VERSION 5.8 ;
BUSBITCHARS "[]" ;
DIVIDERCHAR "/" ;
UNITS
    DATABASE MICRONS 1000 ;
END UNITS

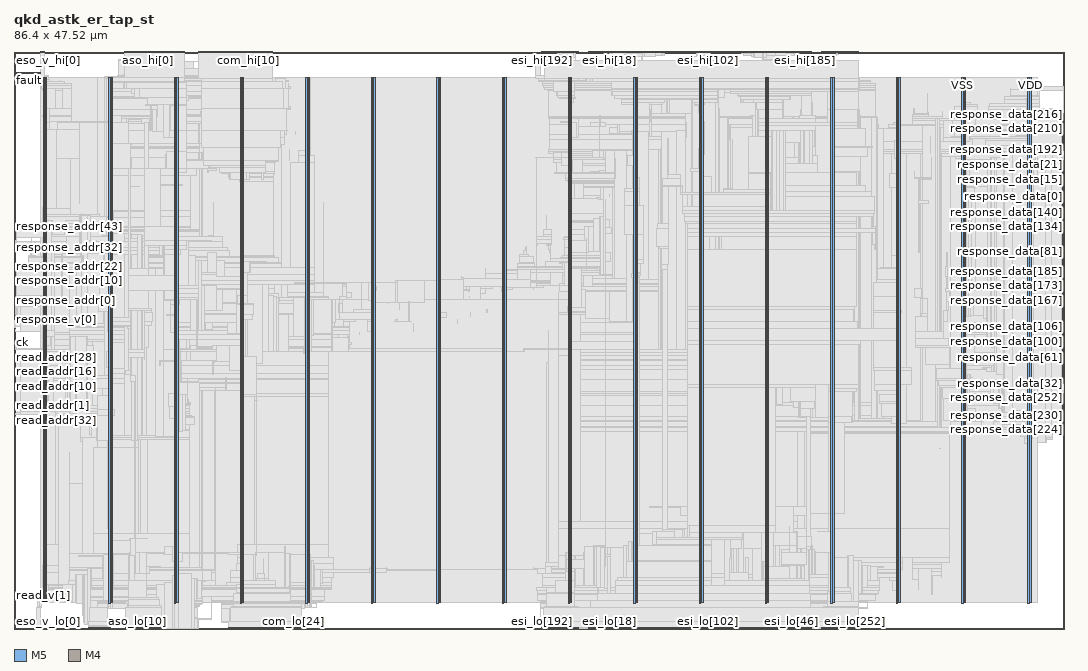
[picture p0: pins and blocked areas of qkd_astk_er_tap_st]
MACRO qkd_astk_er_tap_st
  FOREIGN qkd_astk_er_tap_st 0 0 ;
  CLASS BLOCK ;
  SIZE 86.4 BY 47.52 ;
  PIN aso_hi[0]
    DIRECTION OUTPUT ;
    USE SIGNAL ;
    PORT
      LAYER M5 ;
        RECT  10.992 47.436 11.016 47.52 ;
    END
  END aso_hi[0]
  PIN aso_hi[10]
    DIRECTION OUTPUT ;
    USE SIGNAL ;
    PORT
      LAYER M5 ;
        RECT  11.952 47.436 11.976 47.52 ;
    END
  END aso_hi[10]
  PIN aso_hi[11]
    DIRECTION OUTPUT ;
    USE SIGNAL ;
    PORT
      LAYER M5 ;
        RECT  12.048 47.436 12.072 47.52 ;
    END
  END aso_hi[11]
  PIN aso_hi[12]
    DIRECTION OUTPUT ;
    USE SIGNAL ;
    PORT
      LAYER M5 ;
        RECT  12.144 47.436 12.168 47.52 ;
    END
  END aso_hi[12]
  PIN aso_hi[13]
    DIRECTION OUTPUT ;
    USE SIGNAL ;
    PORT
      LAYER M5 ;
        RECT  12.24 47.436 12.264 47.52 ;
    END
  END aso_hi[13]
  PIN aso_hi[14]
    DIRECTION OUTPUT ;
    USE SIGNAL ;
    PORT
      LAYER M5 ;
        RECT  12.336 47.436 12.36 47.52 ;
    END
  END aso_hi[14]
  PIN aso_hi[15]
    DIRECTION OUTPUT ;
    USE SIGNAL ;
    PORT
      LAYER M5 ;
        RECT  12.432 47.436 12.456 47.52 ;
    END
  END aso_hi[15]
  PIN aso_hi[16]
    DIRECTION OUTPUT ;
    USE SIGNAL ;
    PORT
      LAYER M5 ;
        RECT  12.528 47.436 12.552 47.52 ;
    END
  END aso_hi[16]
  PIN aso_hi[17]
    DIRECTION OUTPUT ;
    USE SIGNAL ;
    PORT
      LAYER M5 ;
        RECT  12.624 47.436 12.648 47.52 ;
    END
  END aso_hi[17]
  PIN aso_hi[18]
    DIRECTION OUTPUT ;
    USE SIGNAL ;
    PORT
      LAYER M5 ;
        RECT  12.72 47.436 12.744 47.52 ;
    END
  END aso_hi[18]
  PIN aso_hi[19]
    DIRECTION OUTPUT ;
    USE SIGNAL ;
    PORT
      LAYER M5 ;
        RECT  12.816 47.436 12.84 47.52 ;
    END
  END aso_hi[19]
  PIN aso_hi[1]
    DIRECTION OUTPUT ;
    USE SIGNAL ;
    PORT
      LAYER M5 ;
        RECT  11.088 47.436 11.112 47.52 ;
    END
  END aso_hi[1]
  PIN aso_hi[20]
    DIRECTION OUTPUT ;
    USE SIGNAL ;
    PORT
      LAYER M5 ;
        RECT  12.912 47.436 12.936 47.52 ;
    END
  END aso_hi[20]
  PIN aso_hi[21]
    DIRECTION OUTPUT ;
    USE SIGNAL ;
    PORT
      LAYER M5 ;
        RECT  13.008 47.436 13.032 47.52 ;
    END
  END aso_hi[21]
  PIN aso_hi[22]
    DIRECTION OUTPUT ;
    USE SIGNAL ;
    PORT
      LAYER M5 ;
        RECT  13.104 47.436 13.128 47.52 ;
    END
  END aso_hi[22]
  PIN aso_hi[23]
    DIRECTION OUTPUT ;
    USE SIGNAL ;
    PORT
      LAYER M5 ;
        RECT  13.2 47.436 13.224 47.52 ;
    END
  END aso_hi[23]
  PIN aso_hi[24]
    DIRECTION OUTPUT ;
    USE SIGNAL ;
    PORT
      LAYER M5 ;
        RECT  13.296 47.436 13.32 47.52 ;
    END
  END aso_hi[24]
  PIN aso_hi[25]
    DIRECTION OUTPUT ;
    USE SIGNAL ;
    PORT
      LAYER M5 ;
        RECT  13.392 47.436 13.416 47.52 ;
    END
  END aso_hi[25]
  PIN aso_hi[26]
    DIRECTION OUTPUT ;
    USE SIGNAL ;
    PORT
      LAYER M5 ;
        RECT  13.488 47.436 13.512 47.52 ;
    END
  END aso_hi[26]
  PIN aso_hi[27]
    DIRECTION OUTPUT ;
    USE SIGNAL ;
    PORT
      LAYER M5 ;
        RECT  13.584 47.436 13.608 47.52 ;
    END
  END aso_hi[27]
  PIN aso_hi[28]
    DIRECTION OUTPUT ;
    USE SIGNAL ;
    PORT
      LAYER M5 ;
        RECT  13.68 47.436 13.704 47.52 ;
    END
  END aso_hi[28]
  PIN aso_hi[29]
    DIRECTION OUTPUT ;
    USE SIGNAL ;
    PORT
      LAYER M5 ;
        RECT  13.776 47.436 13.8 47.52 ;
    END
  END aso_hi[29]
  PIN aso_hi[2]
    DIRECTION OUTPUT ;
    USE SIGNAL ;
    PORT
      LAYER M5 ;
        RECT  11.184 47.436 11.208 47.52 ;
    END
  END aso_hi[2]
  PIN aso_hi[30]
    DIRECTION OUTPUT ;
    USE SIGNAL ;
    PORT
      LAYER M5 ;
        RECT  13.872 47.436 13.896 47.52 ;
    END
  END aso_hi[30]
  PIN aso_hi[31]
    DIRECTION OUTPUT ;
    USE SIGNAL ;
    PORT
      LAYER M5 ;
        RECT  13.968 47.436 13.992 47.52 ;
    END
  END aso_hi[31]
  PIN aso_hi[32]
    DIRECTION OUTPUT ;
    USE SIGNAL ;
    PORT
      LAYER M5 ;
        RECT  9.072 47.436 9.096 47.52 ;
    END
  END aso_hi[32]
  PIN aso_hi[33]
    DIRECTION OUTPUT ;
    USE SIGNAL ;
    PORT
      LAYER M5 ;
        RECT  9.168 47.436 9.192 47.52 ;
    END
  END aso_hi[33]
  PIN aso_hi[34]
    DIRECTION OUTPUT ;
    USE SIGNAL ;
    PORT
      LAYER M5 ;
        RECT  9.264 47.436 9.288 47.52 ;
    END
  END aso_hi[34]
  PIN aso_hi[35]
    DIRECTION OUTPUT ;
    USE SIGNAL ;
    PORT
      LAYER M5 ;
        RECT  9.36 47.436 9.384 47.52 ;
    END
  END aso_hi[35]
  PIN aso_hi[36]
    DIRECTION OUTPUT ;
    USE SIGNAL ;
    PORT
      LAYER M5 ;
        RECT  9.456 47.436 9.48 47.52 ;
    END
  END aso_hi[36]
  PIN aso_hi[37]
    DIRECTION OUTPUT ;
    USE SIGNAL ;
    PORT
      LAYER M5 ;
        RECT  9.552 47.436 9.576 47.52 ;
    END
  END aso_hi[37]
  PIN aso_hi[38]
    DIRECTION OUTPUT ;
    USE SIGNAL ;
    PORT
      LAYER M5 ;
        RECT  9.648 47.436 9.672 47.52 ;
    END
  END aso_hi[38]
  PIN aso_hi[39]
    DIRECTION OUTPUT ;
    USE SIGNAL ;
    PORT
      LAYER M5 ;
        RECT  9.744 47.436 9.768 47.52 ;
    END
  END aso_hi[39]
  PIN aso_hi[3]
    DIRECTION OUTPUT ;
    USE SIGNAL ;
    PORT
      LAYER M5 ;
        RECT  11.28 47.436 11.304 47.52 ;
    END
  END aso_hi[3]
  PIN aso_hi[40]
    DIRECTION OUTPUT ;
    USE SIGNAL ;
    PORT
      LAYER M5 ;
        RECT  9.84 47.436 9.864 47.52 ;
    END
  END aso_hi[40]
  PIN aso_hi[41]
    DIRECTION OUTPUT ;
    USE SIGNAL ;
    PORT
      LAYER M5 ;
        RECT  9.936 47.436 9.96 47.52 ;
    END
  END aso_hi[41]
  PIN aso_hi[42]
    DIRECTION OUTPUT ;
    USE SIGNAL ;
    PORT
      LAYER M5 ;
        RECT  10.032 47.436 10.056 47.52 ;
    END
  END aso_hi[42]
  PIN aso_hi[43]
    DIRECTION OUTPUT ;
    USE SIGNAL ;
    PORT
      LAYER M5 ;
        RECT  10.128 47.436 10.152 47.52 ;
    END
  END aso_hi[43]
  PIN aso_hi[44]
    DIRECTION OUTPUT ;
    USE SIGNAL ;
    PORT
      LAYER M5 ;
        RECT  10.224 47.436 10.248 47.52 ;
    END
  END aso_hi[44]
  PIN aso_hi[45]
    DIRECTION OUTPUT ;
    USE SIGNAL ;
    PORT
      LAYER M5 ;
        RECT  10.32 47.436 10.344 47.52 ;
    END
  END aso_hi[45]
  PIN aso_hi[46]
    DIRECTION OUTPUT ;
    USE SIGNAL ;
    PORT
      LAYER M5 ;
        RECT  10.416 47.436 10.44 47.52 ;
    END
  END aso_hi[46]
  PIN aso_hi[47]
    DIRECTION OUTPUT ;
    USE SIGNAL ;
    PORT
      LAYER M5 ;
        RECT  10.512 47.436 10.536 47.52 ;
    END
  END aso_hi[47]
  PIN aso_hi[48]
    DIRECTION OUTPUT ;
    USE SIGNAL ;
    PORT
      LAYER M5 ;
        RECT  10.608 47.436 10.632 47.52 ;
    END
  END aso_hi[48]
  PIN aso_hi[49]
    DIRECTION OUTPUT ;
    USE SIGNAL ;
    PORT
      LAYER M5 ;
        RECT  10.704 47.436 10.728 47.52 ;
    END
  END aso_hi[49]
  PIN aso_hi[4]
    DIRECTION OUTPUT ;
    USE SIGNAL ;
    PORT
      LAYER M5 ;
        RECT  11.376 47.436 11.4 47.52 ;
    END
  END aso_hi[4]
  PIN aso_hi[50]
    DIRECTION OUTPUT ;
    USE SIGNAL ;
    PORT
      LAYER M5 ;
        RECT  10.8 47.436 10.824 47.52 ;
    END
  END aso_hi[50]
  PIN aso_hi[51]
    DIRECTION OUTPUT ;
    USE SIGNAL ;
    PORT
      LAYER M5 ;
        RECT  10.896 47.436 10.92 47.52 ;
    END
  END aso_hi[51]
  PIN aso_hi[5]
    DIRECTION OUTPUT ;
    USE SIGNAL ;
    PORT
      LAYER M5 ;
        RECT  11.472 47.436 11.496 47.52 ;
    END
  END aso_hi[5]
  PIN aso_hi[6]
    DIRECTION OUTPUT ;
    USE SIGNAL ;
    PORT
      LAYER M5 ;
        RECT  11.568 47.436 11.592 47.52 ;
    END
  END aso_hi[6]
  PIN aso_hi[7]
    DIRECTION OUTPUT ;
    USE SIGNAL ;
    PORT
      LAYER M5 ;
        RECT  11.664 47.436 11.688 47.52 ;
    END
  END aso_hi[7]
  PIN aso_hi[8]
    DIRECTION OUTPUT ;
    USE SIGNAL ;
    PORT
      LAYER M5 ;
        RECT  11.76 47.436 11.784 47.52 ;
    END
  END aso_hi[8]
  PIN aso_hi[9]
    DIRECTION OUTPUT ;
    USE SIGNAL ;
    PORT
      LAYER M5 ;
        RECT  11.856 47.436 11.88 47.52 ;
    END
  END aso_hi[9]
  PIN aso_lo[0]
    DIRECTION OUTPUT ;
    USE SIGNAL ;
    PORT
      LAYER M5 ;
        RECT  9.168 0 9.192 0.084 ;
    END
  END aso_lo[0]
  PIN aso_lo[10]
    DIRECTION OUTPUT ;
    USE SIGNAL ;
    PORT
      LAYER M5 ;
        RECT  10.128 0 10.152 0.084 ;
    END
  END aso_lo[10]
  PIN aso_lo[11]
    DIRECTION OUTPUT ;
    USE SIGNAL ;
    PORT
      LAYER M5 ;
        RECT  10.224 0 10.248 0.084 ;
    END
  END aso_lo[11]
  PIN aso_lo[12]
    DIRECTION OUTPUT ;
    USE SIGNAL ;
    PORT
      LAYER M5 ;
        RECT  10.32 0 10.344 0.084 ;
    END
  END aso_lo[12]
  PIN aso_lo[13]
    DIRECTION OUTPUT ;
    USE SIGNAL ;
    PORT
      LAYER M5 ;
        RECT  10.416 0 10.44 0.084 ;
    END
  END aso_lo[13]
  PIN aso_lo[14]
    DIRECTION OUTPUT ;
    USE SIGNAL ;
    PORT
      LAYER M5 ;
        RECT  10.512 0 10.536 0.084 ;
    END
  END aso_lo[14]
  PIN aso_lo[15]
    DIRECTION OUTPUT ;
    USE SIGNAL ;
    PORT
      LAYER M5 ;
        RECT  10.608 0 10.632 0.084 ;
    END
  END aso_lo[15]
  PIN aso_lo[16]
    DIRECTION OUTPUT ;
    USE SIGNAL ;
    PORT
      LAYER M5 ;
        RECT  10.704 0 10.728 0.084 ;
    END
  END aso_lo[16]
  PIN aso_lo[17]
    DIRECTION OUTPUT ;
    USE SIGNAL ;
    PORT
      LAYER M5 ;
        RECT  10.8 0 10.824 0.084 ;
    END
  END aso_lo[17]
  PIN aso_lo[18]
    DIRECTION OUTPUT ;
    USE SIGNAL ;
    PORT
      LAYER M5 ;
        RECT  10.896 0 10.92 0.084 ;
    END
  END aso_lo[18]
  PIN aso_lo[19]
    DIRECTION OUTPUT ;
    USE SIGNAL ;
    PORT
      LAYER M5 ;
        RECT  10.992 0 11.016 0.084 ;
    END
  END aso_lo[19]
  PIN aso_lo[1]
    DIRECTION OUTPUT ;
    USE SIGNAL ;
    PORT
      LAYER M5 ;
        RECT  9.264 0 9.288 0.084 ;
    END
  END aso_lo[1]
  PIN aso_lo[20]
    DIRECTION OUTPUT ;
    USE SIGNAL ;
    PORT
      LAYER M5 ;
        RECT  11.088 0 11.112 0.084 ;
    END
  END aso_lo[20]
  PIN aso_lo[21]
    DIRECTION OUTPUT ;
    USE SIGNAL ;
    PORT
      LAYER M5 ;
        RECT  11.184 0 11.208 0.084 ;
    END
  END aso_lo[21]
  PIN aso_lo[22]
    DIRECTION OUTPUT ;
    USE SIGNAL ;
    PORT
      LAYER M5 ;
        RECT  11.28 0 11.304 0.084 ;
    END
  END aso_lo[22]
  PIN aso_lo[23]
    DIRECTION OUTPUT ;
    USE SIGNAL ;
    PORT
      LAYER M5 ;
        RECT  11.376 0 11.4 0.084 ;
    END
  END aso_lo[23]
  PIN aso_lo[24]
    DIRECTION OUTPUT ;
    USE SIGNAL ;
    PORT
      LAYER M5 ;
        RECT  11.472 0 11.496 0.084 ;
    END
  END aso_lo[24]
  PIN aso_lo[25]
    DIRECTION OUTPUT ;
    USE SIGNAL ;
    PORT
      LAYER M5 ;
        RECT  11.568 0 11.592 0.084 ;
    END
  END aso_lo[25]
  PIN aso_lo[26]
    DIRECTION OUTPUT ;
    USE SIGNAL ;
    PORT
      LAYER M5 ;
        RECT  11.664 0 11.688 0.084 ;
    END
  END aso_lo[26]
  PIN aso_lo[27]
    DIRECTION OUTPUT ;
    USE SIGNAL ;
    PORT
      LAYER M5 ;
        RECT  11.76 0 11.784 0.084 ;
    END
  END aso_lo[27]
  PIN aso_lo[28]
    DIRECTION OUTPUT ;
    USE SIGNAL ;
    PORT
      LAYER M5 ;
        RECT  11.856 0 11.88 0.084 ;
    END
  END aso_lo[28]
  PIN aso_lo[29]
    DIRECTION OUTPUT ;
    USE SIGNAL ;
    PORT
      LAYER M5 ;
        RECT  11.952 0 11.976 0.084 ;
    END
  END aso_lo[29]
  PIN aso_lo[2]
    DIRECTION OUTPUT ;
    USE SIGNAL ;
    PORT
      LAYER M5 ;
        RECT  9.36 0 9.384 0.084 ;
    END
  END aso_lo[2]
  PIN aso_lo[30]
    DIRECTION OUTPUT ;
    USE SIGNAL ;
    PORT
      LAYER M5 ;
        RECT  12.048 0 12.072 0.084 ;
    END
  END aso_lo[30]
  PIN aso_lo[31]
    DIRECTION OUTPUT ;
    USE SIGNAL ;
    PORT
      LAYER M5 ;
        RECT  12.144 0 12.168 0.084 ;
    END
  END aso_lo[31]
  PIN aso_lo[32]
    DIRECTION OUTPUT ;
    USE SIGNAL ;
    PORT
      LAYER M5 ;
        RECT  6.096 0 6.12 0.084 ;
    END
  END aso_lo[32]
  PIN aso_lo[33]
    DIRECTION OUTPUT ;
    USE SIGNAL ;
    PORT
      LAYER M5 ;
        RECT  6.192 0 6.216 0.084 ;
    END
  END aso_lo[33]
  PIN aso_lo[34]
    DIRECTION OUTPUT ;
    USE SIGNAL ;
    PORT
      LAYER M5 ;
        RECT  6.288 0 6.312 0.084 ;
    END
  END aso_lo[34]
  PIN aso_lo[35]
    DIRECTION OUTPUT ;
    USE SIGNAL ;
    PORT
      LAYER M5 ;
        RECT  6.384 0 6.408 0.084 ;
    END
  END aso_lo[35]
  PIN aso_lo[36]
    DIRECTION OUTPUT ;
    USE SIGNAL ;
    PORT
      LAYER M5 ;
        RECT  6.48 0 6.504 0.084 ;
    END
  END aso_lo[36]
  PIN aso_lo[37]
    DIRECTION OUTPUT ;
    USE SIGNAL ;
    PORT
      LAYER M5 ;
        RECT  6.576 0 6.6 0.084 ;
    END
  END aso_lo[37]
  PIN aso_lo[38]
    DIRECTION OUTPUT ;
    USE SIGNAL ;
    PORT
      LAYER M5 ;
        RECT  6.672 0 6.696 0.084 ;
    END
  END aso_lo[38]
  PIN aso_lo[39]
    DIRECTION OUTPUT ;
    USE SIGNAL ;
    PORT
      LAYER M5 ;
        RECT  6.768 0 6.792 0.084 ;
    END
  END aso_lo[39]
  PIN aso_lo[3]
    DIRECTION OUTPUT ;
    USE SIGNAL ;
    PORT
      LAYER M5 ;
        RECT  9.456 0 9.48 0.084 ;
    END
  END aso_lo[3]
  PIN aso_lo[40]
    DIRECTION OUTPUT ;
    USE SIGNAL ;
    PORT
      LAYER M5 ;
        RECT  6.864 0 6.888 0.084 ;
    END
  END aso_lo[40]
  PIN aso_lo[41]
    DIRECTION OUTPUT ;
    USE SIGNAL ;
    PORT
      LAYER M5 ;
        RECT  6.96 0 6.984 0.084 ;
    END
  END aso_lo[41]
  PIN aso_lo[42]
    DIRECTION OUTPUT ;
    USE SIGNAL ;
    PORT
      LAYER M5 ;
        RECT  7.056 0 7.08 0.084 ;
    END
  END aso_lo[42]
  PIN aso_lo[43]
    DIRECTION OUTPUT ;
    USE SIGNAL ;
    PORT
      LAYER M5 ;
        RECT  7.152 0 7.176 0.084 ;
    END
  END aso_lo[43]
  PIN aso_lo[44]
    DIRECTION OUTPUT ;
    USE SIGNAL ;
    PORT
      LAYER M5 ;
        RECT  7.248 0 7.272 0.084 ;
    END
  END aso_lo[44]
  PIN aso_lo[45]
    DIRECTION OUTPUT ;
    USE SIGNAL ;
    PORT
      LAYER M5 ;
        RECT  7.344 0 7.368 0.084 ;
    END
  END aso_lo[45]
  PIN aso_lo[46]
    DIRECTION OUTPUT ;
    USE SIGNAL ;
    PORT
      LAYER M5 ;
        RECT  7.44 0 7.464 0.084 ;
    END
  END aso_lo[46]
  PIN aso_lo[47]
    DIRECTION OUTPUT ;
    USE SIGNAL ;
    PORT
      LAYER M5 ;
        RECT  7.536 0 7.56 0.084 ;
    END
  END aso_lo[47]
  PIN aso_lo[48]
    DIRECTION OUTPUT ;
    USE SIGNAL ;
    PORT
      LAYER M5 ;
        RECT  7.632 0 7.656 0.084 ;
    END
  END aso_lo[48]
  PIN aso_lo[49]
    DIRECTION OUTPUT ;
    USE SIGNAL ;
    PORT
      LAYER M5 ;
        RECT  7.728 0 7.752 0.084 ;
    END
  END aso_lo[49]
  PIN aso_lo[4]
    DIRECTION OUTPUT ;
    USE SIGNAL ;
    PORT
      LAYER M5 ;
        RECT  9.552 0 9.576 0.084 ;
    END
  END aso_lo[4]
  PIN aso_lo[50]
    DIRECTION OUTPUT ;
    USE SIGNAL ;
    PORT
      LAYER M5 ;
        RECT  7.824 0 7.848 0.084 ;
    END
  END aso_lo[50]
  PIN aso_lo[51]
    DIRECTION OUTPUT ;
    USE SIGNAL ;
    PORT
      LAYER M5 ;
        RECT  7.92 0 7.944 0.084 ;
    END
  END aso_lo[51]
  PIN aso_lo[5]
    DIRECTION OUTPUT ;
    USE SIGNAL ;
    PORT
      LAYER M5 ;
        RECT  9.648 0 9.672 0.084 ;
    END
  END aso_lo[5]
  PIN aso_lo[6]
    DIRECTION OUTPUT ;
    USE SIGNAL ;
    PORT
      LAYER M5 ;
        RECT  9.744 0 9.768 0.084 ;
    END
  END aso_lo[6]
  PIN aso_lo[7]
    DIRECTION OUTPUT ;
    USE SIGNAL ;
    PORT
      LAYER M5 ;
        RECT  9.84 0 9.864 0.084 ;
    END
  END aso_lo[7]
  PIN aso_lo[8]
    DIRECTION OUTPUT ;
    USE SIGNAL ;
    PORT
      LAYER M5 ;
        RECT  9.936 0 9.96 0.084 ;
    END
  END aso_lo[8]
  PIN aso_lo[9]
    DIRECTION OUTPUT ;
    USE SIGNAL ;
    PORT
      LAYER M5 ;
        RECT  10.032 0 10.056 0.084 ;
    END
  END aso_lo[9]
  PIN ck
    DIRECTION INPUT ;
    USE SIGNAL ;
    PORT
      LAYER M4 ;
        RECT  0 23.568 0.084 23.592 ;
    END
    PORT
      LAYER M4 ;
        RECT  0.06 23.568 0.133 23.592 ;
    END
  END ck
  PIN com_hi[0]
    DIRECTION INPUT ;
    USE SIGNAL ;
    PORT
      LAYER M5 ;
        RECT  18.288 47.436 18.312 47.52 ;
    END
  END com_hi[0]
  PIN com_hi[10]
    DIRECTION INPUT ;
    USE SIGNAL ;
    PORT
      LAYER M5 ;
        RECT  19.248 47.436 19.272 47.52 ;
    END
  END com_hi[10]
  PIN com_hi[11]
    DIRECTION INPUT ;
    USE SIGNAL ;
    PORT
      LAYER M5 ;
        RECT  19.344 47.436 19.368 47.52 ;
    END
  END com_hi[11]
  PIN com_hi[12]
    DIRECTION INPUT ;
    USE SIGNAL ;
    PORT
      LAYER M5 ;
        RECT  19.44 47.436 19.464 47.52 ;
    END
  END com_hi[12]
  PIN com_hi[13]
    DIRECTION INPUT ;
    USE SIGNAL ;
    PORT
      LAYER M5 ;
        RECT  19.536 47.436 19.56 47.52 ;
    END
  END com_hi[13]
  PIN com_hi[14]
    DIRECTION INPUT ;
    USE SIGNAL ;
    PORT
      LAYER M5 ;
        RECT  19.632 47.436 19.656 47.52 ;
    END
  END com_hi[14]
  PIN com_hi[15]
    DIRECTION INPUT ;
    USE SIGNAL ;
    PORT
      LAYER M5 ;
        RECT  19.728 47.436 19.752 47.52 ;
    END
  END com_hi[15]
  PIN com_hi[16]
    DIRECTION INPUT ;
    USE SIGNAL ;
    PORT
      LAYER M5 ;
        RECT  19.824 47.436 19.848 47.52 ;
    END
  END com_hi[16]
  PIN com_hi[17]
    DIRECTION INPUT ;
    USE SIGNAL ;
    PORT
      LAYER M5 ;
        RECT  19.92 47.436 19.944 47.52 ;
    END
  END com_hi[17]
  PIN com_hi[18]
    DIRECTION INPUT ;
    USE SIGNAL ;
    PORT
      LAYER M5 ;
        RECT  20.016 47.436 20.04 47.52 ;
    END
  END com_hi[18]
  PIN com_hi[19]
    DIRECTION INPUT ;
    USE SIGNAL ;
    PORT
      LAYER M5 ;
        RECT  20.112 47.436 20.136 47.52 ;
    END
  END com_hi[19]
  PIN com_hi[1]
    DIRECTION INPUT ;
    USE SIGNAL ;
    PORT
      LAYER M5 ;
        RECT  18.384 47.436 18.408 47.52 ;
    END
  END com_hi[1]
  PIN com_hi[20]
    DIRECTION INPUT ;
    USE SIGNAL ;
    PORT
      LAYER M5 ;
        RECT  20.208 47.436 20.232 47.52 ;
    END
  END com_hi[20]
  PIN com_hi[21]
    DIRECTION INPUT ;
    USE SIGNAL ;
    PORT
      LAYER M5 ;
        RECT  20.304 47.436 20.328 47.52 ;
    END
  END com_hi[21]
  PIN com_hi[22]
    DIRECTION INPUT ;
    USE SIGNAL ;
    PORT
      LAYER M5 ;
        RECT  20.4 47.436 20.424 47.52 ;
    END
  END com_hi[22]
  PIN com_hi[23]
    DIRECTION INPUT ;
    USE SIGNAL ;
    PORT
      LAYER M5 ;
        RECT  20.496 47.436 20.52 47.52 ;
    END
  END com_hi[23]
  PIN com_hi[24]
    DIRECTION INPUT ;
    USE SIGNAL ;
    PORT
      LAYER M5 ;
        RECT  20.592 47.436 20.616 47.52 ;
    END
  END com_hi[24]
  PIN com_hi[25]
    DIRECTION INPUT ;
    USE SIGNAL ;
    PORT
      LAYER M5 ;
        RECT  20.688 47.436 20.712 47.52 ;
    END
  END com_hi[25]
  PIN com_hi[26]
    DIRECTION INPUT ;
    USE SIGNAL ;
    PORT
      LAYER M5 ;
        RECT  20.784 47.436 20.808 47.52 ;
    END
  END com_hi[26]
  PIN com_hi[27]
    DIRECTION INPUT ;
    USE SIGNAL ;
    PORT
      LAYER M5 ;
        RECT  20.88 47.436 20.904 47.52 ;
    END
  END com_hi[27]
  PIN com_hi[28]
    DIRECTION INPUT ;
    USE SIGNAL ;
    PORT
      LAYER M5 ;
        RECT  20.976 47.436 21 47.52 ;
    END
  END com_hi[28]
  PIN com_hi[29]
    DIRECTION INPUT ;
    USE SIGNAL ;
    PORT
      LAYER M5 ;
        RECT  21.072 47.436 21.096 47.52 ;
    END
  END com_hi[29]
  PIN com_hi[2]
    DIRECTION INPUT ;
    USE SIGNAL ;
    PORT
      LAYER M5 ;
        RECT  18.48 47.436 18.504 47.52 ;
    END
  END com_hi[2]
  PIN com_hi[30]
    DIRECTION INPUT ;
    USE SIGNAL ;
    PORT
      LAYER M5 ;
        RECT  21.168 47.436 21.192 47.52 ;
    END
  END com_hi[30]
  PIN com_hi[31]
    DIRECTION INPUT ;
    USE SIGNAL ;
    PORT
      LAYER M5 ;
        RECT  21.264 47.436 21.288 47.52 ;
    END
  END com_hi[31]
  PIN com_hi[32]
    DIRECTION INPUT ;
    USE SIGNAL ;
    PORT
      LAYER M5 ;
        RECT  15.216 47.436 15.24 47.52 ;
    END
  END com_hi[32]
  PIN com_hi[33]
    DIRECTION INPUT ;
    USE SIGNAL ;
    PORT
      LAYER M5 ;
        RECT  15.312 47.436 15.336 47.52 ;
    END
  END com_hi[33]
  PIN com_hi[34]
    DIRECTION INPUT ;
    USE SIGNAL ;
    PORT
      LAYER M5 ;
        RECT  15.408 47.436 15.432 47.52 ;
    END
  END com_hi[34]
  PIN com_hi[35]
    DIRECTION INPUT ;
    USE SIGNAL ;
    PORT
      LAYER M5 ;
        RECT  15.504 47.436 15.528 47.52 ;
    END
  END com_hi[35]
  PIN com_hi[36]
    DIRECTION INPUT ;
    USE SIGNAL ;
    PORT
      LAYER M5 ;
        RECT  15.6 47.436 15.624 47.52 ;
    END
  END com_hi[36]
  PIN com_hi[37]
    DIRECTION INPUT ;
    USE SIGNAL ;
    PORT
      LAYER M5 ;
        RECT  15.696 47.436 15.72 47.52 ;
    END
  END com_hi[37]
  PIN com_hi[38]
    DIRECTION INPUT ;
    USE SIGNAL ;
    PORT
      LAYER M5 ;
        RECT  15.792 47.436 15.816 47.52 ;
    END
  END com_hi[38]
  PIN com_hi[39]
    DIRECTION INPUT ;
    USE SIGNAL ;
    PORT
      LAYER M5 ;
        RECT  15.888 47.436 15.912 47.52 ;
    END
  END com_hi[39]
  PIN com_hi[3]
    DIRECTION INPUT ;
    USE SIGNAL ;
    PORT
      LAYER M5 ;
        RECT  18.576 47.436 18.6 47.52 ;
    END
  END com_hi[3]
  PIN com_hi[40]
    DIRECTION INPUT ;
    USE SIGNAL ;
    PORT
      LAYER M5 ;
        RECT  15.984 47.436 16.008 47.52 ;
    END
  END com_hi[40]
  PIN com_hi[41]
    DIRECTION INPUT ;
    USE SIGNAL ;
    PORT
      LAYER M5 ;
        RECT  16.08 47.436 16.104 47.52 ;
    END
  END com_hi[41]
  PIN com_hi[42]
    DIRECTION INPUT ;
    USE SIGNAL ;
    PORT
      LAYER M5 ;
        RECT  16.176 47.436 16.2 47.52 ;
    END
  END com_hi[42]
  PIN com_hi[43]
    DIRECTION INPUT ;
    USE SIGNAL ;
    PORT
      LAYER M5 ;
        RECT  16.272 47.436 16.296 47.52 ;
    END
  END com_hi[43]
  PIN com_hi[44]
    DIRECTION INPUT ;
    USE SIGNAL ;
    PORT
      LAYER M5 ;
        RECT  16.368 47.436 16.392 47.52 ;
    END
  END com_hi[44]
  PIN com_hi[45]
    DIRECTION INPUT ;
    USE SIGNAL ;
    PORT
      LAYER M5 ;
        RECT  16.464 47.436 16.488 47.52 ;
    END
  END com_hi[45]
  PIN com_hi[46]
    DIRECTION INPUT ;
    USE SIGNAL ;
    PORT
      LAYER M5 ;
        RECT  16.56 47.436 16.584 47.52 ;
    END
  END com_hi[46]
  PIN com_hi[47]
    DIRECTION INPUT ;
    USE SIGNAL ;
    PORT
      LAYER M5 ;
        RECT  16.656 47.436 16.68 47.52 ;
    END
  END com_hi[47]
  PIN com_hi[48]
    DIRECTION INPUT ;
    USE SIGNAL ;
    PORT
      LAYER M5 ;
        RECT  16.752 47.436 16.776 47.52 ;
    END
  END com_hi[48]
  PIN com_hi[49]
    DIRECTION INPUT ;
    USE SIGNAL ;
    PORT
      LAYER M5 ;
        RECT  16.848 47.436 16.872 47.52 ;
    END
  END com_hi[49]
  PIN com_hi[4]
    DIRECTION INPUT ;
    USE SIGNAL ;
    PORT
      LAYER M5 ;
        RECT  18.672 47.436 18.696 47.52 ;
    END
  END com_hi[4]
  PIN com_hi[50]
    DIRECTION INPUT ;
    USE SIGNAL ;
    PORT
      LAYER M5 ;
        RECT  16.944 47.436 16.968 47.52 ;
    END
  END com_hi[50]
  PIN com_hi[51]
    DIRECTION INPUT ;
    USE SIGNAL ;
    PORT
      LAYER M5 ;
        RECT  17.04 47.436 17.064 47.52 ;
    END
  END com_hi[51]
  PIN com_hi[52]
    DIRECTION INPUT ;
    USE SIGNAL ;
    PORT
      LAYER M5 ;
        RECT  17.136 47.436 17.16 47.52 ;
    END
  END com_hi[52]
  PIN com_hi[53]
    DIRECTION INPUT ;
    USE SIGNAL ;
    PORT
      LAYER M5 ;
        RECT  17.232 47.436 17.256 47.52 ;
    END
  END com_hi[53]
  PIN com_hi[54]
    DIRECTION INPUT ;
    USE SIGNAL ;
    PORT
      LAYER M5 ;
        RECT  17.328 47.436 17.352 47.52 ;
    END
  END com_hi[54]
  PIN com_hi[55]
    DIRECTION INPUT ;
    USE SIGNAL ;
    PORT
      LAYER M5 ;
        RECT  17.424 47.436 17.448 47.52 ;
    END
  END com_hi[55]
  PIN com_hi[56]
    DIRECTION INPUT ;
    USE SIGNAL ;
    PORT
      LAYER M5 ;
        RECT  17.52 47.436 17.544 47.52 ;
    END
  END com_hi[56]
  PIN com_hi[57]
    DIRECTION INPUT ;
    USE SIGNAL ;
    PORT
      LAYER M5 ;
        RECT  17.616 47.436 17.64 47.52 ;
    END
  END com_hi[57]
  PIN com_hi[58]
    DIRECTION INPUT ;
    USE SIGNAL ;
    PORT
      LAYER M5 ;
        RECT  17.712 47.436 17.736 47.52 ;
    END
  END com_hi[58]
  PIN com_hi[59]
    DIRECTION INPUT ;
    USE SIGNAL ;
    PORT
      LAYER M5 ;
        RECT  17.808 47.436 17.832 47.52 ;
    END
  END com_hi[59]
  PIN com_hi[5]
    DIRECTION INPUT ;
    USE SIGNAL ;
    PORT
      LAYER M5 ;
        RECT  18.768 47.436 18.792 47.52 ;
    END
  END com_hi[5]
  PIN com_hi[60]
    DIRECTION INPUT ;
    USE SIGNAL ;
    PORT
      LAYER M5 ;
        RECT  17.904 47.436 17.928 47.52 ;
    END
  END com_hi[60]
  PIN com_hi[61]
    DIRECTION INPUT ;
    USE SIGNAL ;
    PORT
      LAYER M5 ;
        RECT  18 47.436 18.024 47.52 ;
    END
  END com_hi[61]
  PIN com_hi[62]
    DIRECTION INPUT ;
    USE SIGNAL ;
    PORT
      LAYER M5 ;
        RECT  18.096 47.436 18.12 47.52 ;
    END
  END com_hi[62]
  PIN com_hi[63]
    DIRECTION INPUT ;
    USE SIGNAL ;
    PORT
      LAYER M5 ;
        RECT  18.192 47.436 18.216 47.52 ;
    END
  END com_hi[63]
  PIN com_hi[6]
    DIRECTION INPUT ;
    USE SIGNAL ;
    PORT
      LAYER M5 ;
        RECT  18.864 47.436 18.888 47.52 ;
    END
  END com_hi[6]
  PIN com_hi[7]
    DIRECTION INPUT ;
    USE SIGNAL ;
    PORT
      LAYER M5 ;
        RECT  18.96 47.436 18.984 47.52 ;
    END
  END com_hi[7]
  PIN com_hi[8]
    DIRECTION INPUT ;
    USE SIGNAL ;
    PORT
      LAYER M5 ;
        RECT  19.056 47.436 19.08 47.52 ;
    END
  END com_hi[8]
  PIN com_hi[9]
    DIRECTION INPUT ;
    USE SIGNAL ;
    PORT
      LAYER M5 ;
        RECT  19.152 47.436 19.176 47.52 ;
    END
  END com_hi[9]
  PIN com_lo[0]
    DIRECTION INPUT ;
    USE SIGNAL ;
    PORT
      LAYER M5 ;
        RECT  20.688 0 20.712 0.084 ;
    END
  END com_lo[0]
  PIN com_lo[10]
    DIRECTION INPUT ;
    USE SIGNAL ;
    PORT
      LAYER M5 ;
        RECT  21.648 0 21.672 0.084 ;
    END
  END com_lo[10]
  PIN com_lo[11]
    DIRECTION INPUT ;
    USE SIGNAL ;
    PORT
      LAYER M5 ;
        RECT  21.744 0 21.768 0.084 ;
    END
  END com_lo[11]
  PIN com_lo[12]
    DIRECTION INPUT ;
    USE SIGNAL ;
    PORT
      LAYER M5 ;
        RECT  21.84 0 21.864 0.084 ;
    END
  END com_lo[12]
  PIN com_lo[13]
    DIRECTION INPUT ;
    USE SIGNAL ;
    PORT
      LAYER M5 ;
        RECT  21.936 0 21.96 0.084 ;
    END
  END com_lo[13]
  PIN com_lo[14]
    DIRECTION INPUT ;
    USE SIGNAL ;
    PORT
      LAYER M5 ;
        RECT  22.032 0 22.056 0.084 ;
    END
  END com_lo[14]
  PIN com_lo[15]
    DIRECTION INPUT ;
    USE SIGNAL ;
    PORT
      LAYER M5 ;
        RECT  22.128 0 22.152 0.084 ;
    END
  END com_lo[15]
  PIN com_lo[16]
    DIRECTION INPUT ;
    USE SIGNAL ;
    PORT
      LAYER M5 ;
        RECT  22.224 0 22.248 0.084 ;
    END
  END com_lo[16]
  PIN com_lo[17]
    DIRECTION INPUT ;
    USE SIGNAL ;
    PORT
      LAYER M5 ;
        RECT  22.32 0 22.344 0.084 ;
    END
  END com_lo[17]
  PIN com_lo[18]
    DIRECTION INPUT ;
    USE SIGNAL ;
    PORT
      LAYER M5 ;
        RECT  22.416 0 22.44 0.084 ;
    END
  END com_lo[18]
  PIN com_lo[19]
    DIRECTION INPUT ;
    USE SIGNAL ;
    PORT
      LAYER M5 ;
        RECT  22.512 0 22.536 0.084 ;
    END
  END com_lo[19]
  PIN com_lo[1]
    DIRECTION INPUT ;
    USE SIGNAL ;
    PORT
      LAYER M5 ;
        RECT  20.784 0 20.808 0.084 ;
    END
  END com_lo[1]
  PIN com_lo[20]
    DIRECTION INPUT ;
    USE SIGNAL ;
    PORT
      LAYER M5 ;
        RECT  22.608 0 22.632 0.084 ;
    END
  END com_lo[20]
  PIN com_lo[21]
    DIRECTION INPUT ;
    USE SIGNAL ;
    PORT
      LAYER M5 ;
        RECT  22.704 0 22.728 0.084 ;
    END
  END com_lo[21]
  PIN com_lo[22]
    DIRECTION INPUT ;
    USE SIGNAL ;
    PORT
      LAYER M5 ;
        RECT  22.8 0 22.824 0.084 ;
    END
  END com_lo[22]
  PIN com_lo[23]
    DIRECTION INPUT ;
    USE SIGNAL ;
    PORT
      LAYER M5 ;
        RECT  22.896 0 22.92 0.084 ;
    END
  END com_lo[23]
  PIN com_lo[24]
    DIRECTION INPUT ;
    USE SIGNAL ;
    PORT
      LAYER M5 ;
        RECT  22.992 0 23.016 0.084 ;
    END
  END com_lo[24]
  PIN com_lo[25]
    DIRECTION INPUT ;
    USE SIGNAL ;
    PORT
      LAYER M5 ;
        RECT  23.088 0 23.112 0.084 ;
    END
  END com_lo[25]
  PIN com_lo[26]
    DIRECTION INPUT ;
    USE SIGNAL ;
    PORT
      LAYER M5 ;
        RECT  23.184 0 23.208 0.084 ;
    END
  END com_lo[26]
  PIN com_lo[27]
    DIRECTION INPUT ;
    USE SIGNAL ;
    PORT
      LAYER M5 ;
        RECT  23.28 0 23.304 0.084 ;
    END
  END com_lo[27]
  PIN com_lo[28]
    DIRECTION INPUT ;
    USE SIGNAL ;
    PORT
      LAYER M5 ;
        RECT  23.376 0 23.4 0.084 ;
    END
  END com_lo[28]
  PIN com_lo[29]
    DIRECTION INPUT ;
    USE SIGNAL ;
    PORT
      LAYER M5 ;
        RECT  23.472 0 23.496 0.084 ;
    END
  END com_lo[29]
  PIN com_lo[2]
    DIRECTION INPUT ;
    USE SIGNAL ;
    PORT
      LAYER M5 ;
        RECT  20.88 0 20.904 0.084 ;
    END
  END com_lo[2]
  PIN com_lo[30]
    DIRECTION INPUT ;
    USE SIGNAL ;
    PORT
      LAYER M5 ;
        RECT  23.568 0 23.592 0.084 ;
    END
  END com_lo[30]
  PIN com_lo[31]
    DIRECTION INPUT ;
    USE SIGNAL ;
    PORT
      LAYER M5 ;
        RECT  23.664 0 23.688 0.084 ;
    END
  END com_lo[31]
  PIN com_lo[32]
    DIRECTION INPUT ;
    USE SIGNAL ;
    PORT
      LAYER M5 ;
        RECT  17.616 0 17.64 0.084 ;
    END
  END com_lo[32]
  PIN com_lo[33]
    DIRECTION INPUT ;
    USE SIGNAL ;
    PORT
      LAYER M5 ;
        RECT  17.712 0 17.736 0.084 ;
    END
  END com_lo[33]
  PIN com_lo[34]
    DIRECTION INPUT ;
    USE SIGNAL ;
    PORT
      LAYER M5 ;
        RECT  17.808 0 17.832 0.084 ;
    END
  END com_lo[34]
  PIN com_lo[35]
    DIRECTION INPUT ;
    USE SIGNAL ;
    PORT
      LAYER M5 ;
        RECT  17.904 0 17.928 0.084 ;
    END
  END com_lo[35]
  PIN com_lo[36]
    DIRECTION INPUT ;
    USE SIGNAL ;
    PORT
      LAYER M5 ;
        RECT  18 0 18.024 0.084 ;
    END
  END com_lo[36]
  PIN com_lo[37]
    DIRECTION INPUT ;
    USE SIGNAL ;
    PORT
      LAYER M5 ;
        RECT  18.096 0 18.12 0.084 ;
    END
  END com_lo[37]
  PIN com_lo[38]
    DIRECTION INPUT ;
    USE SIGNAL ;
    PORT
      LAYER M5 ;
        RECT  18.192 0 18.216 0.084 ;
    END
  END com_lo[38]
  PIN com_lo[39]
    DIRECTION INPUT ;
    USE SIGNAL ;
    PORT
      LAYER M5 ;
        RECT  18.288 0 18.312 0.084 ;
    END
  END com_lo[39]
  PIN com_lo[3]
    DIRECTION INPUT ;
    USE SIGNAL ;
    PORT
      LAYER M5 ;
        RECT  20.976 0 21 0.084 ;
    END
  END com_lo[3]
  PIN com_lo[40]
    DIRECTION INPUT ;
    USE SIGNAL ;
    PORT
      LAYER M5 ;
        RECT  18.384 0 18.408 0.084 ;
    END
  END com_lo[40]
  PIN com_lo[41]
    DIRECTION INPUT ;
    USE SIGNAL ;
    PORT
      LAYER M5 ;
        RECT  18.48 0 18.504 0.084 ;
    END
  END com_lo[41]
  PIN com_lo[42]
    DIRECTION INPUT ;
    USE SIGNAL ;
    PORT
      LAYER M5 ;
        RECT  18.576 0 18.6 0.084 ;
    END
  END com_lo[42]
  PIN com_lo[43]
    DIRECTION INPUT ;
    USE SIGNAL ;
    PORT
      LAYER M5 ;
        RECT  18.672 0 18.696 0.084 ;
    END
  END com_lo[43]
  PIN com_lo[44]
    DIRECTION INPUT ;
    USE SIGNAL ;
    PORT
      LAYER M5 ;
        RECT  18.768 0 18.792 0.084 ;
    END
  END com_lo[44]
  PIN com_lo[45]
    DIRECTION INPUT ;
    USE SIGNAL ;
    PORT
      LAYER M5 ;
        RECT  18.864 0 18.888 0.084 ;
    END
  END com_lo[45]
  PIN com_lo[46]
    DIRECTION INPUT ;
    USE SIGNAL ;
    PORT
      LAYER M5 ;
        RECT  18.96 0 18.984 0.084 ;
    END
  END com_lo[46]
  PIN com_lo[47]
    DIRECTION INPUT ;
    USE SIGNAL ;
    PORT
      LAYER M5 ;
        RECT  19.056 0 19.08 0.084 ;
    END
  END com_lo[47]
  PIN com_lo[48]
    DIRECTION INPUT ;
    USE SIGNAL ;
    PORT
      LAYER M5 ;
        RECT  19.152 0 19.176 0.084 ;
    END
  END com_lo[48]
  PIN com_lo[49]
    DIRECTION INPUT ;
    USE SIGNAL ;
    PORT
      LAYER M5 ;
        RECT  19.248 0 19.272 0.084 ;
    END
  END com_lo[49]
  PIN com_lo[4]
    DIRECTION INPUT ;
    USE SIGNAL ;
    PORT
      LAYER M5 ;
        RECT  21.072 0 21.096 0.084 ;
    END
  END com_lo[4]
  PIN com_lo[50]
    DIRECTION INPUT ;
    USE SIGNAL ;
    PORT
      LAYER M5 ;
        RECT  19.344 0 19.368 0.084 ;
    END
  END com_lo[50]
  PIN com_lo[51]
    DIRECTION INPUT ;
    USE SIGNAL ;
    PORT
      LAYER M5 ;
        RECT  19.44 0 19.464 0.084 ;
    END
  END com_lo[51]
  PIN com_lo[52]
    DIRECTION INPUT ;
    USE SIGNAL ;
    PORT
      LAYER M5 ;
        RECT  19.536 0 19.56 0.084 ;
    END
  END com_lo[52]
  PIN com_lo[53]
    DIRECTION INPUT ;
    USE SIGNAL ;
    PORT
      LAYER M5 ;
        RECT  19.632 0 19.656 0.084 ;
    END
  END com_lo[53]
  PIN com_lo[54]
    DIRECTION INPUT ;
    USE SIGNAL ;
    PORT
      LAYER M5 ;
        RECT  19.728 0 19.752 0.084 ;
    END
  END com_lo[54]
  PIN com_lo[55]
    DIRECTION INPUT ;
    USE SIGNAL ;
    PORT
      LAYER M5 ;
        RECT  19.824 0 19.848 0.084 ;
    END
  END com_lo[55]
  PIN com_lo[56]
    DIRECTION INPUT ;
    USE SIGNAL ;
    PORT
      LAYER M5 ;
        RECT  19.92 0 19.944 0.084 ;
    END
  END com_lo[56]
  PIN com_lo[57]
    DIRECTION INPUT ;
    USE SIGNAL ;
    PORT
      LAYER M5 ;
        RECT  20.016 0 20.04 0.084 ;
    END
  END com_lo[57]
  PIN com_lo[58]
    DIRECTION INPUT ;
    USE SIGNAL ;
    PORT
      LAYER M5 ;
        RECT  20.112 0 20.136 0.084 ;
    END
  END com_lo[58]
  PIN com_lo[59]
    DIRECTION INPUT ;
    USE SIGNAL ;
    PORT
      LAYER M5 ;
        RECT  20.208 0 20.232 0.084 ;
    END
  END com_lo[59]
  PIN com_lo[5]
    DIRECTION INPUT ;
    USE SIGNAL ;
    PORT
      LAYER M5 ;
        RECT  21.168 0 21.192 0.084 ;
    END
  END com_lo[5]
  PIN com_lo[60]
    DIRECTION INPUT ;
    USE SIGNAL ;
    PORT
      LAYER M5 ;
        RECT  20.304 0 20.328 0.084 ;
    END
  END com_lo[60]
  PIN com_lo[61]
    DIRECTION INPUT ;
    USE SIGNAL ;
    PORT
      LAYER M5 ;
        RECT  20.4 0 20.424 0.084 ;
    END
  END com_lo[61]
  PIN com_lo[62]
    DIRECTION INPUT ;
    USE SIGNAL ;
    PORT
      LAYER M5 ;
        RECT  20.496 0 20.52 0.084 ;
    END
  END com_lo[62]
  PIN com_lo[63]
    DIRECTION INPUT ;
    USE SIGNAL ;
    PORT
      LAYER M5 ;
        RECT  20.592 0 20.616 0.084 ;
    END
  END com_lo[63]
  PIN com_lo[6]
    DIRECTION INPUT ;
    USE SIGNAL ;
    PORT
      LAYER M5 ;
        RECT  21.264 0 21.288 0.084 ;
    END
  END com_lo[6]
  PIN com_lo[7]
    DIRECTION INPUT ;
    USE SIGNAL ;
    PORT
      LAYER M5 ;
        RECT  21.36 0 21.384 0.084 ;
    END
  END com_lo[7]
  PIN com_lo[8]
    DIRECTION INPUT ;
    USE SIGNAL ;
    PORT
      LAYER M5 ;
        RECT  21.456 0 21.48 0.084 ;
    END
  END com_lo[8]
  PIN com_lo[9]
    DIRECTION INPUT ;
    USE SIGNAL ;
    PORT
      LAYER M5 ;
        RECT  21.552 0 21.576 0.084 ;
    END
  END com_lo[9]
  PIN esi_hi[0]
    DIRECTION INPUT ;
    USE SIGNAL ;
    PORT
      LAYER M5 ;
        RECT  47.28 47.436 47.304 47.52 ;
    END
  END esi_hi[0]
  PIN esi_hi[100]
    DIRECTION INPUT ;
    USE SIGNAL ;
    PORT
      LAYER M5 ;
        RECT  56.88 47.436 56.904 47.52 ;
    END
  END esi_hi[100]
  PIN esi_hi[101]
    DIRECTION INPUT ;
    USE SIGNAL ;
    PORT
      LAYER M5 ;
        RECT  56.976 47.436 57 47.52 ;
    END
  END esi_hi[101]
  PIN esi_hi[102]
    DIRECTION INPUT ;
    USE SIGNAL ;
    PORT
      LAYER M5 ;
        RECT  57.072 47.436 57.096 47.52 ;
    END
  END esi_hi[102]
  PIN esi_hi[103]
    DIRECTION INPUT ;
    USE SIGNAL ;
    PORT
      LAYER M5 ;
        RECT  57.168 47.436 57.192 47.52 ;
    END
  END esi_hi[103]
  PIN esi_hi[104]
    DIRECTION INPUT ;
    USE SIGNAL ;
    PORT
      LAYER M5 ;
        RECT  57.264 47.436 57.288 47.52 ;
    END
  END esi_hi[104]
  PIN esi_hi[105]
    DIRECTION INPUT ;
    USE SIGNAL ;
    PORT
      LAYER M5 ;
        RECT  57.36 47.436 57.384 47.52 ;
    END
  END esi_hi[105]
  PIN esi_hi[106]
    DIRECTION INPUT ;
    USE SIGNAL ;
    PORT
      LAYER M5 ;
        RECT  57.456 47.436 57.48 47.52 ;
    END
  END esi_hi[106]
  PIN esi_hi[107]
    DIRECTION INPUT ;
    USE SIGNAL ;
    PORT
      LAYER M5 ;
        RECT  57.552 47.436 57.576 47.52 ;
    END
  END esi_hi[107]
  PIN esi_hi[108]
    DIRECTION INPUT ;
    USE SIGNAL ;
    PORT
      LAYER M5 ;
        RECT  57.648 47.436 57.672 47.52 ;
    END
  END esi_hi[108]
  PIN esi_hi[109]
    DIRECTION INPUT ;
    USE SIGNAL ;
    PORT
      LAYER M5 ;
        RECT  57.744 47.436 57.768 47.52 ;
    END
  END esi_hi[109]
  PIN esi_hi[10]
    DIRECTION INPUT ;
    USE SIGNAL ;
    PORT
      LAYER M5 ;
        RECT  48.24 47.436 48.264 47.52 ;
    END
  END esi_hi[10]
  PIN esi_hi[110]
    DIRECTION INPUT ;
    USE SIGNAL ;
    PORT
      LAYER M5 ;
        RECT  57.84 47.436 57.864 47.52 ;
    END
  END esi_hi[110]
  PIN esi_hi[111]
    DIRECTION INPUT ;
    USE SIGNAL ;
    PORT
      LAYER M5 ;
        RECT  57.936 47.436 57.96 47.52 ;
    END
  END esi_hi[111]
  PIN esi_hi[112]
    DIRECTION INPUT ;
    USE SIGNAL ;
    PORT
      LAYER M5 ;
        RECT  58.032 47.436 58.056 47.52 ;
    END
  END esi_hi[112]
  PIN esi_hi[113]
    DIRECTION INPUT ;
    USE SIGNAL ;
    PORT
      LAYER M5 ;
        RECT  58.128 47.436 58.152 47.52 ;
    END
  END esi_hi[113]
  PIN esi_hi[114]
    DIRECTION INPUT ;
    USE SIGNAL ;
    PORT
      LAYER M5 ;
        RECT  58.224 47.436 58.248 47.52 ;
    END
  END esi_hi[114]
  PIN esi_hi[115]
    DIRECTION INPUT ;
    USE SIGNAL ;
    PORT
      LAYER M5 ;
        RECT  58.32 47.436 58.344 47.52 ;
    END
  END esi_hi[115]
  PIN esi_hi[116]
    DIRECTION INPUT ;
    USE SIGNAL ;
    PORT
      LAYER M5 ;
        RECT  58.416 47.436 58.44 47.52 ;
    END
  END esi_hi[116]
  PIN esi_hi[117]
    DIRECTION INPUT ;
    USE SIGNAL ;
    PORT
      LAYER M5 ;
        RECT  58.512 47.436 58.536 47.52 ;
    END
  END esi_hi[117]
  PIN esi_hi[118]
    DIRECTION INPUT ;
    USE SIGNAL ;
    PORT
      LAYER M5 ;
        RECT  58.608 47.436 58.632 47.52 ;
    END
  END esi_hi[118]
  PIN esi_hi[119]
    DIRECTION INPUT ;
    USE SIGNAL ;
    PORT
      LAYER M5 ;
        RECT  58.704 47.436 58.728 47.52 ;
    END
  END esi_hi[119]
  PIN esi_hi[11]
    DIRECTION INPUT ;
    USE SIGNAL ;
    PORT
      LAYER M5 ;
        RECT  48.336 47.436 48.36 47.52 ;
    END
  END esi_hi[11]
  PIN esi_hi[120]
    DIRECTION INPUT ;
    USE SIGNAL ;
    PORT
      LAYER M5 ;
        RECT  58.8 47.436 58.824 47.52 ;
    END
  END esi_hi[120]
  PIN esi_hi[121]
    DIRECTION INPUT ;
    USE SIGNAL ;
    PORT
      LAYER M5 ;
        RECT  58.896 47.436 58.92 47.52 ;
    END
  END esi_hi[121]
  PIN esi_hi[122]
    DIRECTION INPUT ;
    USE SIGNAL ;
    PORT
      LAYER M5 ;
        RECT  58.992 47.436 59.016 47.52 ;
    END
  END esi_hi[122]
  PIN esi_hi[123]
    DIRECTION INPUT ;
    USE SIGNAL ;
    PORT
      LAYER M5 ;
        RECT  59.088 47.436 59.112 47.52 ;
    END
  END esi_hi[123]
  PIN esi_hi[124]
    DIRECTION INPUT ;
    USE SIGNAL ;
    PORT
      LAYER M5 ;
        RECT  59.184 47.436 59.208 47.52 ;
    END
  END esi_hi[124]
  PIN esi_hi[125]
    DIRECTION INPUT ;
    USE SIGNAL ;
    PORT
      LAYER M5 ;
        RECT  59.28 47.436 59.304 47.52 ;
    END
  END esi_hi[125]
  PIN esi_hi[126]
    DIRECTION INPUT ;
    USE SIGNAL ;
    PORT
      LAYER M5 ;
        RECT  59.376 47.436 59.4 47.52 ;
    END
  END esi_hi[126]
  PIN esi_hi[127]
    DIRECTION INPUT ;
    USE SIGNAL ;
    PORT
      LAYER M5 ;
        RECT  59.472 47.436 59.496 47.52 ;
    END
  END esi_hi[127]
  PIN esi_hi[128]
    DIRECTION INPUT ;
    USE SIGNAL ;
    PORT
      LAYER M5 ;
        RECT  53.424 47.436 53.448 47.52 ;
    END
  END esi_hi[128]
  PIN esi_hi[129]
    DIRECTION INPUT ;
    USE SIGNAL ;
    PORT
      LAYER M5 ;
        RECT  53.52 47.436 53.544 47.52 ;
    END
  END esi_hi[129]
  PIN esi_hi[12]
    DIRECTION INPUT ;
    USE SIGNAL ;
    PORT
      LAYER M5 ;
        RECT  48.432 47.436 48.456 47.52 ;
    END
  END esi_hi[12]
  PIN esi_hi[130]
    DIRECTION INPUT ;
    USE SIGNAL ;
    PORT
      LAYER M5 ;
        RECT  53.616 47.436 53.64 47.52 ;
    END
  END esi_hi[130]
  PIN esi_hi[131]
    DIRECTION INPUT ;
    USE SIGNAL ;
    PORT
      LAYER M5 ;
        RECT  53.712 47.436 53.736 47.52 ;
    END
  END esi_hi[131]
  PIN esi_hi[132]
    DIRECTION INPUT ;
    USE SIGNAL ;
    PORT
      LAYER M5 ;
        RECT  53.808 47.436 53.832 47.52 ;
    END
  END esi_hi[132]
  PIN esi_hi[133]
    DIRECTION INPUT ;
    USE SIGNAL ;
    PORT
      LAYER M5 ;
        RECT  53.904 47.436 53.928 47.52 ;
    END
  END esi_hi[133]
  PIN esi_hi[134]
    DIRECTION INPUT ;
    USE SIGNAL ;
    PORT
      LAYER M5 ;
        RECT  54 47.436 54.024 47.52 ;
    END
  END esi_hi[134]
  PIN esi_hi[135]
    DIRECTION INPUT ;
    USE SIGNAL ;
    PORT
      LAYER M5 ;
        RECT  54.096 47.436 54.12 47.52 ;
    END
  END esi_hi[135]
  PIN esi_hi[136]
    DIRECTION INPUT ;
    USE SIGNAL ;
    PORT
      LAYER M5 ;
        RECT  54.192 47.436 54.216 47.52 ;
    END
  END esi_hi[136]
  PIN esi_hi[137]
    DIRECTION INPUT ;
    USE SIGNAL ;
    PORT
      LAYER M5 ;
        RECT  54.288 47.436 54.312 47.52 ;
    END
  END esi_hi[137]
  PIN esi_hi[138]
    DIRECTION INPUT ;
    USE SIGNAL ;
    PORT
      LAYER M5 ;
        RECT  54.384 47.436 54.408 47.52 ;
    END
  END esi_hi[138]
  PIN esi_hi[139]
    DIRECTION INPUT ;
    USE SIGNAL ;
    PORT
      LAYER M5 ;
        RECT  54.48 47.436 54.504 47.52 ;
    END
  END esi_hi[139]
  PIN esi_hi[13]
    DIRECTION INPUT ;
    USE SIGNAL ;
    PORT
      LAYER M5 ;
        RECT  48.528 47.436 48.552 47.52 ;
    END
  END esi_hi[13]
  PIN esi_hi[140]
    DIRECTION INPUT ;
    USE SIGNAL ;
    PORT
      LAYER M5 ;
        RECT  54.576 47.436 54.6 47.52 ;
    END
  END esi_hi[140]
  PIN esi_hi[141]
    DIRECTION INPUT ;
    USE SIGNAL ;
    PORT
      LAYER M5 ;
        RECT  54.672 47.436 54.696 47.52 ;
    END
  END esi_hi[141]
  PIN esi_hi[142]
    DIRECTION INPUT ;
    USE SIGNAL ;
    PORT
      LAYER M5 ;
        RECT  54.768 47.436 54.792 47.52 ;
    END
  END esi_hi[142]
  PIN esi_hi[143]
    DIRECTION INPUT ;
    USE SIGNAL ;
    PORT
      LAYER M5 ;
        RECT  54.864 47.436 54.888 47.52 ;
    END
  END esi_hi[143]
  PIN esi_hi[144]
    DIRECTION INPUT ;
    USE SIGNAL ;
    PORT
      LAYER M5 ;
        RECT  54.96 47.436 54.984 47.52 ;
    END
  END esi_hi[144]
  PIN esi_hi[145]
    DIRECTION INPUT ;
    USE SIGNAL ;
    PORT
      LAYER M5 ;
        RECT  55.056 47.436 55.08 47.52 ;
    END
  END esi_hi[145]
  PIN esi_hi[146]
    DIRECTION INPUT ;
    USE SIGNAL ;
    PORT
      LAYER M5 ;
        RECT  55.152 47.436 55.176 47.52 ;
    END
  END esi_hi[146]
  PIN esi_hi[147]
    DIRECTION INPUT ;
    USE SIGNAL ;
    PORT
      LAYER M5 ;
        RECT  55.248 47.436 55.272 47.52 ;
    END
  END esi_hi[147]
  PIN esi_hi[148]
    DIRECTION INPUT ;
    USE SIGNAL ;
    PORT
      LAYER M5 ;
        RECT  55.344 47.436 55.368 47.52 ;
    END
  END esi_hi[148]
  PIN esi_hi[149]
    DIRECTION INPUT ;
    USE SIGNAL ;
    PORT
      LAYER M5 ;
        RECT  55.44 47.436 55.464 47.52 ;
    END
  END esi_hi[149]
  PIN esi_hi[14]
    DIRECTION INPUT ;
    USE SIGNAL ;
    PORT
      LAYER M5 ;
        RECT  48.624 47.436 48.648 47.52 ;
    END
  END esi_hi[14]
  PIN esi_hi[150]
    DIRECTION INPUT ;
    USE SIGNAL ;
    PORT
      LAYER M5 ;
        RECT  55.536 47.436 55.56 47.52 ;
    END
  END esi_hi[150]
  PIN esi_hi[151]
    DIRECTION INPUT ;
    USE SIGNAL ;
    PORT
      LAYER M5 ;
        RECT  55.632 47.436 55.656 47.52 ;
    END
  END esi_hi[151]
  PIN esi_hi[152]
    DIRECTION INPUT ;
    USE SIGNAL ;
    PORT
      LAYER M5 ;
        RECT  55.728 47.436 55.752 47.52 ;
    END
  END esi_hi[152]
  PIN esi_hi[153]
    DIRECTION INPUT ;
    USE SIGNAL ;
    PORT
      LAYER M5 ;
        RECT  55.824 47.436 55.848 47.52 ;
    END
  END esi_hi[153]
  PIN esi_hi[154]
    DIRECTION INPUT ;
    USE SIGNAL ;
    PORT
      LAYER M5 ;
        RECT  55.92 47.436 55.944 47.52 ;
    END
  END esi_hi[154]
  PIN esi_hi[155]
    DIRECTION INPUT ;
    USE SIGNAL ;
    PORT
      LAYER M5 ;
        RECT  56.016 47.436 56.04 47.52 ;
    END
  END esi_hi[155]
  PIN esi_hi[156]
    DIRECTION INPUT ;
    USE SIGNAL ;
    PORT
      LAYER M5 ;
        RECT  56.112 47.436 56.136 47.52 ;
    END
  END esi_hi[156]
  PIN esi_hi[157]
    DIRECTION INPUT ;
    USE SIGNAL ;
    PORT
      LAYER M5 ;
        RECT  56.208 47.436 56.232 47.52 ;
    END
  END esi_hi[157]
  PIN esi_hi[158]
    DIRECTION INPUT ;
    USE SIGNAL ;
    PORT
      LAYER M5 ;
        RECT  56.304 47.436 56.328 47.52 ;
    END
  END esi_hi[158]
  PIN esi_hi[159]
    DIRECTION INPUT ;
    USE SIGNAL ;
    PORT
      LAYER M5 ;
        RECT  56.4 47.436 56.424 47.52 ;
    END
  END esi_hi[159]
  PIN esi_hi[15]
    DIRECTION INPUT ;
    USE SIGNAL ;
    PORT
      LAYER M5 ;
        RECT  48.72 47.436 48.744 47.52 ;
    END
  END esi_hi[15]
  PIN esi_hi[160]
    DIRECTION INPUT ;
    USE SIGNAL ;
    PORT
      LAYER M5 ;
        RECT  62.64 47.436 62.664 47.52 ;
    END
  END esi_hi[160]
  PIN esi_hi[161]
    DIRECTION INPUT ;
    USE SIGNAL ;
    PORT
      LAYER M5 ;
        RECT  62.736 47.436 62.76 47.52 ;
    END
  END esi_hi[161]
  PIN esi_hi[162]
    DIRECTION INPUT ;
    USE SIGNAL ;
    PORT
      LAYER M5 ;
        RECT  62.832 47.436 62.856 47.52 ;
    END
  END esi_hi[162]
  PIN esi_hi[163]
    DIRECTION INPUT ;
    USE SIGNAL ;
    PORT
      LAYER M5 ;
        RECT  62.928 47.436 62.952 47.52 ;
    END
  END esi_hi[163]
  PIN esi_hi[164]
    DIRECTION INPUT ;
    USE SIGNAL ;
    PORT
      LAYER M5 ;
        RECT  63.024 47.436 63.048 47.52 ;
    END
  END esi_hi[164]
  PIN esi_hi[165]
    DIRECTION INPUT ;
    USE SIGNAL ;
    PORT
      LAYER M5 ;
        RECT  63.12 47.436 63.144 47.52 ;
    END
  END esi_hi[165]
  PIN esi_hi[166]
    DIRECTION INPUT ;
    USE SIGNAL ;
    PORT
      LAYER M5 ;
        RECT  63.216 47.436 63.24 47.52 ;
    END
  END esi_hi[166]
  PIN esi_hi[167]
    DIRECTION INPUT ;
    USE SIGNAL ;
    PORT
      LAYER M5 ;
        RECT  63.312 47.436 63.336 47.52 ;
    END
  END esi_hi[167]
  PIN esi_hi[168]
    DIRECTION INPUT ;
    USE SIGNAL ;
    PORT
      LAYER M5 ;
        RECT  63.408 47.436 63.432 47.52 ;
    END
  END esi_hi[168]
  PIN esi_hi[169]
    DIRECTION INPUT ;
    USE SIGNAL ;
    PORT
      LAYER M5 ;
        RECT  63.504 47.436 63.528 47.52 ;
    END
  END esi_hi[169]
  PIN esi_hi[16]
    DIRECTION INPUT ;
    USE SIGNAL ;
    PORT
      LAYER M5 ;
        RECT  48.816 47.436 48.84 47.52 ;
    END
  END esi_hi[16]
  PIN esi_hi[170]
    DIRECTION INPUT ;
    USE SIGNAL ;
    PORT
      LAYER M5 ;
        RECT  63.6 47.436 63.624 47.52 ;
    END
  END esi_hi[170]
  PIN esi_hi[171]
    DIRECTION INPUT ;
    USE SIGNAL ;
    PORT
      LAYER M5 ;
        RECT  63.696 47.436 63.72 47.52 ;
    END
  END esi_hi[171]
  PIN esi_hi[172]
    DIRECTION INPUT ;
    USE SIGNAL ;
    PORT
      LAYER M5 ;
        RECT  63.792 47.436 63.816 47.52 ;
    END
  END esi_hi[172]
  PIN esi_hi[173]
    DIRECTION INPUT ;
    USE SIGNAL ;
    PORT
      LAYER M5 ;
        RECT  63.888 47.436 63.912 47.52 ;
    END
  END esi_hi[173]
  PIN esi_hi[174]
    DIRECTION INPUT ;
    USE SIGNAL ;
    PORT
      LAYER M5 ;
        RECT  63.984 47.436 64.008 47.52 ;
    END
  END esi_hi[174]
  PIN esi_hi[175]
    DIRECTION INPUT ;
    USE SIGNAL ;
    PORT
      LAYER M5 ;
        RECT  64.08 47.436 64.104 47.52 ;
    END
  END esi_hi[175]
  PIN esi_hi[176]
    DIRECTION INPUT ;
    USE SIGNAL ;
    PORT
      LAYER M5 ;
        RECT  64.176 47.436 64.2 47.52 ;
    END
  END esi_hi[176]
  PIN esi_hi[177]
    DIRECTION INPUT ;
    USE SIGNAL ;
    PORT
      LAYER M5 ;
        RECT  64.272 47.436 64.296 47.52 ;
    END
  END esi_hi[177]
  PIN esi_hi[178]
    DIRECTION INPUT ;
    USE SIGNAL ;
    PORT
      LAYER M5 ;
        RECT  64.368 47.436 64.392 47.52 ;
    END
  END esi_hi[178]
  PIN esi_hi[179]
    DIRECTION INPUT ;
    USE SIGNAL ;
    PORT
      LAYER M5 ;
        RECT  64.464 47.436 64.488 47.52 ;
    END
  END esi_hi[179]
  PIN esi_hi[17]
    DIRECTION INPUT ;
    USE SIGNAL ;
    PORT
      LAYER M5 ;
        RECT  48.912 47.436 48.936 47.52 ;
    END
  END esi_hi[17]
  PIN esi_hi[180]
    DIRECTION INPUT ;
    USE SIGNAL ;
    PORT
      LAYER M5 ;
        RECT  64.56 47.436 64.584 47.52 ;
    END
  END esi_hi[180]
  PIN esi_hi[181]
    DIRECTION INPUT ;
    USE SIGNAL ;
    PORT
      LAYER M5 ;
        RECT  64.656 47.436 64.68 47.52 ;
    END
  END esi_hi[181]
  PIN esi_hi[182]
    DIRECTION INPUT ;
    USE SIGNAL ;
    PORT
      LAYER M5 ;
        RECT  64.752 47.436 64.776 47.52 ;
    END
  END esi_hi[182]
  PIN esi_hi[183]
    DIRECTION INPUT ;
    USE SIGNAL ;
    PORT
      LAYER M5 ;
        RECT  64.848 47.436 64.872 47.52 ;
    END
  END esi_hi[183]
  PIN esi_hi[184]
    DIRECTION INPUT ;
    USE SIGNAL ;
    PORT
      LAYER M5 ;
        RECT  64.944 47.436 64.968 47.52 ;
    END
  END esi_hi[184]
  PIN esi_hi[185]
    DIRECTION INPUT ;
    USE SIGNAL ;
    PORT
      LAYER M5 ;
        RECT  65.04 47.436 65.064 47.52 ;
    END
  END esi_hi[185]
  PIN esi_hi[186]
    DIRECTION INPUT ;
    USE SIGNAL ;
    PORT
      LAYER M5 ;
        RECT  65.136 47.436 65.16 47.52 ;
    END
  END esi_hi[186]
  PIN esi_hi[187]
    DIRECTION INPUT ;
    USE SIGNAL ;
    PORT
      LAYER M5 ;
        RECT  65.232 47.436 65.256 47.52 ;
    END
  END esi_hi[187]
  PIN esi_hi[188]
    DIRECTION INPUT ;
    USE SIGNAL ;
    PORT
      LAYER M5 ;
        RECT  65.328 47.436 65.352 47.52 ;
    END
  END esi_hi[188]
  PIN esi_hi[189]
    DIRECTION INPUT ;
    USE SIGNAL ;
    PORT
      LAYER M5 ;
        RECT  65.424 47.436 65.448 47.52 ;
    END
  END esi_hi[189]
  PIN esi_hi[18]
    DIRECTION INPUT ;
    USE SIGNAL ;
    PORT
      LAYER M5 ;
        RECT  49.008 47.436 49.032 47.52 ;
    END
  END esi_hi[18]
  PIN esi_hi[190]
    DIRECTION INPUT ;
    USE SIGNAL ;
    PORT
      LAYER M5 ;
        RECT  65.52 47.436 65.544 47.52 ;
    END
  END esi_hi[190]
  PIN esi_hi[191]
    DIRECTION INPUT ;
    USE SIGNAL ;
    PORT
      LAYER M5 ;
        RECT  65.616 47.436 65.64 47.52 ;
    END
  END esi_hi[191]
  PIN esi_hi[192]
    DIRECTION INPUT ;
    USE SIGNAL ;
    PORT
      LAYER M5 ;
        RECT  43.44 47.436 43.464 47.52 ;
    END
  END esi_hi[192]
  PIN esi_hi[193]
    DIRECTION INPUT ;
    USE SIGNAL ;
    PORT
      LAYER M5 ;
        RECT  43.536 47.436 43.56 47.52 ;
    END
  END esi_hi[193]
  PIN esi_hi[194]
    DIRECTION INPUT ;
    USE SIGNAL ;
    PORT
      LAYER M5 ;
        RECT  43.632 47.436 43.656 47.52 ;
    END
  END esi_hi[194]
  PIN esi_hi[195]
    DIRECTION INPUT ;
    USE SIGNAL ;
    PORT
      LAYER M5 ;
        RECT  43.728 47.436 43.752 47.52 ;
    END
  END esi_hi[195]
  PIN esi_hi[196]
    DIRECTION INPUT ;
    USE SIGNAL ;
    PORT
      LAYER M5 ;
        RECT  43.824 47.436 43.848 47.52 ;
    END
  END esi_hi[196]
  PIN esi_hi[197]
    DIRECTION INPUT ;
    USE SIGNAL ;
    PORT
      LAYER M5 ;
        RECT  43.92 47.436 43.944 47.52 ;
    END
  END esi_hi[197]
  PIN esi_hi[198]
    DIRECTION INPUT ;
    USE SIGNAL ;
    PORT
      LAYER M5 ;
        RECT  44.016 47.436 44.04 47.52 ;
    END
  END esi_hi[198]
  PIN esi_hi[199]
    DIRECTION INPUT ;
    USE SIGNAL ;
    PORT
      LAYER M5 ;
        RECT  44.112 47.436 44.136 47.52 ;
    END
  END esi_hi[199]
  PIN esi_hi[19]
    DIRECTION INPUT ;
    USE SIGNAL ;
    PORT
      LAYER M5 ;
        RECT  49.104 47.436 49.128 47.52 ;
    END
  END esi_hi[19]
  PIN esi_hi[1]
    DIRECTION INPUT ;
    USE SIGNAL ;
    PORT
      LAYER M5 ;
        RECT  47.376 47.436 47.4 47.52 ;
    END
  END esi_hi[1]
  PIN esi_hi[200]
    DIRECTION INPUT ;
    USE SIGNAL ;
    PORT
      LAYER M5 ;
        RECT  44.208 47.436 44.232 47.52 ;
    END
  END esi_hi[200]
  PIN esi_hi[201]
    DIRECTION INPUT ;
    USE SIGNAL ;
    PORT
      LAYER M5 ;
        RECT  44.304 47.436 44.328 47.52 ;
    END
  END esi_hi[201]
  PIN esi_hi[202]
    DIRECTION INPUT ;
    USE SIGNAL ;
    PORT
      LAYER M5 ;
        RECT  44.4 47.436 44.424 47.52 ;
    END
  END esi_hi[202]
  PIN esi_hi[203]
    DIRECTION INPUT ;
    USE SIGNAL ;
    PORT
      LAYER M5 ;
        RECT  44.496 47.436 44.52 47.52 ;
    END
  END esi_hi[203]
  PIN esi_hi[204]
    DIRECTION INPUT ;
    USE SIGNAL ;
    PORT
      LAYER M5 ;
        RECT  44.592 47.436 44.616 47.52 ;
    END
  END esi_hi[204]
  PIN esi_hi[205]
    DIRECTION INPUT ;
    USE SIGNAL ;
    PORT
      LAYER M5 ;
        RECT  44.688 47.436 44.712 47.52 ;
    END
  END esi_hi[205]
  PIN esi_hi[206]
    DIRECTION INPUT ;
    USE SIGNAL ;
    PORT
      LAYER M5 ;
        RECT  44.784 47.436 44.808 47.52 ;
    END
  END esi_hi[206]
  PIN esi_hi[207]
    DIRECTION INPUT ;
    USE SIGNAL ;
    PORT
      LAYER M5 ;
        RECT  44.88 47.436 44.904 47.52 ;
    END
  END esi_hi[207]
  PIN esi_hi[208]
    DIRECTION INPUT ;
    USE SIGNAL ;
    PORT
      LAYER M5 ;
        RECT  44.976 47.436 45 47.52 ;
    END
  END esi_hi[208]
  PIN esi_hi[209]
    DIRECTION INPUT ;
    USE SIGNAL ;
    PORT
      LAYER M5 ;
        RECT  45.072 47.436 45.096 47.52 ;
    END
  END esi_hi[209]
  PIN esi_hi[20]
    DIRECTION INPUT ;
    USE SIGNAL ;
    PORT
      LAYER M5 ;
        RECT  49.2 47.436 49.224 47.52 ;
    END
  END esi_hi[20]
  PIN esi_hi[210]
    DIRECTION INPUT ;
    USE SIGNAL ;
    PORT
      LAYER M5 ;
        RECT  45.168 47.436 45.192 47.52 ;
    END
  END esi_hi[210]
  PIN esi_hi[211]
    DIRECTION INPUT ;
    USE SIGNAL ;
    PORT
      LAYER M5 ;
        RECT  45.264 47.436 45.288 47.52 ;
    END
  END esi_hi[211]
  PIN esi_hi[212]
    DIRECTION INPUT ;
    USE SIGNAL ;
    PORT
      LAYER M5 ;
        RECT  45.36 47.436 45.384 47.52 ;
    END
  END esi_hi[212]
  PIN esi_hi[213]
    DIRECTION INPUT ;
    USE SIGNAL ;
    PORT
      LAYER M5 ;
        RECT  45.456 47.436 45.48 47.52 ;
    END
  END esi_hi[213]
  PIN esi_hi[214]
    DIRECTION INPUT ;
    USE SIGNAL ;
    PORT
      LAYER M5 ;
        RECT  45.552 47.436 45.576 47.52 ;
    END
  END esi_hi[214]
  PIN esi_hi[215]
    DIRECTION INPUT ;
    USE SIGNAL ;
    PORT
      LAYER M5 ;
        RECT  45.648 47.436 45.672 47.52 ;
    END
  END esi_hi[215]
  PIN esi_hi[216]
    DIRECTION INPUT ;
    USE SIGNAL ;
    PORT
      LAYER M5 ;
        RECT  45.744 47.436 45.768 47.52 ;
    END
  END esi_hi[216]
  PIN esi_hi[217]
    DIRECTION INPUT ;
    USE SIGNAL ;
    PORT
      LAYER M5 ;
        RECT  45.84 47.436 45.864 47.52 ;
    END
  END esi_hi[217]
  PIN esi_hi[218]
    DIRECTION INPUT ;
    USE SIGNAL ;
    PORT
      LAYER M5 ;
        RECT  45.936 47.436 45.96 47.52 ;
    END
  END esi_hi[218]
  PIN esi_hi[219]
    DIRECTION INPUT ;
    USE SIGNAL ;
    PORT
      LAYER M5 ;
        RECT  46.032 47.436 46.056 47.52 ;
    END
  END esi_hi[219]
  PIN esi_hi[21]
    DIRECTION INPUT ;
    USE SIGNAL ;
    PORT
      LAYER M5 ;
        RECT  49.296 47.436 49.32 47.52 ;
    END
  END esi_hi[21]
  PIN esi_hi[220]
    DIRECTION INPUT ;
    USE SIGNAL ;
    PORT
      LAYER M5 ;
        RECT  46.128 47.436 46.152 47.52 ;
    END
  END esi_hi[220]
  PIN esi_hi[221]
    DIRECTION INPUT ;
    USE SIGNAL ;
    PORT
      LAYER M5 ;
        RECT  46.224 47.436 46.248 47.52 ;
    END
  END esi_hi[221]
  PIN esi_hi[222]
    DIRECTION INPUT ;
    USE SIGNAL ;
    PORT
      LAYER M5 ;
        RECT  46.32 47.436 46.344 47.52 ;
    END
  END esi_hi[222]
  PIN esi_hi[223]
    DIRECTION INPUT ;
    USE SIGNAL ;
    PORT
      LAYER M5 ;
        RECT  46.416 47.436 46.44 47.52 ;
    END
  END esi_hi[223]
  PIN esi_hi[224]
    DIRECTION INPUT ;
    USE SIGNAL ;
    PORT
      LAYER M5 ;
        RECT  66.48 47.436 66.504 47.52 ;
    END
  END esi_hi[224]
  PIN esi_hi[225]
    DIRECTION INPUT ;
    USE SIGNAL ;
    PORT
      LAYER M5 ;
        RECT  66.576 47.436 66.6 47.52 ;
    END
  END esi_hi[225]
  PIN esi_hi[226]
    DIRECTION INPUT ;
    USE SIGNAL ;
    PORT
      LAYER M5 ;
        RECT  66.672 47.436 66.696 47.52 ;
    END
  END esi_hi[226]
  PIN esi_hi[227]
    DIRECTION INPUT ;
    USE SIGNAL ;
    PORT
      LAYER M5 ;
        RECT  66.768 47.436 66.792 47.52 ;
    END
  END esi_hi[227]
  PIN esi_hi[228]
    DIRECTION INPUT ;
    USE SIGNAL ;
    PORT
      LAYER M5 ;
        RECT  66.864 47.436 66.888 47.52 ;
    END
  END esi_hi[228]
  PIN esi_hi[229]
    DIRECTION INPUT ;
    USE SIGNAL ;
    PORT
      LAYER M5 ;
        RECT  66.96 47.436 66.984 47.52 ;
    END
  END esi_hi[229]
  PIN esi_hi[22]
    DIRECTION INPUT ;
    USE SIGNAL ;
    PORT
      LAYER M5 ;
        RECT  49.392 47.436 49.416 47.52 ;
    END
  END esi_hi[22]
  PIN esi_hi[230]
    DIRECTION INPUT ;
    USE SIGNAL ;
    PORT
      LAYER M5 ;
        RECT  67.056 47.436 67.08 47.52 ;
    END
  END esi_hi[230]
  PIN esi_hi[231]
    DIRECTION INPUT ;
    USE SIGNAL ;
    PORT
      LAYER M5 ;
        RECT  67.152 47.436 67.176 47.52 ;
    END
  END esi_hi[231]
  PIN esi_hi[232]
    DIRECTION INPUT ;
    USE SIGNAL ;
    PORT
      LAYER M5 ;
        RECT  67.248 47.436 67.272 47.52 ;
    END
  END esi_hi[232]
  PIN esi_hi[233]
    DIRECTION INPUT ;
    USE SIGNAL ;
    PORT
      LAYER M5 ;
        RECT  67.344 47.436 67.368 47.52 ;
    END
  END esi_hi[233]
  PIN esi_hi[234]
    DIRECTION INPUT ;
    USE SIGNAL ;
    PORT
      LAYER M5 ;
        RECT  67.44 47.436 67.464 47.52 ;
    END
  END esi_hi[234]
  PIN esi_hi[235]
    DIRECTION INPUT ;
    USE SIGNAL ;
    PORT
      LAYER M5 ;
        RECT  67.536 47.436 67.56 47.52 ;
    END
  END esi_hi[235]
  PIN esi_hi[236]
    DIRECTION INPUT ;
    USE SIGNAL ;
    PORT
      LAYER M5 ;
        RECT  67.632 47.436 67.656 47.52 ;
    END
  END esi_hi[236]
  PIN esi_hi[237]
    DIRECTION INPUT ;
    USE SIGNAL ;
    PORT
      LAYER M5 ;
        RECT  67.728 47.436 67.752 47.52 ;
    END
  END esi_hi[237]
  PIN esi_hi[238]
    DIRECTION INPUT ;
    USE SIGNAL ;
    PORT
      LAYER M5 ;
        RECT  67.824 47.436 67.848 47.52 ;
    END
  END esi_hi[238]
  PIN esi_hi[239]
    DIRECTION INPUT ;
    USE SIGNAL ;
    PORT
      LAYER M5 ;
        RECT  67.92 47.436 67.944 47.52 ;
    END
  END esi_hi[239]
  PIN esi_hi[23]
    DIRECTION INPUT ;
    USE SIGNAL ;
    PORT
      LAYER M5 ;
        RECT  49.488 47.436 49.512 47.52 ;
    END
  END esi_hi[23]
  PIN esi_hi[240]
    DIRECTION INPUT ;
    USE SIGNAL ;
    PORT
      LAYER M5 ;
        RECT  68.016 47.436 68.04 47.52 ;
    END
  END esi_hi[240]
  PIN esi_hi[241]
    DIRECTION INPUT ;
    USE SIGNAL ;
    PORT
      LAYER M5 ;
        RECT  68.112 47.436 68.136 47.52 ;
    END
  END esi_hi[241]
  PIN esi_hi[242]
    DIRECTION INPUT ;
    USE SIGNAL ;
    PORT
      LAYER M5 ;
        RECT  68.208 47.436 68.232 47.52 ;
    END
  END esi_hi[242]
  PIN esi_hi[243]
    DIRECTION INPUT ;
    USE SIGNAL ;
    PORT
      LAYER M5 ;
        RECT  68.304 47.436 68.328 47.52 ;
    END
  END esi_hi[243]
  PIN esi_hi[244]
    DIRECTION INPUT ;
    USE SIGNAL ;
    PORT
      LAYER M5 ;
        RECT  68.4 47.436 68.424 47.52 ;
    END
  END esi_hi[244]
  PIN esi_hi[245]
    DIRECTION INPUT ;
    USE SIGNAL ;
    PORT
      LAYER M5 ;
        RECT  68.496 47.436 68.52 47.52 ;
    END
  END esi_hi[245]
  PIN esi_hi[246]
    DIRECTION INPUT ;
    USE SIGNAL ;
    PORT
      LAYER M5 ;
        RECT  68.592 47.436 68.616 47.52 ;
    END
  END esi_hi[246]
  PIN esi_hi[247]
    DIRECTION INPUT ;
    USE SIGNAL ;
    PORT
      LAYER M5 ;
        RECT  68.688 47.436 68.712 47.52 ;
    END
  END esi_hi[247]
  PIN esi_hi[248]
    DIRECTION INPUT ;
    USE SIGNAL ;
    PORT
      LAYER M5 ;
        RECT  68.784 47.436 68.808 47.52 ;
    END
  END esi_hi[248]
  PIN esi_hi[249]
    DIRECTION INPUT ;
    USE SIGNAL ;
    PORT
      LAYER M5 ;
        RECT  68.88 47.436 68.904 47.52 ;
    END
  END esi_hi[249]
  PIN esi_hi[24]
    DIRECTION INPUT ;
    USE SIGNAL ;
    PORT
      LAYER M5 ;
        RECT  49.584 47.436 49.608 47.52 ;
    END
  END esi_hi[24]
  PIN esi_hi[250]
    DIRECTION INPUT ;
    USE SIGNAL ;
    PORT
      LAYER M5 ;
        RECT  68.976 47.436 69 47.52 ;
    END
  END esi_hi[250]
  PIN esi_hi[251]
    DIRECTION INPUT ;
    USE SIGNAL ;
    PORT
      LAYER M5 ;
        RECT  69.072 47.436 69.096 47.52 ;
    END
  END esi_hi[251]
  PIN esi_hi[252]
    DIRECTION INPUT ;
    USE SIGNAL ;
    PORT
      LAYER M5 ;
        RECT  69.168 47.436 69.192 47.52 ;
    END
  END esi_hi[252]
  PIN esi_hi[253]
    DIRECTION INPUT ;
    USE SIGNAL ;
    PORT
      LAYER M5 ;
        RECT  69.264 47.436 69.288 47.52 ;
    END
  END esi_hi[253]
  PIN esi_hi[254]
    DIRECTION INPUT ;
    USE SIGNAL ;
    PORT
      LAYER M5 ;
        RECT  69.36 47.436 69.384 47.52 ;
    END
  END esi_hi[254]
  PIN esi_hi[255]
    DIRECTION INPUT ;
    USE SIGNAL ;
    PORT
      LAYER M5 ;
        RECT  69.456 47.436 69.48 47.52 ;
    END
  END esi_hi[255]
  PIN esi_hi[25]
    DIRECTION INPUT ;
    USE SIGNAL ;
    PORT
      LAYER M5 ;
        RECT  49.68 47.436 49.704 47.52 ;
    END
  END esi_hi[25]
  PIN esi_hi[26]
    DIRECTION INPUT ;
    USE SIGNAL ;
    PORT
      LAYER M5 ;
        RECT  49.776 47.436 49.8 47.52 ;
    END
  END esi_hi[26]
  PIN esi_hi[27]
    DIRECTION INPUT ;
    USE SIGNAL ;
    PORT
      LAYER M5 ;
        RECT  49.872 47.436 49.896 47.52 ;
    END
  END esi_hi[27]
  PIN esi_hi[28]
    DIRECTION INPUT ;
    USE SIGNAL ;
    PORT
      LAYER M5 ;
        RECT  49.968 47.436 49.992 47.52 ;
    END
  END esi_hi[28]
  PIN esi_hi[29]
    DIRECTION INPUT ;
    USE SIGNAL ;
    PORT
      LAYER M5 ;
        RECT  50.064 47.436 50.088 47.52 ;
    END
  END esi_hi[29]
  PIN esi_hi[2]
    DIRECTION INPUT ;
    USE SIGNAL ;
    PORT
      LAYER M5 ;
        RECT  47.472 47.436 47.496 47.52 ;
    END
  END esi_hi[2]
  PIN esi_hi[30]
    DIRECTION INPUT ;
    USE SIGNAL ;
    PORT
      LAYER M5 ;
        RECT  50.16 47.436 50.184 47.52 ;
    END
  END esi_hi[30]
  PIN esi_hi[31]
    DIRECTION INPUT ;
    USE SIGNAL ;
    PORT
      LAYER M5 ;
        RECT  50.256 47.436 50.28 47.52 ;
    END
  END esi_hi[31]
  PIN esi_hi[32]
    DIRECTION INPUT ;
    USE SIGNAL ;
    PORT
      LAYER M5 ;
        RECT  59.568 47.436 59.592 47.52 ;
    END
  END esi_hi[32]
  PIN esi_hi[33]
    DIRECTION INPUT ;
    USE SIGNAL ;
    PORT
      LAYER M5 ;
        RECT  59.664 47.436 59.688 47.52 ;
    END
  END esi_hi[33]
  PIN esi_hi[34]
    DIRECTION INPUT ;
    USE SIGNAL ;
    PORT
      LAYER M5 ;
        RECT  59.76 47.436 59.784 47.52 ;
    END
  END esi_hi[34]
  PIN esi_hi[35]
    DIRECTION INPUT ;
    USE SIGNAL ;
    PORT
      LAYER M5 ;
        RECT  59.856 47.436 59.88 47.52 ;
    END
  END esi_hi[35]
  PIN esi_hi[36]
    DIRECTION INPUT ;
    USE SIGNAL ;
    PORT
      LAYER M5 ;
        RECT  59.952 47.436 59.976 47.52 ;
    END
  END esi_hi[36]
  PIN esi_hi[37]
    DIRECTION INPUT ;
    USE SIGNAL ;
    PORT
      LAYER M5 ;
        RECT  60.048 47.436 60.072 47.52 ;
    END
  END esi_hi[37]
  PIN esi_hi[38]
    DIRECTION INPUT ;
    USE SIGNAL ;
    PORT
      LAYER M5 ;
        RECT  60.144 47.436 60.168 47.52 ;
    END
  END esi_hi[38]
  PIN esi_hi[39]
    DIRECTION INPUT ;
    USE SIGNAL ;
    PORT
      LAYER M5 ;
        RECT  60.24 47.436 60.264 47.52 ;
    END
  END esi_hi[39]
  PIN esi_hi[3]
    DIRECTION INPUT ;
    USE SIGNAL ;
    PORT
      LAYER M5 ;
        RECT  47.568 47.436 47.592 47.52 ;
    END
  END esi_hi[3]
  PIN esi_hi[40]
    DIRECTION INPUT ;
    USE SIGNAL ;
    PORT
      LAYER M5 ;
        RECT  60.336 47.436 60.36 47.52 ;
    END
  END esi_hi[40]
  PIN esi_hi[41]
    DIRECTION INPUT ;
    USE SIGNAL ;
    PORT
      LAYER M5 ;
        RECT  60.432 47.436 60.456 47.52 ;
    END
  END esi_hi[41]
  PIN esi_hi[42]
    DIRECTION INPUT ;
    USE SIGNAL ;
    PORT
      LAYER M5 ;
        RECT  60.528 47.436 60.552 47.52 ;
    END
  END esi_hi[42]
  PIN esi_hi[43]
    DIRECTION INPUT ;
    USE SIGNAL ;
    PORT
      LAYER M5 ;
        RECT  60.624 47.436 60.648 47.52 ;
    END
  END esi_hi[43]
  PIN esi_hi[44]
    DIRECTION INPUT ;
    USE SIGNAL ;
    PORT
      LAYER M5 ;
        RECT  60.72 47.436 60.744 47.52 ;
    END
  END esi_hi[44]
  PIN esi_hi[45]
    DIRECTION INPUT ;
    USE SIGNAL ;
    PORT
      LAYER M5 ;
        RECT  60.816 47.436 60.84 47.52 ;
    END
  END esi_hi[45]
  PIN esi_hi[46]
    DIRECTION INPUT ;
    USE SIGNAL ;
    PORT
      LAYER M5 ;
        RECT  60.912 47.436 60.936 47.52 ;
    END
  END esi_hi[46]
  PIN esi_hi[47]
    DIRECTION INPUT ;
    USE SIGNAL ;
    PORT
      LAYER M5 ;
        RECT  61.008 47.436 61.032 47.52 ;
    END
  END esi_hi[47]
  PIN esi_hi[48]
    DIRECTION INPUT ;
    USE SIGNAL ;
    PORT
      LAYER M5 ;
        RECT  61.104 47.436 61.128 47.52 ;
    END
  END esi_hi[48]
  PIN esi_hi[49]
    DIRECTION INPUT ;
    USE SIGNAL ;
    PORT
      LAYER M5 ;
        RECT  61.2 47.436 61.224 47.52 ;
    END
  END esi_hi[49]
  PIN esi_hi[4]
    DIRECTION INPUT ;
    USE SIGNAL ;
    PORT
      LAYER M5 ;
        RECT  47.664 47.436 47.688 47.52 ;
    END
  END esi_hi[4]
  PIN esi_hi[50]
    DIRECTION INPUT ;
    USE SIGNAL ;
    PORT
      LAYER M5 ;
        RECT  61.296 47.436 61.32 47.52 ;
    END
  END esi_hi[50]
  PIN esi_hi[51]
    DIRECTION INPUT ;
    USE SIGNAL ;
    PORT
      LAYER M5 ;
        RECT  61.392 47.436 61.416 47.52 ;
    END
  END esi_hi[51]
  PIN esi_hi[52]
    DIRECTION INPUT ;
    USE SIGNAL ;
    PORT
      LAYER M5 ;
        RECT  61.488 47.436 61.512 47.52 ;
    END
  END esi_hi[52]
  PIN esi_hi[53]
    DIRECTION INPUT ;
    USE SIGNAL ;
    PORT
      LAYER M5 ;
        RECT  61.584 47.436 61.608 47.52 ;
    END
  END esi_hi[53]
  PIN esi_hi[54]
    DIRECTION INPUT ;
    USE SIGNAL ;
    PORT
      LAYER M5 ;
        RECT  61.68 47.436 61.704 47.52 ;
    END
  END esi_hi[54]
  PIN esi_hi[55]
    DIRECTION INPUT ;
    USE SIGNAL ;
    PORT
      LAYER M5 ;
        RECT  61.776 47.436 61.8 47.52 ;
    END
  END esi_hi[55]
  PIN esi_hi[56]
    DIRECTION INPUT ;
    USE SIGNAL ;
    PORT
      LAYER M5 ;
        RECT  61.872 47.436 61.896 47.52 ;
    END
  END esi_hi[56]
  PIN esi_hi[57]
    DIRECTION INPUT ;
    USE SIGNAL ;
    PORT
      LAYER M5 ;
        RECT  61.968 47.436 61.992 47.52 ;
    END
  END esi_hi[57]
  PIN esi_hi[58]
    DIRECTION INPUT ;
    USE SIGNAL ;
    PORT
      LAYER M5 ;
        RECT  62.064 47.436 62.088 47.52 ;
    END
  END esi_hi[58]
  PIN esi_hi[59]
    DIRECTION INPUT ;
    USE SIGNAL ;
    PORT
      LAYER M5 ;
        RECT  62.16 47.436 62.184 47.52 ;
    END
  END esi_hi[59]
  PIN esi_hi[5]
    DIRECTION INPUT ;
    USE SIGNAL ;
    PORT
      LAYER M5 ;
        RECT  47.76 47.436 47.784 47.52 ;
    END
  END esi_hi[5]
  PIN esi_hi[60]
    DIRECTION INPUT ;
    USE SIGNAL ;
    PORT
      LAYER M5 ;
        RECT  62.256 47.436 62.28 47.52 ;
    END
  END esi_hi[60]
  PIN esi_hi[61]
    DIRECTION INPUT ;
    USE SIGNAL ;
    PORT
      LAYER M5 ;
        RECT  62.352 47.436 62.376 47.52 ;
    END
  END esi_hi[61]
  PIN esi_hi[62]
    DIRECTION INPUT ;
    USE SIGNAL ;
    PORT
      LAYER M5 ;
        RECT  62.448 47.436 62.472 47.52 ;
    END
  END esi_hi[62]
  PIN esi_hi[63]
    DIRECTION INPUT ;
    USE SIGNAL ;
    PORT
      LAYER M5 ;
        RECT  62.544 47.436 62.568 47.52 ;
    END
  END esi_hi[63]
  PIN esi_hi[64]
    DIRECTION INPUT ;
    USE SIGNAL ;
    PORT
      LAYER M5 ;
        RECT  50.352 47.436 50.376 47.52 ;
    END
  END esi_hi[64]
  PIN esi_hi[65]
    DIRECTION INPUT ;
    USE SIGNAL ;
    PORT
      LAYER M5 ;
        RECT  50.448 47.436 50.472 47.52 ;
    END
  END esi_hi[65]
  PIN esi_hi[66]
    DIRECTION INPUT ;
    USE SIGNAL ;
    PORT
      LAYER M5 ;
        RECT  50.544 47.436 50.568 47.52 ;
    END
  END esi_hi[66]
  PIN esi_hi[67]
    DIRECTION INPUT ;
    USE SIGNAL ;
    PORT
      LAYER M5 ;
        RECT  50.64 47.436 50.664 47.52 ;
    END
  END esi_hi[67]
  PIN esi_hi[68]
    DIRECTION INPUT ;
    USE SIGNAL ;
    PORT
      LAYER M5 ;
        RECT  50.736 47.436 50.76 47.52 ;
    END
  END esi_hi[68]
  PIN esi_hi[69]
    DIRECTION INPUT ;
    USE SIGNAL ;
    PORT
      LAYER M5 ;
        RECT  50.832 47.436 50.856 47.52 ;
    END
  END esi_hi[69]
  PIN esi_hi[6]
    DIRECTION INPUT ;
    USE SIGNAL ;
    PORT
      LAYER M5 ;
        RECT  47.856 47.436 47.88 47.52 ;
    END
  END esi_hi[6]
  PIN esi_hi[70]
    DIRECTION INPUT ;
    USE SIGNAL ;
    PORT
      LAYER M5 ;
        RECT  50.928 47.436 50.952 47.52 ;
    END
  END esi_hi[70]
  PIN esi_hi[71]
    DIRECTION INPUT ;
    USE SIGNAL ;
    PORT
      LAYER M5 ;
        RECT  51.024 47.436 51.048 47.52 ;
    END
  END esi_hi[71]
  PIN esi_hi[72]
    DIRECTION INPUT ;
    USE SIGNAL ;
    PORT
      LAYER M5 ;
        RECT  51.12 47.436 51.144 47.52 ;
    END
  END esi_hi[72]
  PIN esi_hi[73]
    DIRECTION INPUT ;
    USE SIGNAL ;
    PORT
      LAYER M5 ;
        RECT  51.216 47.436 51.24 47.52 ;
    END
  END esi_hi[73]
  PIN esi_hi[74]
    DIRECTION INPUT ;
    USE SIGNAL ;
    PORT
      LAYER M5 ;
        RECT  51.312 47.436 51.336 47.52 ;
    END
  END esi_hi[74]
  PIN esi_hi[75]
    DIRECTION INPUT ;
    USE SIGNAL ;
    PORT
      LAYER M5 ;
        RECT  51.408 47.436 51.432 47.52 ;
    END
  END esi_hi[75]
  PIN esi_hi[76]
    DIRECTION INPUT ;
    USE SIGNAL ;
    PORT
      LAYER M5 ;
        RECT  51.504 47.436 51.528 47.52 ;
    END
  END esi_hi[76]
  PIN esi_hi[77]
    DIRECTION INPUT ;
    USE SIGNAL ;
    PORT
      LAYER M5 ;
        RECT  51.6 47.436 51.624 47.52 ;
    END
  END esi_hi[77]
  PIN esi_hi[78]
    DIRECTION INPUT ;
    USE SIGNAL ;
    PORT
      LAYER M5 ;
        RECT  51.696 47.436 51.72 47.52 ;
    END
  END esi_hi[78]
  PIN esi_hi[79]
    DIRECTION INPUT ;
    USE SIGNAL ;
    PORT
      LAYER M5 ;
        RECT  51.792 47.436 51.816 47.52 ;
    END
  END esi_hi[79]
  PIN esi_hi[7]
    DIRECTION INPUT ;
    USE SIGNAL ;
    PORT
      LAYER M5 ;
        RECT  47.952 47.436 47.976 47.52 ;
    END
  END esi_hi[7]
  PIN esi_hi[80]
    DIRECTION INPUT ;
    USE SIGNAL ;
    PORT
      LAYER M5 ;
        RECT  51.888 47.436 51.912 47.52 ;
    END
  END esi_hi[80]
  PIN esi_hi[81]
    DIRECTION INPUT ;
    USE SIGNAL ;
    PORT
      LAYER M5 ;
        RECT  51.984 47.436 52.008 47.52 ;
    END
  END esi_hi[81]
  PIN esi_hi[82]
    DIRECTION INPUT ;
    USE SIGNAL ;
    PORT
      LAYER M5 ;
        RECT  52.08 47.436 52.104 47.52 ;
    END
  END esi_hi[82]
  PIN esi_hi[83]
    DIRECTION INPUT ;
    USE SIGNAL ;
    PORT
      LAYER M5 ;
        RECT  52.176 47.436 52.2 47.52 ;
    END
  END esi_hi[83]
  PIN esi_hi[84]
    DIRECTION INPUT ;
    USE SIGNAL ;
    PORT
      LAYER M5 ;
        RECT  52.272 47.436 52.296 47.52 ;
    END
  END esi_hi[84]
  PIN esi_hi[85]
    DIRECTION INPUT ;
    USE SIGNAL ;
    PORT
      LAYER M5 ;
        RECT  52.368 47.436 52.392 47.52 ;
    END
  END esi_hi[85]
  PIN esi_hi[86]
    DIRECTION INPUT ;
    USE SIGNAL ;
    PORT
      LAYER M5 ;
        RECT  52.464 47.436 52.488 47.52 ;
    END
  END esi_hi[86]
  PIN esi_hi[87]
    DIRECTION INPUT ;
    USE SIGNAL ;
    PORT
      LAYER M5 ;
        RECT  52.56 47.436 52.584 47.52 ;
    END
  END esi_hi[87]
  PIN esi_hi[88]
    DIRECTION INPUT ;
    USE SIGNAL ;
    PORT
      LAYER M5 ;
        RECT  52.656 47.436 52.68 47.52 ;
    END
  END esi_hi[88]
  PIN esi_hi[89]
    DIRECTION INPUT ;
    USE SIGNAL ;
    PORT
      LAYER M5 ;
        RECT  52.752 47.436 52.776 47.52 ;
    END
  END esi_hi[89]
  PIN esi_hi[8]
    DIRECTION INPUT ;
    USE SIGNAL ;
    PORT
      LAYER M5 ;
        RECT  48.048 47.436 48.072 47.52 ;
    END
  END esi_hi[8]
  PIN esi_hi[90]
    DIRECTION INPUT ;
    USE SIGNAL ;
    PORT
      LAYER M5 ;
        RECT  52.848 47.436 52.872 47.52 ;
    END
  END esi_hi[90]
  PIN esi_hi[91]
    DIRECTION INPUT ;
    USE SIGNAL ;
    PORT
      LAYER M5 ;
        RECT  52.944 47.436 52.968 47.52 ;
    END
  END esi_hi[91]
  PIN esi_hi[92]
    DIRECTION INPUT ;
    USE SIGNAL ;
    PORT
      LAYER M5 ;
        RECT  53.04 47.436 53.064 47.52 ;
    END
  END esi_hi[92]
  PIN esi_hi[93]
    DIRECTION INPUT ;
    USE SIGNAL ;
    PORT
      LAYER M5 ;
        RECT  53.136 47.436 53.16 47.52 ;
    END
  END esi_hi[93]
  PIN esi_hi[94]
    DIRECTION INPUT ;
    USE SIGNAL ;
    PORT
      LAYER M5 ;
        RECT  53.232 47.436 53.256 47.52 ;
    END
  END esi_hi[94]
  PIN esi_hi[95]
    DIRECTION INPUT ;
    USE SIGNAL ;
    PORT
      LAYER M5 ;
        RECT  53.328 47.436 53.352 47.52 ;
    END
  END esi_hi[95]
  PIN esi_hi[96]
    DIRECTION INPUT ;
    USE SIGNAL ;
    PORT
      LAYER M5 ;
        RECT  56.496 47.436 56.52 47.52 ;
    END
  END esi_hi[96]
  PIN esi_hi[97]
    DIRECTION INPUT ;
    USE SIGNAL ;
    PORT
      LAYER M5 ;
        RECT  56.592 47.436 56.616 47.52 ;
    END
  END esi_hi[97]
  PIN esi_hi[98]
    DIRECTION INPUT ;
    USE SIGNAL ;
    PORT
      LAYER M5 ;
        RECT  56.688 47.436 56.712 47.52 ;
    END
  END esi_hi[98]
  PIN esi_hi[99]
    DIRECTION INPUT ;
    USE SIGNAL ;
    PORT
      LAYER M5 ;
        RECT  56.784 47.436 56.808 47.52 ;
    END
  END esi_hi[99]
  PIN esi_hi[9]
    DIRECTION INPUT ;
    USE SIGNAL ;
    PORT
      LAYER M5 ;
        RECT  48.144 47.436 48.168 47.52 ;
    END
  END esi_hi[9]
  PIN esi_lo[0]
    DIRECTION INPUT ;
    USE SIGNAL ;
    PORT
      LAYER M5 ;
        RECT  47.28 0 47.304 0.084 ;
    END
  END esi_lo[0]
  PIN esi_lo[100]
    DIRECTION INPUT ;
    USE SIGNAL ;
    PORT
      LAYER M5 ;
        RECT  56.88 0 56.904 0.084 ;
    END
  END esi_lo[100]
  PIN esi_lo[101]
    DIRECTION INPUT ;
    USE SIGNAL ;
    PORT
      LAYER M5 ;
        RECT  56.976 0 57 0.084 ;
    END
  END esi_lo[101]
  PIN esi_lo[102]
    DIRECTION INPUT ;
    USE SIGNAL ;
    PORT
      LAYER M5 ;
        RECT  57.072 0 57.096 0.084 ;
    END
  END esi_lo[102]
  PIN esi_lo[103]
    DIRECTION INPUT ;
    USE SIGNAL ;
    PORT
      LAYER M5 ;
        RECT  57.168 0 57.192 0.084 ;
    END
  END esi_lo[103]
  PIN esi_lo[104]
    DIRECTION INPUT ;
    USE SIGNAL ;
    PORT
      LAYER M5 ;
        RECT  57.264 0 57.288 0.084 ;
    END
  END esi_lo[104]
  PIN esi_lo[105]
    DIRECTION INPUT ;
    USE SIGNAL ;
    PORT
      LAYER M5 ;
        RECT  57.36 0 57.384 0.084 ;
    END
  END esi_lo[105]
  PIN esi_lo[106]
    DIRECTION INPUT ;
    USE SIGNAL ;
    PORT
      LAYER M5 ;
        RECT  57.456 0 57.48 0.084 ;
    END
  END esi_lo[106]
  PIN esi_lo[107]
    DIRECTION INPUT ;
    USE SIGNAL ;
    PORT
      LAYER M5 ;
        RECT  57.552 0 57.576 0.084 ;
    END
  END esi_lo[107]
  PIN esi_lo[108]
    DIRECTION INPUT ;
    USE SIGNAL ;
    PORT
      LAYER M5 ;
        RECT  57.648 0 57.672 0.084 ;
    END
  END esi_lo[108]
  PIN esi_lo[109]
    DIRECTION INPUT ;
    USE SIGNAL ;
    PORT
      LAYER M5 ;
        RECT  57.744 0 57.768 0.084 ;
    END
  END esi_lo[109]
  PIN esi_lo[10]
    DIRECTION INPUT ;
    USE SIGNAL ;
    PORT
      LAYER M5 ;
        RECT  48.24 0 48.264 0.084 ;
    END
  END esi_lo[10]
  PIN esi_lo[110]
    DIRECTION INPUT ;
    USE SIGNAL ;
    PORT
      LAYER M5 ;
        RECT  57.84 0 57.864 0.084 ;
    END
  END esi_lo[110]
  PIN esi_lo[111]
    DIRECTION INPUT ;
    USE SIGNAL ;
    PORT
      LAYER M5 ;
        RECT  57.936 0 57.96 0.084 ;
    END
  END esi_lo[111]
  PIN esi_lo[112]
    DIRECTION INPUT ;
    USE SIGNAL ;
    PORT
      LAYER M5 ;
        RECT  58.032 0 58.056 0.084 ;
    END
  END esi_lo[112]
  PIN esi_lo[113]
    DIRECTION INPUT ;
    USE SIGNAL ;
    PORT
      LAYER M5 ;
        RECT  58.128 0 58.152 0.084 ;
    END
  END esi_lo[113]
  PIN esi_lo[114]
    DIRECTION INPUT ;
    USE SIGNAL ;
    PORT
      LAYER M5 ;
        RECT  58.224 0 58.248 0.084 ;
    END
  END esi_lo[114]
  PIN esi_lo[115]
    DIRECTION INPUT ;
    USE SIGNAL ;
    PORT
      LAYER M5 ;
        RECT  58.32 0 58.344 0.084 ;
    END
  END esi_lo[115]
  PIN esi_lo[116]
    DIRECTION INPUT ;
    USE SIGNAL ;
    PORT
      LAYER M5 ;
        RECT  58.416 0 58.44 0.084 ;
    END
  END esi_lo[116]
  PIN esi_lo[117]
    DIRECTION INPUT ;
    USE SIGNAL ;
    PORT
      LAYER M5 ;
        RECT  58.512 0 58.536 0.084 ;
    END
  END esi_lo[117]
  PIN esi_lo[118]
    DIRECTION INPUT ;
    USE SIGNAL ;
    PORT
      LAYER M5 ;
        RECT  58.608 0 58.632 0.084 ;
    END
  END esi_lo[118]
  PIN esi_lo[119]
    DIRECTION INPUT ;
    USE SIGNAL ;
    PORT
      LAYER M5 ;
        RECT  58.704 0 58.728 0.084 ;
    END
  END esi_lo[119]
  PIN esi_lo[11]
    DIRECTION INPUT ;
    USE SIGNAL ;
    PORT
      LAYER M5 ;
        RECT  48.336 0 48.36 0.084 ;
    END
  END esi_lo[11]
  PIN esi_lo[120]
    DIRECTION INPUT ;
    USE SIGNAL ;
    PORT
      LAYER M5 ;
        RECT  58.8 0 58.824 0.084 ;
    END
  END esi_lo[120]
  PIN esi_lo[121]
    DIRECTION INPUT ;
    USE SIGNAL ;
    PORT
      LAYER M5 ;
        RECT  58.896 0 58.92 0.084 ;
    END
  END esi_lo[121]
  PIN esi_lo[122]
    DIRECTION INPUT ;
    USE SIGNAL ;
    PORT
      LAYER M5 ;
        RECT  58.992 0 59.016 0.084 ;
    END
  END esi_lo[122]
  PIN esi_lo[123]
    DIRECTION INPUT ;
    USE SIGNAL ;
    PORT
      LAYER M5 ;
        RECT  59.088 0 59.112 0.084 ;
    END
  END esi_lo[123]
  PIN esi_lo[124]
    DIRECTION INPUT ;
    USE SIGNAL ;
    PORT
      LAYER M5 ;
        RECT  59.184 0 59.208 0.084 ;
    END
  END esi_lo[124]
  PIN esi_lo[125]
    DIRECTION INPUT ;
    USE SIGNAL ;
    PORT
      LAYER M5 ;
        RECT  59.28 0 59.304 0.084 ;
    END
  END esi_lo[125]
  PIN esi_lo[126]
    DIRECTION INPUT ;
    USE SIGNAL ;
    PORT
      LAYER M5 ;
        RECT  59.376 0 59.4 0.084 ;
    END
  END esi_lo[126]
  PIN esi_lo[127]
    DIRECTION INPUT ;
    USE SIGNAL ;
    PORT
      LAYER M5 ;
        RECT  59.472 0 59.496 0.084 ;
    END
  END esi_lo[127]
  PIN esi_lo[128]
    DIRECTION INPUT ;
    USE SIGNAL ;
    PORT
      LAYER M5 ;
        RECT  50.352 0 50.376 0.084 ;
    END
  END esi_lo[128]
  PIN esi_lo[129]
    DIRECTION INPUT ;
    USE SIGNAL ;
    PORT
      LAYER M5 ;
        RECT  50.448 0 50.472 0.084 ;
    END
  END esi_lo[129]
  PIN esi_lo[12]
    DIRECTION INPUT ;
    USE SIGNAL ;
    PORT
      LAYER M5 ;
        RECT  48.432 0 48.456 0.084 ;
    END
  END esi_lo[12]
  PIN esi_lo[130]
    DIRECTION INPUT ;
    USE SIGNAL ;
    PORT
      LAYER M5 ;
        RECT  50.544 0 50.568 0.084 ;
    END
  END esi_lo[130]
  PIN esi_lo[131]
    DIRECTION INPUT ;
    USE SIGNAL ;
    PORT
      LAYER M5 ;
        RECT  50.64 0 50.664 0.084 ;
    END
  END esi_lo[131]
  PIN esi_lo[132]
    DIRECTION INPUT ;
    USE SIGNAL ;
    PORT
      LAYER M5 ;
        RECT  50.736 0 50.76 0.084 ;
    END
  END esi_lo[132]
  PIN esi_lo[133]
    DIRECTION INPUT ;
    USE SIGNAL ;
    PORT
      LAYER M5 ;
        RECT  50.832 0 50.856 0.084 ;
    END
  END esi_lo[133]
  PIN esi_lo[134]
    DIRECTION INPUT ;
    USE SIGNAL ;
    PORT
      LAYER M5 ;
        RECT  50.928 0 50.952 0.084 ;
    END
  END esi_lo[134]
  PIN esi_lo[135]
    DIRECTION INPUT ;
    USE SIGNAL ;
    PORT
      LAYER M5 ;
        RECT  51.024 0 51.048 0.084 ;
    END
  END esi_lo[135]
  PIN esi_lo[136]
    DIRECTION INPUT ;
    USE SIGNAL ;
    PORT
      LAYER M5 ;
        RECT  51.12 0 51.144 0.084 ;
    END
  END esi_lo[136]
  PIN esi_lo[137]
    DIRECTION INPUT ;
    USE SIGNAL ;
    PORT
      LAYER M5 ;
        RECT  51.216 0 51.24 0.084 ;
    END
  END esi_lo[137]
  PIN esi_lo[138]
    DIRECTION INPUT ;
    USE SIGNAL ;
    PORT
      LAYER M5 ;
        RECT  51.312 0 51.336 0.084 ;
    END
  END esi_lo[138]
  PIN esi_lo[139]
    DIRECTION INPUT ;
    USE SIGNAL ;
    PORT
      LAYER M5 ;
        RECT  51.408 0 51.432 0.084 ;
    END
  END esi_lo[139]
  PIN esi_lo[13]
    DIRECTION INPUT ;
    USE SIGNAL ;
    PORT
      LAYER M5 ;
        RECT  48.528 0 48.552 0.084 ;
    END
  END esi_lo[13]
  PIN esi_lo[140]
    DIRECTION INPUT ;
    USE SIGNAL ;
    PORT
      LAYER M5 ;
        RECT  51.504 0 51.528 0.084 ;
    END
  END esi_lo[140]
  PIN esi_lo[141]
    DIRECTION INPUT ;
    USE SIGNAL ;
    PORT
      LAYER M5 ;
        RECT  51.6 0 51.624 0.084 ;
    END
  END esi_lo[141]
  PIN esi_lo[142]
    DIRECTION INPUT ;
    USE SIGNAL ;
    PORT
      LAYER M5 ;
        RECT  51.696 0 51.72 0.084 ;
    END
  END esi_lo[142]
  PIN esi_lo[143]
    DIRECTION INPUT ;
    USE SIGNAL ;
    PORT
      LAYER M5 ;
        RECT  51.792 0 51.816 0.084 ;
    END
  END esi_lo[143]
  PIN esi_lo[144]
    DIRECTION INPUT ;
    USE SIGNAL ;
    PORT
      LAYER M5 ;
        RECT  51.888 0 51.912 0.084 ;
    END
  END esi_lo[144]
  PIN esi_lo[145]
    DIRECTION INPUT ;
    USE SIGNAL ;
    PORT
      LAYER M5 ;
        RECT  51.984 0 52.008 0.084 ;
    END
  END esi_lo[145]
  PIN esi_lo[146]
    DIRECTION INPUT ;
    USE SIGNAL ;
    PORT
      LAYER M5 ;
        RECT  52.08 0 52.104 0.084 ;
    END
  END esi_lo[146]
  PIN esi_lo[147]
    DIRECTION INPUT ;
    USE SIGNAL ;
    PORT
      LAYER M5 ;
        RECT  52.176 0 52.2 0.084 ;
    END
  END esi_lo[147]
  PIN esi_lo[148]
    DIRECTION INPUT ;
    USE SIGNAL ;
    PORT
      LAYER M5 ;
        RECT  52.272 0 52.296 0.084 ;
    END
  END esi_lo[148]
  PIN esi_lo[149]
    DIRECTION INPUT ;
    USE SIGNAL ;
    PORT
      LAYER M5 ;
        RECT  52.368 0 52.392 0.084 ;
    END
  END esi_lo[149]
  PIN esi_lo[14]
    DIRECTION INPUT ;
    USE SIGNAL ;
    PORT
      LAYER M5 ;
        RECT  48.624 0 48.648 0.084 ;
    END
  END esi_lo[14]
  PIN esi_lo[150]
    DIRECTION INPUT ;
    USE SIGNAL ;
    PORT
      LAYER M5 ;
        RECT  52.464 0 52.488 0.084 ;
    END
  END esi_lo[150]
  PIN esi_lo[151]
    DIRECTION INPUT ;
    USE SIGNAL ;
    PORT
      LAYER M5 ;
        RECT  52.56 0 52.584 0.084 ;
    END
  END esi_lo[151]
  PIN esi_lo[152]
    DIRECTION INPUT ;
    USE SIGNAL ;
    PORT
      LAYER M5 ;
        RECT  52.656 0 52.68 0.084 ;
    END
  END esi_lo[152]
  PIN esi_lo[153]
    DIRECTION INPUT ;
    USE SIGNAL ;
    PORT
      LAYER M5 ;
        RECT  52.752 0 52.776 0.084 ;
    END
  END esi_lo[153]
  PIN esi_lo[154]
    DIRECTION INPUT ;
    USE SIGNAL ;
    PORT
      LAYER M5 ;
        RECT  52.848 0 52.872 0.084 ;
    END
  END esi_lo[154]
  PIN esi_lo[155]
    DIRECTION INPUT ;
    USE SIGNAL ;
    PORT
      LAYER M5 ;
        RECT  52.944 0 52.968 0.084 ;
    END
  END esi_lo[155]
  PIN esi_lo[156]
    DIRECTION INPUT ;
    USE SIGNAL ;
    PORT
      LAYER M5 ;
        RECT  53.04 0 53.064 0.084 ;
    END
  END esi_lo[156]
  PIN esi_lo[157]
    DIRECTION INPUT ;
    USE SIGNAL ;
    PORT
      LAYER M5 ;
        RECT  53.136 0 53.16 0.084 ;
    END
  END esi_lo[157]
  PIN esi_lo[158]
    DIRECTION INPUT ;
    USE SIGNAL ;
    PORT
      LAYER M5 ;
        RECT  53.232 0 53.256 0.084 ;
    END
  END esi_lo[158]
  PIN esi_lo[159]
    DIRECTION INPUT ;
    USE SIGNAL ;
    PORT
      LAYER M5 ;
        RECT  53.328 0 53.352 0.084 ;
    END
  END esi_lo[159]
  PIN esi_lo[15]
    DIRECTION INPUT ;
    USE SIGNAL ;
    PORT
      LAYER M5 ;
        RECT  48.72 0 48.744 0.084 ;
    END
  END esi_lo[15]
  PIN esi_lo[160]
    DIRECTION INPUT ;
    USE SIGNAL ;
    PORT
      LAYER M5 ;
        RECT  59.568 0 59.592 0.084 ;
    END
  END esi_lo[160]
  PIN esi_lo[161]
    DIRECTION INPUT ;
    USE SIGNAL ;
    PORT
      LAYER M5 ;
        RECT  59.664 0 59.688 0.084 ;
    END
  END esi_lo[161]
  PIN esi_lo[162]
    DIRECTION INPUT ;
    USE SIGNAL ;
    PORT
      LAYER M5 ;
        RECT  59.76 0 59.784 0.084 ;
    END
  END esi_lo[162]
  PIN esi_lo[163]
    DIRECTION INPUT ;
    USE SIGNAL ;
    PORT
      LAYER M5 ;
        RECT  59.856 0 59.88 0.084 ;
    END
  END esi_lo[163]
  PIN esi_lo[164]
    DIRECTION INPUT ;
    USE SIGNAL ;
    PORT
      LAYER M5 ;
        RECT  59.952 0 59.976 0.084 ;
    END
  END esi_lo[164]
  PIN esi_lo[165]
    DIRECTION INPUT ;
    USE SIGNAL ;
    PORT
      LAYER M5 ;
        RECT  60.048 0 60.072 0.084 ;
    END
  END esi_lo[165]
  PIN esi_lo[166]
    DIRECTION INPUT ;
    USE SIGNAL ;
    PORT
      LAYER M5 ;
        RECT  60.144 0 60.168 0.084 ;
    END
  END esi_lo[166]
  PIN esi_lo[167]
    DIRECTION INPUT ;
    USE SIGNAL ;
    PORT
      LAYER M5 ;
        RECT  60.24 0 60.264 0.084 ;
    END
  END esi_lo[167]
  PIN esi_lo[168]
    DIRECTION INPUT ;
    USE SIGNAL ;
    PORT
      LAYER M5 ;
        RECT  60.336 0 60.36 0.084 ;
    END
  END esi_lo[168]
  PIN esi_lo[169]
    DIRECTION INPUT ;
    USE SIGNAL ;
    PORT
      LAYER M5 ;
        RECT  60.432 0 60.456 0.084 ;
    END
  END esi_lo[169]
  PIN esi_lo[16]
    DIRECTION INPUT ;
    USE SIGNAL ;
    PORT
      LAYER M5 ;
        RECT  48.816 0 48.84 0.084 ;
    END
  END esi_lo[16]
  PIN esi_lo[170]
    DIRECTION INPUT ;
    USE SIGNAL ;
    PORT
      LAYER M5 ;
        RECT  60.528 0 60.552 0.084 ;
    END
  END esi_lo[170]
  PIN esi_lo[171]
    DIRECTION INPUT ;
    USE SIGNAL ;
    PORT
      LAYER M5 ;
        RECT  60.624 0 60.648 0.084 ;
    END
  END esi_lo[171]
  PIN esi_lo[172]
    DIRECTION INPUT ;
    USE SIGNAL ;
    PORT
      LAYER M5 ;
        RECT  60.72 0 60.744 0.084 ;
    END
  END esi_lo[172]
  PIN esi_lo[173]
    DIRECTION INPUT ;
    USE SIGNAL ;
    PORT
      LAYER M5 ;
        RECT  60.816 0 60.84 0.084 ;
    END
  END esi_lo[173]
  PIN esi_lo[174]
    DIRECTION INPUT ;
    USE SIGNAL ;
    PORT
      LAYER M5 ;
        RECT  60.912 0 60.936 0.084 ;
    END
  END esi_lo[174]
  PIN esi_lo[175]
    DIRECTION INPUT ;
    USE SIGNAL ;
    PORT
      LAYER M5 ;
        RECT  61.008 0 61.032 0.084 ;
    END
  END esi_lo[175]
  PIN esi_lo[176]
    DIRECTION INPUT ;
    USE SIGNAL ;
    PORT
      LAYER M5 ;
        RECT  61.104 0 61.128 0.084 ;
    END
  END esi_lo[176]
  PIN esi_lo[177]
    DIRECTION INPUT ;
    USE SIGNAL ;
    PORT
      LAYER M5 ;
        RECT  61.2 0 61.224 0.084 ;
    END
  END esi_lo[177]
  PIN esi_lo[178]
    DIRECTION INPUT ;
    USE SIGNAL ;
    PORT
      LAYER M5 ;
        RECT  61.296 0 61.32 0.084 ;
    END
  END esi_lo[178]
  PIN esi_lo[179]
    DIRECTION INPUT ;
    USE SIGNAL ;
    PORT
      LAYER M5 ;
        RECT  61.392 0 61.416 0.084 ;
    END
  END esi_lo[179]
  PIN esi_lo[17]
    DIRECTION INPUT ;
    USE SIGNAL ;
    PORT
      LAYER M5 ;
        RECT  48.912 0 48.936 0.084 ;
    END
  END esi_lo[17]
  PIN esi_lo[180]
    DIRECTION INPUT ;
    USE SIGNAL ;
    PORT
      LAYER M5 ;
        RECT  61.488 0 61.512 0.084 ;
    END
  END esi_lo[180]
  PIN esi_lo[181]
    DIRECTION INPUT ;
    USE SIGNAL ;
    PORT
      LAYER M5 ;
        RECT  61.584 0 61.608 0.084 ;
    END
  END esi_lo[181]
  PIN esi_lo[182]
    DIRECTION INPUT ;
    USE SIGNAL ;
    PORT
      LAYER M5 ;
        RECT  61.68 0 61.704 0.084 ;
    END
  END esi_lo[182]
  PIN esi_lo[183]
    DIRECTION INPUT ;
    USE SIGNAL ;
    PORT
      LAYER M5 ;
        RECT  61.776 0 61.8 0.084 ;
    END
  END esi_lo[183]
  PIN esi_lo[184]
    DIRECTION INPUT ;
    USE SIGNAL ;
    PORT
      LAYER M5 ;
        RECT  61.872 0 61.896 0.084 ;
    END
  END esi_lo[184]
  PIN esi_lo[185]
    DIRECTION INPUT ;
    USE SIGNAL ;
    PORT
      LAYER M5 ;
        RECT  61.968 0 61.992 0.084 ;
    END
  END esi_lo[185]
  PIN esi_lo[186]
    DIRECTION INPUT ;
    USE SIGNAL ;
    PORT
      LAYER M5 ;
        RECT  62.064 0 62.088 0.084 ;
    END
  END esi_lo[186]
  PIN esi_lo[187]
    DIRECTION INPUT ;
    USE SIGNAL ;
    PORT
      LAYER M5 ;
        RECT  62.16 0 62.184 0.084 ;
    END
  END esi_lo[187]
  PIN esi_lo[188]
    DIRECTION INPUT ;
    USE SIGNAL ;
    PORT
      LAYER M5 ;
        RECT  62.256 0 62.28 0.084 ;
    END
  END esi_lo[188]
  PIN esi_lo[189]
    DIRECTION INPUT ;
    USE SIGNAL ;
    PORT
      LAYER M5 ;
        RECT  62.352 0 62.376 0.084 ;
    END
  END esi_lo[189]
  PIN esi_lo[18]
    DIRECTION INPUT ;
    USE SIGNAL ;
    PORT
      LAYER M5 ;
        RECT  49.008 0 49.032 0.084 ;
    END
  END esi_lo[18]
  PIN esi_lo[190]
    DIRECTION INPUT ;
    USE SIGNAL ;
    PORT
      LAYER M5 ;
        RECT  62.448 0 62.472 0.084 ;
    END
  END esi_lo[190]
  PIN esi_lo[191]
    DIRECTION INPUT ;
    USE SIGNAL ;
    PORT
      LAYER M5 ;
        RECT  62.544 0 62.568 0.084 ;
    END
  END esi_lo[191]
  PIN esi_lo[192]
    DIRECTION INPUT ;
    USE SIGNAL ;
    PORT
      LAYER M5 ;
        RECT  43.44 0 43.464 0.084 ;
    END
  END esi_lo[192]
  PIN esi_lo[193]
    DIRECTION INPUT ;
    USE SIGNAL ;
    PORT
      LAYER M5 ;
        RECT  43.536 0 43.56 0.084 ;
    END
  END esi_lo[193]
  PIN esi_lo[194]
    DIRECTION INPUT ;
    USE SIGNAL ;
    PORT
      LAYER M5 ;
        RECT  43.632 0 43.656 0.084 ;
    END
  END esi_lo[194]
  PIN esi_lo[195]
    DIRECTION INPUT ;
    USE SIGNAL ;
    PORT
      LAYER M5 ;
        RECT  43.728 0 43.752 0.084 ;
    END
  END esi_lo[195]
  PIN esi_lo[196]
    DIRECTION INPUT ;
    USE SIGNAL ;
    PORT
      LAYER M5 ;
        RECT  43.824 0 43.848 0.084 ;
    END
  END esi_lo[196]
  PIN esi_lo[197]
    DIRECTION INPUT ;
    USE SIGNAL ;
    PORT
      LAYER M5 ;
        RECT  43.92 0 43.944 0.084 ;
    END
  END esi_lo[197]
  PIN esi_lo[198]
    DIRECTION INPUT ;
    USE SIGNAL ;
    PORT
      LAYER M5 ;
        RECT  44.016 0 44.04 0.084 ;
    END
  END esi_lo[198]
  PIN esi_lo[199]
    DIRECTION INPUT ;
    USE SIGNAL ;
    PORT
      LAYER M5 ;
        RECT  44.112 0 44.136 0.084 ;
    END
  END esi_lo[199]
  PIN esi_lo[19]
    DIRECTION INPUT ;
    USE SIGNAL ;
    PORT
      LAYER M5 ;
        RECT  49.104 0 49.128 0.084 ;
    END
  END esi_lo[19]
  PIN esi_lo[1]
    DIRECTION INPUT ;
    USE SIGNAL ;
    PORT
      LAYER M5 ;
        RECT  47.376 0 47.4 0.084 ;
    END
  END esi_lo[1]
  PIN esi_lo[200]
    DIRECTION INPUT ;
    USE SIGNAL ;
    PORT
      LAYER M5 ;
        RECT  44.208 0 44.232 0.084 ;
    END
  END esi_lo[200]
  PIN esi_lo[201]
    DIRECTION INPUT ;
    USE SIGNAL ;
    PORT
      LAYER M5 ;
        RECT  44.304 0 44.328 0.084 ;
    END
  END esi_lo[201]
  PIN esi_lo[202]
    DIRECTION INPUT ;
    USE SIGNAL ;
    PORT
      LAYER M5 ;
        RECT  44.4 0 44.424 0.084 ;
    END
  END esi_lo[202]
  PIN esi_lo[203]
    DIRECTION INPUT ;
    USE SIGNAL ;
    PORT
      LAYER M5 ;
        RECT  44.496 0 44.52 0.084 ;
    END
  END esi_lo[203]
  PIN esi_lo[204]
    DIRECTION INPUT ;
    USE SIGNAL ;
    PORT
      LAYER M5 ;
        RECT  44.592 0 44.616 0.084 ;
    END
  END esi_lo[204]
  PIN esi_lo[205]
    DIRECTION INPUT ;
    USE SIGNAL ;
    PORT
      LAYER M5 ;
        RECT  44.688 0 44.712 0.084 ;
    END
  END esi_lo[205]
  PIN esi_lo[206]
    DIRECTION INPUT ;
    USE SIGNAL ;
    PORT
      LAYER M5 ;
        RECT  44.784 0 44.808 0.084 ;
    END
  END esi_lo[206]
  PIN esi_lo[207]
    DIRECTION INPUT ;
    USE SIGNAL ;
    PORT
      LAYER M5 ;
        RECT  44.88 0 44.904 0.084 ;
    END
  END esi_lo[207]
  PIN esi_lo[208]
    DIRECTION INPUT ;
    USE SIGNAL ;
    PORT
      LAYER M5 ;
        RECT  44.976 0 45 0.084 ;
    END
  END esi_lo[208]
  PIN esi_lo[209]
    DIRECTION INPUT ;
    USE SIGNAL ;
    PORT
      LAYER M5 ;
        RECT  45.072 0 45.096 0.084 ;
    END
  END esi_lo[209]
  PIN esi_lo[20]
    DIRECTION INPUT ;
    USE SIGNAL ;
    PORT
      LAYER M5 ;
        RECT  49.2 0 49.224 0.084 ;
    END
  END esi_lo[20]
  PIN esi_lo[210]
    DIRECTION INPUT ;
    USE SIGNAL ;
    PORT
      LAYER M5 ;
        RECT  45.168 0 45.192 0.084 ;
    END
  END esi_lo[210]
  PIN esi_lo[211]
    DIRECTION INPUT ;
    USE SIGNAL ;
    PORT
      LAYER M5 ;
        RECT  45.264 0 45.288 0.084 ;
    END
  END esi_lo[211]
  PIN esi_lo[212]
    DIRECTION INPUT ;
    USE SIGNAL ;
    PORT
      LAYER M5 ;
        RECT  45.36 0 45.384 0.084 ;
    END
  END esi_lo[212]
  PIN esi_lo[213]
    DIRECTION INPUT ;
    USE SIGNAL ;
    PORT
      LAYER M5 ;
        RECT  45.456 0 45.48 0.084 ;
    END
  END esi_lo[213]
  PIN esi_lo[214]
    DIRECTION INPUT ;
    USE SIGNAL ;
    PORT
      LAYER M5 ;
        RECT  45.552 0 45.576 0.084 ;
    END
  END esi_lo[214]
  PIN esi_lo[215]
    DIRECTION INPUT ;
    USE SIGNAL ;
    PORT
      LAYER M5 ;
        RECT  45.648 0 45.672 0.084 ;
    END
  END esi_lo[215]
  PIN esi_lo[216]
    DIRECTION INPUT ;
    USE SIGNAL ;
    PORT
      LAYER M5 ;
        RECT  45.744 0 45.768 0.084 ;
    END
  END esi_lo[216]
  PIN esi_lo[217]
    DIRECTION INPUT ;
    USE SIGNAL ;
    PORT
      LAYER M5 ;
        RECT  45.84 0 45.864 0.084 ;
    END
  END esi_lo[217]
  PIN esi_lo[218]
    DIRECTION INPUT ;
    USE SIGNAL ;
    PORT
      LAYER M5 ;
        RECT  45.936 0 45.96 0.084 ;
    END
  END esi_lo[218]
  PIN esi_lo[219]
    DIRECTION INPUT ;
    USE SIGNAL ;
    PORT
      LAYER M5 ;
        RECT  46.032 0 46.056 0.084 ;
    END
  END esi_lo[219]
  PIN esi_lo[21]
    DIRECTION INPUT ;
    USE SIGNAL ;
    PORT
      LAYER M5 ;
        RECT  49.296 0 49.32 0.084 ;
    END
  END esi_lo[21]
  PIN esi_lo[220]
    DIRECTION INPUT ;
    USE SIGNAL ;
    PORT
      LAYER M5 ;
        RECT  46.128 0 46.152 0.084 ;
    END
  END esi_lo[220]
  PIN esi_lo[221]
    DIRECTION INPUT ;
    USE SIGNAL ;
    PORT
      LAYER M5 ;
        RECT  46.224 0 46.248 0.084 ;
    END
  END esi_lo[221]
  PIN esi_lo[222]
    DIRECTION INPUT ;
    USE SIGNAL ;
    PORT
      LAYER M5 ;
        RECT  46.32 0 46.344 0.084 ;
    END
  END esi_lo[222]
  PIN esi_lo[223]
    DIRECTION INPUT ;
    USE SIGNAL ;
    PORT
      LAYER M5 ;
        RECT  46.416 0 46.44 0.084 ;
    END
  END esi_lo[223]
  PIN esi_lo[224]
    DIRECTION INPUT ;
    USE SIGNAL ;
    PORT
      LAYER M5 ;
        RECT  66.48 0 66.504 0.084 ;
    END
  END esi_lo[224]
  PIN esi_lo[225]
    DIRECTION INPUT ;
    USE SIGNAL ;
    PORT
      LAYER M5 ;
        RECT  66.576 0 66.6 0.084 ;
    END
  END esi_lo[225]
  PIN esi_lo[226]
    DIRECTION INPUT ;
    USE SIGNAL ;
    PORT
      LAYER M5 ;
        RECT  66.672 0 66.696 0.084 ;
    END
  END esi_lo[226]
  PIN esi_lo[227]
    DIRECTION INPUT ;
    USE SIGNAL ;
    PORT
      LAYER M5 ;
        RECT  66.768 0 66.792 0.084 ;
    END
  END esi_lo[227]
  PIN esi_lo[228]
    DIRECTION INPUT ;
    USE SIGNAL ;
    PORT
      LAYER M5 ;
        RECT  66.864 0 66.888 0.084 ;
    END
  END esi_lo[228]
  PIN esi_lo[229]
    DIRECTION INPUT ;
    USE SIGNAL ;
    PORT
      LAYER M5 ;
        RECT  66.96 0 66.984 0.084 ;
    END
  END esi_lo[229]
  PIN esi_lo[22]
    DIRECTION INPUT ;
    USE SIGNAL ;
    PORT
      LAYER M5 ;
        RECT  49.392 0 49.416 0.084 ;
    END
  END esi_lo[22]
  PIN esi_lo[230]
    DIRECTION INPUT ;
    USE SIGNAL ;
    PORT
      LAYER M5 ;
        RECT  67.056 0 67.08 0.084 ;
    END
  END esi_lo[230]
  PIN esi_lo[231]
    DIRECTION INPUT ;
    USE SIGNAL ;
    PORT
      LAYER M5 ;
        RECT  67.152 0 67.176 0.084 ;
    END
  END esi_lo[231]
  PIN esi_lo[232]
    DIRECTION INPUT ;
    USE SIGNAL ;
    PORT
      LAYER M5 ;
        RECT  67.248 0 67.272 0.084 ;
    END
  END esi_lo[232]
  PIN esi_lo[233]
    DIRECTION INPUT ;
    USE SIGNAL ;
    PORT
      LAYER M5 ;
        RECT  67.344 0 67.368 0.084 ;
    END
  END esi_lo[233]
  PIN esi_lo[234]
    DIRECTION INPUT ;
    USE SIGNAL ;
    PORT
      LAYER M5 ;
        RECT  67.44 0 67.464 0.084 ;
    END
  END esi_lo[234]
  PIN esi_lo[235]
    DIRECTION INPUT ;
    USE SIGNAL ;
    PORT
      LAYER M5 ;
        RECT  67.536 0 67.56 0.084 ;
    END
  END esi_lo[235]
  PIN esi_lo[236]
    DIRECTION INPUT ;
    USE SIGNAL ;
    PORT
      LAYER M5 ;
        RECT  67.632 0 67.656 0.084 ;
    END
  END esi_lo[236]
  PIN esi_lo[237]
    DIRECTION INPUT ;
    USE SIGNAL ;
    PORT
      LAYER M5 ;
        RECT  67.728 0 67.752 0.084 ;
    END
  END esi_lo[237]
  PIN esi_lo[238]
    DIRECTION INPUT ;
    USE SIGNAL ;
    PORT
      LAYER M5 ;
        RECT  67.824 0 67.848 0.084 ;
    END
  END esi_lo[238]
  PIN esi_lo[239]
    DIRECTION INPUT ;
    USE SIGNAL ;
    PORT
      LAYER M5 ;
        RECT  67.92 0 67.944 0.084 ;
    END
  END esi_lo[239]
  PIN esi_lo[23]
    DIRECTION INPUT ;
    USE SIGNAL ;
    PORT
      LAYER M5 ;
        RECT  49.488 0 49.512 0.084 ;
    END
  END esi_lo[23]
  PIN esi_lo[240]
    DIRECTION INPUT ;
    USE SIGNAL ;
    PORT
      LAYER M5 ;
        RECT  68.016 0 68.04 0.084 ;
    END
  END esi_lo[240]
  PIN esi_lo[241]
    DIRECTION INPUT ;
    USE SIGNAL ;
    PORT
      LAYER M5 ;
        RECT  68.112 0 68.136 0.084 ;
    END
  END esi_lo[241]
  PIN esi_lo[242]
    DIRECTION INPUT ;
    USE SIGNAL ;
    PORT
      LAYER M5 ;
        RECT  68.208 0 68.232 0.084 ;
    END
  END esi_lo[242]
  PIN esi_lo[243]
    DIRECTION INPUT ;
    USE SIGNAL ;
    PORT
      LAYER M5 ;
        RECT  68.304 0 68.328 0.084 ;
    END
  END esi_lo[243]
  PIN esi_lo[244]
    DIRECTION INPUT ;
    USE SIGNAL ;
    PORT
      LAYER M5 ;
        RECT  68.4 0 68.424 0.084 ;
    END
  END esi_lo[244]
  PIN esi_lo[245]
    DIRECTION INPUT ;
    USE SIGNAL ;
    PORT
      LAYER M5 ;
        RECT  68.496 0 68.52 0.084 ;
    END
  END esi_lo[245]
  PIN esi_lo[246]
    DIRECTION INPUT ;
    USE SIGNAL ;
    PORT
      LAYER M5 ;
        RECT  68.592 0 68.616 0.084 ;
    END
  END esi_lo[246]
  PIN esi_lo[247]
    DIRECTION INPUT ;
    USE SIGNAL ;
    PORT
      LAYER M5 ;
        RECT  68.688 0 68.712 0.084 ;
    END
  END esi_lo[247]
  PIN esi_lo[248]
    DIRECTION INPUT ;
    USE SIGNAL ;
    PORT
      LAYER M5 ;
        RECT  68.784 0 68.808 0.084 ;
    END
  END esi_lo[248]
  PIN esi_lo[249]
    DIRECTION INPUT ;
    USE SIGNAL ;
    PORT
      LAYER M5 ;
        RECT  68.88 0 68.904 0.084 ;
    END
  END esi_lo[249]
  PIN esi_lo[24]
    DIRECTION INPUT ;
    USE SIGNAL ;
    PORT
      LAYER M5 ;
        RECT  49.584 0 49.608 0.084 ;
    END
  END esi_lo[24]
  PIN esi_lo[250]
    DIRECTION INPUT ;
    USE SIGNAL ;
    PORT
      LAYER M5 ;
        RECT  68.976 0 69 0.084 ;
    END
  END esi_lo[250]
  PIN esi_lo[251]
    DIRECTION INPUT ;
    USE SIGNAL ;
    PORT
      LAYER M5 ;
        RECT  69.072 0 69.096 0.084 ;
    END
  END esi_lo[251]
  PIN esi_lo[252]
    DIRECTION INPUT ;
    USE SIGNAL ;
    PORT
      LAYER M5 ;
        RECT  69.168 0 69.192 0.084 ;
    END
  END esi_lo[252]
  PIN esi_lo[253]
    DIRECTION INPUT ;
    USE SIGNAL ;
    PORT
      LAYER M5 ;
        RECT  69.264 0 69.288 0.084 ;
    END
  END esi_lo[253]
  PIN esi_lo[254]
    DIRECTION INPUT ;
    USE SIGNAL ;
    PORT
      LAYER M5 ;
        RECT  69.36 0 69.384 0.084 ;
    END
  END esi_lo[254]
  PIN esi_lo[255]
    DIRECTION INPUT ;
    USE SIGNAL ;
    PORT
      LAYER M5 ;
        RECT  69.456 0 69.48 0.084 ;
    END
  END esi_lo[255]
  PIN esi_lo[25]
    DIRECTION INPUT ;
    USE SIGNAL ;
    PORT
      LAYER M5 ;
        RECT  49.68 0 49.704 0.084 ;
    END
  END esi_lo[25]
  PIN esi_lo[26]
    DIRECTION INPUT ;
    USE SIGNAL ;
    PORT
      LAYER M5 ;
        RECT  49.776 0 49.8 0.084 ;
    END
  END esi_lo[26]
  PIN esi_lo[27]
    DIRECTION INPUT ;
    USE SIGNAL ;
    PORT
      LAYER M5 ;
        RECT  49.872 0 49.896 0.084 ;
    END
  END esi_lo[27]
  PIN esi_lo[28]
    DIRECTION INPUT ;
    USE SIGNAL ;
    PORT
      LAYER M5 ;
        RECT  49.968 0 49.992 0.084 ;
    END
  END esi_lo[28]
  PIN esi_lo[29]
    DIRECTION INPUT ;
    USE SIGNAL ;
    PORT
      LAYER M5 ;
        RECT  50.064 0 50.088 0.084 ;
    END
  END esi_lo[29]
  PIN esi_lo[2]
    DIRECTION INPUT ;
    USE SIGNAL ;
    PORT
      LAYER M5 ;
        RECT  47.472 0 47.496 0.084 ;
    END
  END esi_lo[2]
  PIN esi_lo[30]
    DIRECTION INPUT ;
    USE SIGNAL ;
    PORT
      LAYER M5 ;
        RECT  50.16 0 50.184 0.084 ;
    END
  END esi_lo[30]
  PIN esi_lo[31]
    DIRECTION INPUT ;
    USE SIGNAL ;
    PORT
      LAYER M5 ;
        RECT  50.256 0 50.28 0.084 ;
    END
  END esi_lo[31]
  PIN esi_lo[32]
    DIRECTION INPUT ;
    USE SIGNAL ;
    PORT
      LAYER M5 ;
        RECT  62.64 0 62.664 0.084 ;
    END
  END esi_lo[32]
  PIN esi_lo[33]
    DIRECTION INPUT ;
    USE SIGNAL ;
    PORT
      LAYER M5 ;
        RECT  62.736 0 62.76 0.084 ;
    END
  END esi_lo[33]
  PIN esi_lo[34]
    DIRECTION INPUT ;
    USE SIGNAL ;
    PORT
      LAYER M5 ;
        RECT  62.832 0 62.856 0.084 ;
    END
  END esi_lo[34]
  PIN esi_lo[35]
    DIRECTION INPUT ;
    USE SIGNAL ;
    PORT
      LAYER M5 ;
        RECT  62.928 0 62.952 0.084 ;
    END
  END esi_lo[35]
  PIN esi_lo[36]
    DIRECTION INPUT ;
    USE SIGNAL ;
    PORT
      LAYER M5 ;
        RECT  63.024 0 63.048 0.084 ;
    END
  END esi_lo[36]
  PIN esi_lo[37]
    DIRECTION INPUT ;
    USE SIGNAL ;
    PORT
      LAYER M5 ;
        RECT  63.12 0 63.144 0.084 ;
    END
  END esi_lo[37]
  PIN esi_lo[38]
    DIRECTION INPUT ;
    USE SIGNAL ;
    PORT
      LAYER M5 ;
        RECT  63.216 0 63.24 0.084 ;
    END
  END esi_lo[38]
  PIN esi_lo[39]
    DIRECTION INPUT ;
    USE SIGNAL ;
    PORT
      LAYER M5 ;
        RECT  63.312 0 63.336 0.084 ;
    END
  END esi_lo[39]
  PIN esi_lo[3]
    DIRECTION INPUT ;
    USE SIGNAL ;
    PORT
      LAYER M5 ;
        RECT  47.568 0 47.592 0.084 ;
    END
  END esi_lo[3]
  PIN esi_lo[40]
    DIRECTION INPUT ;
    USE SIGNAL ;
    PORT
      LAYER M5 ;
        RECT  63.408 0 63.432 0.084 ;
    END
  END esi_lo[40]
  PIN esi_lo[41]
    DIRECTION INPUT ;
    USE SIGNAL ;
    PORT
      LAYER M5 ;
        RECT  63.504 0 63.528 0.084 ;
    END
  END esi_lo[41]
  PIN esi_lo[42]
    DIRECTION INPUT ;
    USE SIGNAL ;
    PORT
      LAYER M5 ;
        RECT  63.6 0 63.624 0.084 ;
    END
  END esi_lo[42]
  PIN esi_lo[43]
    DIRECTION INPUT ;
    USE SIGNAL ;
    PORT
      LAYER M5 ;
        RECT  63.696 0 63.72 0.084 ;
    END
  END esi_lo[43]
  PIN esi_lo[44]
    DIRECTION INPUT ;
    USE SIGNAL ;
    PORT
      LAYER M5 ;
        RECT  63.792 0 63.816 0.084 ;
    END
  END esi_lo[44]
  PIN esi_lo[45]
    DIRECTION INPUT ;
    USE SIGNAL ;
    PORT
      LAYER M5 ;
        RECT  63.888 0 63.912 0.084 ;
    END
  END esi_lo[45]
  PIN esi_lo[46]
    DIRECTION INPUT ;
    USE SIGNAL ;
    PORT
      LAYER M5 ;
        RECT  63.984 0 64.008 0.084 ;
    END
  END esi_lo[46]
  PIN esi_lo[47]
    DIRECTION INPUT ;
    USE SIGNAL ;
    PORT
      LAYER M5 ;
        RECT  64.08 0 64.104 0.084 ;
    END
  END esi_lo[47]
  PIN esi_lo[48]
    DIRECTION INPUT ;
    USE SIGNAL ;
    PORT
      LAYER M5 ;
        RECT  64.176 0 64.2 0.084 ;
    END
  END esi_lo[48]
  PIN esi_lo[49]
    DIRECTION INPUT ;
    USE SIGNAL ;
    PORT
      LAYER M5 ;
        RECT  64.272 0 64.296 0.084 ;
    END
  END esi_lo[49]
  PIN esi_lo[4]
    DIRECTION INPUT ;
    USE SIGNAL ;
    PORT
      LAYER M5 ;
        RECT  47.664 0 47.688 0.084 ;
    END
  END esi_lo[4]
  PIN esi_lo[50]
    DIRECTION INPUT ;
    USE SIGNAL ;
    PORT
      LAYER M5 ;
        RECT  64.368 0 64.392 0.084 ;
    END
  END esi_lo[50]
  PIN esi_lo[51]
    DIRECTION INPUT ;
    USE SIGNAL ;
    PORT
      LAYER M5 ;
        RECT  64.464 0 64.488 0.084 ;
    END
  END esi_lo[51]
  PIN esi_lo[52]
    DIRECTION INPUT ;
    USE SIGNAL ;
    PORT
      LAYER M5 ;
        RECT  64.56 0 64.584 0.084 ;
    END
  END esi_lo[52]
  PIN esi_lo[53]
    DIRECTION INPUT ;
    USE SIGNAL ;
    PORT
      LAYER M5 ;
        RECT  64.656 0 64.68 0.084 ;
    END
  END esi_lo[53]
  PIN esi_lo[54]
    DIRECTION INPUT ;
    USE SIGNAL ;
    PORT
      LAYER M5 ;
        RECT  64.752 0 64.776 0.084 ;
    END
  END esi_lo[54]
  PIN esi_lo[55]
    DIRECTION INPUT ;
    USE SIGNAL ;
    PORT
      LAYER M5 ;
        RECT  64.848 0 64.872 0.084 ;
    END
  END esi_lo[55]
  PIN esi_lo[56]
    DIRECTION INPUT ;
    USE SIGNAL ;
    PORT
      LAYER M5 ;
        RECT  64.944 0 64.968 0.084 ;
    END
  END esi_lo[56]
  PIN esi_lo[57]
    DIRECTION INPUT ;
    USE SIGNAL ;
    PORT
      LAYER M5 ;
        RECT  65.04 0 65.064 0.084 ;
    END
  END esi_lo[57]
  PIN esi_lo[58]
    DIRECTION INPUT ;
    USE SIGNAL ;
    PORT
      LAYER M5 ;
        RECT  65.136 0 65.16 0.084 ;
    END
  END esi_lo[58]
  PIN esi_lo[59]
    DIRECTION INPUT ;
    USE SIGNAL ;
    PORT
      LAYER M5 ;
        RECT  65.232 0 65.256 0.084 ;
    END
  END esi_lo[59]
  PIN esi_lo[5]
    DIRECTION INPUT ;
    USE SIGNAL ;
    PORT
      LAYER M5 ;
        RECT  47.76 0 47.784 0.084 ;
    END
  END esi_lo[5]
  PIN esi_lo[60]
    DIRECTION INPUT ;
    USE SIGNAL ;
    PORT
      LAYER M5 ;
        RECT  65.328 0 65.352 0.084 ;
    END
  END esi_lo[60]
  PIN esi_lo[61]
    DIRECTION INPUT ;
    USE SIGNAL ;
    PORT
      LAYER M5 ;
        RECT  65.424 0 65.448 0.084 ;
    END
  END esi_lo[61]
  PIN esi_lo[62]
    DIRECTION INPUT ;
    USE SIGNAL ;
    PORT
      LAYER M5 ;
        RECT  65.52 0 65.544 0.084 ;
    END
  END esi_lo[62]
  PIN esi_lo[63]
    DIRECTION INPUT ;
    USE SIGNAL ;
    PORT
      LAYER M5 ;
        RECT  65.616 0 65.64 0.084 ;
    END
  END esi_lo[63]
  PIN esi_lo[64]
    DIRECTION INPUT ;
    USE SIGNAL ;
    PORT
      LAYER M5 ;
        RECT  53.424 0 53.448 0.084 ;
    END
  END esi_lo[64]
  PIN esi_lo[65]
    DIRECTION INPUT ;
    USE SIGNAL ;
    PORT
      LAYER M5 ;
        RECT  53.52 0 53.544 0.084 ;
    END
  END esi_lo[65]
  PIN esi_lo[66]
    DIRECTION INPUT ;
    USE SIGNAL ;
    PORT
      LAYER M5 ;
        RECT  53.616 0 53.64 0.084 ;
    END
  END esi_lo[66]
  PIN esi_lo[67]
    DIRECTION INPUT ;
    USE SIGNAL ;
    PORT
      LAYER M5 ;
        RECT  53.712 0 53.736 0.084 ;
    END
  END esi_lo[67]
  PIN esi_lo[68]
    DIRECTION INPUT ;
    USE SIGNAL ;
    PORT
      LAYER M5 ;
        RECT  53.808 0 53.832 0.084 ;
    END
  END esi_lo[68]
  PIN esi_lo[69]
    DIRECTION INPUT ;
    USE SIGNAL ;
    PORT
      LAYER M5 ;
        RECT  53.904 0 53.928 0.084 ;
    END
  END esi_lo[69]
  PIN esi_lo[6]
    DIRECTION INPUT ;
    USE SIGNAL ;
    PORT
      LAYER M5 ;
        RECT  47.856 0 47.88 0.084 ;
    END
  END esi_lo[6]
  PIN esi_lo[70]
    DIRECTION INPUT ;
    USE SIGNAL ;
    PORT
      LAYER M5 ;
        RECT  54 0 54.024 0.084 ;
    END
  END esi_lo[70]
  PIN esi_lo[71]
    DIRECTION INPUT ;
    USE SIGNAL ;
    PORT
      LAYER M5 ;
        RECT  54.096 0 54.12 0.084 ;
    END
  END esi_lo[71]
  PIN esi_lo[72]
    DIRECTION INPUT ;
    USE SIGNAL ;
    PORT
      LAYER M5 ;
        RECT  54.192 0 54.216 0.084 ;
    END
  END esi_lo[72]
  PIN esi_lo[73]
    DIRECTION INPUT ;
    USE SIGNAL ;
    PORT
      LAYER M5 ;
        RECT  54.288 0 54.312 0.084 ;
    END
  END esi_lo[73]
  PIN esi_lo[74]
    DIRECTION INPUT ;
    USE SIGNAL ;
    PORT
      LAYER M5 ;
        RECT  54.384 0 54.408 0.084 ;
    END
  END esi_lo[74]
  PIN esi_lo[75]
    DIRECTION INPUT ;
    USE SIGNAL ;
    PORT
      LAYER M5 ;
        RECT  54.48 0 54.504 0.084 ;
    END
  END esi_lo[75]
  PIN esi_lo[76]
    DIRECTION INPUT ;
    USE SIGNAL ;
    PORT
      LAYER M5 ;
        RECT  54.576 0 54.6 0.084 ;
    END
  END esi_lo[76]
  PIN esi_lo[77]
    DIRECTION INPUT ;
    USE SIGNAL ;
    PORT
      LAYER M5 ;
        RECT  54.672 0 54.696 0.084 ;
    END
  END esi_lo[77]
  PIN esi_lo[78]
    DIRECTION INPUT ;
    USE SIGNAL ;
    PORT
      LAYER M5 ;
        RECT  54.768 0 54.792 0.084 ;
    END
  END esi_lo[78]
  PIN esi_lo[79]
    DIRECTION INPUT ;
    USE SIGNAL ;
    PORT
      LAYER M5 ;
        RECT  54.864 0 54.888 0.084 ;
    END
  END esi_lo[79]
  PIN esi_lo[7]
    DIRECTION INPUT ;
    USE SIGNAL ;
    PORT
      LAYER M5 ;
        RECT  47.952 0 47.976 0.084 ;
    END
  END esi_lo[7]
  PIN esi_lo[80]
    DIRECTION INPUT ;
    USE SIGNAL ;
    PORT
      LAYER M5 ;
        RECT  54.96 0 54.984 0.084 ;
    END
  END esi_lo[80]
  PIN esi_lo[81]
    DIRECTION INPUT ;
    USE SIGNAL ;
    PORT
      LAYER M5 ;
        RECT  55.056 0 55.08 0.084 ;
    END
  END esi_lo[81]
  PIN esi_lo[82]
    DIRECTION INPUT ;
    USE SIGNAL ;
    PORT
      LAYER M5 ;
        RECT  55.152 0 55.176 0.084 ;
    END
  END esi_lo[82]
  PIN esi_lo[83]
    DIRECTION INPUT ;
    USE SIGNAL ;
    PORT
      LAYER M5 ;
        RECT  55.248 0 55.272 0.084 ;
    END
  END esi_lo[83]
  PIN esi_lo[84]
    DIRECTION INPUT ;
    USE SIGNAL ;
    PORT
      LAYER M5 ;
        RECT  55.344 0 55.368 0.084 ;
    END
  END esi_lo[84]
  PIN esi_lo[85]
    DIRECTION INPUT ;
    USE SIGNAL ;
    PORT
      LAYER M5 ;
        RECT  55.44 0 55.464 0.084 ;
    END
  END esi_lo[85]
  PIN esi_lo[86]
    DIRECTION INPUT ;
    USE SIGNAL ;
    PORT
      LAYER M5 ;
        RECT  55.536 0 55.56 0.084 ;
    END
  END esi_lo[86]
  PIN esi_lo[87]
    DIRECTION INPUT ;
    USE SIGNAL ;
    PORT
      LAYER M5 ;
        RECT  55.632 0 55.656 0.084 ;
    END
  END esi_lo[87]
  PIN esi_lo[88]
    DIRECTION INPUT ;
    USE SIGNAL ;
    PORT
      LAYER M5 ;
        RECT  55.728 0 55.752 0.084 ;
    END
  END esi_lo[88]
  PIN esi_lo[89]
    DIRECTION INPUT ;
    USE SIGNAL ;
    PORT
      LAYER M5 ;
        RECT  55.824 0 55.848 0.084 ;
    END
  END esi_lo[89]
  PIN esi_lo[8]
    DIRECTION INPUT ;
    USE SIGNAL ;
    PORT
      LAYER M5 ;
        RECT  48.048 0 48.072 0.084 ;
    END
  END esi_lo[8]
  PIN esi_lo[90]
    DIRECTION INPUT ;
    USE SIGNAL ;
    PORT
      LAYER M5 ;
        RECT  55.92 0 55.944 0.084 ;
    END
  END esi_lo[90]
  PIN esi_lo[91]
    DIRECTION INPUT ;
    USE SIGNAL ;
    PORT
      LAYER M5 ;
        RECT  56.016 0 56.04 0.084 ;
    END
  END esi_lo[91]
  PIN esi_lo[92]
    DIRECTION INPUT ;
    USE SIGNAL ;
    PORT
      LAYER M5 ;
        RECT  56.112 0 56.136 0.084 ;
    END
  END esi_lo[92]
  PIN esi_lo[93]
    DIRECTION INPUT ;
    USE SIGNAL ;
    PORT
      LAYER M5 ;
        RECT  56.208 0 56.232 0.084 ;
    END
  END esi_lo[93]
  PIN esi_lo[94]
    DIRECTION INPUT ;
    USE SIGNAL ;
    PORT
      LAYER M5 ;
        RECT  56.304 0 56.328 0.084 ;
    END
  END esi_lo[94]
  PIN esi_lo[95]
    DIRECTION INPUT ;
    USE SIGNAL ;
    PORT
      LAYER M5 ;
        RECT  56.4 0 56.424 0.084 ;
    END
  END esi_lo[95]
  PIN esi_lo[96]
    DIRECTION INPUT ;
    USE SIGNAL ;
    PORT
      LAYER M5 ;
        RECT  56.496 0 56.52 0.084 ;
    END
  END esi_lo[96]
  PIN esi_lo[97]
    DIRECTION INPUT ;
    USE SIGNAL ;
    PORT
      LAYER M5 ;
        RECT  56.592 0 56.616 0.084 ;
    END
  END esi_lo[97]
  PIN esi_lo[98]
    DIRECTION INPUT ;
    USE SIGNAL ;
    PORT
      LAYER M5 ;
        RECT  56.688 0 56.712 0.084 ;
    END
  END esi_lo[98]
  PIN esi_lo[99]
    DIRECTION INPUT ;
    USE SIGNAL ;
    PORT
      LAYER M5 ;
        RECT  56.784 0 56.808 0.084 ;
    END
  END esi_lo[99]
  PIN esi_lo[9]
    DIRECTION INPUT ;
    USE SIGNAL ;
    PORT
      LAYER M5 ;
        RECT  48.144 0 48.168 0.084 ;
    END
  END esi_lo[9]
  PIN eso_v_hi[0]
    DIRECTION INPUT ;
    USE SIGNAL ;
    PORT
      LAYER M5 ;
        RECT  2.16 47.436 2.184 47.52 ;
    END
  END eso_v_hi[0]
  PIN eso_v_hi[1]
    DIRECTION INPUT ;
    USE SIGNAL ;
    PORT
      LAYER M5 ;
        RECT  2.256 47.436 2.28 47.52 ;
    END
  END eso_v_hi[1]
  PIN eso_v_hi[2]
    DIRECTION INPUT ;
    USE SIGNAL ;
    PORT
      LAYER M5 ;
        RECT  2.352 47.436 2.376 47.52 ;
    END
  END eso_v_hi[2]
  PIN eso_v_hi[3]
    DIRECTION INPUT ;
    USE SIGNAL ;
    PORT
      LAYER M5 ;
        RECT  2.448 47.436 2.472 47.52 ;
    END
  END eso_v_hi[3]
  PIN eso_v_lo[0]
    DIRECTION INPUT ;
    USE SIGNAL ;
    PORT
      LAYER M5 ;
        RECT  1.872 0 1.896 0.084 ;
    END
  END eso_v_lo[0]
  PIN eso_v_lo[1]
    DIRECTION INPUT ;
    USE SIGNAL ;
    PORT
      LAYER M5 ;
        RECT  1.968 0 1.992 0.084 ;
    END
  END eso_v_lo[1]
  PIN eso_v_lo[2]
    DIRECTION INPUT ;
    USE SIGNAL ;
    PORT
      LAYER M5 ;
        RECT  2.064 0 2.088 0.084 ;
    END
  END eso_v_lo[2]
  PIN eso_v_lo[3]
    DIRECTION INPUT ;
    USE SIGNAL ;
    PORT
      LAYER M5 ;
        RECT  2.16 0 2.184 0.084 ;
    END
  END eso_v_lo[3]
  PIN fault
    DIRECTION OUTPUT ;
    USE SIGNAL ;
    PORT
      LAYER M4 ;
        RECT  0 45.744 0.084 45.768 ;
    END
    PORT
      LAYER M4 ;
        RECT  0.06 45.744 2.149 45.768 ;
    END
  END fault
  PIN read_addr[0]
    DIRECTION INPUT ;
    USE SIGNAL ;
    PORT
      LAYER M4 ;
        RECT  0 18.96 0.084 18.984 ;
    END
  END read_addr[0]
  PIN read_addr[10]
    DIRECTION INPUT ;
    USE SIGNAL ;
    PORT
      LAYER M4 ;
        RECT  0 19.92 0.084 19.944 ;
    END
  END read_addr[10]
  PIN read_addr[11]
    DIRECTION INPUT ;
    USE SIGNAL ;
    PORT
      LAYER M4 ;
        RECT  0 20.016 0.084 20.04 ;
    END
  END read_addr[11]
  PIN read_addr[12]
    DIRECTION INPUT ;
    USE SIGNAL ;
    PORT
      LAYER M4 ;
        RECT  0 20.112 0.084 20.136 ;
    END
  END read_addr[12]
  PIN read_addr[13]
    DIRECTION INPUT ;
    USE SIGNAL ;
    PORT
      LAYER M4 ;
        RECT  0 20.208 0.084 20.232 ;
    END
  END read_addr[13]
  PIN read_addr[14]
    DIRECTION INPUT ;
    USE SIGNAL ;
    PORT
      LAYER M4 ;
        RECT  0 20.304 0.084 20.328 ;
    END
  END read_addr[14]
  PIN read_addr[15]
    DIRECTION INPUT ;
    USE SIGNAL ;
    PORT
      LAYER M4 ;
        RECT  0 20.4 0.084 20.424 ;
    END
  END read_addr[15]
  PIN read_addr[16]
    DIRECTION INPUT ;
    USE SIGNAL ;
    PORT
      LAYER M4 ;
        RECT  0 20.496 0.084 20.52 ;
    END
  END read_addr[16]
  PIN read_addr[17]
    DIRECTION INPUT ;
    USE SIGNAL ;
    PORT
      LAYER M4 ;
        RECT  0 20.592 0.084 20.616 ;
    END
  END read_addr[17]
  PIN read_addr[18]
    DIRECTION INPUT ;
    USE SIGNAL ;
    PORT
      LAYER M4 ;
        RECT  0 20.688 0.084 20.712 ;
    END
  END read_addr[18]
  PIN read_addr[19]
    DIRECTION INPUT ;
    USE SIGNAL ;
    PORT
      LAYER M4 ;
        RECT  0 20.784 0.084 20.808 ;
    END
  END read_addr[19]
  PIN read_addr[1]
    DIRECTION INPUT ;
    USE SIGNAL ;
    PORT
      LAYER M4 ;
        RECT  0 19.056 0.084 19.08 ;
    END
  END read_addr[1]
  PIN read_addr[20]
    DIRECTION INPUT ;
    USE SIGNAL ;
    PORT
      LAYER M4 ;
        RECT  0 20.88 0.084 20.904 ;
    END
  END read_addr[20]
  PIN read_addr[21]
    DIRECTION INPUT ;
    USE SIGNAL ;
    PORT
      LAYER M4 ;
        RECT  0 20.976 0.084 21 ;
    END
  END read_addr[21]
  PIN read_addr[22]
    DIRECTION INPUT ;
    USE SIGNAL ;
    PORT
      LAYER M4 ;
        RECT  0 21.072 0.084 21.096 ;
    END
  END read_addr[22]
  PIN read_addr[23]
    DIRECTION INPUT ;
    USE SIGNAL ;
    PORT
      LAYER M4 ;
        RECT  0 21.168 0.084 21.192 ;
    END
  END read_addr[23]
  PIN read_addr[24]
    DIRECTION INPUT ;
    USE SIGNAL ;
    PORT
      LAYER M4 ;
        RECT  0 21.264 0.084 21.288 ;
    END
  END read_addr[24]
  PIN read_addr[25]
    DIRECTION INPUT ;
    USE SIGNAL ;
    PORT
      LAYER M4 ;
        RECT  0 21.36 0.084 21.384 ;
    END
  END read_addr[25]
  PIN read_addr[26]
    DIRECTION INPUT ;
    USE SIGNAL ;
    PORT
      LAYER M4 ;
        RECT  0 21.456 0.084 21.48 ;
    END
  END read_addr[26]
  PIN read_addr[27]
    DIRECTION INPUT ;
    USE SIGNAL ;
    PORT
      LAYER M4 ;
        RECT  0 21.552 0.084 21.576 ;
    END
  END read_addr[27]
  PIN read_addr[28]
    DIRECTION INPUT ;
    USE SIGNAL ;
    PORT
      LAYER M4 ;
        RECT  0 21.648 0.084 21.672 ;
    END
  END read_addr[28]
  PIN read_addr[29]
    DIRECTION INPUT ;
    USE SIGNAL ;
    PORT
      LAYER M4 ;
        RECT  0 21.744 0.084 21.768 ;
    END
  END read_addr[29]
  PIN read_addr[2]
    DIRECTION INPUT ;
    USE SIGNAL ;
    PORT
      LAYER M4 ;
        RECT  0 19.152 0.084 19.176 ;
    END
  END read_addr[2]
  PIN read_addr[30]
    DIRECTION INPUT ;
    USE SIGNAL ;
    PORT
      LAYER M4 ;
        RECT  0 21.84 0.084 21.864 ;
    END
  END read_addr[30]
  PIN read_addr[31]
    DIRECTION INPUT ;
    USE SIGNAL ;
    PORT
      LAYER M4 ;
        RECT  0 21.936 0.084 21.96 ;
    END
  END read_addr[31]
  PIN read_addr[32]
    DIRECTION INPUT ;
    USE SIGNAL ;
    PORT
      LAYER M4 ;
        RECT  0 17.808 0.084 17.832 ;
    END
  END read_addr[32]
  PIN read_addr[33]
    DIRECTION INPUT ;
    USE SIGNAL ;
    PORT
      LAYER M4 ;
        RECT  0 17.904 0.084 17.928 ;
    END
  END read_addr[33]
  PIN read_addr[34]
    DIRECTION INPUT ;
    USE SIGNAL ;
    PORT
      LAYER M4 ;
        RECT  0 18 0.084 18.024 ;
    END
  END read_addr[34]
  PIN read_addr[35]
    DIRECTION INPUT ;
    USE SIGNAL ;
    PORT
      LAYER M4 ;
        RECT  0 18.096 0.084 18.12 ;
    END
  END read_addr[35]
  PIN read_addr[36]
    DIRECTION INPUT ;
    USE SIGNAL ;
    PORT
      LAYER M4 ;
        RECT  0 18.192 0.084 18.216 ;
    END
  END read_addr[36]
  PIN read_addr[37]
    DIRECTION INPUT ;
    USE SIGNAL ;
    PORT
      LAYER M4 ;
        RECT  0 18.288 0.084 18.312 ;
    END
  END read_addr[37]
  PIN read_addr[38]
    DIRECTION INPUT ;
    USE SIGNAL ;
    PORT
      LAYER M4 ;
        RECT  0 18.384 0.084 18.408 ;
    END
  END read_addr[38]
  PIN read_addr[39]
    DIRECTION INPUT ;
    USE SIGNAL ;
    PORT
      LAYER M4 ;
        RECT  0 18.48 0.084 18.504 ;
    END
  END read_addr[39]
  PIN read_addr[3]
    DIRECTION INPUT ;
    USE SIGNAL ;
    PORT
      LAYER M4 ;
        RECT  0 19.248 0.084 19.272 ;
    END
  END read_addr[3]
  PIN read_addr[40]
    DIRECTION INPUT ;
    USE SIGNAL ;
    PORT
      LAYER M4 ;
        RECT  0 18.576 0.084 18.6 ;
    END
  END read_addr[40]
  PIN read_addr[41]
    DIRECTION INPUT ;
    USE SIGNAL ;
    PORT
      LAYER M4 ;
        RECT  0 18.672 0.084 18.696 ;
    END
  END read_addr[41]
  PIN read_addr[42]
    DIRECTION INPUT ;
    USE SIGNAL ;
    PORT
      LAYER M4 ;
        RECT  0 18.768 0.084 18.792 ;
    END
  END read_addr[42]
  PIN read_addr[43]
    DIRECTION INPUT ;
    USE SIGNAL ;
    PORT
      LAYER M4 ;
        RECT  0 18.864 0.084 18.888 ;
    END
  END read_addr[43]
  PIN read_addr[4]
    DIRECTION INPUT ;
    USE SIGNAL ;
    PORT
      LAYER M4 ;
        RECT  0 19.344 0.084 19.368 ;
    END
  END read_addr[4]
  PIN read_addr[5]
    DIRECTION INPUT ;
    USE SIGNAL ;
    PORT
      LAYER M4 ;
        RECT  0 19.44 0.084 19.464 ;
    END
  END read_addr[5]
  PIN read_addr[6]
    DIRECTION INPUT ;
    USE SIGNAL ;
    PORT
      LAYER M4 ;
        RECT  0 19.536 0.084 19.56 ;
    END
  END read_addr[6]
  PIN read_addr[7]
    DIRECTION INPUT ;
    USE SIGNAL ;
    PORT
      LAYER M4 ;
        RECT  0 19.632 0.084 19.656 ;
    END
  END read_addr[7]
  PIN read_addr[8]
    DIRECTION INPUT ;
    USE SIGNAL ;
    PORT
      LAYER M4 ;
        RECT  0 19.728 0.084 19.752 ;
    END
  END read_addr[8]
  PIN read_addr[9]
    DIRECTION INPUT ;
    USE SIGNAL ;
    PORT
      LAYER M4 ;
        RECT  0 19.824 0.084 19.848 ;
    END
  END read_addr[9]
  PIN read_v[0]
    DIRECTION INPUT ;
    USE SIGNAL ;
    PORT
      LAYER M4 ;
        RECT  0 2.64 0.084 2.664 ;
    END
  END read_v[0]
  PIN read_v[1]
    DIRECTION INPUT ;
    USE SIGNAL ;
    PORT
      LAYER M4 ;
        RECT  0 2.736 0.084 2.76 ;
    END
  END read_v[1]
  PIN read_v[2]
    DIRECTION INPUT ;
    USE SIGNAL ;
    PORT
      LAYER M4 ;
        RECT  0 2.832 0.084 2.856 ;
    END
  END read_v[2]
  PIN read_v[3]
    DIRECTION INPUT ;
    USE SIGNAL ;
    PORT
      LAYER M4 ;
        RECT  0 2.928 0.084 2.952 ;
    END
  END read_v[3]
  PIN response_addr[0]
    DIRECTION OUTPUT ;
    USE SIGNAL ;
    PORT
      LAYER M4 ;
        RECT  0 27.024 0.084 27.048 ;
    END
  END response_addr[0]
  PIN response_addr[10]
    DIRECTION OUTPUT ;
    USE SIGNAL ;
    PORT
      LAYER M4 ;
        RECT  0 27.984 0.084 28.008 ;
    END
  END response_addr[10]
  PIN response_addr[11]
    DIRECTION OUTPUT ;
    USE SIGNAL ;
    PORT
      LAYER M4 ;
        RECT  0 28.08 0.084 28.104 ;
    END
  END response_addr[11]
  PIN response_addr[12]
    DIRECTION OUTPUT ;
    USE SIGNAL ;
    PORT
      LAYER M4 ;
        RECT  0 28.176 0.084 28.2 ;
    END
  END response_addr[12]
  PIN response_addr[13]
    DIRECTION OUTPUT ;
    USE SIGNAL ;
    PORT
      LAYER M4 ;
        RECT  0 28.272 0.084 28.296 ;
    END
  END response_addr[13]
  PIN response_addr[14]
    DIRECTION OUTPUT ;
    USE SIGNAL ;
    PORT
      LAYER M4 ;
        RECT  0 28.368 0.084 28.392 ;
    END
  END response_addr[14]
  PIN response_addr[15]
    DIRECTION OUTPUT ;
    USE SIGNAL ;
    PORT
      LAYER M4 ;
        RECT  0 28.464 0.084 28.488 ;
    END
  END response_addr[15]
  PIN response_addr[16]
    DIRECTION OUTPUT ;
    USE SIGNAL ;
    PORT
      LAYER M4 ;
        RECT  0 28.56 0.084 28.584 ;
    END
  END response_addr[16]
  PIN response_addr[17]
    DIRECTION OUTPUT ;
    USE SIGNAL ;
    PORT
      LAYER M4 ;
        RECT  0 28.656 0.084 28.68 ;
    END
  END response_addr[17]
  PIN response_addr[18]
    DIRECTION OUTPUT ;
    USE SIGNAL ;
    PORT
      LAYER M4 ;
        RECT  0 28.752 0.084 28.776 ;
    END
  END response_addr[18]
  PIN response_addr[19]
    DIRECTION OUTPUT ;
    USE SIGNAL ;
    PORT
      LAYER M4 ;
        RECT  0 28.848 0.084 28.872 ;
    END
  END response_addr[19]
  PIN response_addr[1]
    DIRECTION OUTPUT ;
    USE SIGNAL ;
    PORT
      LAYER M4 ;
        RECT  0 27.12 0.084 27.144 ;
    END
  END response_addr[1]
  PIN response_addr[20]
    DIRECTION OUTPUT ;
    USE SIGNAL ;
    PORT
      LAYER M4 ;
        RECT  0 28.944 0.084 28.968 ;
    END
  END response_addr[20]
  PIN response_addr[21]
    DIRECTION OUTPUT ;
    USE SIGNAL ;
    PORT
      LAYER M4 ;
        RECT  0 29.04 0.084 29.064 ;
    END
  END response_addr[21]
  PIN response_addr[22]
    DIRECTION OUTPUT ;
    USE SIGNAL ;
    PORT
      LAYER M4 ;
        RECT  0 29.136 0.084 29.16 ;
    END
  END response_addr[22]
  PIN response_addr[23]
    DIRECTION OUTPUT ;
    USE SIGNAL ;
    PORT
      LAYER M4 ;
        RECT  0 29.232 0.084 29.256 ;
    END
  END response_addr[23]
  PIN response_addr[24]
    DIRECTION OUTPUT ;
    USE SIGNAL ;
    PORT
      LAYER M4 ;
        RECT  0 29.328 0.084 29.352 ;
    END
  END response_addr[24]
  PIN response_addr[25]
    DIRECTION OUTPUT ;
    USE SIGNAL ;
    PORT
      LAYER M4 ;
        RECT  0 29.424 0.084 29.448 ;
    END
  END response_addr[25]
  PIN response_addr[26]
    DIRECTION OUTPUT ;
    USE SIGNAL ;
    PORT
      LAYER M4 ;
        RECT  0 29.52 0.084 29.544 ;
    END
  END response_addr[26]
  PIN response_addr[27]
    DIRECTION OUTPUT ;
    USE SIGNAL ;
    PORT
      LAYER M4 ;
        RECT  0 29.616 0.084 29.64 ;
    END
  END response_addr[27]
  PIN response_addr[28]
    DIRECTION OUTPUT ;
    USE SIGNAL ;
    PORT
      LAYER M4 ;
        RECT  0 29.712 0.084 29.736 ;
    END
  END response_addr[28]
  PIN response_addr[29]
    DIRECTION OUTPUT ;
    USE SIGNAL ;
    PORT
      LAYER M4 ;
        RECT  0 29.808 0.084 29.832 ;
    END
  END response_addr[29]
  PIN response_addr[2]
    DIRECTION OUTPUT ;
    USE SIGNAL ;
    PORT
      LAYER M4 ;
        RECT  0 27.216 0.084 27.24 ;
    END
  END response_addr[2]
  PIN response_addr[30]
    DIRECTION OUTPUT ;
    USE SIGNAL ;
    PORT
      LAYER M4 ;
        RECT  0 29.904 0.084 29.928 ;
    END
  END response_addr[30]
  PIN response_addr[31]
    DIRECTION OUTPUT ;
    USE SIGNAL ;
    PORT
      LAYER M4 ;
        RECT  0 30 0.084 30.024 ;
    END
  END response_addr[31]
  PIN response_addr[32]
    DIRECTION OUTPUT ;
    USE SIGNAL ;
    PORT
      LAYER M4 ;
        RECT  0 32.016 0.084 32.04 ;
    END
  END response_addr[32]
  PIN response_addr[33]
    DIRECTION OUTPUT ;
    USE SIGNAL ;
    PORT
      LAYER M4 ;
        RECT  0 32.112 0.084 32.136 ;
    END
  END response_addr[33]
  PIN response_addr[34]
    DIRECTION OUTPUT ;
    USE SIGNAL ;
    PORT
      LAYER M4 ;
        RECT  0 32.208 0.084 32.232 ;
    END
  END response_addr[34]
  PIN response_addr[35]
    DIRECTION OUTPUT ;
    USE SIGNAL ;
    PORT
      LAYER M4 ;
        RECT  0 32.304 0.084 32.328 ;
    END
  END response_addr[35]
  PIN response_addr[36]
    DIRECTION OUTPUT ;
    USE SIGNAL ;
    PORT
      LAYER M4 ;
        RECT  0 32.4 0.084 32.424 ;
    END
  END response_addr[36]
  PIN response_addr[37]
    DIRECTION OUTPUT ;
    USE SIGNAL ;
    PORT
      LAYER M4 ;
        RECT  0 32.496 0.084 32.52 ;
    END
  END response_addr[37]
  PIN response_addr[38]
    DIRECTION OUTPUT ;
    USE SIGNAL ;
    PORT
      LAYER M4 ;
        RECT  0 32.592 0.084 32.616 ;
    END
  END response_addr[38]
  PIN response_addr[39]
    DIRECTION OUTPUT ;
    USE SIGNAL ;
    PORT
      LAYER M4 ;
        RECT  0 32.688 0.084 32.712 ;
    END
  END response_addr[39]
  PIN response_addr[3]
    DIRECTION OUTPUT ;
    USE SIGNAL ;
    PORT
      LAYER M4 ;
        RECT  0 27.312 0.084 27.336 ;
    END
  END response_addr[3]
  PIN response_addr[40]
    DIRECTION OUTPUT ;
    USE SIGNAL ;
    PORT
      LAYER M4 ;
        RECT  0 32.784 0.084 32.808 ;
    END
  END response_addr[40]
  PIN response_addr[41]
    DIRECTION OUTPUT ;
    USE SIGNAL ;
    PORT
      LAYER M4 ;
        RECT  0 32.88 0.084 32.904 ;
    END
  END response_addr[41]
  PIN response_addr[42]
    DIRECTION OUTPUT ;
    USE SIGNAL ;
    PORT
      LAYER M4 ;
        RECT  0 32.976 0.084 33 ;
    END
  END response_addr[42]
  PIN response_addr[43]
    DIRECTION OUTPUT ;
    USE SIGNAL ;
    PORT
      LAYER M4 ;
        RECT  0 33.072 0.084 33.096 ;
    END
  END response_addr[43]
  PIN response_addr[4]
    DIRECTION OUTPUT ;
    USE SIGNAL ;
    PORT
      LAYER M4 ;
        RECT  0 27.408 0.084 27.432 ;
    END
  END response_addr[4]
  PIN response_addr[5]
    DIRECTION OUTPUT ;
    USE SIGNAL ;
    PORT
      LAYER M4 ;
        RECT  0 27.504 0.084 27.528 ;
    END
  END response_addr[5]
  PIN response_addr[6]
    DIRECTION OUTPUT ;
    USE SIGNAL ;
    PORT
      LAYER M4 ;
        RECT  0 27.6 0.084 27.624 ;
    END
  END response_addr[6]
  PIN response_addr[7]
    DIRECTION OUTPUT ;
    USE SIGNAL ;
    PORT
      LAYER M4 ;
        RECT  0 27.696 0.084 27.72 ;
    END
  END response_addr[7]
  PIN response_addr[8]
    DIRECTION OUTPUT ;
    USE SIGNAL ;
    PORT
      LAYER M4 ;
        RECT  0 27.792 0.084 27.816 ;
    END
  END response_addr[8]
  PIN response_addr[9]
    DIRECTION OUTPUT ;
    USE SIGNAL ;
    PORT
      LAYER M4 ;
        RECT  0 27.888 0.084 27.912 ;
    END
  END response_addr[9]
  PIN response_data[0]
    DIRECTION OUTPUT ;
    USE SIGNAL ;
    PORT
      LAYER M4 ;
        RECT  86.316 35.568 86.4 35.592 ;
    END
  END response_data[0]
  PIN response_data[100]
    DIRECTION OUTPUT ;
    USE SIGNAL ;
    PORT
      LAYER M4 ;
        RECT  86.316 23.664 86.4 23.688 ;
    END
  END response_data[100]
  PIN response_data[101]
    DIRECTION OUTPUT ;
    USE SIGNAL ;
    PORT
      LAYER M4 ;
        RECT  86.316 23.76 86.4 23.784 ;
    END
  END response_data[101]
  PIN response_data[102]
    DIRECTION OUTPUT ;
    USE SIGNAL ;
    PORT
      LAYER M4 ;
        RECT  86.316 23.856 86.4 23.88 ;
    END
  END response_data[102]
  PIN response_data[103]
    DIRECTION OUTPUT ;
    USE SIGNAL ;
    PORT
      LAYER M4 ;
        RECT  86.316 23.952 86.4 23.976 ;
    END
  END response_data[103]
  PIN response_data[104]
    DIRECTION OUTPUT ;
    USE SIGNAL ;
    PORT
      LAYER M4 ;
        RECT  86.316 24.048 86.4 24.072 ;
    END
  END response_data[104]
  PIN response_data[105]
    DIRECTION OUTPUT ;
    USE SIGNAL ;
    PORT
      LAYER M4 ;
        RECT  86.316 24.144 86.4 24.168 ;
    END
  END response_data[105]
  PIN response_data[106]
    DIRECTION OUTPUT ;
    USE SIGNAL ;
    PORT
      LAYER M4 ;
        RECT  86.316 24.24 86.4 24.264 ;
    END
  END response_data[106]
  PIN response_data[107]
    DIRECTION OUTPUT ;
    USE SIGNAL ;
    PORT
      LAYER M4 ;
        RECT  86.316 24.336 86.4 24.36 ;
    END
  END response_data[107]
  PIN response_data[108]
    DIRECTION OUTPUT ;
    USE SIGNAL ;
    PORT
      LAYER M4 ;
        RECT  86.316 24.432 86.4 24.456 ;
    END
  END response_data[108]
  PIN response_data[109]
    DIRECTION OUTPUT ;
    USE SIGNAL ;
    PORT
      LAYER M4 ;
        RECT  86.316 24.528 86.4 24.552 ;
    END
  END response_data[109]
  PIN response_data[10]
    DIRECTION OUTPUT ;
    USE SIGNAL ;
    PORT
      LAYER M4 ;
        RECT  86.316 36.528 86.4 36.552 ;
    END
  END response_data[10]
  PIN response_data[110]
    DIRECTION OUTPUT ;
    USE SIGNAL ;
    PORT
      LAYER M4 ;
        RECT  86.316 24.624 86.4 24.648 ;
    END
  END response_data[110]
  PIN response_data[111]
    DIRECTION OUTPUT ;
    USE SIGNAL ;
    PORT
      LAYER M4 ;
        RECT  86.316 24.72 86.4 24.744 ;
    END
  END response_data[111]
  PIN response_data[112]
    DIRECTION OUTPUT ;
    USE SIGNAL ;
    PORT
      LAYER M4 ;
        RECT  86.316 24.816 86.4 24.84 ;
    END
  END response_data[112]
  PIN response_data[113]
    DIRECTION OUTPUT ;
    USE SIGNAL ;
    PORT
      LAYER M4 ;
        RECT  86.316 24.912 86.4 24.936 ;
    END
  END response_data[113]
  PIN response_data[114]
    DIRECTION OUTPUT ;
    USE SIGNAL ;
    PORT
      LAYER M4 ;
        RECT  86.316 25.008 86.4 25.032 ;
    END
  END response_data[114]
  PIN response_data[115]
    DIRECTION OUTPUT ;
    USE SIGNAL ;
    PORT
      LAYER M4 ;
        RECT  86.316 25.104 86.4 25.128 ;
    END
  END response_data[115]
  PIN response_data[116]
    DIRECTION OUTPUT ;
    USE SIGNAL ;
    PORT
      LAYER M4 ;
        RECT  86.316 25.2 86.4 25.224 ;
    END
  END response_data[116]
  PIN response_data[117]
    DIRECTION OUTPUT ;
    USE SIGNAL ;
    PORT
      LAYER M4 ;
        RECT  86.316 25.296 86.4 25.32 ;
    END
  END response_data[117]
  PIN response_data[118]
    DIRECTION OUTPUT ;
    USE SIGNAL ;
    PORT
      LAYER M4 ;
        RECT  86.316 25.392 86.4 25.416 ;
    END
  END response_data[118]
  PIN response_data[119]
    DIRECTION OUTPUT ;
    USE SIGNAL ;
    PORT
      LAYER M4 ;
        RECT  86.316 25.488 86.4 25.512 ;
    END
  END response_data[119]
  PIN response_data[11]
    DIRECTION OUTPUT ;
    USE SIGNAL ;
    PORT
      LAYER M4 ;
        RECT  86.316 36.624 86.4 36.648 ;
    END
  END response_data[11]
  PIN response_data[120]
    DIRECTION OUTPUT ;
    USE SIGNAL ;
    PORT
      LAYER M4 ;
        RECT  86.316 25.584 86.4 25.608 ;
    END
  END response_data[120]
  PIN response_data[121]
    DIRECTION OUTPUT ;
    USE SIGNAL ;
    PORT
      LAYER M4 ;
        RECT  86.316 25.68 86.4 25.704 ;
    END
  END response_data[121]
  PIN response_data[122]
    DIRECTION OUTPUT ;
    USE SIGNAL ;
    PORT
      LAYER M4 ;
        RECT  86.316 25.776 86.4 25.8 ;
    END
  END response_data[122]
  PIN response_data[123]
    DIRECTION OUTPUT ;
    USE SIGNAL ;
    PORT
      LAYER M4 ;
        RECT  86.316 25.872 86.4 25.896 ;
    END
  END response_data[123]
  PIN response_data[124]
    DIRECTION OUTPUT ;
    USE SIGNAL ;
    PORT
      LAYER M4 ;
        RECT  86.316 25.968 86.4 25.992 ;
    END
  END response_data[124]
  PIN response_data[125]
    DIRECTION OUTPUT ;
    USE SIGNAL ;
    PORT
      LAYER M4 ;
        RECT  86.316 26.064 86.4 26.088 ;
    END
  END response_data[125]
  PIN response_data[126]
    DIRECTION OUTPUT ;
    USE SIGNAL ;
    PORT
      LAYER M4 ;
        RECT  86.316 26.16 86.4 26.184 ;
    END
  END response_data[126]
  PIN response_data[127]
    DIRECTION OUTPUT ;
    USE SIGNAL ;
    PORT
      LAYER M4 ;
        RECT  86.316 26.256 86.4 26.28 ;
    END
  END response_data[127]
  PIN response_data[128]
    DIRECTION OUTPUT ;
    USE SIGNAL ;
    PORT
      LAYER M4 ;
        RECT  86.316 32.496 86.4 32.52 ;
    END
  END response_data[128]
  PIN response_data[129]
    DIRECTION OUTPUT ;
    USE SIGNAL ;
    PORT
      LAYER M4 ;
        RECT  86.316 32.592 86.4 32.616 ;
    END
  END response_data[129]
  PIN response_data[12]
    DIRECTION OUTPUT ;
    USE SIGNAL ;
    PORT
      LAYER M4 ;
        RECT  86.316 36.72 86.4 36.744 ;
    END
  END response_data[12]
  PIN response_data[130]
    DIRECTION OUTPUT ;
    USE SIGNAL ;
    PORT
      LAYER M4 ;
        RECT  86.316 32.688 86.4 32.712 ;
    END
  END response_data[130]
  PIN response_data[131]
    DIRECTION OUTPUT ;
    USE SIGNAL ;
    PORT
      LAYER M4 ;
        RECT  86.316 32.784 86.4 32.808 ;
    END
  END response_data[131]
  PIN response_data[132]
    DIRECTION OUTPUT ;
    USE SIGNAL ;
    PORT
      LAYER M4 ;
        RECT  86.316 32.88 86.4 32.904 ;
    END
  END response_data[132]
  PIN response_data[133]
    DIRECTION OUTPUT ;
    USE SIGNAL ;
    PORT
      LAYER M4 ;
        RECT  86.316 32.976 86.4 33 ;
    END
  END response_data[133]
  PIN response_data[134]
    DIRECTION OUTPUT ;
    USE SIGNAL ;
    PORT
      LAYER M4 ;
        RECT  86.316 33.072 86.4 33.096 ;
    END
  END response_data[134]
  PIN response_data[135]
    DIRECTION OUTPUT ;
    USE SIGNAL ;
    PORT
      LAYER M4 ;
        RECT  86.316 33.168 86.4 33.192 ;
    END
  END response_data[135]
  PIN response_data[136]
    DIRECTION OUTPUT ;
    USE SIGNAL ;
    PORT
      LAYER M4 ;
        RECT  86.316 33.264 86.4 33.288 ;
    END
  END response_data[136]
  PIN response_data[137]
    DIRECTION OUTPUT ;
    USE SIGNAL ;
    PORT
      LAYER M4 ;
        RECT  86.316 33.36 86.4 33.384 ;
    END
  END response_data[137]
  PIN response_data[138]
    DIRECTION OUTPUT ;
    USE SIGNAL ;
    PORT
      LAYER M4 ;
        RECT  86.316 33.456 86.4 33.48 ;
    END
  END response_data[138]
  PIN response_data[139]
    DIRECTION OUTPUT ;
    USE SIGNAL ;
    PORT
      LAYER M4 ;
        RECT  86.316 33.552 86.4 33.576 ;
    END
  END response_data[139]
  PIN response_data[13]
    DIRECTION OUTPUT ;
    USE SIGNAL ;
    PORT
      LAYER M4 ;
        RECT  86.316 36.816 86.4 36.84 ;
    END
  END response_data[13]
  PIN response_data[140]
    DIRECTION OUTPUT ;
    USE SIGNAL ;
    PORT
      LAYER M4 ;
        RECT  86.316 33.648 86.4 33.672 ;
    END
  END response_data[140]
  PIN response_data[141]
    DIRECTION OUTPUT ;
    USE SIGNAL ;
    PORT
      LAYER M4 ;
        RECT  86.316 33.744 86.4 33.768 ;
    END
  END response_data[141]
  PIN response_data[142]
    DIRECTION OUTPUT ;
    USE SIGNAL ;
    PORT
      LAYER M4 ;
        RECT  86.316 33.84 86.4 33.864 ;
    END
  END response_data[142]
  PIN response_data[143]
    DIRECTION OUTPUT ;
    USE SIGNAL ;
    PORT
      LAYER M4 ;
        RECT  86.316 33.936 86.4 33.96 ;
    END
  END response_data[143]
  PIN response_data[144]
    DIRECTION OUTPUT ;
    USE SIGNAL ;
    PORT
      LAYER M4 ;
        RECT  86.316 34.032 86.4 34.056 ;
    END
  END response_data[144]
  PIN response_data[145]
    DIRECTION OUTPUT ;
    USE SIGNAL ;
    PORT
      LAYER M4 ;
        RECT  86.316 34.128 86.4 34.152 ;
    END
  END response_data[145]
  PIN response_data[146]
    DIRECTION OUTPUT ;
    USE SIGNAL ;
    PORT
      LAYER M4 ;
        RECT  86.316 34.224 86.4 34.248 ;
    END
  END response_data[146]
  PIN response_data[147]
    DIRECTION OUTPUT ;
    USE SIGNAL ;
    PORT
      LAYER M4 ;
        RECT  86.316 34.32 86.4 34.344 ;
    END
  END response_data[147]
  PIN response_data[148]
    DIRECTION OUTPUT ;
    USE SIGNAL ;
    PORT
      LAYER M4 ;
        RECT  86.316 34.416 86.4 34.44 ;
    END
  END response_data[148]
  PIN response_data[149]
    DIRECTION OUTPUT ;
    USE SIGNAL ;
    PORT
      LAYER M4 ;
        RECT  86.316 34.512 86.4 34.536 ;
    END
  END response_data[149]
  PIN response_data[14]
    DIRECTION OUTPUT ;
    USE SIGNAL ;
    PORT
      LAYER M4 ;
        RECT  86.316 36.912 86.4 36.936 ;
    END
  END response_data[14]
  PIN response_data[150]
    DIRECTION OUTPUT ;
    USE SIGNAL ;
    PORT
      LAYER M4 ;
        RECT  86.316 34.608 86.4 34.632 ;
    END
  END response_data[150]
  PIN response_data[151]
    DIRECTION OUTPUT ;
    USE SIGNAL ;
    PORT
      LAYER M4 ;
        RECT  86.316 34.704 86.4 34.728 ;
    END
  END response_data[151]
  PIN response_data[152]
    DIRECTION OUTPUT ;
    USE SIGNAL ;
    PORT
      LAYER M4 ;
        RECT  86.316 34.8 86.4 34.824 ;
    END
  END response_data[152]
  PIN response_data[153]
    DIRECTION OUTPUT ;
    USE SIGNAL ;
    PORT
      LAYER M4 ;
        RECT  86.316 34.896 86.4 34.92 ;
    END
  END response_data[153]
  PIN response_data[154]
    DIRECTION OUTPUT ;
    USE SIGNAL ;
    PORT
      LAYER M4 ;
        RECT  86.316 34.992 86.4 35.016 ;
    END
  END response_data[154]
  PIN response_data[155]
    DIRECTION OUTPUT ;
    USE SIGNAL ;
    PORT
      LAYER M4 ;
        RECT  86.316 35.088 86.4 35.112 ;
    END
  END response_data[155]
  PIN response_data[156]
    DIRECTION OUTPUT ;
    USE SIGNAL ;
    PORT
      LAYER M4 ;
        RECT  86.316 35.184 86.4 35.208 ;
    END
  END response_data[156]
  PIN response_data[157]
    DIRECTION OUTPUT ;
    USE SIGNAL ;
    PORT
      LAYER M4 ;
        RECT  86.316 35.28 86.4 35.304 ;
    END
  END response_data[157]
  PIN response_data[158]
    DIRECTION OUTPUT ;
    USE SIGNAL ;
    PORT
      LAYER M4 ;
        RECT  86.316 35.376 86.4 35.4 ;
    END
  END response_data[158]
  PIN response_data[159]
    DIRECTION OUTPUT ;
    USE SIGNAL ;
    PORT
      LAYER M4 ;
        RECT  86.316 35.472 86.4 35.496 ;
    END
  END response_data[159]
  PIN response_data[15]
    DIRECTION OUTPUT ;
    USE SIGNAL ;
    PORT
      LAYER M4 ;
        RECT  86.316 37.008 86.4 37.032 ;
    END
  END response_data[15]
  PIN response_data[160]
    DIRECTION OUTPUT ;
    USE SIGNAL ;
    PORT
      LAYER M4 ;
        RECT  86.316 26.352 86.4 26.376 ;
    END
  END response_data[160]
  PIN response_data[161]
    DIRECTION OUTPUT ;
    USE SIGNAL ;
    PORT
      LAYER M4 ;
        RECT  86.316 26.448 86.4 26.472 ;
    END
  END response_data[161]
  PIN response_data[162]
    DIRECTION OUTPUT ;
    USE SIGNAL ;
    PORT
      LAYER M4 ;
        RECT  86.316 26.544 86.4 26.568 ;
    END
  END response_data[162]
  PIN response_data[163]
    DIRECTION OUTPUT ;
    USE SIGNAL ;
    PORT
      LAYER M4 ;
        RECT  86.316 26.64 86.4 26.664 ;
    END
  END response_data[163]
  PIN response_data[164]
    DIRECTION OUTPUT ;
    USE SIGNAL ;
    PORT
      LAYER M4 ;
        RECT  86.316 26.736 86.4 26.76 ;
    END
  END response_data[164]
  PIN response_data[165]
    DIRECTION OUTPUT ;
    USE SIGNAL ;
    PORT
      LAYER M4 ;
        RECT  86.316 26.832 86.4 26.856 ;
    END
  END response_data[165]
  PIN response_data[166]
    DIRECTION OUTPUT ;
    USE SIGNAL ;
    PORT
      LAYER M4 ;
        RECT  86.316 26.928 86.4 26.952 ;
    END
  END response_data[166]
  PIN response_data[167]
    DIRECTION OUTPUT ;
    USE SIGNAL ;
    PORT
      LAYER M4 ;
        RECT  86.316 27.024 86.4 27.048 ;
    END
  END response_data[167]
  PIN response_data[168]
    DIRECTION OUTPUT ;
    USE SIGNAL ;
    PORT
      LAYER M4 ;
        RECT  86.316 27.12 86.4 27.144 ;
    END
  END response_data[168]
  PIN response_data[169]
    DIRECTION OUTPUT ;
    USE SIGNAL ;
    PORT
      LAYER M4 ;
        RECT  86.316 27.216 86.4 27.24 ;
    END
  END response_data[169]
  PIN response_data[16]
    DIRECTION OUTPUT ;
    USE SIGNAL ;
    PORT
      LAYER M4 ;
        RECT  86.316 37.104 86.4 37.128 ;
    END
  END response_data[16]
  PIN response_data[170]
    DIRECTION OUTPUT ;
    USE SIGNAL ;
    PORT
      LAYER M4 ;
        RECT  86.316 27.312 86.4 27.336 ;
    END
  END response_data[170]
  PIN response_data[171]
    DIRECTION OUTPUT ;
    USE SIGNAL ;
    PORT
      LAYER M4 ;
        RECT  86.316 27.408 86.4 27.432 ;
    END
  END response_data[171]
  PIN response_data[172]
    DIRECTION OUTPUT ;
    USE SIGNAL ;
    PORT
      LAYER M4 ;
        RECT  86.316 27.504 86.4 27.528 ;
    END
  END response_data[172]
  PIN response_data[173]
    DIRECTION OUTPUT ;
    USE SIGNAL ;
    PORT
      LAYER M4 ;
        RECT  86.316 27.6 86.4 27.624 ;
    END
  END response_data[173]
  PIN response_data[174]
    DIRECTION OUTPUT ;
    USE SIGNAL ;
    PORT
      LAYER M4 ;
        RECT  86.316 27.696 86.4 27.72 ;
    END
  END response_data[174]
  PIN response_data[175]
    DIRECTION OUTPUT ;
    USE SIGNAL ;
    PORT
      LAYER M4 ;
        RECT  86.316 27.792 86.4 27.816 ;
    END
  END response_data[175]
  PIN response_data[176]
    DIRECTION OUTPUT ;
    USE SIGNAL ;
    PORT
      LAYER M4 ;
        RECT  86.316 27.888 86.4 27.912 ;
    END
  END response_data[176]
  PIN response_data[177]
    DIRECTION OUTPUT ;
    USE SIGNAL ;
    PORT
      LAYER M4 ;
        RECT  86.316 27.984 86.4 28.008 ;
    END
  END response_data[177]
  PIN response_data[178]
    DIRECTION OUTPUT ;
    USE SIGNAL ;
    PORT
      LAYER M4 ;
        RECT  86.316 28.08 86.4 28.104 ;
    END
  END response_data[178]
  PIN response_data[179]
    DIRECTION OUTPUT ;
    USE SIGNAL ;
    PORT
      LAYER M4 ;
        RECT  86.316 28.176 86.4 28.2 ;
    END
  END response_data[179]
  PIN response_data[17]
    DIRECTION OUTPUT ;
    USE SIGNAL ;
    PORT
      LAYER M4 ;
        RECT  86.316 37.2 86.4 37.224 ;
    END
  END response_data[17]
  PIN response_data[180]
    DIRECTION OUTPUT ;
    USE SIGNAL ;
    PORT
      LAYER M4 ;
        RECT  86.316 28.272 86.4 28.296 ;
    END
  END response_data[180]
  PIN response_data[181]
    DIRECTION OUTPUT ;
    USE SIGNAL ;
    PORT
      LAYER M4 ;
        RECT  86.316 28.368 86.4 28.392 ;
    END
  END response_data[181]
  PIN response_data[182]
    DIRECTION OUTPUT ;
    USE SIGNAL ;
    PORT
      LAYER M4 ;
        RECT  86.316 28.464 86.4 28.488 ;
    END
  END response_data[182]
  PIN response_data[183]
    DIRECTION OUTPUT ;
    USE SIGNAL ;
    PORT
      LAYER M4 ;
        RECT  86.316 28.56 86.4 28.584 ;
    END
  END response_data[183]
  PIN response_data[184]
    DIRECTION OUTPUT ;
    USE SIGNAL ;
    PORT
      LAYER M4 ;
        RECT  86.316 28.656 86.4 28.68 ;
    END
  END response_data[184]
  PIN response_data[185]
    DIRECTION OUTPUT ;
    USE SIGNAL ;
    PORT
      LAYER M4 ;
        RECT  86.316 28.752 86.4 28.776 ;
    END
  END response_data[185]
  PIN response_data[186]
    DIRECTION OUTPUT ;
    USE SIGNAL ;
    PORT
      LAYER M4 ;
        RECT  86.316 28.848 86.4 28.872 ;
    END
  END response_data[186]
  PIN response_data[187]
    DIRECTION OUTPUT ;
    USE SIGNAL ;
    PORT
      LAYER M4 ;
        RECT  86.316 28.944 86.4 28.968 ;
    END
  END response_data[187]
  PIN response_data[188]
    DIRECTION OUTPUT ;
    USE SIGNAL ;
    PORT
      LAYER M4 ;
        RECT  86.316 29.04 86.4 29.064 ;
    END
  END response_data[188]
  PIN response_data[189]
    DIRECTION OUTPUT ;
    USE SIGNAL ;
    PORT
      LAYER M4 ;
        RECT  86.316 29.136 86.4 29.16 ;
    END
  END response_data[189]
  PIN response_data[18]
    DIRECTION OUTPUT ;
    USE SIGNAL ;
    PORT
      LAYER M4 ;
        RECT  86.316 37.296 86.4 37.32 ;
    END
  END response_data[18]
  PIN response_data[190]
    DIRECTION OUTPUT ;
    USE SIGNAL ;
    PORT
      LAYER M4 ;
        RECT  86.316 29.232 86.4 29.256 ;
    END
  END response_data[190]
  PIN response_data[191]
    DIRECTION OUTPUT ;
    USE SIGNAL ;
    PORT
      LAYER M4 ;
        RECT  86.316 29.328 86.4 29.352 ;
    END
  END response_data[191]
  PIN response_data[192]
    DIRECTION OUTPUT ;
    USE SIGNAL ;
    PORT
      LAYER M4 ;
        RECT  86.316 39.408 86.4 39.432 ;
    END
  END response_data[192]
  PIN response_data[193]
    DIRECTION OUTPUT ;
    USE SIGNAL ;
    PORT
      LAYER M4 ;
        RECT  86.316 39.504 86.4 39.528 ;
    END
  END response_data[193]
  PIN response_data[194]
    DIRECTION OUTPUT ;
    USE SIGNAL ;
    PORT
      LAYER M4 ;
        RECT  86.316 39.6 86.4 39.624 ;
    END
  END response_data[194]
  PIN response_data[195]
    DIRECTION OUTPUT ;
    USE SIGNAL ;
    PORT
      LAYER M4 ;
        RECT  86.316 39.696 86.4 39.72 ;
    END
  END response_data[195]
  PIN response_data[196]
    DIRECTION OUTPUT ;
    USE SIGNAL ;
    PORT
      LAYER M4 ;
        RECT  86.316 39.792 86.4 39.816 ;
    END
  END response_data[196]
  PIN response_data[197]
    DIRECTION OUTPUT ;
    USE SIGNAL ;
    PORT
      LAYER M4 ;
        RECT  86.316 39.888 86.4 39.912 ;
    END
  END response_data[197]
  PIN response_data[198]
    DIRECTION OUTPUT ;
    USE SIGNAL ;
    PORT
      LAYER M4 ;
        RECT  86.316 39.984 86.4 40.008 ;
    END
  END response_data[198]
  PIN response_data[199]
    DIRECTION OUTPUT ;
    USE SIGNAL ;
    PORT
      LAYER M4 ;
        RECT  86.316 40.08 86.4 40.104 ;
    END
  END response_data[199]
  PIN response_data[19]
    DIRECTION OUTPUT ;
    USE SIGNAL ;
    PORT
      LAYER M4 ;
        RECT  86.316 37.392 86.4 37.416 ;
    END
  END response_data[19]
  PIN response_data[1]
    DIRECTION OUTPUT ;
    USE SIGNAL ;
    PORT
      LAYER M4 ;
        RECT  86.316 35.664 86.4 35.688 ;
    END
  END response_data[1]
  PIN response_data[200]
    DIRECTION OUTPUT ;
    USE SIGNAL ;
    PORT
      LAYER M4 ;
        RECT  86.316 40.176 86.4 40.2 ;
    END
  END response_data[200]
  PIN response_data[201]
    DIRECTION OUTPUT ;
    USE SIGNAL ;
    PORT
      LAYER M4 ;
        RECT  86.316 40.272 86.4 40.296 ;
    END
  END response_data[201]
  PIN response_data[202]
    DIRECTION OUTPUT ;
    USE SIGNAL ;
    PORT
      LAYER M4 ;
        RECT  86.316 40.368 86.4 40.392 ;
    END
  END response_data[202]
  PIN response_data[203]
    DIRECTION OUTPUT ;
    USE SIGNAL ;
    PORT
      LAYER M4 ;
        RECT  86.316 40.464 86.4 40.488 ;
    END
  END response_data[203]
  PIN response_data[204]
    DIRECTION OUTPUT ;
    USE SIGNAL ;
    PORT
      LAYER M4 ;
        RECT  86.316 40.56 86.4 40.584 ;
    END
  END response_data[204]
  PIN response_data[205]
    DIRECTION OUTPUT ;
    USE SIGNAL ;
    PORT
      LAYER M4 ;
        RECT  86.316 40.656 86.4 40.68 ;
    END
  END response_data[205]
  PIN response_data[206]
    DIRECTION OUTPUT ;
    USE SIGNAL ;
    PORT
      LAYER M4 ;
        RECT  86.316 40.752 86.4 40.776 ;
    END
  END response_data[206]
  PIN response_data[207]
    DIRECTION OUTPUT ;
    USE SIGNAL ;
    PORT
      LAYER M4 ;
        RECT  86.316 40.848 86.4 40.872 ;
    END
  END response_data[207]
  PIN response_data[208]
    DIRECTION OUTPUT ;
    USE SIGNAL ;
    PORT
      LAYER M4 ;
        RECT  86.316 40.944 86.4 40.968 ;
    END
  END response_data[208]
  PIN response_data[209]
    DIRECTION OUTPUT ;
    USE SIGNAL ;
    PORT
      LAYER M4 ;
        RECT  86.316 41.04 86.4 41.064 ;
    END
  END response_data[209]
  PIN response_data[20]
    DIRECTION OUTPUT ;
    USE SIGNAL ;
    PORT
      LAYER M4 ;
        RECT  86.316 37.488 86.4 37.512 ;
    END
  END response_data[20]
  PIN response_data[210]
    DIRECTION OUTPUT ;
    USE SIGNAL ;
    PORT
      LAYER M4 ;
        RECT  86.316 41.136 86.4 41.16 ;
    END
  END response_data[210]
  PIN response_data[211]
    DIRECTION OUTPUT ;
    USE SIGNAL ;
    PORT
      LAYER M4 ;
        RECT  86.316 41.232 86.4 41.256 ;
    END
  END response_data[211]
  PIN response_data[212]
    DIRECTION OUTPUT ;
    USE SIGNAL ;
    PORT
      LAYER M4 ;
        RECT  86.316 41.328 86.4 41.352 ;
    END
  END response_data[212]
  PIN response_data[213]
    DIRECTION OUTPUT ;
    USE SIGNAL ;
    PORT
      LAYER M4 ;
        RECT  86.316 41.424 86.4 41.448 ;
    END
  END response_data[213]
  PIN response_data[214]
    DIRECTION OUTPUT ;
    USE SIGNAL ;
    PORT
      LAYER M4 ;
        RECT  86.316 41.52 86.4 41.544 ;
    END
  END response_data[214]
  PIN response_data[215]
    DIRECTION OUTPUT ;
    USE SIGNAL ;
    PORT
      LAYER M4 ;
        RECT  86.316 41.616 86.4 41.64 ;
    END
  END response_data[215]
  PIN response_data[216]
    DIRECTION OUTPUT ;
    USE SIGNAL ;
    PORT
      LAYER M4 ;
        RECT  86.316 41.712 86.4 41.736 ;
    END
  END response_data[216]
  PIN response_data[217]
    DIRECTION OUTPUT ;
    USE SIGNAL ;
    PORT
      LAYER M4 ;
        RECT  86.316 41.808 86.4 41.832 ;
    END
  END response_data[217]
  PIN response_data[218]
    DIRECTION OUTPUT ;
    USE SIGNAL ;
    PORT
      LAYER M4 ;
        RECT  86.316 41.904 86.4 41.928 ;
    END
  END response_data[218]
  PIN response_data[219]
    DIRECTION OUTPUT ;
    USE SIGNAL ;
    PORT
      LAYER M4 ;
        RECT  86.316 42 86.4 42.024 ;
    END
  END response_data[219]
  PIN response_data[21]
    DIRECTION OUTPUT ;
    USE SIGNAL ;
    PORT
      LAYER M4 ;
        RECT  86.316 37.584 86.4 37.608 ;
    END
  END response_data[21]
  PIN response_data[220]
    DIRECTION OUTPUT ;
    USE SIGNAL ;
    PORT
      LAYER M4 ;
        RECT  86.316 42.096 86.4 42.12 ;
    END
  END response_data[220]
  PIN response_data[221]
    DIRECTION OUTPUT ;
    USE SIGNAL ;
    PORT
      LAYER M4 ;
        RECT  86.316 42.192 86.4 42.216 ;
    END
  END response_data[221]
  PIN response_data[222]
    DIRECTION OUTPUT ;
    USE SIGNAL ;
    PORT
      LAYER M4 ;
        RECT  86.316 42.288 86.4 42.312 ;
    END
  END response_data[222]
  PIN response_data[223]
    DIRECTION OUTPUT ;
    USE SIGNAL ;
    PORT
      LAYER M4 ;
        RECT  86.316 42.384 86.4 42.408 ;
    END
  END response_data[223]
  PIN response_data[224]
    DIRECTION OUTPUT ;
    USE SIGNAL ;
    PORT
      LAYER M4 ;
        RECT  86.316 16.368 86.4 16.392 ;
    END
  END response_data[224]
  PIN response_data[225]
    DIRECTION OUTPUT ;
    USE SIGNAL ;
    PORT
      LAYER M4 ;
        RECT  86.316 16.464 86.4 16.488 ;
    END
  END response_data[225]
  PIN response_data[226]
    DIRECTION OUTPUT ;
    USE SIGNAL ;
    PORT
      LAYER M4 ;
        RECT  86.316 16.56 86.4 16.584 ;
    END
  END response_data[226]
  PIN response_data[227]
    DIRECTION OUTPUT ;
    USE SIGNAL ;
    PORT
      LAYER M4 ;
        RECT  86.316 16.656 86.4 16.68 ;
    END
  END response_data[227]
  PIN response_data[228]
    DIRECTION OUTPUT ;
    USE SIGNAL ;
    PORT
      LAYER M4 ;
        RECT  86.316 16.752 86.4 16.776 ;
    END
  END response_data[228]
  PIN response_data[229]
    DIRECTION OUTPUT ;
    USE SIGNAL ;
    PORT
      LAYER M4 ;
        RECT  86.316 16.848 86.4 16.872 ;
    END
  END response_data[229]
  PIN response_data[22]
    DIRECTION OUTPUT ;
    USE SIGNAL ;
    PORT
      LAYER M4 ;
        RECT  86.316 37.68 86.4 37.704 ;
    END
  END response_data[22]
  PIN response_data[230]
    DIRECTION OUTPUT ;
    USE SIGNAL ;
    PORT
      LAYER M4 ;
        RECT  86.316 16.944 86.4 16.968 ;
    END
  END response_data[230]
  PIN response_data[231]
    DIRECTION OUTPUT ;
    USE SIGNAL ;
    PORT
      LAYER M4 ;
        RECT  86.316 17.04 86.4 17.064 ;
    END
  END response_data[231]
  PIN response_data[232]
    DIRECTION OUTPUT ;
    USE SIGNAL ;
    PORT
      LAYER M4 ;
        RECT  86.316 17.136 86.4 17.16 ;
    END
  END response_data[232]
  PIN response_data[233]
    DIRECTION OUTPUT ;
    USE SIGNAL ;
    PORT
      LAYER M4 ;
        RECT  86.316 17.232 86.4 17.256 ;
    END
  END response_data[233]
  PIN response_data[234]
    DIRECTION OUTPUT ;
    USE SIGNAL ;
    PORT
      LAYER M4 ;
        RECT  86.316 17.328 86.4 17.352 ;
    END
  END response_data[234]
  PIN response_data[235]
    DIRECTION OUTPUT ;
    USE SIGNAL ;
    PORT
      LAYER M4 ;
        RECT  86.316 17.424 86.4 17.448 ;
    END
  END response_data[235]
  PIN response_data[236]
    DIRECTION OUTPUT ;
    USE SIGNAL ;
    PORT
      LAYER M4 ;
        RECT  86.316 17.52 86.4 17.544 ;
    END
  END response_data[236]
  PIN response_data[237]
    DIRECTION OUTPUT ;
    USE SIGNAL ;
    PORT
      LAYER M4 ;
        RECT  86.316 17.616 86.4 17.64 ;
    END
  END response_data[237]
  PIN response_data[238]
    DIRECTION OUTPUT ;
    USE SIGNAL ;
    PORT
      LAYER M4 ;
        RECT  86.316 17.712 86.4 17.736 ;
    END
  END response_data[238]
  PIN response_data[239]
    DIRECTION OUTPUT ;
    USE SIGNAL ;
    PORT
      LAYER M4 ;
        RECT  86.316 17.808 86.4 17.832 ;
    END
  END response_data[239]
  PIN response_data[23]
    DIRECTION OUTPUT ;
    USE SIGNAL ;
    PORT
      LAYER M4 ;
        RECT  86.316 37.776 86.4 37.8 ;
    END
  END response_data[23]
  PIN response_data[240]
    DIRECTION OUTPUT ;
    USE SIGNAL ;
    PORT
      LAYER M4 ;
        RECT  86.316 17.904 86.4 17.928 ;
    END
  END response_data[240]
  PIN response_data[241]
    DIRECTION OUTPUT ;
    USE SIGNAL ;
    PORT
      LAYER M4 ;
        RECT  86.316 18 86.4 18.024 ;
    END
  END response_data[241]
  PIN response_data[242]
    DIRECTION OUTPUT ;
    USE SIGNAL ;
    PORT
      LAYER M4 ;
        RECT  86.316 18.096 86.4 18.12 ;
    END
  END response_data[242]
  PIN response_data[243]
    DIRECTION OUTPUT ;
    USE SIGNAL ;
    PORT
      LAYER M4 ;
        RECT  86.316 18.192 86.4 18.216 ;
    END
  END response_data[243]
  PIN response_data[244]
    DIRECTION OUTPUT ;
    USE SIGNAL ;
    PORT
      LAYER M4 ;
        RECT  86.316 18.288 86.4 18.312 ;
    END
  END response_data[244]
  PIN response_data[245]
    DIRECTION OUTPUT ;
    USE SIGNAL ;
    PORT
      LAYER M4 ;
        RECT  86.316 18.384 86.4 18.408 ;
    END
  END response_data[245]
  PIN response_data[246]
    DIRECTION OUTPUT ;
    USE SIGNAL ;
    PORT
      LAYER M4 ;
        RECT  86.316 18.48 86.4 18.504 ;
    END
  END response_data[246]
  PIN response_data[247]
    DIRECTION OUTPUT ;
    USE SIGNAL ;
    PORT
      LAYER M4 ;
        RECT  86.316 18.576 86.4 18.6 ;
    END
  END response_data[247]
  PIN response_data[248]
    DIRECTION OUTPUT ;
    USE SIGNAL ;
    PORT
      LAYER M4 ;
        RECT  86.316 18.672 86.4 18.696 ;
    END
  END response_data[248]
  PIN response_data[249]
    DIRECTION OUTPUT ;
    USE SIGNAL ;
    PORT
      LAYER M4 ;
        RECT  86.316 18.768 86.4 18.792 ;
    END
  END response_data[249]
  PIN response_data[24]
    DIRECTION OUTPUT ;
    USE SIGNAL ;
    PORT
      LAYER M4 ;
        RECT  86.316 37.872 86.4 37.896 ;
    END
  END response_data[24]
  PIN response_data[250]
    DIRECTION OUTPUT ;
    USE SIGNAL ;
    PORT
      LAYER M4 ;
        RECT  86.316 18.864 86.4 18.888 ;
    END
  END response_data[250]
  PIN response_data[251]
    DIRECTION OUTPUT ;
    USE SIGNAL ;
    PORT
      LAYER M4 ;
        RECT  86.316 18.96 86.4 18.984 ;
    END
  END response_data[251]
  PIN response_data[252]
    DIRECTION OUTPUT ;
    USE SIGNAL ;
    PORT
      LAYER M4 ;
        RECT  86.316 19.056 86.4 19.08 ;
    END
  END response_data[252]
  PIN response_data[253]
    DIRECTION OUTPUT ;
    USE SIGNAL ;
    PORT
      LAYER M4 ;
        RECT  86.316 19.152 86.4 19.176 ;
    END
  END response_data[253]
  PIN response_data[254]
    DIRECTION OUTPUT ;
    USE SIGNAL ;
    PORT
      LAYER M4 ;
        RECT  86.316 19.248 86.4 19.272 ;
    END
  END response_data[254]
  PIN response_data[255]
    DIRECTION OUTPUT ;
    USE SIGNAL ;
    PORT
      LAYER M4 ;
        RECT  86.316 19.344 86.4 19.368 ;
    END
  END response_data[255]
  PIN response_data[25]
    DIRECTION OUTPUT ;
    USE SIGNAL ;
    PORT
      LAYER M4 ;
        RECT  86.316 37.968 86.4 37.992 ;
    END
  END response_data[25]
  PIN response_data[26]
    DIRECTION OUTPUT ;
    USE SIGNAL ;
    PORT
      LAYER M4 ;
        RECT  86.316 38.064 86.4 38.088 ;
    END
  END response_data[26]
  PIN response_data[27]
    DIRECTION OUTPUT ;
    USE SIGNAL ;
    PORT
      LAYER M4 ;
        RECT  86.316 38.16 86.4 38.184 ;
    END
  END response_data[27]
  PIN response_data[28]
    DIRECTION OUTPUT ;
    USE SIGNAL ;
    PORT
      LAYER M4 ;
        RECT  86.316 38.256 86.4 38.28 ;
    END
  END response_data[28]
  PIN response_data[29]
    DIRECTION OUTPUT ;
    USE SIGNAL ;
    PORT
      LAYER M4 ;
        RECT  86.316 38.352 86.4 38.376 ;
    END
  END response_data[29]
  PIN response_data[2]
    DIRECTION OUTPUT ;
    USE SIGNAL ;
    PORT
      LAYER M4 ;
        RECT  86.316 35.76 86.4 35.784 ;
    END
  END response_data[2]
  PIN response_data[30]
    DIRECTION OUTPUT ;
    USE SIGNAL ;
    PORT
      LAYER M4 ;
        RECT  86.316 38.448 86.4 38.472 ;
    END
  END response_data[30]
  PIN response_data[31]
    DIRECTION OUTPUT ;
    USE SIGNAL ;
    PORT
      LAYER M4 ;
        RECT  86.316 38.544 86.4 38.568 ;
    END
  END response_data[31]
  PIN response_data[32]
    DIRECTION OUTPUT ;
    USE SIGNAL ;
    PORT
      LAYER M4 ;
        RECT  86.316 20.208 86.4 20.232 ;
    END
  END response_data[32]
  PIN response_data[33]
    DIRECTION OUTPUT ;
    USE SIGNAL ;
    PORT
      LAYER M4 ;
        RECT  86.316 20.304 86.4 20.328 ;
    END
  END response_data[33]
  PIN response_data[34]
    DIRECTION OUTPUT ;
    USE SIGNAL ;
    PORT
      LAYER M4 ;
        RECT  86.316 20.4 86.4 20.424 ;
    END
  END response_data[34]
  PIN response_data[35]
    DIRECTION OUTPUT ;
    USE SIGNAL ;
    PORT
      LAYER M4 ;
        RECT  86.316 20.496 86.4 20.52 ;
    END
  END response_data[35]
  PIN response_data[36]
    DIRECTION OUTPUT ;
    USE SIGNAL ;
    PORT
      LAYER M4 ;
        RECT  86.316 20.592 86.4 20.616 ;
    END
  END response_data[36]
  PIN response_data[37]
    DIRECTION OUTPUT ;
    USE SIGNAL ;
    PORT
      LAYER M4 ;
        RECT  86.316 20.688 86.4 20.712 ;
    END
  END response_data[37]
  PIN response_data[38]
    DIRECTION OUTPUT ;
    USE SIGNAL ;
    PORT
      LAYER M4 ;
        RECT  86.316 20.784 86.4 20.808 ;
    END
  END response_data[38]
  PIN response_data[39]
    DIRECTION OUTPUT ;
    USE SIGNAL ;
    PORT
      LAYER M4 ;
        RECT  86.316 20.88 86.4 20.904 ;
    END
  END response_data[39]
  PIN response_data[3]
    DIRECTION OUTPUT ;
    USE SIGNAL ;
    PORT
      LAYER M4 ;
        RECT  86.316 35.856 86.4 35.88 ;
    END
  END response_data[3]
  PIN response_data[40]
    DIRECTION OUTPUT ;
    USE SIGNAL ;
    PORT
      LAYER M4 ;
        RECT  86.316 20.976 86.4 21 ;
    END
  END response_data[40]
  PIN response_data[41]
    DIRECTION OUTPUT ;
    USE SIGNAL ;
    PORT
      LAYER M4 ;
        RECT  86.316 21.072 86.4 21.096 ;
    END
  END response_data[41]
  PIN response_data[42]
    DIRECTION OUTPUT ;
    USE SIGNAL ;
    PORT
      LAYER M4 ;
        RECT  86.316 21.168 86.4 21.192 ;
    END
  END response_data[42]
  PIN response_data[43]
    DIRECTION OUTPUT ;
    USE SIGNAL ;
    PORT
      LAYER M4 ;
        RECT  86.316 21.264 86.4 21.288 ;
    END
  END response_data[43]
  PIN response_data[44]
    DIRECTION OUTPUT ;
    USE SIGNAL ;
    PORT
      LAYER M4 ;
        RECT  86.316 21.36 86.4 21.384 ;
    END
  END response_data[44]
  PIN response_data[45]
    DIRECTION OUTPUT ;
    USE SIGNAL ;
    PORT
      LAYER M4 ;
        RECT  86.316 21.456 86.4 21.48 ;
    END
  END response_data[45]
  PIN response_data[46]
    DIRECTION OUTPUT ;
    USE SIGNAL ;
    PORT
      LAYER M4 ;
        RECT  86.316 21.552 86.4 21.576 ;
    END
  END response_data[46]
  PIN response_data[47]
    DIRECTION OUTPUT ;
    USE SIGNAL ;
    PORT
      LAYER M4 ;
        RECT  86.316 21.648 86.4 21.672 ;
    END
  END response_data[47]
  PIN response_data[48]
    DIRECTION OUTPUT ;
    USE SIGNAL ;
    PORT
      LAYER M4 ;
        RECT  86.316 21.744 86.4 21.768 ;
    END
  END response_data[48]
  PIN response_data[49]
    DIRECTION OUTPUT ;
    USE SIGNAL ;
    PORT
      LAYER M4 ;
        RECT  86.316 21.84 86.4 21.864 ;
    END
  END response_data[49]
  PIN response_data[4]
    DIRECTION OUTPUT ;
    USE SIGNAL ;
    PORT
      LAYER M4 ;
        RECT  86.316 35.952 86.4 35.976 ;
    END
  END response_data[4]
  PIN response_data[50]
    DIRECTION OUTPUT ;
    USE SIGNAL ;
    PORT
      LAYER M4 ;
        RECT  86.316 21.936 86.4 21.96 ;
    END
  END response_data[50]
  PIN response_data[51]
    DIRECTION OUTPUT ;
    USE SIGNAL ;
    PORT
      LAYER M4 ;
        RECT  86.316 22.032 86.4 22.056 ;
    END
  END response_data[51]
  PIN response_data[52]
    DIRECTION OUTPUT ;
    USE SIGNAL ;
    PORT
      LAYER M4 ;
        RECT  86.316 22.128 86.4 22.152 ;
    END
  END response_data[52]
  PIN response_data[53]
    DIRECTION OUTPUT ;
    USE SIGNAL ;
    PORT
      LAYER M4 ;
        RECT  86.316 22.224 86.4 22.248 ;
    END
  END response_data[53]
  PIN response_data[54]
    DIRECTION OUTPUT ;
    USE SIGNAL ;
    PORT
      LAYER M4 ;
        RECT  86.316 22.32 86.4 22.344 ;
    END
  END response_data[54]
  PIN response_data[55]
    DIRECTION OUTPUT ;
    USE SIGNAL ;
    PORT
      LAYER M4 ;
        RECT  86.316 22.416 86.4 22.44 ;
    END
  END response_data[55]
  PIN response_data[56]
    DIRECTION OUTPUT ;
    USE SIGNAL ;
    PORT
      LAYER M4 ;
        RECT  86.316 22.512 86.4 22.536 ;
    END
  END response_data[56]
  PIN response_data[57]
    DIRECTION OUTPUT ;
    USE SIGNAL ;
    PORT
      LAYER M4 ;
        RECT  86.316 22.608 86.4 22.632 ;
    END
  END response_data[57]
  PIN response_data[58]
    DIRECTION OUTPUT ;
    USE SIGNAL ;
    PORT
      LAYER M4 ;
        RECT  86.316 22.704 86.4 22.728 ;
    END
  END response_data[58]
  PIN response_data[59]
    DIRECTION OUTPUT ;
    USE SIGNAL ;
    PORT
      LAYER M4 ;
        RECT  86.316 22.8 86.4 22.824 ;
    END
  END response_data[59]
  PIN response_data[5]
    DIRECTION OUTPUT ;
    USE SIGNAL ;
    PORT
      LAYER M4 ;
        RECT  86.316 36.048 86.4 36.072 ;
    END
  END response_data[5]
  PIN response_data[60]
    DIRECTION OUTPUT ;
    USE SIGNAL ;
    PORT
      LAYER M4 ;
        RECT  86.316 22.896 86.4 22.92 ;
    END
  END response_data[60]
  PIN response_data[61]
    DIRECTION OUTPUT ;
    USE SIGNAL ;
    PORT
      LAYER M4 ;
        RECT  86.316 22.992 86.4 23.016 ;
    END
  END response_data[61]
  PIN response_data[62]
    DIRECTION OUTPUT ;
    USE SIGNAL ;
    PORT
      LAYER M4 ;
        RECT  86.316 23.088 86.4 23.112 ;
    END
  END response_data[62]
  PIN response_data[63]
    DIRECTION OUTPUT ;
    USE SIGNAL ;
    PORT
      LAYER M4 ;
        RECT  86.316 23.184 86.4 23.208 ;
    END
  END response_data[63]
  PIN response_data[64]
    DIRECTION OUTPUT ;
    USE SIGNAL ;
    PORT
      LAYER M4 ;
        RECT  86.316 29.424 86.4 29.448 ;
    END
  END response_data[64]
  PIN response_data[65]
    DIRECTION OUTPUT ;
    USE SIGNAL ;
    PORT
      LAYER M4 ;
        RECT  86.316 29.52 86.4 29.544 ;
    END
  END response_data[65]
  PIN response_data[66]
    DIRECTION OUTPUT ;
    USE SIGNAL ;
    PORT
      LAYER M4 ;
        RECT  86.316 29.616 86.4 29.64 ;
    END
  END response_data[66]
  PIN response_data[67]
    DIRECTION OUTPUT ;
    USE SIGNAL ;
    PORT
      LAYER M4 ;
        RECT  86.316 29.712 86.4 29.736 ;
    END
  END response_data[67]
  PIN response_data[68]
    DIRECTION OUTPUT ;
    USE SIGNAL ;
    PORT
      LAYER M4 ;
        RECT  86.316 29.808 86.4 29.832 ;
    END
  END response_data[68]
  PIN response_data[69]
    DIRECTION OUTPUT ;
    USE SIGNAL ;
    PORT
      LAYER M4 ;
        RECT  86.316 29.904 86.4 29.928 ;
    END
  END response_data[69]
  PIN response_data[6]
    DIRECTION OUTPUT ;
    USE SIGNAL ;
    PORT
      LAYER M4 ;
        RECT  86.316 36.144 86.4 36.168 ;
    END
  END response_data[6]
  PIN response_data[70]
    DIRECTION OUTPUT ;
    USE SIGNAL ;
    PORT
      LAYER M4 ;
        RECT  86.316 30 86.4 30.024 ;
    END
  END response_data[70]
  PIN response_data[71]
    DIRECTION OUTPUT ;
    USE SIGNAL ;
    PORT
      LAYER M4 ;
        RECT  86.316 30.096 86.4 30.12 ;
    END
  END response_data[71]
  PIN response_data[72]
    DIRECTION OUTPUT ;
    USE SIGNAL ;
    PORT
      LAYER M4 ;
        RECT  86.316 30.192 86.4 30.216 ;
    END
  END response_data[72]
  PIN response_data[73]
    DIRECTION OUTPUT ;
    USE SIGNAL ;
    PORT
      LAYER M4 ;
        RECT  86.316 30.288 86.4 30.312 ;
    END
  END response_data[73]
  PIN response_data[74]
    DIRECTION OUTPUT ;
    USE SIGNAL ;
    PORT
      LAYER M4 ;
        RECT  86.316 30.384 86.4 30.408 ;
    END
  END response_data[74]
  PIN response_data[75]
    DIRECTION OUTPUT ;
    USE SIGNAL ;
    PORT
      LAYER M4 ;
        RECT  86.316 30.48 86.4 30.504 ;
    END
  END response_data[75]
  PIN response_data[76]
    DIRECTION OUTPUT ;
    USE SIGNAL ;
    PORT
      LAYER M4 ;
        RECT  86.316 30.576 86.4 30.6 ;
    END
  END response_data[76]
  PIN response_data[77]
    DIRECTION OUTPUT ;
    USE SIGNAL ;
    PORT
      LAYER M4 ;
        RECT  86.316 30.672 86.4 30.696 ;
    END
  END response_data[77]
  PIN response_data[78]
    DIRECTION OUTPUT ;
    USE SIGNAL ;
    PORT
      LAYER M4 ;
        RECT  86.316 30.768 86.4 30.792 ;
    END
  END response_data[78]
  PIN response_data[79]
    DIRECTION OUTPUT ;
    USE SIGNAL ;
    PORT
      LAYER M4 ;
        RECT  86.316 30.864 86.4 30.888 ;
    END
  END response_data[79]
  PIN response_data[7]
    DIRECTION OUTPUT ;
    USE SIGNAL ;
    PORT
      LAYER M4 ;
        RECT  86.316 36.24 86.4 36.264 ;
    END
  END response_data[7]
  PIN response_data[80]
    DIRECTION OUTPUT ;
    USE SIGNAL ;
    PORT
      LAYER M4 ;
        RECT  86.316 30.96 86.4 30.984 ;
    END
  END response_data[80]
  PIN response_data[81]
    DIRECTION OUTPUT ;
    USE SIGNAL ;
    PORT
      LAYER M4 ;
        RECT  86.316 31.056 86.4 31.08 ;
    END
  END response_data[81]
  PIN response_data[82]
    DIRECTION OUTPUT ;
    USE SIGNAL ;
    PORT
      LAYER M4 ;
        RECT  86.316 31.152 86.4 31.176 ;
    END
  END response_data[82]
  PIN response_data[83]
    DIRECTION OUTPUT ;
    USE SIGNAL ;
    PORT
      LAYER M4 ;
        RECT  86.316 31.248 86.4 31.272 ;
    END
  END response_data[83]
  PIN response_data[84]
    DIRECTION OUTPUT ;
    USE SIGNAL ;
    PORT
      LAYER M4 ;
        RECT  86.316 31.344 86.4 31.368 ;
    END
  END response_data[84]
  PIN response_data[85]
    DIRECTION OUTPUT ;
    USE SIGNAL ;
    PORT
      LAYER M4 ;
        RECT  86.316 31.44 86.4 31.464 ;
    END
  END response_data[85]
  PIN response_data[86]
    DIRECTION OUTPUT ;
    USE SIGNAL ;
    PORT
      LAYER M4 ;
        RECT  86.316 31.536 86.4 31.56 ;
    END
  END response_data[86]
  PIN response_data[87]
    DIRECTION OUTPUT ;
    USE SIGNAL ;
    PORT
      LAYER M4 ;
        RECT  86.316 31.632 86.4 31.656 ;
    END
  END response_data[87]
  PIN response_data[88]
    DIRECTION OUTPUT ;
    USE SIGNAL ;
    PORT
      LAYER M4 ;
        RECT  86.316 31.728 86.4 31.752 ;
    END
  END response_data[88]
  PIN response_data[89]
    DIRECTION OUTPUT ;
    USE SIGNAL ;
    PORT
      LAYER M4 ;
        RECT  86.316 31.824 86.4 31.848 ;
    END
  END response_data[89]
  PIN response_data[8]
    DIRECTION OUTPUT ;
    USE SIGNAL ;
    PORT
      LAYER M4 ;
        RECT  86.316 36.336 86.4 36.36 ;
    END
  END response_data[8]
  PIN response_data[90]
    DIRECTION OUTPUT ;
    USE SIGNAL ;
    PORT
      LAYER M4 ;
        RECT  86.316 31.92 86.4 31.944 ;
    END
  END response_data[90]
  PIN response_data[91]
    DIRECTION OUTPUT ;
    USE SIGNAL ;
    PORT
      LAYER M4 ;
        RECT  86.316 32.016 86.4 32.04 ;
    END
  END response_data[91]
  PIN response_data[92]
    DIRECTION OUTPUT ;
    USE SIGNAL ;
    PORT
      LAYER M4 ;
        RECT  86.316 32.112 86.4 32.136 ;
    END
  END response_data[92]
  PIN response_data[93]
    DIRECTION OUTPUT ;
    USE SIGNAL ;
    PORT
      LAYER M4 ;
        RECT  86.316 32.208 86.4 32.232 ;
    END
  END response_data[93]
  PIN response_data[94]
    DIRECTION OUTPUT ;
    USE SIGNAL ;
    PORT
      LAYER M4 ;
        RECT  86.316 32.304 86.4 32.328 ;
    END
  END response_data[94]
  PIN response_data[95]
    DIRECTION OUTPUT ;
    USE SIGNAL ;
    PORT
      LAYER M4 ;
        RECT  86.316 32.4 86.4 32.424 ;
    END
  END response_data[95]
  PIN response_data[96]
    DIRECTION OUTPUT ;
    USE SIGNAL ;
    PORT
      LAYER M4 ;
        RECT  86.316 23.28 86.4 23.304 ;
    END
  END response_data[96]
  PIN response_data[97]
    DIRECTION OUTPUT ;
    USE SIGNAL ;
    PORT
      LAYER M4 ;
        RECT  86.316 23.376 86.4 23.4 ;
    END
  END response_data[97]
  PIN response_data[98]
    DIRECTION OUTPUT ;
    USE SIGNAL ;
    PORT
      LAYER M4 ;
        RECT  86.316 23.472 86.4 23.496 ;
    END
  END response_data[98]
  PIN response_data[99]
    DIRECTION OUTPUT ;
    USE SIGNAL ;
    PORT
      LAYER M4 ;
        RECT  86.316 23.568 86.4 23.592 ;
    END
  END response_data[99]
  PIN response_data[9]
    DIRECTION OUTPUT ;
    USE SIGNAL ;
    PORT
      LAYER M4 ;
        RECT  86.316 36.432 86.4 36.456 ;
    END
  END response_data[9]
  PIN response_v[0]
    DIRECTION OUTPUT ;
    USE SIGNAL ;
    PORT
      LAYER M4 ;
        RECT  0 25.488 0.084 25.512 ;
    END
  END response_v[0]
  PIN response_v[1]
    DIRECTION OUTPUT ;
    USE SIGNAL ;
    PORT
      LAYER M4 ;
        RECT  0 25.584 0.084 25.608 ;
    END
  END response_v[1]
  PIN response_v[2]
    DIRECTION OUTPUT ;
    USE SIGNAL ;
    PORT
      LAYER M4 ;
        RECT  0 25.68 0.084 25.704 ;
    END
  END response_v[2]
  PIN response_v[3]
    DIRECTION OUTPUT ;
    USE SIGNAL ;
    PORT
      LAYER M4 ;
        RECT  0 25.776 0.084 25.8 ;
    END
  END response_v[3]
  PIN rst_n
    DIRECTION INPUT ;
    USE SIGNAL ;
    PORT
      LAYER M4 ;
        RECT  0 24.72 0.084 24.744 ;
    END
  END rst_n
  PIN VDD
    DIRECTION INOUT ;
    USE POWER ;
    PORT
      LAYER M5 ;
        RECT  83.592 2.151 83.712 45.369 ;
        RECT  78.192 2.151 78.312 45.369 ;
        RECT  72.792 2.151 72.912 45.369 ;
        RECT  67.392 2.151 67.512 45.369 ;
        RECT  61.992 2.151 62.112 45.369 ;
        RECT  56.592 2.151 56.712 45.369 ;
        RECT  51.192 2.151 51.312 45.369 ;
        RECT  45.792 2.151 45.912 45.369 ;
        RECT  40.392 2.151 40.512 45.369 ;
        RECT  34.992 2.151 35.112 45.369 ;
        RECT  29.592 2.151 29.712 45.369 ;
        RECT  24.192 2.151 24.312 45.369 ;
        RECT  18.792 2.151 18.912 45.369 ;
        RECT  13.392 2.151 13.512 45.369 ;
        RECT  7.992 2.151 8.112 45.369 ;
        RECT  2.592 2.151 2.712 45.369 ;
    END
  END VDD
  PIN VSS
    DIRECTION INOUT ;
    USE GROUND ;
    PORT
      LAYER M5 ;
        RECT  83.4 2.137 83.52 45.383 ;
        RECT  78 2.137 78.12 45.383 ;
        RECT  72.6 2.137 72.72 45.383 ;
        RECT  67.2 2.137 67.32 45.383 ;
        RECT  61.8 2.137 61.92 45.383 ;
        RECT  56.4 2.137 56.52 45.383 ;
        RECT  51 2.137 51.12 45.383 ;
        RECT  45.6 2.137 45.72 45.383 ;
        RECT  40.2 2.137 40.32 45.383 ;
        RECT  34.8 2.137 34.92 45.383 ;
        RECT  29.4 2.137 29.52 45.383 ;
        RECT  24 2.137 24.12 45.383 ;
        RECT  18.6 2.137 18.72 45.383 ;
        RECT  13.2 2.137 13.32 45.383 ;
        RECT  7.8 2.137 7.92 45.383 ;
        RECT  2.4 2.137 2.52 45.383 ;
    END
  END VSS
  # OT_OBS_CLOSED layer=M5 d_um=1.536 added=196
  OBS
    LAYER RVTN ;
     RECT  2.16 2.16 84.24 2.295 ;
     RECT  2.16 2.565 84.24 2.835 ;
     RECT  2.16 3.105 84.24 3.375 ;
     RECT  2.16 3.645 84.24 3.915 ;
     RECT  2.16 4.185 84.24 4.455 ;
     RECT  2.16 4.725 84.24 4.995 ;
     RECT  2.16 5.265 84.24 5.535 ;
     RECT  2.16 5.805 84.24 6.075 ;
     RECT  2.16 6.345 84.24 6.615 ;
     RECT  2.16 6.885 84.24 7.155 ;
     RECT  2.16 7.425 84.24 7.695 ;
     RECT  2.16 7.965 84.24 8.235 ;
     RECT  2.16 8.505 84.24 8.775 ;
     RECT  2.16 9.045 84.24 9.315 ;
     RECT  2.16 9.585 84.24 9.855 ;
     RECT  2.16 10.125 84.24 10.395 ;
     RECT  2.16 10.665 84.24 10.935 ;
     RECT  2.16 11.205 84.24 11.475 ;
     RECT  2.16 11.745 84.24 12.015 ;
     RECT  2.16 12.285 84.24 12.555 ;
     RECT  2.16 12.825 84.24 13.095 ;
     RECT  2.16 13.365 84.24 13.635 ;
     RECT  2.16 13.905 84.24 14.175 ;
     RECT  2.16 14.445 84.24 14.715 ;
     RECT  2.16 14.985 84.24 15.255 ;
     RECT  2.16 15.525 84.24 15.795 ;
     RECT  2.16 16.065 84.24 16.335 ;
     RECT  2.16 16.605 84.24 16.875 ;
     RECT  2.16 17.145 84.24 17.415 ;
     RECT  2.16 17.685 84.24 17.955 ;
     RECT  2.16 18.225 84.24 18.495 ;
     RECT  2.16 18.765 84.24 19.035 ;
     RECT  2.16 19.305 84.24 19.575 ;
     RECT  2.16 19.845 84.24 20.115 ;
     RECT  2.16 20.385 84.24 20.655 ;
     RECT  2.16 20.925 84.24 21.195 ;
     RECT  2.16 21.465 84.24 21.735 ;
     RECT  2.16 22.005 84.24 22.275 ;
     RECT  2.16 22.545 84.24 22.815 ;
     RECT  2.16 23.085 84.24 23.355 ;
     RECT  2.16 23.625 84.24 23.895 ;
     RECT  2.16 24.165 84.24 24.435 ;
     RECT  2.16 24.705 84.24 24.975 ;
     RECT  2.16 25.245 84.24 25.515 ;
     RECT  2.16 25.785 84.24 26.055 ;
     RECT  2.16 26.325 84.24 26.595 ;
     RECT  2.16 26.865 84.24 27.135 ;
     RECT  2.16 27.405 84.24 27.675 ;
     RECT  2.16 27.945 84.24 28.215 ;
     RECT  2.16 28.485 84.24 28.755 ;
     RECT  2.16 29.025 84.24 29.295 ;
     RECT  2.16 29.565 84.24 29.835 ;
     RECT  2.16 30.105 84.24 30.375 ;
     RECT  2.16 30.645 84.24 30.915 ;
     RECT  2.16 31.185 84.24 31.455 ;
     RECT  2.16 31.725 84.24 31.995 ;
     RECT  2.16 32.265 84.24 32.535 ;
     RECT  2.16 32.805 84.24 33.075 ;
     RECT  2.16 33.345 84.24 33.615 ;
     RECT  2.16 33.885 84.24 34.155 ;
     RECT  2.16 34.425 84.24 34.695 ;
     RECT  2.16 34.965 84.24 35.235 ;
     RECT  2.16 35.505 84.24 35.775 ;
     RECT  2.16 36.045 84.24 36.315 ;
     RECT  2.16 36.585 84.24 36.855 ;
     RECT  2.16 37.125 84.24 37.395 ;
     RECT  2.16 37.665 84.24 37.935 ;
     RECT  2.16 38.205 84.24 38.475 ;
     RECT  2.16 38.745 84.24 39.015 ;
     RECT  2.16 39.285 84.24 39.555 ;
     RECT  2.16 39.825 84.24 40.095 ;
     RECT  2.16 40.365 84.24 40.635 ;
     RECT  2.16 40.905 84.24 41.175 ;
     RECT  2.16 41.445 84.24 41.715 ;
     RECT  2.16 41.985 84.24 42.255 ;
     RECT  2.16 42.525 84.24 42.795 ;
     RECT  2.16 43.065 84.24 43.335 ;
     RECT  2.16 43.605 84.24 43.875 ;
     RECT  2.16 44.145 84.24 44.415 ;
     RECT  2.16 44.685 84.24 44.955 ;
     RECT  2.16 45.225 84.24 45.36 ;
    LAYER RVTP ;
     RECT  2.16 2.295 84.24 2.565 ;
     RECT  2.16 2.835 84.24 3.105 ;
     RECT  2.16 3.375 84.24 3.645 ;
     RECT  2.16 3.915 84.24 4.185 ;
     RECT  2.16 4.455 84.24 4.725 ;
     RECT  2.16 4.995 84.24 5.265 ;
     RECT  2.16 5.535 84.24 5.805 ;
     RECT  2.16 6.075 84.24 6.345 ;
     RECT  2.16 6.615 84.24 6.885 ;
     RECT  2.16 7.155 84.24 7.425 ;
     RECT  2.16 7.695 84.24 7.965 ;
     RECT  2.16 8.235 84.24 8.505 ;
     RECT  2.16 8.775 84.24 9.045 ;
     RECT  2.16 9.315 84.24 9.585 ;
     RECT  2.16 9.855 84.24 10.125 ;
     RECT  2.16 10.395 84.24 10.665 ;
     RECT  2.16 10.935 84.24 11.205 ;
     RECT  2.16 11.475 84.24 11.745 ;
     RECT  2.16 12.015 84.24 12.285 ;
     RECT  2.16 12.555 84.24 12.825 ;
     RECT  2.16 13.095 84.24 13.365 ;
     RECT  2.16 13.635 84.24 13.905 ;
     RECT  2.16 14.175 84.24 14.445 ;
     RECT  2.16 14.715 84.24 14.985 ;
     RECT  2.16 15.255 84.24 15.525 ;
     RECT  2.16 15.795 84.24 16.065 ;
     RECT  2.16 16.335 84.24 16.605 ;
     RECT  2.16 16.875 84.24 17.145 ;
     RECT  2.16 17.415 84.24 17.685 ;
     RECT  2.16 17.955 84.24 18.225 ;
     RECT  2.16 18.495 84.24 18.765 ;
     RECT  2.16 19.035 84.24 19.305 ;
     RECT  2.16 19.575 84.24 19.845 ;
     RECT  2.16 20.115 84.24 20.385 ;
     RECT  2.16 20.655 84.24 20.925 ;
     RECT  2.16 21.195 84.24 21.465 ;
     RECT  2.16 21.735 84.24 22.005 ;
     RECT  2.16 22.275 84.24 22.545 ;
     RECT  2.16 22.815 84.24 23.085 ;
     RECT  2.16 23.355 84.24 23.625 ;
     RECT  2.16 23.895 84.24 24.165 ;
     RECT  2.16 24.435 84.24 24.705 ;
     RECT  2.16 24.975 84.24 25.245 ;
     RECT  2.16 25.515 84.24 25.785 ;
     RECT  2.16 26.055 84.24 26.325 ;
     RECT  2.16 26.595 84.24 26.865 ;
     RECT  2.16 27.135 84.24 27.405 ;
     RECT  2.16 27.675 84.24 27.945 ;
     RECT  2.16 28.215 84.24 28.485 ;
     RECT  2.16 28.755 84.24 29.025 ;
     RECT  2.16 29.295 84.24 29.565 ;
     RECT  2.16 29.835 84.24 30.105 ;
     RECT  2.16 30.375 84.24 30.645 ;
     RECT  2.16 30.915 84.24 31.185 ;
     RECT  2.16 31.455 84.24 31.725 ;
     RECT  2.16 31.995 84.24 32.265 ;
     RECT  2.16 32.535 84.24 32.805 ;
     RECT  2.16 33.075 84.24 33.345 ;
     RECT  2.16 33.615 84.24 33.885 ;
     RECT  2.16 34.155 84.24 34.425 ;
     RECT  2.16 34.695 84.24 34.965 ;
     RECT  2.16 35.235 84.24 35.505 ;
     RECT  2.16 35.775 84.24 36.045 ;
     RECT  2.16 36.315 84.24 36.585 ;
     RECT  2.16 36.855 84.24 37.125 ;
     RECT  2.16 37.395 84.24 37.665 ;
     RECT  2.16 37.935 84.24 38.205 ;
     RECT  2.16 38.475 84.24 38.745 ;
     RECT  2.16 39.015 84.24 39.285 ;
     RECT  2.16 39.555 84.24 39.825 ;
     RECT  2.16 40.095 84.24 40.365 ;
     RECT  2.16 40.635 84.24 40.905 ;
     RECT  2.16 41.175 84.24 41.445 ;
     RECT  2.16 41.715 84.24 41.985 ;
     RECT  2.16 42.255 84.24 42.525 ;
     RECT  2.16 42.795 84.24 43.065 ;
     RECT  2.16 43.335 84.24 43.605 ;
     RECT  2.16 43.875 84.24 44.145 ;
     RECT  2.16 44.415 84.24 44.685 ;
     RECT  2.16 44.955 84.24 45.225 ;
    LAYER M1 ;
     RECT  2.16 2.151 84.24 45.369 ;
    LAYER M2 ;
     RECT  0.103 25.326 0.139 26.046 ;
     RECT  0.103 31.626 0.139 31.644 ;
     RECT  0.139 31.626 0.175 31.68 ;
     RECT  0.139 25.326 0.211 26.244 ;
     RECT  0.211 25.326 0.247 26.316 ;
     RECT  0.103 24.48 0.535 24.498 ;
     RECT  0.247 25.326 0.535 26.514 ;
     RECT  1.219 30.726 1.363 30.744 ;
     RECT  0.175 31.626 1.363 31.914 ;
     RECT  1.363 30.726 1.723 31.914 ;
     RECT  1.723 30.654 1.759 31.914 ;
     RECT  1.759 30.384 1.795 31.914 ;
     RECT  1.903 2.106 1.975 2.124 ;
     RECT  1.975 2.106 2.083 2.25 ;
     RECT  2.083 2.106 2.16 2.592 ;
     RECT  0.103 17.622 2.16 18.216 ;
     RECT  0.535 24.48 2.16 26.514 ;
     RECT  0.103 27.648 2.16 27.666 ;
     RECT  1.795 30.276 2.16 31.914 ;
     RECT  1.399 32.778 2.16 32.796 ;
     RECT  2.16 2.106 2.651 45.369 ;
     RECT  2.651 2.151 6.835 45.369 ;
     RECT  6.835 2.106 7.447 45.369 ;
     RECT  7.447 2.106 7.583 45.486 ;
     RECT  7.583 2.151 8.491 45.486 ;
     RECT  8.491 2.151 9.563 45.558 ;
     RECT  9.563 2.151 9.851 45.414 ;
     RECT  9.851 2.151 10.435 45.369 ;
     RECT  10.435 1.998 11.479 45.369 ;
     RECT  11.479 1.881 12.739 45.369 ;
     RECT  12.739 1.836 14.207 45.369 ;
     RECT  14.207 1.881 15.251 45.369 ;
     RECT  15.251 1.998 15.431 45.369 ;
     RECT  15.431 2.034 15.467 45.369 ;
     RECT  15.467 2.106 15.503 45.369 ;
     RECT  15.503 2.151 22.027 45.369 ;
     RECT  22.027 2.106 24.431 45.369 ;
     RECT  24.431 2.151 49.963 45.369 ;
     RECT  49.963 2.106 50.891 45.369 ;
     RECT  50.891 2.151 54.211 45.369 ;
     RECT  54.211 2.106 55.679 45.369 ;
     RECT  55.679 2.151 56.803 45.369 ;
     RECT  56.803 2.034 58.343 45.369 ;
     RECT  58.343 2.07 58.595 45.369 ;
     RECT  58.595 2.106 59.135 45.369 ;
     RECT  59.135 2.151 62.635 45.369 ;
     RECT  62.635 2.106 62.707 45.369 ;
     RECT  62.707 2.07 62.879 45.369 ;
     RECT  62.879 2.106 63.887 45.369 ;
     RECT  63.887 2.151 65.011 45.369 ;
     RECT  65.011 2.106 65.183 45.369 ;
     RECT  65.183 2.151 68.827 45.369 ;
     RECT  68.827 2.106 69.287 45.369 ;
     RECT  69.287 2.151 84.24 45.369 ;
     RECT  84.24 43.578 84.407 44.604 ;
     RECT  84.24 15.336 84.875 40.356 ;
     RECT  84.875 15.336 84.911 25.974 ;
     RECT  84.911 15.336 84.947 24.084 ;
     RECT  84.875 26.766 85.415 40.356 ;
     RECT  84.947 15.606 85.451 24.084 ;
     RECT  84.911 24.876 85.451 25.704 ;
     RECT  84.24 41.346 85.451 42.822 ;
     RECT  85.451 15.606 85.487 19.566 ;
     RECT  85.451 20.358 85.487 24.084 ;
     RECT  85.451 24.876 85.487 24.894 ;
     RECT  85.415 29.196 85.487 40.356 ;
     RECT  85.451 41.346 85.487 42.444 ;
     RECT  85.487 17.388 85.523 17.406 ;
     RECT  85.487 18.306 85.523 18.756 ;
     RECT  85.487 19.548 85.523 19.566 ;
     RECT  85.487 20.358 85.523 20.646 ;
     RECT  85.487 21.474 85.523 21.726 ;
     RECT  85.487 23.166 85.523 23.652 ;
     RECT  85.487 29.808 85.523 36.846 ;
     RECT  85.487 41.418 85.523 42.444 ;
     RECT  85.487 16.146 85.559 16.596 ;
     RECT  85.523 31.5 86.135 36.684 ;
     RECT  85.415 26.766 86.207 28.404 ;
     RECT  85.451 25.686 86.215 25.704 ;
     RECT  86.207 27.306 86.243 28.404 ;
     RECT  86.135 31.698 86.243 36.684 ;
     RECT  85.523 23.4 86.279 23.652 ;
     RECT  86.215 25.686 86.279 26.154 ;
     RECT  86.243 32.508 86.279 36.189 ;
     RECT  85.523 41.688 86.287 42.444 ;
     RECT  85.559 16.146 86.315 16.164 ;
     RECT  85.523 18.738 86.315 18.756 ;
     RECT  85.523 21.474 86.315 21.492 ;
     RECT  86.279 23.4 86.315 23.418 ;
     RECT  86.279 26.136 86.315 26.154 ;
     RECT  86.243 27.306 86.315 27.324 ;
     RECT  86.243 28.386 86.315 28.404 ;
     RECT  85.523 29.808 86.315 30.402 ;
     RECT  86.243 31.698 86.315 31.716 ;
     RECT  86.279 33.624 86.315 33.642 ;
     RECT  86.279 34.596 86.315 36.189 ;
     RECT  85.487 37.638 86.315 39.312 ;
     RECT  85.487 40.338 86.315 40.356 ;
     RECT  86.287 41.454 86.315 42.444 ;
     RECT  84.407 44.316 86.351 44.604 ;
     RECT  86.315 41.454 86.387 41.472 ;
     RECT  86.351 44.316 86.387 44.334 ;
    LAYER M3 ;
     RECT  10.728 0.043 10.746 0.173 ;
     RECT  67.716 0.091 67.734 0.187 ;
     RECT  62.316 0.091 62.658 0.269 ;
     RECT  56.772 0.139 56.79 0.365 ;
     RECT  62.424 0.269 62.658 0.365 ;
     RECT  67.536 0.187 67.734 0.365 ;
     RECT  62.424 0.365 62.442 0.413 ;
     RECT  5.832 0.331 5.85 0.427 ;
     RECT  5.796 0.427 5.85 0.523 ;
     RECT  9.504 0.091 9.522 0.523 ;
     RECT  50.256 0.091 50.274 0.523 ;
     RECT  5.76 0.523 5.85 0.571 ;
     RECT  15.12 0.043 15.138 0.859 ;
     RECT  15.048 0.859 15.138 0.907 ;
     RECT  5.76 0.571 6.102 1.099 ;
     RECT  66.132 0.091 66.15 1.099 ;
     RECT  5.76 1.099 6.282 1.147 ;
     RECT  7.344 0.091 7.362 1.147 ;
     RECT  9.252 0.523 9.522 1.147 ;
     RECT  67.356 0.523 67.374 1.675 ;
     RECT  5.652 1.147 6.282 1.723 ;
     RECT  7.236 1.147 7.362 1.723 ;
     RECT  9.252 1.147 9.81 1.723 ;
     RECT  17.1 0.571 17.73 1.723 ;
     RECT  21.672 1.147 21.69 1.723 ;
     RECT  22.824 1.147 22.842 1.723 ;
     RECT  43.344 0.571 43.362 1.723 ;
     RECT  44.46 0.523 44.478 1.723 ;
     RECT  47.016 0.091 47.034 1.723 ;
     RECT  48.96 1.147 48.978 1.723 ;
     RECT  50.256 0.523 50.994 1.723 ;
     RECT  59.256 1.099 59.274 1.723 ;
     RECT  64.116 0.523 64.134 1.723 ;
     RECT  65.592 1.099 66.15 1.723 ;
     RECT  67.356 1.675 67.554 1.723 ;
     RECT  1.908 1.723 2.106 1.771 ;
     RECT  14.832 0.907 15.138 1.771 ;
     RECT  43.344 1.723 45.486 1.771 ;
     RECT  46.404 1.723 49.41 1.771 ;
     RECT  56.916 1.723 59.274 1.771 ;
     RECT  60.084 1.723 60.462 1.771 ;
     RECT  61.38 1.723 61.614 1.771 ;
     RECT  62.676 1.723 62.694 1.771 ;
     RECT  65.412 1.723 67.554 1.771 ;
     RECT  68.976 1.723 69.174 1.771 ;
     RECT  13.104 1.723 13.122 1.819 ;
     RECT  14.796 1.771 15.138 1.831 ;
     RECT  11.412 1.771 11.43 1.867 ;
     RECT  14.184 1.831 15.138 1.867 ;
     RECT  53.604 1.723 54.054 1.867 ;
     RECT  60.084 1.771 60.606 1.867 ;
     RECT  14.112 1.867 15.138 1.876 ;
     RECT  12.564 1.819 13.122 1.915 ;
     RECT  12.456 1.915 13.122 1.957 ;
     RECT  14.112 1.876 15.246 1.957 ;
     RECT  12.456 1.957 15.246 1.993 ;
     RECT  17.1 1.723 18.234 2.011 ;
     RECT  19.152 1.723 23.886 2.011 ;
     RECT  50.184 1.723 50.994 2.011 ;
     RECT  12.456 1.993 15.426 2.029 ;
     RECT  56.916 1.771 59.31 2.029 ;
     RECT  5.652 1.723 7.398 2.059 ;
     RECT  61.38 1.771 62.694 2.065 ;
     RECT  63.468 1.723 64.638 2.065 ;
     RECT  1.908 1.771 2.214 2.101 ;
     RECT  5.148 2.059 7.398 2.101 ;
     RECT  11.34 1.867 11.538 2.101 ;
     RECT  12.348 2.029 15.462 2.101 ;
     RECT  17.1 2.011 23.886 2.101 ;
     RECT  24.876 1.771 24.894 2.101 ;
     RECT  43.344 1.771 49.41 2.101 ;
     RECT  50.184 2.011 51.174 2.101 ;
     RECT  53.496 1.867 54.054 2.101 ;
     RECT  55.836 1.723 55.854 2.101 ;
     RECT  61.38 2.065 64.638 2.101 ;
     RECT  65.412 1.771 69.498 2.101 ;
     RECT  1.908 2.101 2.646 2.129 ;
     RECT  5.148 2.101 7.578 2.143 ;
     RECT  8.316 1.723 8.334 2.143 ;
     RECT  53.496 2.101 55.854 2.143 ;
     RECT  56.808 2.029 59.31 2.143 ;
     RECT  5.148 2.143 8.334 2.191 ;
     RECT  17.1 2.101 24.894 2.191 ;
     RECT  43.344 2.101 51.174 2.191 ;
     RECT  52.2 1.723 52.218 2.191 ;
     RECT  53.496 2.143 59.31 2.191 ;
     RECT  60.084 1.867 60.642 2.191 ;
     RECT  61.38 2.101 69.498 2.191 ;
     RECT  43.344 2.191 69.498 2.227 ;
     RECT  70.236 1.723 70.254 2.227 ;
     RECT  1.98 2.129 2.646 2.255 ;
     RECT  4.86 2.191 8.334 2.263 ;
     RECT  9.216 1.723 10.53 2.263 ;
     RECT  11.34 2.101 15.498 2.263 ;
     RECT  17.1 2.191 25.002 2.263 ;
     RECT  4.86 2.263 15.498 2.299 ;
     RECT  16.236 0.811 16.254 2.299 ;
     RECT  17.1 2.263 25.362 2.299 ;
     RECT  2.088 2.255 2.646 2.335 ;
     RECT  4.14 2.299 15.498 2.335 ;
     RECT  16.236 2.299 25.362 2.371 ;
     RECT  43.344 2.227 70.254 2.371 ;
     RECT  29.415 2.143 29.505 2.413 ;
     RECT  34.815 2.143 34.905 2.413 ;
     RECT  40.215 2.143 40.305 2.413 ;
     RECT  72.615 2.143 72.705 2.413 ;
     RECT  78.015 2.143 78.105 2.413 ;
     RECT  83.415 2.143 83.505 2.413 ;
     RECT  2.088 2.335 15.498 2.597 ;
     RECT  2.304 2.597 15.498 2.641 ;
     RECT  16.236 2.371 25.542 2.641 ;
     RECT  0.144 2.635 0.162 2.813 ;
     RECT  43.056 2.371 70.902 2.875 ;
     RECT  43.056 2.875 71.01 2.911 ;
     RECT  43.056 2.911 71.118 3.145 ;
     RECT  43.056 3.145 71.226 3.181 ;
     RECT  72.615 2.413 72.897 3.181 ;
     RECT  2.304 2.641 25.542 3.271 ;
     RECT  2.304 3.271 26.154 3.335 ;
     RECT  43.02 3.181 71.226 3.437 ;
     RECT  2.34 3.335 26.154 3.443 ;
     RECT  4.464 3.443 26.154 3.569 ;
     RECT  43.452 3.437 71.226 3.605 ;
     RECT  75.528 2.803 75.546 3.721 ;
     RECT  17.496 3.569 26.154 3.839 ;
     RECT  4.464 3.569 16.614 3.965 ;
     RECT  4.464 3.965 15.498 3.983 ;
     RECT  72.324 3.181 72.897 3.991 ;
     RECT  74.448 3.271 74.466 4.081 ;
     RECT  17.784 3.839 26.154 4.261 ;
     RECT  43.524 3.605 71.226 4.261 ;
     RECT  72.036 3.991 72.897 4.261 ;
     RECT  75.492 3.721 75.546 4.387 ;
     RECT  76.284 4.225 76.302 4.387 ;
     RECT  43.524 4.261 72.897 4.555 ;
     RECT  2.34 3.443 3.69 4.649 ;
     RECT  16.236 3.965 16.614 4.685 ;
     RECT  30.636 4.648 30.654 4.685 ;
     RECT  43.128 4.555 72.897 4.685 ;
     RECT  75.492 4.387 76.302 4.729 ;
     RECT  4.572 3.983 15.498 4.801 ;
     RECT  16.236 4.685 16.542 4.801 ;
     RECT  17.784 4.261 26.262 4.829 ;
     RECT  34.815 2.413 35.097 4.843 ;
     RECT  30.672 4.801 30.834 4.877 ;
     RECT  32.184 4.801 32.202 4.877 ;
     RECT  29.415 2.413 29.697 4.891 ;
     RECT  43.74 4.685 72.897 4.891 ;
     RECT  4.572 4.801 16.542 4.919 ;
     RECT  34.704 4.843 35.097 4.919 ;
     RECT  73.944 4.081 74.466 4.963 ;
     RECT  75.492 4.729 76.338 4.963 ;
     RECT  29.304 4.891 29.697 5.021 ;
     RECT  30.672 4.877 30.69 5.021 ;
     RECT  42.768 4.891 42.786 5.021 ;
     RECT  4.572 4.919 15.462 5.027 ;
     RECT  15.444 5.027 15.462 5.189 ;
     RECT  2.34 4.649 3.654 5.225 ;
     RECT  73.944 4.963 76.338 5.269 ;
     RECT  18.288 4.829 26.262 5.369 ;
     RECT  43.74 4.891 73.098 5.459 ;
     RECT  73.908 5.269 76.338 5.503 ;
     RECT  44.784 5.459 73.098 5.881 ;
     RECT  73.908 5.503 76.95 5.881 ;
     RECT  18.432 5.369 26.262 5.909 ;
     RECT  4.572 5.027 14.418 6.179 ;
     RECT  17.64 6.091 17.658 6.269 ;
     RECT  18.432 5.909 25.866 6.917 ;
     RECT  2.415 5.225 3.654 6.989 ;
     RECT  18.615 6.917 25.866 6.989 ;
     RECT  6.552 6.179 14.418 7.889 ;
     RECT  44.784 5.881 76.95 8.303 ;
     RECT  44.784 8.303 64.494 8.879 ;
     RECT  4.572 6.179 5.67 12.011 ;
     RECT  4.572 12.011 4.59 14.549 ;
     RECT  6.552 7.889 10.242 14.909 ;
     RECT  83.415 2.413 83.697 15.295 ;
     RECT  5.652 12.011 5.67 15.457 ;
     RECT  6.84 14.909 10.242 15.565 ;
     RECT  10.98 7.889 14.418 15.565 ;
     RECT  84.924 15.331 84.942 15.601 ;
     RECT  83.124 15.295 83.697 15.691 ;
     RECT  84.924 15.601 85.482 15.763 ;
     RECT  5.436 15.457 5.67 15.787 ;
     RECT  6.84 15.565 14.418 15.787 ;
     RECT  83.124 15.691 83.79 15.835 ;
     RECT  82.836 15.835 83.826 15.871 ;
     RECT  65.232 8.303 76.95 16.105 ;
     RECT  65.232 16.105 76.986 16.141 ;
     RECT  82.836 15.871 84.114 16.141 ;
     RECT  82.512 16.141 84.114 16.231 ;
     RECT  46.62 8.879 64.494 16.267 ;
     RECT  65.232 16.141 77.166 16.267 ;
     RECT  84.852 15.763 85.482 16.303 ;
     RECT  82.368 16.231 84.114 16.375 ;
     RECT  81.936 16.375 84.114 16.411 ;
     RECT  84.852 16.303 85.518 16.411 ;
     RECT  81.36 16.411 85.518 16.573 ;
     RECT  46.62 16.267 77.166 16.609 ;
     RECT  78.015 2.413 78.297 16.609 ;
     RECT  79.2 16.411 79.218 16.609 ;
     RECT  46.62 16.609 79.218 16.645 ;
     RECT  5.436 15.787 14.418 16.843 ;
     RECT  81.36 16.573 85.554 16.843 ;
     RECT  86.292 16.141 86.31 16.877 ;
     RECT  80.568 16.681 80.586 17.041 ;
     RECT  81.324 16.843 85.554 17.041 ;
     RECT  46.62 16.645 79.578 17.077 ;
     RECT  46.62 17.077 79.794 17.185 ;
     RECT  80.568 17.041 85.554 17.185 ;
     RECT  3.456 6.989 3.654 17.419 ;
     RECT  5.436 16.843 14.814 17.453 ;
     RECT  46.62 17.185 85.554 17.453 ;
     RECT  5.436 17.453 14.634 17.491 ;
     RECT  5.112 17.491 14.634 17.609 ;
     RECT  0.108 17.617 0.126 17.653 ;
     RECT  3.456 17.419 4.05 17.707 ;
     RECT  5.112 17.609 14.418 17.707 ;
     RECT  0.108 17.653 0.558 17.837 ;
     RECT  2.415 6.989 2.697 17.887 ;
     RECT  3.456 17.707 14.418 17.887 ;
     RECT  2.415 17.887 14.418 18.157 ;
     RECT  2.304 18.157 14.418 18.379 ;
     RECT  46.62 17.453 85.518 18.413 ;
     RECT  2.268 18.379 14.418 18.463 ;
     RECT  0.108 17.837 0.126 18.509 ;
     RECT  2.268 18.463 14.562 18.527 ;
     RECT  2.304 18.527 14.562 18.599 ;
     RECT  0.144 18.571 0.162 18.749 ;
     RECT  86.292 18.571 86.31 18.761 ;
     RECT  2.304 18.599 14.382 18.869 ;
     RECT  18.615 6.989 18.897 19.111 ;
     RECT  19.764 6.989 25.866 19.111 ;
     RECT  46.62 18.413 85.482 19.243 ;
     RECT  2.304 18.869 14.31 19.337 ;
     RECT  18.615 19.111 25.866 19.373 ;
     RECT  46.62 19.243 85.518 19.409 ;
     RECT  46.62 19.409 83.934 19.571 ;
     RECT  16.524 4.919 16.542 19.615 ;
     RECT  16.524 19.615 16.578 19.627 ;
     RECT  15.912 19.627 16.578 19.651 ;
     RECT  17.64 19.627 17.658 19.651 ;
     RECT  15.264 19.651 16.578 19.885 ;
     RECT  17.64 19.651 17.802 19.885 ;
     RECT  0.324 19.819 0.342 19.949 ;
     RECT  15.264 19.885 17.802 20.191 ;
     RECT  18.615 19.373 18.897 20.191 ;
     RECT  15.264 20.191 18.954 20.299 ;
     RECT  84.888 19.409 85.518 20.299 ;
     RECT  79.38 19.571 83.934 20.389 ;
     RECT  84.852 20.299 85.518 20.389 ;
     RECT  79.38 20.389 85.518 20.429 ;
     RECT  0.144 20.347 0.162 20.525 ;
     RECT  46.62 19.571 78.606 20.539 ;
     RECT  79.38 20.429 84.042 20.539 ;
     RECT  15.156 20.299 18.954 20.551 ;
     RECT  19.764 19.373 25.866 20.551 ;
     RECT  2.304 19.337 14.274 20.587 ;
     RECT  15.156 20.551 25.866 20.587 ;
     RECT  0.252 20.779 0.342 20.909 ;
     RECT  2.304 20.587 25.866 21.019 ;
     RECT  0.252 20.909 0.27 21.101 ;
     RECT  46.62 20.539 84.042 21.361 ;
     RECT  84.816 20.429 85.518 21.361 ;
     RECT  86.292 21.451 86.31 21.497 ;
     RECT  46.62 21.361 85.518 21.643 ;
     RECT  2.268 21.019 25.866 21.677 ;
     RECT  2.268 21.677 13.734 21.695 ;
     RECT  0.324 21.643 0.342 21.835 ;
     RECT  0.108 21.835 0.342 21.869 ;
     RECT  43.812 5.459 43.974 21.965 ;
     RECT  0.108 21.869 0.126 22.061 ;
     RECT  2.304 21.695 13.734 22.073 ;
     RECT  46.62 21.643 86.238 22.109 ;
     RECT  46.62 22.109 85.518 22.157 ;
     RECT  2.304 22.073 13.662 22.235 ;
     RECT  2.34 22.235 13.662 22.505 ;
     RECT  44.784 8.879 45.897 22.541 ;
     RECT  46.62 22.157 84.042 22.541 ;
     RECT  84.924 22.157 85.518 22.733 ;
     RECT  46.62 22.541 83.934 22.739 ;
     RECT  2.376 22.505 13.662 22.819 ;
     RECT  14.544 21.677 25.866 22.819 ;
     RECT  2.376 22.819 25.866 22.855 ;
     RECT  2.376 22.855 26.406 23.009 ;
     RECT  41.976 22.795 41.994 23.069 ;
     RECT  86.292 22.891 86.31 23.083 ;
     RECT  14.4 23.009 26.406 23.131 ;
     RECT  14.4 23.131 26.694 23.161 ;
     RECT  85.392 22.733 85.518 23.179 ;
     RECT  86.256 23.083 86.31 23.179 ;
     RECT  14.4 23.161 26.838 23.279 ;
     RECT  46.62 22.739 83.898 23.279 ;
     RECT  85.392 23.179 86.31 23.423 ;
     RECT  27.612 23.161 27.63 23.431 ;
     RECT  85.392 23.423 86.274 23.521 ;
     RECT  27.468 23.431 27.774 23.585 ;
     RECT  84.924 23.521 86.274 23.657 ;
     RECT  84.924 23.657 86.13 23.659 ;
     RECT  2.376 23.009 13.626 23.791 ;
     RECT  14.4 23.279 26.694 23.791 ;
     RECT  27.468 23.585 27.63 24.089 ;
     RECT  2.376 23.791 26.694 24.205 ;
     RECT  27.468 24.089 27.594 24.205 ;
     RECT  46.62 23.279 83.826 24.205 ;
     RECT  46.62 24.205 83.898 24.359 ;
     RECT  28.404 24.241 28.422 24.395 ;
     RECT  29.415 5.021 29.697 24.475 ;
     RECT  43.956 21.965 43.974 24.539 ;
     RECT  2.376 24.205 27.594 24.601 ;
     RECT  84.888 23.659 86.13 24.667 ;
     RECT  2.34 24.601 27.594 24.781 ;
     RECT  0.108 24.475 0.126 24.871 ;
     RECT  2.304 24.781 27.594 24.899 ;
     RECT  84.888 24.667 86.202 25.147 ;
     RECT  32.868 24.439 32.886 25.169 ;
     RECT  84.78 25.147 86.238 25.169 ;
     RECT  46.62 24.359 83.826 25.195 ;
     RECT  84.78 25.169 84.942 25.195 ;
     RECT  27.144 24.899 27.594 25.321 ;
     RECT  29.124 24.475 29.697 25.321 ;
     RECT  31.356 25.291 31.374 25.321 ;
     RECT  32.688 25.285 32.706 25.325 ;
     RECT  86.112 25.169 86.238 25.325 ;
     RECT  86.148 25.325 86.238 25.387 ;
     RECT  27.144 25.321 28.098 25.435 ;
     RECT  29.052 25.321 29.697 25.435 ;
     RECT  31.356 25.321 31.518 25.439 ;
     RECT  31.356 25.439 31.374 25.475 ;
     RECT  36.468 25.141 36.486 25.475 ;
     RECT  34.815 4.919 35.097 25.591 ;
     RECT  0.108 24.871 0.558 25.709 ;
     RECT  2.304 24.899 26.406 25.861 ;
     RECT  27.144 25.435 29.697 25.861 ;
     RECT  44.784 22.541 44.802 25.861 ;
     RECT  45.615 22.541 45.897 25.861 ;
     RECT  46.62 25.195 84.942 25.861 ;
     RECT  2.304 25.861 29.697 25.997 ;
     RECT  34.815 25.591 35.622 26.015 ;
     RECT  37.548 25.681 37.566 26.015 ;
     RECT  44.784 25.861 84.942 26.015 ;
     RECT  45.54 26.015 84.942 26.059 ;
     RECT  86.148 25.387 86.274 26.059 ;
     RECT  45.54 26.059 86.274 26.131 ;
     RECT  27.972 25.997 29.697 26.285 ;
     RECT  38.916 26.059 38.934 26.285 ;
     RECT  0.108 25.709 0.234 26.491 ;
     RECT  45.54 26.131 86.31 26.519 ;
     RECT  2.304 25.997 27.054 26.825 ;
     RECT  45.615 26.519 86.31 26.825 ;
     RECT  30.744 26.761 30.762 26.827 ;
     RECT  31.716 26.329 31.734 26.827 ;
     RECT  46.62 26.825 86.31 26.957 ;
     RECT  30.672 26.827 31.734 27.031 ;
     RECT  2.304 26.825 25.938 27.059 ;
     RECT  30.672 27.031 31.914 27.067 ;
     RECT  32.652 26.941 32.67 27.067 ;
     RECT  2.34 27.059 25.938 27.095 ;
     RECT  46.656 26.957 86.31 27.095 ;
     RECT  30.672 27.067 32.67 27.103 ;
     RECT  30.636 27.103 32.67 27.139 ;
     RECT  28.62 26.285 29.697 27.175 ;
     RECT  30.636 27.139 32.778 27.175 ;
     RECT  47.592 27.095 86.31 27.203 ;
     RECT  34.815 26.015 35.097 27.211 ;
     RECT  2.34 27.095 25.866 27.239 ;
     RECT  28.62 27.175 32.922 27.239 ;
     RECT  26.784 26.825 27.054 27.301 ;
     RECT  27.792 27.211 27.81 27.301 ;
     RECT  26.784 27.301 27.81 27.329 ;
     RECT  28.764 27.239 32.922 27.329 ;
     RECT  26.784 27.329 27.738 27.341 ;
     RECT  22.536 27.239 25.866 27.365 ;
     RECT  34.668 27.211 35.097 27.365 ;
     RECT  37.476 27.301 37.494 27.401 ;
     RECT  0.108 26.491 0.27 27.533 ;
     RECT  33.732 26.875 33.75 27.547 ;
     RECT  38.376 27.211 38.394 27.571 ;
     RECT  2.34 27.239 21.762 27.599 ;
     RECT  31.896 27.329 32.922 27.629 ;
     RECT  31.896 27.629 32.094 27.635 ;
     RECT  36 27.595 36.018 27.635 ;
     RECT  44.784 26.015 44.802 27.671 ;
     RECT  31.896 27.635 31.95 27.677 ;
     RECT  22.536 27.365 25.47 27.707 ;
     RECT  33.66 27.547 33.75 27.715 ;
     RECT  32.904 27.629 32.922 27.751 ;
     RECT  33.66 27.715 34.002 27.751 ;
     RECT  40.215 2.413 40.497 27.751 ;
     RECT  45.615 26.825 45.897 27.751 ;
     RECT  37.404 27.751 37.458 27.841 ;
     RECT  28.764 27.329 30.654 27.869 ;
     RECT  36.072 27.679 36.09 27.869 ;
     RECT  36.936 27.841 37.458 27.877 ;
     RECT  46.656 27.095 46.782 27.877 ;
     RECT  47.592 27.203 83.898 27.877 ;
     RECT  28.764 27.869 30.402 27.905 ;
     RECT  32.904 27.751 34.002 27.905 ;
     RECT  40.14 27.751 40.497 27.913 ;
     RECT  28.764 27.905 29.754 27.917 ;
     RECT  33.516 27.905 33.894 27.917 ;
     RECT  36.756 27.877 37.458 27.917 ;
     RECT  2.34 27.599 21.438 28.021 ;
     RECT  34.815 27.365 35.097 28.021 ;
     RECT  38.376 27.571 38.79 28.021 ;
     RECT  42.768 27.949 42.786 28.111 ;
     RECT  34.815 28.021 35.226 28.139 ;
     RECT  84.636 27.203 86.31 28.139 ;
     RECT  38.376 28.021 39.366 28.147 ;
     RECT  40.14 27.913 40.986 28.147 ;
     RECT  38.376 28.147 40.986 28.175 ;
     RECT  46.656 27.877 83.898 28.175 ;
     RECT  38.484 28.175 40.986 28.183 ;
     RECT  0.108 27.533 0.162 28.205 ;
     RECT  33.516 27.917 33.714 28.205 ;
     RECT  27.036 27.341 27.702 28.219 ;
     RECT  33.696 28.205 33.714 28.253 ;
     RECT  37.224 27.917 37.458 28.255 ;
     RECT  42.624 28.111 43.578 28.255 ;
     RECT  31.932 27.677 31.95 28.283 ;
     RECT  42.516 28.255 44.01 28.291 ;
     RECT  44.928 27.751 45.897 28.291 ;
     RECT  46.656 28.175 46.854 28.291 ;
     RECT  47.592 28.175 83.898 28.315 ;
     RECT  27.036 28.219 27.918 28.319 ;
     RECT  2.304 28.021 21.438 28.381 ;
     RECT  22.536 27.707 24.714 28.381 ;
     RECT  27.684 28.319 27.846 28.409 ;
     RECT  37.224 28.255 37.602 28.409 ;
     RECT  37.224 28.409 37.422 28.445 ;
     RECT  44.928 28.291 46.854 28.445 ;
     RECT  47.592 28.315 84.042 28.445 ;
     RECT  42.516 28.291 44.154 28.459 ;
     RECT  38.484 28.183 41.598 28.489 ;
     RECT  27.684 28.409 27.702 28.493 ;
     RECT  38.484 28.489 41.67 28.525 ;
     RECT  42.48 28.459 44.154 28.525 ;
     RECT  28.62 28.381 28.638 28.541 ;
     RECT  0.144 28.205 0.162 28.555 ;
     RECT  38.484 28.525 44.154 28.589 ;
     RECT  1.224 28.459 1.242 28.603 ;
     RECT  2.304 28.381 24.714 28.651 ;
     RECT  34.815 28.139 35.097 28.651 ;
     RECT  38.484 28.589 41.562 28.679 ;
     RECT  42.336 28.589 44.154 28.679 ;
     RECT  31.356 28.507 31.554 28.688 ;
     RECT  31.356 28.688 31.374 28.715 ;
     RECT  33.984 28.651 34.002 28.715 ;
     RECT  38.736 28.679 41.454 28.751 ;
     RECT  0.144 28.555 0.342 28.781 ;
     RECT  47.592 28.445 78.426 28.859 ;
     RECT  36.792 28.699 37.026 28.949 ;
     RECT  84.852 28.139 86.31 28.973 ;
     RECT  36.792 28.949 36.81 28.985 ;
     RECT  34.776 28.651 35.097 29.057 ;
     RECT  45.108 28.445 46.854 29.065 ;
     RECT  47.592 28.859 78.297 29.065 ;
     RECT  1.224 28.603 1.422 29.131 ;
     RECT  2.268 28.651 24.714 29.131 ;
     RECT  79.236 28.445 84.042 29.131 ;
     RECT  84.852 28.973 85.482 29.131 ;
     RECT  38.772 28.751 41.454 29.255 ;
     RECT  42.48 28.679 44.154 29.371 ;
     RECT  45.108 29.065 78.297 29.371 ;
     RECT  40.212 29.255 41.454 29.489 ;
     RECT  40.215 29.489 41.454 29.561 ;
     RECT  79.236 29.131 85.482 29.561 ;
     RECT  41.436 29.561 41.454 29.569 ;
     RECT  42.48 29.371 78.297 29.569 ;
     RECT  0.144 28.781 0.162 29.597 ;
     RECT  38.772 29.255 38.79 29.633 ;
     RECT  79.236 29.561 84.114 29.641 ;
     RECT  41.436 29.569 78.297 29.755 ;
     RECT  79.128 29.641 84.114 29.755 ;
     RECT  1.224 29.131 24.714 29.759 ;
     RECT  41.436 29.755 84.114 29.795 ;
     RECT  0.216 29.707 0.342 29.837 ;
     RECT  86.292 28.973 86.31 29.851 ;
     RECT  84.924 29.561 85.482 29.875 ;
     RECT  86.22 29.851 86.31 29.875 ;
     RECT  0.216 29.837 0.234 30.029 ;
     RECT  41.436 29.795 42.822 30.065 ;
     RECT  1.224 29.759 21.978 30.101 ;
     RECT  41.616 30.065 42.822 30.137 ;
     RECT  1.224 30.101 21.906 30.173 ;
     RECT  43.74 29.795 84.114 30.209 ;
     RECT  84.924 29.875 86.31 30.283 ;
     RECT  84.888 30.283 86.31 30.371 ;
     RECT  44.136 30.209 84.114 30.479 ;
     RECT  84.924 30.371 86.31 30.509 ;
     RECT  1.224 30.173 21.726 30.569 ;
     RECT  45 30.479 84.114 30.605 ;
     RECT  1.224 30.569 21.438 30.677 ;
     RECT  41.616 30.137 42.75 30.677 ;
     RECT  45.108 30.605 84.114 30.713 ;
     RECT  1.224 30.677 1.422 30.749 ;
     RECT  18.615 30.677 21.438 30.749 ;
     RECT  41.616 30.677 42.318 30.839 ;
     RECT  41.94 30.839 42.318 30.845 ;
     RECT  44.136 30.479 44.154 30.991 ;
     RECT  2.304 30.677 17.694 31.145 ;
     RECT  41.94 30.845 42.174 31.145 ;
     RECT  44.064 30.991 44.154 31.225 ;
     RECT  2.304 31.145 17.586 31.379 ;
     RECT  42.048 31.145 42.174 31.379 ;
     RECT  45.288 30.713 84.114 31.379 ;
     RECT  2.304 31.379 17.19 31.415 ;
     RECT  84.924 30.509 86.238 31.435 ;
     RECT  42.156 31.379 42.174 31.451 ;
     RECT  1.368 30.749 1.422 31.487 ;
     RECT  43.992 31.225 44.154 31.531 ;
     RECT  84.924 31.435 86.31 31.531 ;
     RECT  0.108 31.621 0.126 31.657 ;
     RECT  43.848 31.531 44.154 31.657 ;
     RECT  84.888 31.531 86.31 31.721 ;
     RECT  43.02 31.531 43.038 31.729 ;
     RECT  43.848 31.657 44.19 31.729 ;
     RECT  0.108 31.657 0.162 31.891 ;
     RECT  2.376 31.415 17.19 31.919 ;
     RECT  45.288 31.379 83.934 32.035 ;
     RECT  0.108 31.891 0.198 32.045 ;
     RECT  43.02 31.729 44.19 32.071 ;
     RECT  0.144 32.045 0.198 32.141 ;
     RECT  45.252 32.035 83.934 32.189 ;
     RECT  45.288 32.189 83.934 32.297 ;
     RECT  0.18 32.141 0.198 32.299 ;
     RECT  0.18 32.299 0.342 32.333 ;
     RECT  2.376 31.919 17.154 32.333 ;
     RECT  43.02 32.071 44.226 32.333 ;
     RECT  45.468 32.297 83.934 32.333 ;
     RECT  16.02 32.333 16.434 32.369 ;
     RECT  84.888 31.721 86.274 32.381 ;
     RECT  0.324 32.333 0.342 32.429 ;
     RECT  43.596 32.333 44.226 32.459 ;
     RECT  2.376 32.333 15.282 32.683 ;
     RECT  1.404 31.487 1.422 32.801 ;
     RECT  2.304 32.683 15.282 32.827 ;
     RECT  43.596 32.459 44.19 32.837 ;
     RECT  2.196 32.827 15.282 32.873 ;
     RECT  43.596 32.837 44.046 32.873 ;
     RECT  45.615 32.333 83.934 32.875 ;
     RECT  84.888 32.381 85.518 32.875 ;
     RECT  86.256 32.381 86.274 32.971 ;
     RECT  2.196 32.873 14.562 33.005 ;
     RECT  2.268 33.005 14.562 33.143 ;
     RECT  45.615 32.875 85.518 33.451 ;
     RECT  86.256 32.971 86.31 33.451 ;
     RECT  45.615 33.451 86.31 33.539 ;
     RECT  45.615 33.539 78.894 33.575 ;
     RECT  79.668 33.539 86.31 33.845 ;
     RECT  2.304 33.143 14.562 33.953 ;
     RECT  43.812 32.873 43.83 33.989 ;
     RECT  2.304 33.953 7.038 34.079 ;
     RECT  79.812 33.845 86.31 34.109 ;
     RECT  5.544 34.079 5.562 34.151 ;
     RECT  7.02 34.079 7.038 34.151 ;
     RECT  45.615 33.575 78.678 34.187 ;
     RECT  7.812 33.953 14.562 34.397 ;
     RECT  77.4 34.187 78.678 34.411 ;
     RECT  2.304 34.079 4.662 34.619 ;
     RECT  2.304 34.619 2.697 34.655 ;
     RECT  79.812 34.109 85.482 34.771 ;
     RECT  77.4 34.411 78.714 34.781 ;
     RECT  79.488 34.771 85.482 34.889 ;
     RECT  77.436 34.781 78.714 34.897 ;
     RECT  79.92 34.889 85.482 35.021 ;
     RECT  16.416 32.369 16.434 35.069 ;
     RECT  25.452 27.707 25.47 35.069 ;
     RECT  77.436 34.897 79.182 35.195 ;
     RECT  77.436 35.195 79.11 35.213 ;
     RECT  45.615 34.187 76.662 35.429 ;
     RECT  79.92 35.021 84.654 35.429 ;
     RECT  80.136 35.429 84.654 35.699 ;
     RECT  46.836 35.429 76.662 35.707 ;
     RECT  77.436 35.213 79.038 35.707 ;
     RECT  85.464 35.021 85.482 35.755 ;
     RECT  86.22 34.109 86.31 35.755 ;
     RECT  80.136 35.699 83.898 35.969 ;
     RECT  85.464 35.755 86.31 36.194 ;
     RECT  84.636 35.699 84.654 36.239 ;
     RECT  46.836 35.707 79.038 36.355 ;
     RECT  46.836 36.355 79.146 36.391 ;
     RECT  80.136 35.969 83.826 36.391 ;
     RECT  85.464 36.194 86.274 36.557 ;
     RECT  45.615 35.429 46.098 36.661 ;
     RECT  46.836 36.391 83.826 36.661 ;
     RECT  85.464 36.557 86.238 36.689 ;
     RECT  45.615 36.661 83.826 36.779 ;
     RECT  45.615 36.779 83.697 36.787 ;
     RECT  85.464 36.689 85.518 36.811 ;
     RECT  18.615 30.749 21.33 36.823 ;
     RECT  85.428 36.811 85.518 36.907 ;
     RECT  45.54 36.787 83.697 36.931 ;
     RECT  85.392 36.907 85.518 37.003 ;
     RECT  45.396 36.931 83.697 37.049 ;
     RECT  17.784 37.003 17.802 37.165 ;
     RECT  18.576 36.823 21.33 37.165 ;
     RECT  17.64 37.165 21.33 37.201 ;
     RECT  7.815 34.397 14.562 37.291 ;
     RECT  17.64 37.201 21.366 37.471 ;
     RECT  45.396 37.049 79.146 37.471 ;
     RECT  86.292 37.387 86.31 37.579 ;
     RECT  44.496 37.471 79.146 37.589 ;
     RECT  17.064 37.471 21.438 37.613 ;
     RECT  80.028 37.049 83.697 37.627 ;
     RECT  85.032 37.003 85.518 37.675 ;
     RECT  86.256 37.579 86.31 37.675 ;
     RECT  15.948 37.561 15.966 37.705 ;
     RECT  85.032 37.675 86.31 37.859 ;
     RECT  7.815 37.291 15.03 37.867 ;
     RECT  15.948 37.705 16.65 37.867 ;
     RECT  80.028 37.627 83.862 37.975 ;
     RECT  46.764 37.589 79.146 38.101 ;
     RECT  80.028 37.975 83.898 38.101 ;
     RECT  86.112 37.859 86.31 38.189 ;
     RECT  46.764 38.101 79.254 38.281 ;
     RECT  80.028 38.101 84.042 38.281 ;
     RECT  84.924 37.867 84.978 38.381 ;
     RECT  22.716 29.759 24.714 38.399 ;
     RECT  17.892 37.613 21.438 38.407 ;
     RECT  44.64 37.589 45.954 38.407 ;
     RECT  84.924 38.381 84.942 38.471 ;
     RECT  7.815 37.867 16.65 38.551 ;
     RECT  7.815 38.551 17.01 38.621 ;
     RECT  16.236 38.621 17.01 38.641 ;
     RECT  17.892 38.407 21.51 38.641 ;
     RECT  44.388 38.407 45.954 38.641 ;
     RECT  46.764 38.281 84.042 38.641 ;
     RECT  3.492 34.619 4.662 38.749 ;
     RECT  5.4 35.041 5.418 38.749 ;
     RECT  23.436 38.399 24.714 38.939 ;
     RECT  44.388 38.641 84.042 39.091 ;
     RECT  86.22 38.189 86.31 39.119 ;
     RECT  43.956 39.091 84.042 39.281 ;
     RECT  16.236 38.641 21.51 39.361 ;
     RECT  23.436 38.939 24.297 39.389 ;
     RECT  22.68 38.515 22.698 39.479 ;
     RECT  43.956 39.281 78.894 39.479 ;
     RECT  16.236 39.361 21.69 39.487 ;
     RECT  7.815 38.621 15.174 39.499 ;
     RECT  79.92 39.281 84.042 39.523 ;
     RECT  16.236 39.487 21.762 39.581 ;
     RECT  7.815 39.499 15.282 39.631 ;
     RECT  17.1 39.581 21.762 39.631 ;
     RECT  17.1 39.631 21.906 39.659 ;
     RECT  7.815 39.631 15.426 39.677 ;
     RECT  85.428 39.595 85.446 39.787 ;
     RECT  79.92 39.523 84.366 39.793 ;
     RECT  85.428 39.787 85.482 39.793 ;
     RECT  16.236 39.581 16.362 39.865 ;
     RECT  17.172 39.659 21.906 39.901 ;
     RECT  7.815 39.677 15.282 39.917 ;
     RECT  16.164 39.865 16.362 39.917 ;
     RECT  79.92 39.793 85.482 40.205 ;
     RECT  44.1 39.479 78.894 40.289 ;
     RECT  86.292 39.119 86.31 40.361 ;
     RECT  77.184 40.289 78.894 40.369 ;
     RECT  79.92 40.205 83.934 40.369 ;
     RECT  77.184 40.369 83.934 40.559 ;
     RECT  86.22 40.459 86.238 40.637 ;
     RECT  44.1 40.289 76.374 40.667 ;
     RECT  17.172 39.901 22.266 40.711 ;
     RECT  23.184 40.711 23.202 40.973 ;
     RECT  7.815 39.917 15.174 40.981 ;
     RECT  7.815 40.981 15.21 41.021 ;
     RECT  17.172 40.711 22.41 41.021 ;
     RECT  17.172 41.021 21.726 41.035 ;
     RECT  77.364 40.559 83.934 41.035 ;
     RECT  2.415 34.655 2.697 41.071 ;
     RECT  3.492 38.749 5.418 41.071 ;
     RECT  72 40.667 76.374 41.071 ;
     RECT  16.92 41.035 21.726 41.099 ;
     RECT  77.364 41.035 84.006 41.131 ;
     RECT  84.852 40.205 85.482 41.131 ;
     RECT  16.92 41.099 21.69 41.215 ;
     RECT  72 41.071 76.446 41.275 ;
     RECT  77.364 41.131 85.482 41.413 ;
     RECT  77.364 41.413 85.518 41.449 ;
     RECT  86.292 41.419 86.31 41.449 ;
     RECT  44.1 40.667 71.118 41.513 ;
     RECT  72 41.275 76.482 41.513 ;
     RECT  72 41.513 72.897 41.549 ;
     RECT  77.22 41.449 85.518 41.549 ;
     RECT  8.964 41.021 15.21 41.611 ;
     RECT  16.704 41.215 21.69 41.611 ;
     RECT  2.415 41.071 5.418 41.639 ;
     RECT  72.36 41.549 72.897 41.639 ;
     RECT  86.292 41.449 86.382 41.707 ;
     RECT  7.815 41.021 8.097 41.791 ;
     RECT  8.964 41.611 21.69 41.791 ;
     RECT  73.908 41.513 76.482 41.881 ;
     RECT  77.22 41.549 78.297 41.881 ;
     RECT  79.092 41.549 85.518 41.909 ;
     RECT  73.908 41.881 78.297 42.017 ;
     RECT  44.1 41.513 71.082 42.025 ;
     RECT  43.956 42.025 71.082 42.029 ;
     RECT  80.208 41.909 85.518 42.029 ;
     RECT  43.956 42.029 71.046 42.089 ;
     RECT  43.956 42.089 71.01 42.179 ;
     RECT  73.908 42.017 76.41 42.179 ;
     RECT  79.092 41.909 79.326 42.179 ;
     RECT  2.415 41.639 4.734 42.187 ;
     RECT  7.815 41.791 21.69 42.187 ;
     RECT  2.34 42.187 4.734 42.251 ;
     RECT  7.815 42.187 22.158 42.283 ;
     RECT  73.908 42.179 75.222 42.359 ;
     RECT  74.052 42.359 75.222 42.449 ;
     RECT  75.132 42.449 75.222 42.521 ;
     RECT  86.256 41.707 86.382 42.557 ;
     RECT  76.392 42.179 76.41 42.593 ;
     RECT  77.364 42.017 78.297 42.601 ;
     RECT  79.092 42.179 79.29 42.601 ;
     RECT  7.815 42.283 22.266 42.719 ;
     RECT  80.208 42.029 85.446 42.719 ;
     RECT  7.815 42.719 15.966 42.755 ;
     RECT  16.74 42.719 22.266 42.755 ;
     RECT  85.356 42.719 85.446 42.755 ;
     RECT  74.052 42.449 74.07 42.827 ;
     RECT  85.428 42.755 85.446 42.827 ;
     RECT  2.415 42.251 4.734 42.863 ;
     RECT  22.608 42.763 22.734 42.989 ;
     RECT  77.364 42.601 79.29 42.989 ;
     RECT  80.208 42.719 84.402 43.025 ;
     RECT  78.015 42.989 79.29 43.169 ;
     RECT  80.244 43.025 84.402 43.259 ;
     RECT  78.015 43.169 78.714 43.331 ;
     RECT  81.54 43.259 84.402 43.601 ;
     RECT  7.815 42.755 15.426 43.681 ;
     RECT  7.815 43.681 15.534 43.771 ;
     RECT  16.74 42.755 21.69 43.771 ;
     RECT  81.54 43.601 84.366 43.799 ;
     RECT  7.815 43.771 15.606 43.807 ;
     RECT  16.416 43.771 21.69 43.807 ;
     RECT  81.972 43.799 84.366 43.907 ;
     RECT  75.132 42.521 75.15 44.069 ;
     RECT  7.815 43.807 21.69 44.249 ;
     RECT  2.415 42.863 3.978 44.311 ;
     RECT  86.328 42.557 86.382 44.339 ;
     RECT  43.956 42.179 70.902 44.347 ;
     RECT  81.972 43.907 84.258 44.375 ;
     RECT  43.884 44.347 70.902 44.419 ;
     RECT  22.608 42.989 22.626 44.443 ;
     RECT  81.972 44.375 81.99 44.447 ;
     RECT  82.728 44.375 84.258 44.447 ;
     RECT  2.304 44.311 3.978 44.455 ;
     RECT  4.716 42.863 4.734 44.455 ;
     RECT  43.632 44.419 70.902 44.581 ;
     RECT  22.608 44.443 22.734 44.609 ;
     RECT  86.328 44.339 86.346 44.609 ;
     RECT  2.304 44.455 4.734 44.725 ;
     RECT  7.815 44.249 21.654 44.725 ;
     RECT  43.56 44.581 70.902 44.761 ;
     RECT  2.268 44.725 4.734 44.879 ;
     RECT  22.608 44.609 22.626 44.879 ;
     RECT  43.524 44.761 70.902 44.879 ;
     RECT  82.728 44.447 83.97 44.879 ;
     RECT  82.728 44.879 83.697 44.915 ;
     RECT  7.776 44.725 21.654 45.019 ;
     RECT  2.268 44.879 4.194 45.023 ;
     RECT  43.524 44.879 70.506 45.031 ;
     RECT  2.268 45.023 2.934 45.053 ;
     RECT  24.015 39.389 24.297 45.107 ;
     RECT  29.415 27.917 29.697 45.107 ;
     RECT  34.815 29.057 35.097 45.107 ;
     RECT  40.215 29.561 40.497 45.107 ;
     RECT  72.615 41.639 72.897 45.107 ;
     RECT  78.015 43.331 78.297 45.107 ;
     RECT  83.415 44.915 83.697 45.107 ;
     RECT  3.708 45.023 3.726 45.149 ;
     RECT  7.776 45.019 22.554 45.149 ;
     RECT  43.164 45.031 70.506 45.149 ;
     RECT  17.856 45.149 19.89 45.197 ;
     RECT  20.664 45.149 21.474 45.197 ;
     RECT  47.052 45.149 49.734 45.197 ;
     RECT  54.936 45.149 59.058 45.197 ;
     RECT  2.376 45.053 2.934 45.221 ;
     RECT  20.664 45.197 20.682 45.221 ;
     RECT  47.052 45.197 48.942 45.221 ;
     RECT  52.812 45.149 54.198 45.221 ;
     RECT  54.936 45.197 58.95 45.221 ;
     RECT  59.868 45.149 60.066 45.221 ;
     RECT  60.804 45.149 69.534 45.221 ;
     RECT  43.164 45.149 44.874 45.265 ;
     RECT  7.776 45.149 16.902 45.293 ;
     RECT  7.776 45.293 15.714 45.301 ;
     RECT  18.216 45.197 19.89 45.329 ;
     RECT  42.948 45.265 44.874 45.329 ;
     RECT  52.92 45.221 54.198 45.329 ;
     RECT  55.224 45.221 58.95 45.329 ;
     RECT  59.868 45.221 59.958 45.329 ;
     RECT  60.804 45.221 60.822 45.329 ;
     RECT  61.815 45.221 63.558 45.329 ;
     RECT  64.404 45.221 69.534 45.329 ;
     RECT  22.32 45.149 22.338 45.341 ;
     RECT  47.052 45.221 48.33 45.341 ;
     RECT  50.472 45.149 51.678 45.341 ;
     RECT  66.996 45.329 69.534 45.341 ;
     RECT  7.452 45.301 15.714 45.377 ;
     RECT  24.015 45.107 24.105 45.377 ;
     RECT  29.415 45.107 29.505 45.377 ;
     RECT  34.815 45.107 34.905 45.377 ;
     RECT  40.215 45.107 40.305 45.377 ;
     RECT  45.615 45.149 46.206 45.377 ;
     RECT  51.015 45.341 51.678 45.377 ;
     RECT  55.224 45.329 57.942 45.377 ;
     RECT  61.815 45.329 62.55 45.377 ;
     RECT  72.615 45.107 72.705 45.377 ;
     RECT  78.015 45.107 78.105 45.377 ;
     RECT  83.415 45.107 83.505 45.377 ;
     RECT  21.456 45.197 21.474 45.389 ;
     RECT  66.996 45.341 69.462 45.389 ;
     RECT  8.496 45.377 15.714 45.485 ;
     RECT  45.972 45.377 46.206 45.485 ;
     RECT  61.956 45.377 62.55 45.485 ;
     RECT  7.452 45.377 7.47 45.491 ;
     RECT  2.376 45.221 2.826 45.533 ;
     RECT  18.216 45.329 19.278 45.533 ;
     RECT  51.156 45.377 51.678 45.533 ;
     RECT  55.224 45.377 55.854 45.533 ;
     RECT  62.208 45.485 62.55 45.533 ;
     RECT  65.304 45.329 66.186 45.533 ;
     RECT  66.996 45.389 68.958 45.533 ;
     RECT  8.496 45.485 13.014 45.563 ;
     RECT  2.376 45.533 2.574 45.581 ;
     RECT  8.604 45.563 13.014 45.581 ;
     RECT  13.968 45.485 15.714 45.581 ;
     RECT  16.668 45.293 16.902 45.581 ;
     RECT  19.26 45.533 19.278 45.581 ;
     RECT  42.948 45.329 44.334 45.581 ;
     RECT  47.088 45.341 48.33 45.581 ;
     RECT  49.716 45.197 49.734 45.581 ;
     RECT  53.568 45.329 54.198 45.581 ;
     RECT  55.224 45.533 55.674 45.581 ;
     RECT  56.952 45.377 57.942 45.581 ;
     RECT  59.868 45.329 59.886 45.581 ;
     RECT  63.324 45.329 63.558 45.581 ;
     RECT  64.404 45.329 64.422 45.581 ;
     RECT  65.304 45.533 65.322 45.581 ;
     RECT  66.168 45.533 66.186 45.581 ;
     RECT  66.996 45.533 67.014 45.581 ;
     RECT  68.22 45.533 68.958 45.581 ;
     RECT  2.376 45.581 2.394 45.773 ;
     RECT  12.996 45.581 13.014 46.157 ;
     RECT  14.004 45.581 15.174 46.157 ;
     RECT  10.476 45.581 12.078 46.205 ;
     RECT  47.088 45.581 47.574 46.205 ;
     RECT  10.476 46.205 11.934 46.301 ;
     RECT  14.004 46.157 14.742 46.733 ;
     RECT  47.556 46.205 47.574 46.733 ;
     RECT  8.604 45.581 9.594 46.781 ;
     RECT  11.088 46.301 11.934 46.781 ;
     RECT  18.216 45.533 18.234 46.781 ;
     RECT  42.948 45.581 43.29 46.781 ;
     RECT  54.18 45.581 54.198 46.781 ;
     RECT  9.36 46.781 9.378 46.829 ;
     RECT  11.268 46.781 11.934 46.829 ;
     RECT  43.272 46.781 43.29 46.829 ;
     RECT  8.604 46.781 8.622 46.877 ;
     RECT  62.28 45.533 62.55 46.891 ;
     RECT  17.172 46.891 17.442 47.069 ;
     RECT  60.84 46.987 60.858 47.165 ;
     RECT  61.596 46.891 62.55 47.213 ;
     RECT  51.66 45.533 51.678 47.261 ;
     RECT  57.384 45.581 57.402 47.261 ;
     RECT  52.632 47.227 52.65 47.275 ;
     RECT  62.28 47.213 62.55 47.275 ;
     RECT  62.28 47.275 62.694 47.357 ;
     RECT  11.916 46.829 11.934 47.405 ;
     RECT  14.004 46.733 14.022 47.405 ;
     RECT  44.964 47.227 44.982 47.405 ;
     RECT  46.188 45.485 46.206 47.405 ;
     RECT  49.32 47.275 49.338 47.405 ;
     RECT  50.292 47.275 50.31 47.405 ;
     RECT  51.804 47.275 53.262 47.405 ;
     RECT  56.232 47.275 56.25 47.405 ;
     RECT  57.276 47.275 57.294 47.405 ;
     RECT  61.02 47.275 61.038 47.405 ;
     RECT  62.532 47.357 62.694 47.405 ;
     RECT  63.504 47.227 63.522 47.405 ;
     RECT  67.752 47.275 67.77 47.405 ;
    LAYER M4 ;
     RECT  0.084 17.808 0.097 17.832 ;
     RECT  0.06 17.832 0.097 17.904 ;
     RECT  0.084 17.904 0.097 17.928 ;
     RECT  0.06 17.928 0.097 18 ;
     RECT  0.084 18 0.097 18.024 ;
     RECT  0.06 18.024 0.097 18.096 ;
     RECT  0.084 18.096 0.097 18.12 ;
     RECT  0.06 18.12 0.097 18.192 ;
     RECT  0.084 18.192 0.097 18.216 ;
     RECT  0.06 18.216 0.097 18.288 ;
     RECT  0.084 18.288 0.097 18.312 ;
     RECT  0.06 18.312 0.097 18.384 ;
     RECT  0.084 18.384 0.097 18.408 ;
     RECT  0.06 18.408 0.097 18.48 ;
     RECT  0.084 18.48 0.097 18.504 ;
     RECT  0.06 18.504 0.097 18.576 ;
     RECT  0.084 18.576 0.097 18.6 ;
     RECT  0.06 18.6 0.097 18.672 ;
     RECT  0.084 18.672 0.097 18.696 ;
     RECT  0.06 18.696 0.097 18.768 ;
     RECT  0.084 18.768 0.097 18.792 ;
     RECT  0.06 18.792 0.097 18.864 ;
     RECT  0.084 18.864 0.097 18.888 ;
     RECT  0.06 18.888 0.097 18.96 ;
     RECT  0.084 18.96 0.097 18.984 ;
     RECT  0.06 18.984 0.097 19.056 ;
     RECT  0.084 19.056 0.097 19.08 ;
     RECT  0.06 19.08 0.097 19.152 ;
     RECT  0.084 19.152 0.097 19.176 ;
     RECT  0.06 19.176 0.097 19.248 ;
     RECT  0.084 19.248 0.097 19.272 ;
     RECT  0.06 19.272 0.097 19.344 ;
     RECT  0.084 19.344 0.097 19.368 ;
     RECT  0.06 19.368 0.097 19.44 ;
     RECT  0.084 19.44 0.097 19.464 ;
     RECT  0.06 19.464 0.097 19.536 ;
     RECT  0.084 19.536 0.097 19.56 ;
     RECT  0.06 19.56 0.097 19.632 ;
     RECT  0.084 19.632 0.097 19.656 ;
     RECT  0.06 19.656 0.097 19.728 ;
     RECT  0.084 19.728 0.097 19.752 ;
     RECT  0.06 19.752 0.097 19.824 ;
     RECT  0.084 19.824 0.097 19.848 ;
     RECT  0.06 19.848 0.097 19.92 ;
     RECT  0.084 19.92 0.097 19.944 ;
     RECT  0.06 19.944 0.097 20.016 ;
     RECT  0.084 20.016 0.097 20.04 ;
     RECT  0.06 20.04 0.097 20.112 ;
     RECT  0.084 20.112 0.097 20.136 ;
     RECT  0.06 20.136 0.097 20.208 ;
     RECT  0.084 20.208 0.097 20.232 ;
     RECT  0.06 20.232 0.097 20.304 ;
     RECT  0.084 20.304 0.097 20.328 ;
     RECT  0.06 20.328 0.097 20.4 ;
     RECT  0.084 20.4 0.097 20.424 ;
     RECT  0.06 20.424 0.097 20.496 ;
     RECT  0.084 20.496 0.097 20.52 ;
     RECT  0.06 20.52 0.097 20.592 ;
     RECT  0.084 20.592 0.097 20.616 ;
     RECT  0.06 20.616 0.097 20.688 ;
     RECT  0.084 20.688 0.097 20.712 ;
     RECT  0.06 20.712 0.097 20.784 ;
     RECT  0.084 20.784 0.097 20.808 ;
     RECT  0.06 20.808 0.097 20.88 ;
     RECT  0.084 20.88 0.097 20.904 ;
     RECT  0.06 20.904 0.097 20.976 ;
     RECT  0.084 20.976 0.097 21 ;
     RECT  0.06 21 0.097 21.072 ;
     RECT  0.084 21.072 0.097 21.096 ;
     RECT  0.06 21.096 0.097 21.168 ;
     RECT  0.084 21.168 0.097 21.192 ;
     RECT  0.06 21.192 0.097 21.264 ;
     RECT  0.084 21.264 0.097 21.288 ;
     RECT  0.06 21.288 0.097 21.36 ;
     RECT  0.084 21.36 0.097 21.384 ;
     RECT  0.06 21.384 0.097 21.456 ;
     RECT  0.084 21.456 0.097 21.48 ;
     RECT  0.06 21.48 0.097 21.552 ;
     RECT  0.084 21.552 0.097 21.576 ;
     RECT  0.06 21.576 0.097 21.648 ;
     RECT  0.084 21.648 0.097 21.672 ;
     RECT  0.06 21.672 0.097 21.744 ;
     RECT  0.084 21.744 0.097 21.768 ;
     RECT  0.06 21.768 0.097 21.84 ;
     RECT  0.084 21.84 0.097 21.864 ;
     RECT  0.06 21.864 0.097 21.936 ;
     RECT  0.084 21.936 0.097 21.96 ;
     RECT  0.084 27.024 0.133 27.048 ;
     RECT  0.06 27.048 0.133 27.12 ;
     RECT  0.084 27.12 0.133 27.144 ;
     RECT  0.06 27.144 0.133 27.216 ;
     RECT  0.084 27.216 0.133 27.24 ;
     RECT  0.06 27.24 0.133 27.312 ;
     RECT  0.084 27.312 0.133 27.336 ;
     RECT  0.06 27.336 0.133 27.408 ;
     RECT  0.084 27.408 0.133 27.432 ;
     RECT  0.06 27.432 0.133 27.504 ;
     RECT  0.084 27.504 0.133 27.528 ;
     RECT  0.06 27.528 0.133 27.6 ;
     RECT  0.084 27.6 0.133 27.624 ;
     RECT  0.06 27.624 0.133 27.696 ;
     RECT  0.084 27.696 0.133 27.72 ;
     RECT  0.06 27.72 0.133 27.792 ;
     RECT  0.084 27.792 0.133 27.816 ;
     RECT  0.06 27.816 0.133 27.888 ;
     RECT  0.084 27.888 0.133 27.912 ;
     RECT  0.06 27.912 0.133 27.984 ;
     RECT  0.084 27.984 0.133 28.008 ;
     RECT  0.06 28.008 0.133 28.08 ;
     RECT  0.084 28.08 0.133 28.104 ;
     RECT  0.06 28.104 0.133 28.176 ;
     RECT  0.084 28.176 0.133 28.2 ;
     RECT  0.06 28.2 0.133 28.272 ;
     RECT  0.084 28.272 0.133 28.296 ;
     RECT  0.06 28.296 0.133 28.368 ;
     RECT  0.084 28.368 0.133 28.392 ;
     RECT  0.06 28.392 0.133 28.464 ;
     RECT  0.084 28.464 0.133 28.488 ;
     RECT  0.06 28.488 0.133 28.56 ;
     RECT  0.084 28.56 0.133 28.584 ;
     RECT  0.06 28.584 0.133 28.656 ;
     RECT  0.084 28.656 0.133 28.68 ;
     RECT  0.06 28.68 0.133 28.752 ;
     RECT  0.084 28.752 0.133 28.776 ;
     RECT  0.06 28.776 0.133 28.848 ;
     RECT  0.084 28.848 0.133 28.872 ;
     RECT  0.06 28.872 0.133 28.944 ;
     RECT  0.084 28.944 0.133 28.968 ;
     RECT  0.06 28.968 0.133 29.04 ;
     RECT  0.084 29.04 0.133 29.064 ;
     RECT  0.06 29.064 0.133 29.136 ;
     RECT  0.084 29.136 0.133 29.16 ;
     RECT  0.06 29.16 0.133 29.232 ;
     RECT  0.084 29.232 0.133 29.256 ;
     RECT  0.06 29.256 0.133 29.328 ;
     RECT  0.084 29.328 0.133 29.352 ;
     RECT  0.06 29.352 0.133 29.424 ;
     RECT  0.084 29.424 0.133 29.448 ;
     RECT  0.06 29.448 0.133 29.52 ;
     RECT  0.084 29.52 0.133 29.544 ;
     RECT  0.06 29.544 0.133 29.616 ;
     RECT  0.084 29.616 0.133 29.64 ;
     RECT  0.06 29.64 0.133 29.712 ;
     RECT  0.084 29.712 0.133 29.736 ;
     RECT  0.06 29.736 0.133 29.808 ;
     RECT  0.084 29.808 0.133 29.832 ;
     RECT  0.06 29.832 0.133 29.904 ;
     RECT  0.084 29.904 0.133 29.928 ;
     RECT  0.06 29.928 0.133 30 ;
     RECT  0.084 30 0.133 30.024 ;
     RECT  0.084 24.72 0.137 24.744 ;
     RECT  0.06 24.744 0.137 25.488 ;
     RECT  0.084 25.488 0.137 25.512 ;
     RECT  0.06 25.512 0.137 25.584 ;
     RECT  0.084 25.584 0.137 25.608 ;
     RECT  0.06 25.608 0.137 25.68 ;
     RECT  0.084 25.68 0.137 25.704 ;
     RECT  0.06 25.704 0.137 25.776 ;
     RECT  0.084 25.776 0.137 25.8 ;
     RECT  0.133 27.024 0.137 30.072 ;
     RECT  0.084 32.016 0.137 32.04 ;
     RECT  0.06 32.04 0.137 32.112 ;
     RECT  0.084 32.112 0.137 32.136 ;
     RECT  0.06 32.136 0.137 32.208 ;
     RECT  0.084 32.208 0.137 32.232 ;
     RECT  0.06 32.232 0.137 32.304 ;
     RECT  0.084 32.304 0.137 32.328 ;
     RECT  0.06 32.328 0.137 32.4 ;
     RECT  0.084 32.4 0.137 32.424 ;
     RECT  0.06 32.424 0.137 32.496 ;
     RECT  0.084 32.496 0.137 32.52 ;
     RECT  0.06 32.52 0.137 32.592 ;
     RECT  0.084 32.592 0.137 32.616 ;
     RECT  0.06 32.616 0.137 32.688 ;
     RECT  0.084 32.688 0.137 32.712 ;
     RECT  0.06 32.712 0.137 32.784 ;
     RECT  0.084 32.784 0.137 32.808 ;
     RECT  0.06 32.808 0.137 32.88 ;
     RECT  0.084 32.88 0.137 32.904 ;
     RECT  0.06 32.904 0.137 32.976 ;
     RECT  0.084 32.976 0.137 33 ;
     RECT  0.06 33 0.137 33.072 ;
     RECT  0.084 33.072 0.137 33.096 ;
     RECT  0.084 2.64 0.173 2.664 ;
     RECT  0.06 2.664 0.173 2.736 ;
     RECT  0.084 2.736 0.173 2.76 ;
     RECT  0.06 2.76 0.173 2.832 ;
     RECT  0.084 2.832 0.173 2.856 ;
     RECT  0.06 2.856 0.173 2.928 ;
     RECT  0.084 2.928 0.173 2.952 ;
     RECT  0.137 27.12 0.173 30.072 ;
     RECT  0.137 32.112 0.173 33.096 ;
     RECT  0.133 23.04 0.179 23.592 ;
     RECT  0.173 27.216 0.209 30.072 ;
     RECT  0.209 27.312 0.245 30.072 ;
     RECT  0.097 17.808 0.569 22.056 ;
     RECT  0.137 25.44 0.569 25.704 ;
     RECT  1.853 1.728 1.925 1.752 ;
     RECT  0.173 2.736 1.925 2.952 ;
     RECT  1.925 1.728 2.117 2.952 ;
     RECT  2.117 1.776 2.225 2.952 ;
     RECT  2.149 45.024 2.245 45.768 ;
     RECT  0.245 27.408 2.401 30.072 ;
     RECT  2.245 44.448 2.405 45.768 ;
     RECT  2.225 2.148 2.408 2.952 ;
     RECT  0.569 17.904 2.408 22.056 ;
     RECT  0.179 23.04 2.408 23.064 ;
     RECT  2.401 24.096 2.408 24.12 ;
     RECT  0.569 25.44 2.408 25.512 ;
     RECT  2.401 27.408 2.408 30.12 ;
     RECT  0.173 32.208 2.408 33.096 ;
     RECT  2.329 42.192 2.408 42.216 ;
     RECT  2.405 44.448 2.408 45.576 ;
     RECT  2.408 2.148 2.512 45.576 ;
     RECT  2.512 2.418 2.585 45.576 ;
     RECT  2.585 2.418 2.704 45.528 ;
     RECT  2.704 17.904 2.765 22.056 ;
     RECT  2.765 21.936 2.801 22.056 ;
     RECT  2.765 17.904 2.837 20.952 ;
     RECT  2.704 45.504 2.837 45.528 ;
     RECT  2.704 2.418 2.873 3.624 ;
     RECT  2.704 41.136 2.915 42.84 ;
     RECT  2.704 23.04 3.125 33.576 ;
     RECT  3.125 32.448 3.197 33.576 ;
     RECT  2.837 18.096 3.233 20.952 ;
     RECT  3.125 23.04 3.341 31.368 ;
     RECT  3.341 23.04 3.347 29.592 ;
     RECT  2.915 42.816 3.477 42.84 ;
     RECT  2.915 41.136 3.593 41.736 ;
     RECT  2.704 44.448 3.629 44.472 ;
     RECT  3.589 2.352 3.973 2.376 ;
     RECT  2.873 3.6 3.973 3.624 ;
     RECT  3.341 30.816 3.997 31.368 ;
     RECT  2.801 22.032 4.021 22.056 ;
     RECT  3.197 32.448 4.169 33.384 ;
     RECT  3.233 18.096 4.201 20.424 ;
     RECT  4.021 21.552 4.201 22.056 ;
     RECT  4.169 33.36 4.237 33.384 ;
     RECT  3.997 30.864 4.309 31.368 ;
     RECT  4.201 18.096 4.381 22.056 ;
     RECT  4.381 18.048 4.561 22.056 ;
     RECT  3.347 23.04 4.561 23.304 ;
     RECT  3.347 24.384 4.561 29.592 ;
     RECT  4.561 23.04 4.601 29.592 ;
     RECT  4.561 17.712 4.633 22.056 ;
     RECT  4.601 23.04 4.633 24.072 ;
     RECT  3.973 2.352 4.849 3.624 ;
     RECT  4.849 2.208 5.065 3.624 ;
     RECT  4.633 17.712 5.077 24.072 ;
     RECT  5.065 2.208 5.137 4.488 ;
     RECT  4.601 25.152 5.173 29.592 ;
     RECT  4.309 30.864 5.353 32.328 ;
     RECT  4.237 33.36 5.353 33.624 ;
     RECT  5.353 30.864 5.461 34.056 ;
     RECT  5.173 25.152 5.592 29.736 ;
     RECT  5.461 30.72 5.592 34.056 ;
     RECT  5.137 2.064 5.641 4.488 ;
     RECT  5.641 1.152 5.749 4.488 ;
     RECT  5.749 0.528 5.785 4.488 ;
     RECT  5.785 0.432 5.821 4.488 ;
     RECT  5.077 17.52 5.933 24.072 ;
     RECT  5.933 18.432 6.035 24.072 ;
     RECT  5.592 25.152 6.041 34.056 ;
     RECT  5.821 0.336 6.073 4.488 ;
     RECT  6.001 16.896 6.073 17.448 ;
     RECT  6.073 16.8 6.181 17.448 ;
     RECT  6.041 31.968 6.293 34.056 ;
     RECT  6.073 0.336 6.325 4.968 ;
     RECT  6.325 0.336 6.329 5.016 ;
     RECT  6.293 33.024 6.329 34.056 ;
     RECT  6.181 16.032 6.361 17.448 ;
     RECT  6.329 3.504 6.401 5.016 ;
     RECT  6.035 18.432 6.437 23.688 ;
     RECT  6.293 31.968 6.761 31.992 ;
     RECT  6.361 15.792 6.812 17.448 ;
     RECT  6.329 0.336 7.141 2.328 ;
     RECT  6.401 4.176 7.261 5.016 ;
     RECT  5.317 6 7.261 6.024 ;
     RECT  6.329 33.024 7.261 33.384 ;
     RECT  6.812 15.504 7.297 17.448 ;
     RECT  6.437 18.432 7.297 19.752 ;
     RECT  7.261 4.176 7.333 6.024 ;
     RECT  6.041 25.152 7.333 30.888 ;
     RECT  7.141 0.096 7.373 2.328 ;
     RECT  7.333 4.176 7.429 6.12 ;
     RECT  6.437 20.832 7.477 23.688 ;
     RECT  7.333 25.104 7.477 30.888 ;
     RECT  7.373 0.144 7.571 2.328 ;
     RECT  7.261 32.4 7.585 33.384 ;
     RECT  7.571 0.144 7.763 0.264 ;
     RECT  7.585 32.4 7.801 33.864 ;
     RECT  7.571 1.728 7.808 2.328 ;
     RECT  7.429 3.408 7.808 6.12 ;
     RECT  7.669 8.304 7.808 8.328 ;
     RECT  7.297 15.504 7.808 19.752 ;
     RECT  7.477 20.832 7.808 30.888 ;
     RECT  7.801 32.4 7.808 34.392 ;
     RECT  3.593 41.712 7.808 41.736 ;
     RECT  7.763 0.192 7.859 0.264 ;
     RECT  7.808 1.728 7.912 45.372 ;
     RECT  7.859 0.192 7.955 0.216 ;
     RECT  7.912 1.728 8.104 45.102 ;
     RECT  8.104 3.408 8.165 6.12 ;
     RECT  8.104 31.872 8.165 34.392 ;
     RECT  8.165 3.408 8.597 3.432 ;
     RECT  8.104 40.992 8.857 42.216 ;
     RECT  8.593 46.848 8.953 46.872 ;
     RECT  8.104 44.448 9.025 45.102 ;
     RECT  8.104 21.456 9.097 23.544 ;
     RECT  8.104 24.96 9.097 30.84 ;
     RECT  9.025 44.448 9.097 45.624 ;
     RECT  8.953 46.752 9.097 46.872 ;
     RECT  8.165 31.872 9.101 32.52 ;
     RECT  8.104 15.936 9.133 20.184 ;
     RECT  9.097 21.456 9.133 30.84 ;
     RECT  8.857 40.992 9.245 41.976 ;
     RECT  9.241 0.528 9.253 0.552 ;
     RECT  8.104 1.728 9.308 2.088 ;
     RECT  8.165 4.56 9.413 6.12 ;
     RECT  9.245 41.616 9.443 41.976 ;
     RECT  8.104 7.296 9.529 7.32 ;
     RECT  9.253 0.096 9.533 0.552 ;
     RECT  9.413 3.984 9.541 6.12 ;
     RECT  8.104 37.872 9.565 37.896 ;
     RECT  9.533 0.528 9.587 0.552 ;
     RECT  9.133 15.936 9.637 30.84 ;
     RECT  9.097 44.448 9.673 46.872 ;
     RECT  9.101 32.112 9.677 32.52 ;
     RECT  9.565 37.872 9.677 38.808 ;
     RECT  9.589 39.888 9.677 39.912 ;
     RECT  9.529 7.296 9.713 7.464 ;
     RECT  9.308 1.68 9.733 2.088 ;
     RECT  9.673 44.064 9.925 46.872 ;
     RECT  9.541 3.984 10.021 6.264 ;
     RECT  9.637 15.504 10.141 30.84 ;
     RECT  9.677 32.112 10.141 32.472 ;
     RECT  9.443 41.952 10.141 41.976 ;
     RECT  10.141 15.504 10.145 32.472 ;
     RECT  10.021 3.408 10.289 6.264 ;
     RECT  9.637 36.384 10.289 36.408 ;
     RECT  10.289 3.408 10.325 3.432 ;
     RECT  9.925 43.728 10.355 46.872 ;
     RECT  10.355 44.448 10.451 46.872 ;
     RECT  10.145 15.936 10.469 32.472 ;
     RECT  10.141 41.952 10.501 42.024 ;
     RECT  9.733 0.816 10.597 2.088 ;
     RECT  10.469 15.936 10.613 32.376 ;
     RECT  10.597 0.816 10.673 2.376 ;
     RECT  10.673 0.144 10.717 2.376 ;
     RECT  10.717 0.048 10.789 2.376 ;
     RECT  10.451 44.448 10.865 46.824 ;
     RECT  10.613 15.936 10.901 30.792 ;
     RECT  10.865 44.976 10.931 46.824 ;
     RECT  10.289 4.56 10.937 6.264 ;
     RECT  9.713 7.44 10.973 7.464 ;
     RECT  10.501 41.568 11.149 42.024 ;
     RECT  10.937 4.56 11.153 5.16 ;
     RECT  10.931 44.976 11.189 45.576 ;
     RECT  11.149 41.04 11.269 42.024 ;
     RECT  10.825 43.104 11.269 43.128 ;
     RECT  11.269 41.04 11.329 43.128 ;
     RECT  11.329 41.04 11.437 43.608 ;
     RECT  10.901 15.936 11.617 29.688 ;
     RECT  10.931 46.752 11.653 46.824 ;
     RECT  10.789 0.048 11.761 2.856 ;
     RECT  11.437 40.944 11.765 43.608 ;
     RECT  8.165 33.84 11.909 34.392 ;
     RECT  11.653 46.752 11.945 47.4 ;
     RECT  11.189 45.024 11.987 45.576 ;
     RECT  10.901 30.768 11.989 30.792 ;
     RECT  10.613 32.112 11.989 32.376 ;
     RECT  11.153 5.136 12.017 5.16 ;
     RECT  11.909 34.368 12.035 34.392 ;
     RECT  11.987 45.504 12.049 45.576 ;
     RECT  11.945 46.752 12.049 46.776 ;
     RECT  12.049 45.504 12.083 46.776 ;
     RECT  12.083 45.504 12.179 46.2 ;
     RECT  11.989 30.768 12.229 32.376 ;
     RECT  10.937 6.24 12.265 6.264 ;
     RECT  11.617 15.84 12.337 29.688 ;
     RECT  12.229 30.768 12.337 33.096 ;
     RECT  11.765 40.944 12.337 43.32 ;
     RECT  12.265 6.096 12.373 6.264 ;
     RECT  11.761 0.048 12.409 3.672 ;
     RECT  9.677 37.872 12.445 38.76 ;
     RECT  12.445 37.872 12.517 39.048 ;
     RECT  12.337 40.464 12.805 43.32 ;
     RECT  12.373 6.096 13.021 6.792 ;
     RECT  12.179 45.504 13.025 46.152 ;
     RECT  12.409 0.048 13.057 3.864 ;
     RECT  13.057 0.048 13.208 4.44 ;
     RECT  13.021 5.568 13.208 6.792 ;
     RECT  12.337 15.84 13.208 33.096 ;
     RECT  10.789 36.528 13.208 36.552 ;
     RECT  12.517 37.872 13.208 39.24 ;
     RECT  12.805 40.464 13.208 43.944 ;
     RECT  13.025 45.504 13.208 45.576 ;
     RECT  13.093 47.184 13.237 47.352 ;
     RECT  13.208 0.048 13.504 45.576 ;
     RECT  13.237 47.088 13.573 47.352 ;
     RECT  13.504 16.272 13.637 23.064 ;
     RECT  13.573 47.088 13.667 47.4 ;
     RECT  13.637 20.304 13.673 23.064 ;
     RECT  13.504 40.944 13.781 40.968 ;
     RECT  13.673 20.304 13.817 22.056 ;
     RECT  13.504 5.568 13.853 6.264 ;
     RECT  13.637 16.272 13.889 19.32 ;
     RECT  13.504 36.528 13.889 36.552 ;
     RECT  13.504 42.336 13.997 45.576 ;
     RECT  13.667 47.376 14.033 47.4 ;
     RECT  13.504 39.216 14.069 39.912 ;
     RECT  13.997 42.336 14.105 45.048 ;
     RECT  13.889 16.368 14.141 19.32 ;
     RECT  14.105 43.488 14.141 45.048 ;
     RECT  14.141 45.024 14.195 45.048 ;
     RECT  13.504 37.584 14.221 37.608 ;
     RECT  14.141 17.376 14.249 17.448 ;
     RECT  14.141 18.528 14.249 19.32 ;
     RECT  14.249 19.296 14.285 19.32 ;
     RECT  13.504 28.272 14.321 31.992 ;
     RECT  14.141 43.488 14.321 43.896 ;
     RECT  14.141 16.368 14.393 16.392 ;
     RECT  14.321 43.824 14.501 43.896 ;
     RECT  13.673 23.04 14.533 23.064 ;
     RECT  13.504 25.2 14.533 27.144 ;
     RECT  13.504 0.048 14.573 4.584 ;
     RECT  14.573 0.048 14.825 4.152 ;
     RECT  14.249 17.424 14.825 17.448 ;
     RECT  14.825 0.048 14.861 0.936 ;
     RECT  14.321 28.272 14.897 30.744 ;
     RECT  14.825 2.352 15.005 4.152 ;
     RECT  14.533 23.04 15.013 23.352 ;
     RECT  14.533 24.528 15.013 27.144 ;
     RECT  14.861 0.048 15.077 0.888 ;
     RECT  15.005 2.544 15.077 4.152 ;
     RECT  15.013 23.04 15.1 27.144 ;
     RECT  14.965 45.312 15.145 45.336 ;
     RECT  14.713 46.704 15.145 46.728 ;
     RECT  15.077 0.048 15.149 0.84 ;
     RECT  13.817 20.304 15.185 20.328 ;
     RECT  15.1 24.528 15.217 27.144 ;
     RECT  14.897 28.272 15.217 30.36 ;
     RECT  14.069 39.216 15.253 39.528 ;
     RECT  15.145 45.312 15.347 46.728 ;
     RECT  14.105 42.336 15.356 42.36 ;
     RECT  15.356 42.336 15.397 42.6 ;
     RECT  14.501 43.872 15.397 43.896 ;
     RECT  15.347 45.312 15.397 46.152 ;
     RECT  15.077 2.544 15.401 3.96 ;
     RECT  15.217 24.528 15.437 30.36 ;
     RECT  15.401 3.168 15.545 3.96 ;
     RECT  15.397 42.192 15.589 42.6 ;
     RECT  15.397 43.872 15.617 46.152 ;
     RECT  15.437 24.528 15.653 28.296 ;
     RECT  15.577 38.16 15.685 38.184 ;
     RECT  15.253 39.216 15.685 39.912 ;
     RECT  15.545 3.936 15.725 3.96 ;
     RECT  15.617 43.92 15.731 46.152 ;
     RECT  15.653 24.528 15.797 25.224 ;
     RECT  15.589 41.616 15.925 42.6 ;
     RECT  15.437 29.328 15.937 30.36 ;
     RECT  15.925 41.616 16.012 42.744 ;
     RECT  15.685 38.16 16.028 39.912 ;
     RECT  15.149 0.816 16.265 0.84 ;
     RECT  14.321 31.968 16.265 31.992 ;
     RECT  15.797 24.624 16.301 25.224 ;
     RECT  15.1 23.04 16.333 23.064 ;
     RECT  13.817 21.648 16.357 22.056 ;
     RECT  16.012 41.616 16.405 42.648 ;
     RECT  16.357 20.976 16.444 22.056 ;
     RECT  16.444 21.936 16.481 22.056 ;
     RECT  16.028 38.016 16.553 39.912 ;
     RECT  15.653 26.208 16.625 28.296 ;
     RECT  15.937 29.328 16.657 30.984 ;
     RECT  16.481 22.032 16.693 22.056 ;
     RECT  16.333 23.04 16.693 23.352 ;
     RECT  16.657 29.04 16.697 30.984 ;
     RECT  16.405 41.232 16.909 42.648 ;
     RECT  15.731 43.92 16.979 45.576 ;
     RECT  16.909 41.04 16.981 42.648 ;
     RECT  16.979 43.92 17.084 45.192 ;
     RECT  17.077 47.136 17.117 47.16 ;
     RECT  17.117 47.04 17.125 47.16 ;
     RECT  16.625 26.208 17.129 27.912 ;
     RECT  16.981 41.04 17.173 42.696 ;
     RECT  17.084 43.68 17.173 45.192 ;
     RECT  16.553 38.688 17.197 39.912 ;
     RECT  17.173 41.04 17.197 45.192 ;
     RECT  16.697 29.04 17.309 30.36 ;
     RECT  15.901 19.632 17.413 19.656 ;
     RECT  17.372 20.688 17.413 20.712 ;
     RECT  17.413 19.632 17.459 20.712 ;
     RECT  16.301 25.2 17.557 25.224 ;
     RECT  13.853 6.24 17.629 6.264 ;
     RECT  16.933 37.584 17.629 37.608 ;
     RECT  16.693 22.032 17.701 23.352 ;
     RECT  17.629 37.296 17.756 37.608 ;
     RECT  17.089 0.576 17.785 0.6 ;
     RECT  17.797 1.728 17.884 1.752 ;
     RECT  17.125 46.8 17.893 47.16 ;
     RECT  17.756 37.008 17.953 37.608 ;
     RECT  17.197 38.688 17.953 45.192 ;
     RECT  17.893 46.8 17.989 47.208 ;
     RECT  17.989 46.8 18.205 47.304 ;
     RECT  18.085 2.88 18.277 2.904 ;
     RECT  17.557 24.336 18.313 25.224 ;
     RECT  17.129 26.88 18.313 27.912 ;
     RECT  18.205 46.752 18.323 47.304 ;
     RECT  18.277 2.88 18.325 3.336 ;
     RECT  18.323 47.28 18.325 47.304 ;
     RECT  18.325 0.192 18.421 0.216 ;
     RECT  17.953 37.008 18.421 45.192 ;
     RECT  17.884 1.728 18.565 1.8 ;
     RECT  18.325 2.88 18.565 3.624 ;
     RECT  18.565 1.728 18.608 3.624 ;
     RECT  17.629 6.096 18.608 6.264 ;
     RECT  17.459 19.632 18.608 20.184 ;
     RECT  17.701 21.264 18.608 23.352 ;
     RECT  18.313 24.336 18.608 27.912 ;
     RECT  17.309 29.04 18.608 29.784 ;
     RECT  18.421 37.008 18.608 45.576 ;
     RECT  18.421 0.144 18.611 0.216 ;
     RECT  18.611 0.192 18.707 0.216 ;
     RECT  18.608 1.728 18.904 45.576 ;
     RECT  18.904 21.792 18.965 30.216 ;
     RECT  18.904 19.344 19.117 19.368 ;
     RECT  18.965 21.84 19.187 30.216 ;
     RECT  18.325 47.28 19.235 47.352 ;
     RECT  18.904 36.96 19.379 45.576 ;
     RECT  19.379 36.96 19.397 45.144 ;
     RECT  19.187 29.328 19.427 30.216 ;
     RECT  19.397 37.584 19.475 45.144 ;
     RECT  19.475 37.584 19.523 39.768 ;
     RECT  19.523 37.584 19.649 39.72 ;
     RECT  18.904 2.88 19.721 6.12 ;
     RECT  19.475 40.8 19.793 45.144 ;
     RECT  19.235 47.328 19.811 47.352 ;
     RECT  19.721 3.408 19.865 6.12 ;
     RECT  19.865 3.984 19.901 6.12 ;
     RECT  19.901 4.128 19.909 6.12 ;
     RECT  19.909 18.816 20.045 18.84 ;
     RECT  18.904 1.728 20.293 1.8 ;
     RECT  20.293 1.728 20.389 1.848 ;
     RECT  19.649 37.584 20.401 39.336 ;
     RECT  19.187 21.84 20.477 28.344 ;
     RECT  20.401 37.008 20.531 39.336 ;
     RECT  19.793 40.8 20.54 42.264 ;
     RECT  20.531 37.584 20.675 39.336 ;
     RECT  19.793 43.296 20.773 45.144 ;
     RECT  19.427 30.192 20.801 30.216 ;
     RECT  19.909 4.128 20.905 6.264 ;
     RECT  20.477 22.8 20.909 28.344 ;
     RECT  20.54 40.416 20.917 42.264 ;
     RECT  20.773 43.296 20.917 45.336 ;
     RECT  20.905 4.032 20.965 6.264 ;
     RECT  20.917 40.416 21.233 45.336 ;
     RECT  21.233 43.92 21.253 45.336 ;
     RECT  21.253 43.92 21.299 45.384 ;
     RECT  20.675 38.448 21.308 39.336 ;
     RECT  21.233 40.416 21.308 42.744 ;
     RECT  20.909 22.8 21.377 27.48 ;
     RECT  21.308 38.448 21.395 42.744 ;
     RECT  21.395 39.504 21.413 42.744 ;
     RECT  21.299 44.448 21.485 45.384 ;
     RECT  21.377 22.8 21.593 27.336 ;
     RECT  20.389 1.728 21.617 2.28 ;
     RECT  21.617 1.152 21.701 2.28 ;
     RECT  21.413 39.504 21.737 41.064 ;
     RECT  21.593 22.8 21.773 27.288 ;
     RECT  21.395 38.448 21.779 38.472 ;
     RECT  21.737 39.504 21.779 41.016 ;
     RECT  21.773 26.976 21.845 27.288 ;
     RECT  21.779 39.648 21.923 41.016 ;
     RECT  21.413 42.192 22.169 42.744 ;
     RECT  20.965 3.408 22.268 6.264 ;
     RECT  21.923 40.464 22.277 41.016 ;
     RECT  22.169 42.288 22.277 42.744 ;
     RECT  21.485 44.448 22.349 45.336 ;
     RECT  21.701 1.728 22.355 2.28 ;
     RECT  22.268 3.408 22.355 6.792 ;
     RECT  22.277 40.992 22.465 41.016 ;
     RECT  21.773 22.8 22.565 25.896 ;
     RECT  22.355 3.408 22.669 6.216 ;
     RECT  22.669 2.928 22.745 6.216 ;
     RECT  22.405 42.768 22.745 42.792 ;
     RECT  22.349 44.448 22.745 44.472 ;
     RECT  22.745 2.928 22.753 6.12 ;
     RECT  22.355 1.728 22.789 1.944 ;
     RECT  22.789 1.152 22.876 1.944 ;
     RECT  22.565 24.048 22.993 25.896 ;
     RECT  21.845 27.024 22.993 27.288 ;
     RECT  22.876 1.728 23.605 1.944 ;
     RECT  22.565 22.8 23.852 23.064 ;
     RECT  23.852 22.656 23.893 23.064 ;
     RECT  22.993 24.048 23.893 27.288 ;
     RECT  23.605 1.728 23.897 2.28 ;
     RECT  23.897 1.776 24.008 2.28 ;
     RECT  22.753 3.84 24.008 6.12 ;
     RECT  20.941 21.648 24.008 21.672 ;
     RECT  23.893 22.656 24.008 27.288 ;
     RECT  23.101 28.464 24.008 28.488 ;
     RECT  24.008 1.776 24.112 45.372 ;
     RECT  24.112 1.776 24.304 45.102 ;
     RECT  24.304 1.776 24.401 6.12 ;
     RECT  24.401 1.776 24.473 5.64 ;
     RECT  24.304 22.8 24.509 27.144 ;
     RECT  24.473 3.408 24.653 5.64 ;
     RECT  24.509 24.144 24.653 27.144 ;
     RECT  24.653 3.408 24.761 5.208 ;
     RECT  24.473 1.776 24.905 1.8 ;
     RECT  24.761 3.408 25.229 4.92 ;
     RECT  25.229 3.744 25.379 4.92 ;
     RECT  24.509 22.8 26.149 23.16 ;
     RECT  24.653 24.336 26.149 27.144 ;
     RECT  26.149 22.8 26.195 27.144 ;
     RECT  26.195 25.2 26.417 27.144 ;
     RECT  26.417 25.44 26.771 27.144 ;
     RECT  26.771 27.12 26.773 27.144 ;
     RECT  26.773 27.12 27.349 27.336 ;
     RECT  24.304 28.464 27.349 28.488 ;
     RECT  26.195 22.8 27.497 23.976 ;
     RECT  27.349 27.12 28.609 28.488 ;
     RECT  28.609 27.12 29.185 28.536 ;
     RECT  25.379 4.656 29.293 4.92 ;
     RECT  29.293 4.656 29.408 5.016 ;
     RECT  27.497 22.8 29.408 23.064 ;
     RECT  26.771 25.44 29.408 26.04 ;
     RECT  29.185 27.072 29.408 28.536 ;
     RECT  29.408 2.148 29.512 45.372 ;
     RECT  29.512 2.418 29.704 45.102 ;
     RECT  29.704 4.656 30.665 5.016 ;
     RECT  30.665 4.848 30.701 5.016 ;
     RECT  29.704 26.832 31.385 28.536 ;
     RECT  31.385 26.88 31.525 28.536 ;
     RECT  31.345 25.296 32.717 25.32 ;
     RECT  31.525 26.88 33.761 28.68 ;
     RECT  33.761 27.12 34.765 28.68 ;
     RECT  30.701 4.848 34.808 4.872 ;
     RECT  29.704 22.8 34.808 23.064 ;
     RECT  34.765 27.12 34.808 28.728 ;
     RECT  34.808 2.148 34.912 45.372 ;
     RECT  34.912 2.418 35.104 45.102 ;
     RECT  35.104 27.12 36.995 28.728 ;
     RECT  36.995 28.176 36.997 28.728 ;
     RECT  35.104 4.896 40.208 4.92 ;
     RECT  35.104 22.8 40.208 23.064 ;
     RECT  36.995 27.12 40.208 27.144 ;
     RECT  36.997 28.176 40.208 28.872 ;
     RECT  40.208 2.148 40.312 45.372 ;
     RECT  40.312 2.418 40.504 45.102 ;
     RECT  40.504 22.8 41.965 22.824 ;
     RECT  41.965 22.8 42.005 23.064 ;
     RECT  42.145 30.816 42.329 30.84 ;
     RECT  40.504 28.128 42.509 28.728 ;
     RECT  40.504 4.896 42.757 4.92 ;
     RECT  42.509 28.128 42.977 28.488 ;
     RECT  42.977 28.272 42.995 28.488 ;
     RECT  42.757 4.896 43.117 5.016 ;
     RECT  42.937 46.752 43.261 46.776 ;
     RECT  43.333 0.576 43.475 0.6 ;
     RECT  43.261 46.752 43.475 46.824 ;
     RECT  43.477 1.728 43.57 1.752 ;
     RECT  43.475 46.8 43.571 46.824 ;
     RECT  43.58 45.024 43.621 45.048 ;
     RECT  43.621 45.024 43.657 45.144 ;
     RECT  43.117 4.56 43.729 5.016 ;
     RECT  43.009 3.408 43.813 3.432 ;
     RECT  43.57 1.728 44.189 1.8 ;
     RECT  43.729 4.56 44.237 5.16 ;
     RECT  43.657 45.024 44.345 45.576 ;
     RECT  42.949 38.784 44.377 38.808 ;
     RECT  44.345 45.024 44.389 45.144 ;
     RECT  44.444 0.528 44.531 0.552 ;
     RECT  43.813 2.88 44.581 3.432 ;
     RECT  44.389 44.208 44.677 45.144 ;
     RECT  44.677 43.872 44.725 45.144 ;
     RECT  44.189 1.728 44.828 1.896 ;
     RECT  44.581 2.88 44.828 4.008 ;
     RECT  44.237 4.992 44.845 5.16 ;
     RECT  44.725 43.776 44.876 45.144 ;
     RECT  44.725 47.328 44.914 47.352 ;
     RECT  44.914 47.328 44.917 47.4 ;
     RECT  44.377 38.784 45.02 39.24 ;
     RECT  44.917 47.232 45.037 47.4 ;
     RECT  44.881 30.096 45.133 30.12 ;
     RECT  42.995 28.272 45.313 28.296 ;
     RECT  45.133 29.616 45.313 30.12 ;
     RECT  44.828 1.728 45.349 4.008 ;
     RECT  44.845 4.992 45.349 6.024 ;
     RECT  45.349 1.728 45.421 6.024 ;
     RECT  45.421 1.728 45.608 6.312 ;
     RECT  42.005 23.04 45.608 23.064 ;
     RECT  40.504 27.12 45.608 27.144 ;
     RECT  45.313 28.272 45.608 30.12 ;
     RECT  45.02 38.112 45.608 39.24 ;
     RECT  44.953 41.712 45.608 41.736 ;
     RECT  44.876 43.68 45.608 45.144 ;
     RECT  45.037 47.232 45.637 47.352 ;
     RECT  45.637 0.576 45.733 0.6 ;
     RECT  45.733 0.384 45.877 0.6 ;
     RECT  45.608 1.728 45.877 45.372 ;
     RECT  45.877 1.728 45.904 45.48 ;
     RECT  45.904 43.296 46.001 45.48 ;
     RECT  45.637 46.944 46.018 47.352 ;
     RECT  46.001 43.296 46.019 45.144 ;
     RECT  46.018 46.944 46.019 47.4 ;
     RECT  45.904 1.728 46.109 6.024 ;
     RECT  45.877 0.144 46.115 0.6 ;
     RECT  46.019 43.68 46.115 45.144 ;
     RECT  46.115 0.144 46.163 0.312 ;
     RECT  46.019 47.04 46.163 47.4 ;
     RECT  46.109 3.408 46.189 6.024 ;
     RECT  46.115 43.68 46.204 43.704 ;
     RECT  46.163 47.376 46.217 47.4 ;
     RECT  45.904 40.464 46.433 42.024 ;
     RECT  45.904 26.448 46.721 29.64 ;
     RECT  46.189 3.552 46.885 6.024 ;
     RECT  46.885 3.552 46.933 6.264 ;
     RECT  45.904 30.96 46.933 32.424 ;
     RECT  46.721 26.448 47.005 27.912 ;
     RECT  46.115 45.024 47.041 45.144 ;
     RECT  47.005 25.584 47.045 27.912 ;
     RECT  47.041 45.024 47.077 45.336 ;
     RECT  46.933 30.96 47.297 33.096 ;
     RECT  47.005 0.096 47.411 0.12 ;
     RECT  47.077 45.024 47.411 46.2 ;
     RECT  46.109 1.728 47.507 2.328 ;
     RECT  45.904 38.784 47.581 38.952 ;
     RECT  46.933 3.552 47.681 6.792 ;
     RECT  47.297 31.056 47.725 33.096 ;
     RECT  47.681 3.552 47.765 6.888 ;
     RECT  47.507 1.728 47.917 1.896 ;
     RECT  47.765 3.552 47.941 6.792 ;
     RECT  47.545 46.704 47.987 46.728 ;
     RECT  46.721 29.472 48.013 29.64 ;
     RECT  47.941 35.52 48.121 35.544 ;
     RECT  47.401 37.584 48.157 37.608 ;
     RECT  46.433 41.376 48.181 42.024 ;
     RECT  48.013 29.472 48.193 29.784 ;
     RECT  47.725 31.056 48.193 33.768 ;
     RECT  47.941 3.408 48.233 6.792 ;
     RECT  48.193 31.056 48.265 33.96 ;
     RECT  48.181 41.376 48.269 42.216 ;
     RECT  48.193 29.184 48.301 29.784 ;
     RECT  48.265 30.816 48.301 33.96 ;
     RECT  48.121 35.376 48.301 35.544 ;
     RECT  47.411 45.024 48.385 45.576 ;
     RECT  48.301 29.184 48.517 33.96 ;
     RECT  48.301 35.376 48.517 36.36 ;
     RECT  47.581 38.784 48.517 39.384 ;
     RECT  48.233 3.408 48.553 6.696 ;
     RECT  48.269 41.376 48.665 41.64 ;
     RECT  48.157 37.584 48.697 37.704 ;
     RECT  48.517 38.688 48.697 39.384 ;
     RECT  48.553 3.36 48.805 6.696 ;
     RECT  47.917 1.728 48.949 1.848 ;
     RECT  47.045 25.584 49.021 27.768 ;
     RECT  48.949 1.152 49.043 1.848 ;
     RECT  49.043 1.728 49.052 1.848 ;
     RECT  48.805 2.88 49.052 6.696 ;
     RECT  49.052 1.728 49.097 6.696 ;
     RECT  48.385 45.024 49.189 45.192 ;
     RECT  49.189 44.208 49.196 45.192 ;
     RECT  48.517 29.184 49.237 36.36 ;
     RECT  48.997 47.328 49.282 47.352 ;
     RECT  49.196 43.872 49.388 45.192 ;
     RECT  49.237 28.848 49.389 36.36 ;
     RECT  48.697 37.584 49.389 39.384 ;
     RECT  49.097 1.728 49.427 2.28 ;
     RECT  49.021 40.8 49.669 41.304 ;
     RECT  49.388 43.68 49.705 45.192 ;
     RECT  49.705 43.68 49.811 45.576 ;
     RECT  49.669 40.8 49.817 41.544 ;
     RECT  49.811 43.68 49.957 45.336 ;
     RECT  49.097 3.408 50.137 6.696 ;
     RECT  49.282 47.28 50.293 47.4 ;
     RECT  50.293 47.232 50.342 47.4 ;
     RECT  50.245 0.096 50.387 0.12 ;
     RECT  50.137 3.408 50.389 6.888 ;
     RECT  49.021 25.296 50.389 27.768 ;
     RECT  49.389 28.848 50.389 39.384 ;
     RECT  50.389 2.832 50.533 6.888 ;
     RECT  50.342 47.232 50.725 47.352 ;
     RECT  49.817 40.8 50.785 40.968 ;
     RECT  49.427 1.728 50.821 1.848 ;
     RECT  50.533 2.832 50.821 7.224 ;
     RECT  50.389 25.296 50.857 39.384 ;
     RECT  50.785 40.8 50.857 41.016 ;
     RECT  50.821 1.728 50.861 7.224 ;
     RECT  50.773 0.144 50.869 0.168 ;
     RECT  50.869 0.144 50.965 0.264 ;
     RECT  50.861 1.776 51.008 7.224 ;
     RECT  45.904 23.04 51.008 23.64 ;
     RECT  50.857 25.296 51.008 41.016 ;
     RECT  49.957 43.152 51.008 45.336 ;
     RECT  51.008 1.776 51.109 45.372 ;
     RECT  50.965 0.144 51.155 0.552 ;
     RECT  51.109 1.776 51.196 45.528 ;
     RECT  51.196 1.776 51.304 45.102 ;
     RECT  51.155 0.144 51.491 0.264 ;
     RECT  51.491 0.24 51.587 0.264 ;
     RECT  50.725 47.136 51.685 47.352 ;
     RECT  51.304 43.296 51.869 43.896 ;
     RECT  51.304 1.776 51.877 6.888 ;
     RECT  51.685 47.136 51.877 47.4 ;
     RECT  51.304 28.752 52.193 40.968 ;
     RECT  52.193 40.56 52.297 40.968 ;
     RECT  51.304 42.144 52.297 42.168 ;
     RECT  51.869 43.296 52.297 43.848 ;
     RECT  51.304 45.024 52.357 45.048 ;
     RECT  52.357 45.024 52.444 45.144 ;
     RECT  52.297 40.56 52.451 43.848 ;
     RECT  51.304 7.872 52.513 7.896 ;
     RECT  51.877 1.728 52.549 6.888 ;
     RECT  52.513 7.872 52.549 7.992 ;
     RECT  51.877 47.088 52.787 47.4 ;
     RECT  52.549 1.728 52.885 7.992 ;
     RECT  51.304 23.04 53.017 27.768 ;
     RECT  52.193 28.752 53.017 39.432 ;
     RECT  53.017 23.04 53.161 39.432 ;
     RECT  52.451 42.432 53.269 43.848 ;
     RECT  52.787 47.232 53.273 47.4 ;
     RECT  53.161 23.04 53.305 39.528 ;
     RECT  52.451 40.56 53.305 40.968 ;
     RECT  52.444 45.024 53.458 45.048 ;
     RECT  53.273 47.232 53.507 47.352 ;
     RECT  53.458 44.976 53.509 45.048 ;
     RECT  53.509 44.976 53.597 45.576 ;
     RECT  52.885 1.728 53.603 8.04 ;
     RECT  53.269 42.432 53.665 43.896 ;
     RECT  53.603 1.728 53.669 1.848 ;
     RECT  53.665 42.384 53.813 43.896 ;
     RECT  53.669 1.728 53.849 1.8 ;
     RECT  53.813 42.432 53.941 43.896 ;
     RECT  53.941 42.432 53.953 43.992 ;
     RECT  53.597 44.976 53.953 45.048 ;
     RECT  53.953 42.432 53.957 45.048 ;
     RECT  53.849 1.728 54.065 1.752 ;
     RECT  54.14 46.752 54.227 46.776 ;
     RECT  53.603 2.832 54.277 8.04 ;
     RECT  53.305 23.04 54.529 40.968 ;
     RECT  54.757 0.288 54.853 0.312 ;
     RECT  52.333 10.032 54.853 10.056 ;
     RECT  54.853 0.144 54.899 0.312 ;
     RECT  54.277 2.832 54.997 8.184 ;
     RECT  54.997 2.256 55.141 8.184 ;
     RECT  53.957 43.584 55.141 45.048 ;
     RECT  54.529 23.04 55.285 41.016 ;
     RECT  53.957 42.432 55.285 42.456 ;
     RECT  55.141 2.256 55.381 8.232 ;
     RECT  54.853 9.36 55.381 10.056 ;
     RECT  55.141 43.584 55.685 45.576 ;
     RECT  55.381 2.256 55.781 10.056 ;
     RECT  55.285 23.04 55.781 42.456 ;
     RECT  55.685 43.584 55.781 45.528 ;
     RECT  55.781 1.728 55.865 10.056 ;
     RECT  55.781 23.04 55.865 45.528 ;
     RECT  55.909 47.088 56.177 47.112 ;
     RECT  56.177 47.088 56.195 47.4 ;
     RECT  55.865 1.824 56.408 10.056 ;
     RECT  55.865 23.04 56.408 45.372 ;
     RECT  54.899 0.144 56.485 0.168 ;
     RECT  56.408 1.824 56.704 45.372 ;
     RECT  56.485 0.144 56.819 0.408 ;
     RECT  56.819 0.144 56.845 0.264 ;
     RECT  56.704 1.824 56.861 1.848 ;
     RECT  56.845 0.192 56.867 0.264 ;
     RECT  56.704 45.024 56.869 45.372 ;
     RECT  56.867 0.192 56.963 0.216 ;
     RECT  56.704 2.88 57.203 8.376 ;
     RECT  56.195 47.184 57.305 47.4 ;
     RECT  57.305 47.184 57.347 47.304 ;
     RECT  57.203 2.88 57.395 8.232 ;
     RECT  57.347 47.184 57.413 47.256 ;
     RECT  57.413 47.184 57.539 47.208 ;
     RECT  56.861 1.728 57.733 1.848 ;
     RECT  57.395 2.88 57.733 3.528 ;
     RECT  56.704 23.04 57.733 43.896 ;
     RECT  56.869 45.024 57.733 45.576 ;
     RECT  57.733 23.04 57.953 45.576 ;
     RECT  57.953 43.776 57.997 45.576 ;
     RECT  57.953 23.04 58.061 42.792 ;
     RECT  57.733 1.728 58.453 3.528 ;
     RECT  57.395 4.56 58.453 8.232 ;
     RECT  57.997 43.776 58.493 45.24 ;
     RECT  58.061 23.04 58.709 42.12 ;
     RECT  58.709 23.04 58.817 41.928 ;
     RECT  58.817 23.04 58.931 41.4 ;
     RECT  58.453 1.728 59.245 8.232 ;
     RECT  59.245 1.104 59.411 8.232 ;
     RECT  58.493 44.112 59.557 45.24 ;
     RECT  59.411 1.728 59.651 8.232 ;
     RECT  59.557 43.872 59.653 45.24 ;
     RECT  59.653 43.824 59.797 45.24 ;
     RECT  59.749 18.768 59.833 18.792 ;
     RECT  59.797 43.296 59.857 45.24 ;
     RECT  59.857 43.296 59.987 45.576 ;
     RECT  59.651 4.512 60.013 8.232 ;
     RECT  59.845 47.328 60.037 47.352 ;
     RECT  59.651 1.728 60.46 3.528 ;
     RECT  60.433 20.88 60.661 20.904 ;
     RECT  60.46 1.728 60.697 1.896 ;
     RECT  60.037 47.232 60.709 47.352 ;
     RECT  60.661 20.88 60.757 21.72 ;
     RECT  58.931 23.04 60.757 41.256 ;
     RECT  60.577 42.24 60.757 42.264 ;
     RECT  60.757 20.832 60.793 21.72 ;
     RECT  60.46 3.408 60.805 3.528 ;
     RECT  60.013 4.512 60.805 6.6 ;
     RECT  60.709 47.088 60.812 47.352 ;
     RECT  60.685 19.056 60.865 19.08 ;
     RECT  60.812 46.992 60.901 47.352 ;
     RECT  60.757 23.04 61.052 42.264 ;
     RECT  59.987 43.296 61.052 45.048 ;
     RECT  60.013 7.92 61.151 8.232 ;
     RECT  56.704 9.36 61.151 10.056 ;
     RECT  61.052 23.04 61.153 45.048 ;
     RECT  60.865 18.24 61.189 19.08 ;
     RECT  60.793 20.064 61.189 21.72 ;
     RECT  60.805 3.408 61.525 6.6 ;
     RECT  61.151 7.92 61.525 10.056 ;
     RECT  61.525 3.408 61.573 10.056 ;
     RECT  61.189 18.24 61.573 21.72 ;
     RECT  60.901 46.992 61.58 47.4 ;
     RECT  61.573 18 61.621 21.72 ;
     RECT  60.697 1.728 61.625 1.8 ;
     RECT  61.58 46.896 61.667 47.4 ;
     RECT  61.625 1.776 61.669 1.8 ;
     RECT  61.573 2.784 61.669 10.056 ;
     RECT  61.669 1.776 61.808 10.056 ;
     RECT  61.621 17.616 61.808 21.72 ;
     RECT  61.153 22.752 61.808 45.048 ;
     RECT  61.667 46.992 61.907 47.4 ;
     RECT  61.808 1.776 61.945 45.372 ;
     RECT  61.945 1.776 62.028 45.48 ;
     RECT  62.028 1.776 62.104 45.528 ;
     RECT  61.621 0.144 62.149 0.168 ;
     RECT  62.104 17.088 62.237 45.528 ;
     RECT  62.237 17.088 62.243 45.048 ;
     RECT  62.149 0.144 62.29 0.312 ;
     RECT  62.243 18 62.332 45.048 ;
     RECT  62.29 0.096 62.369 0.312 ;
     RECT  62.332 18.24 62.417 45.048 ;
     RECT  62.369 0.096 62.486 0.408 ;
     RECT  62.104 1.776 62.489 10.056 ;
     RECT  62.489 1.776 62.621 6.84 ;
     RECT  62.486 0.096 62.669 0.36 ;
     RECT  62.669 0.096 62.675 0.216 ;
     RECT  61.907 47.184 62.675 47.4 ;
     RECT  62.417 18.48 62.777 45.048 ;
     RECT  62.621 1.728 62.963 6.84 ;
     RECT  62.777 20.976 63.001 45.048 ;
     RECT  62.777 18.48 63.209 19.992 ;
     RECT  63.001 45.024 63.269 45.048 ;
     RECT  63.001 20.976 63.289 43.896 ;
     RECT  62.675 47.232 63.577 47.4 ;
     RECT  63.289 43.584 63.868 43.896 ;
     RECT  63.868 43.872 63.973 43.896 ;
     RECT  63.269 45.024 63.973 45.576 ;
     RECT  63.209 18.624 64.069 19.992 ;
     RECT  63.289 20.976 64.069 42.168 ;
     RECT  62.489 7.968 64.145 10.056 ;
     RECT  64.069 18.624 64.177 42.168 ;
     RECT  63.577 47.232 64.211 47.352 ;
     RECT  64.211 47.328 64.355 47.352 ;
     RECT  62.963 2.832 64.393 6.84 ;
     RECT  64.145 7.968 64.393 7.992 ;
     RECT  64.393 2.832 64.433 7.992 ;
     RECT  64.105 0.528 64.499 0.552 ;
     RECT  64.177 18.24 64.573 42.168 ;
     RECT  64.573 17.376 64.645 42.168 ;
     RECT  62.963 1.728 64.681 1.848 ;
     RECT  64.433 2.832 64.681 6.6 ;
     RECT  64.645 17.376 64.748 42.216 ;
     RECT  64.681 1.728 64.787 6.6 ;
     RECT  64.748 17.376 64.997 42.744 ;
     RECT  64.997 17.376 65.077 42.792 ;
     RECT  63.973 43.872 65.077 45.576 ;
     RECT  64.145 9.36 65.267 10.056 ;
     RECT  65.267 9.504 65.315 10.056 ;
     RECT  64.787 2.88 65.405 6.6 ;
     RECT  65.077 17.376 65.459 45.576 ;
     RECT  65.405 3.984 65.477 6.6 ;
     RECT  64.787 1.728 65.513 1.8 ;
     RECT  65.459 44.352 65.513 45.576 ;
     RECT  65.513 44.448 65.555 45.576 ;
     RECT  65.513 1.728 65.564 1.752 ;
     RECT  65.405 2.88 65.593 2.904 ;
     RECT  65.477 4.512 65.605 6.6 ;
     RECT  64.433 7.584 65.605 7.608 ;
     RECT  65.564 1.104 65.651 1.752 ;
     RECT  65.605 4.512 65.651 7.608 ;
     RECT  65.459 17.376 65.665 43.32 ;
     RECT  65.651 4.512 65.693 6.84 ;
     RECT  65.665 17.376 65.729 42.792 ;
     RECT  65.693 4.512 65.909 6.504 ;
     RECT  65.729 17.376 65.939 42.264 ;
     RECT  65.909 4.512 65.945 6.36 ;
     RECT  65.651 1.728 66.52 1.752 ;
     RECT  65.555 45.024 66.565 45.576 ;
     RECT  66.565 44.208 66.901 45.576 ;
     RECT  66.949 3.024 67.045 3.048 ;
     RECT  67.045 2.88 67.057 3.048 ;
     RECT  65.945 4.512 67.057 6.264 ;
     RECT  66.52 1.728 67.208 1.8 ;
     RECT  67.057 2.88 67.208 6.264 ;
     RECT  66.157 8.016 67.208 8.04 ;
     RECT  65.315 9.504 67.208 9.528 ;
     RECT  65.939 17.376 67.208 42.024 ;
     RECT  66.901 43.344 67.208 45.576 ;
     RECT  66.121 0.096 67.237 0.12 ;
     RECT  67.208 1.728 67.333 45.576 ;
     RECT  67.237 47.232 67.333 47.256 ;
     RECT  67.333 1.68 67.504 45.576 ;
     RECT  67.237 0.096 67.525 0.552 ;
     RECT  67.504 1.68 67.525 1.896 ;
     RECT  67.333 47.232 67.697 47.304 ;
     RECT  67.525 0.096 67.715 1.896 ;
     RECT  67.697 47.232 67.715 47.4 ;
     RECT  67.715 0.096 67.745 0.36 ;
     RECT  67.715 47.28 67.781 47.4 ;
     RECT  67.745 0.096 67.789 0.12 ;
     RECT  67.781 47.28 67.811 47.304 ;
     RECT  67.504 16.992 67.853 45.576 ;
     RECT  67.853 16.992 67.889 17.688 ;
     RECT  67.504 9.504 68.339 9.528 ;
     RECT  67.504 2.88 68.605 5.88 ;
     RECT  67.715 1.728 68.641 1.896 ;
     RECT  68.605 2.88 68.641 6.024 ;
     RECT  67.889 16.992 68.857 17.496 ;
     RECT  67.853 18.72 68.861 45.576 ;
     RECT  68.857 16.992 68.963 17.592 ;
     RECT  68.861 18.72 68.965 42.792 ;
     RECT  68.861 44.16 68.969 45.576 ;
     RECT  68.963 17.088 69.005 17.592 ;
     RECT  68.641 1.728 69.041 6.024 ;
     RECT  68.965 18.672 69.041 42.792 ;
     RECT  69.005 17.184 69.181 17.592 ;
     RECT  69.041 18.672 69.181 42.744 ;
     RECT  69.041 1.728 69.491 5.64 ;
     RECT  68.969 44.448 69.491 45.384 ;
     RECT  69.491 1.728 69.509 1.8 ;
     RECT  69.181 17.184 69.509 42.744 ;
     RECT  69.491 44.448 69.545 45.336 ;
     RECT  69.509 17.328 69.553 42.744 ;
     RECT  69.553 17.328 69.617 42.216 ;
     RECT  69.491 2.928 69.761 5.64 ;
     RECT  69.761 2.928 69.797 5.208 ;
     RECT  69.545 45.024 70.157 45.048 ;
     RECT  69.797 3.408 70.193 5.208 ;
     RECT  69.509 1.728 70.265 1.752 ;
     RECT  70.193 3.984 70.517 5.208 ;
     RECT  69.617 17.328 70.585 17.592 ;
     RECT  69.617 18.672 70.585 42.12 ;
     RECT  70.585 17.328 70.985 42.12 ;
     RECT  70.873 2.88 71.021 2.904 ;
     RECT  70.517 3.984 71.021 5.112 ;
     RECT  70.985 17.328 71.093 42.024 ;
     RECT  71.021 3.984 71.165 4.008 ;
     RECT  71.021 5.088 71.561 5.112 ;
     RECT  71.093 17.328 71.561 41.16 ;
     RECT  71.561 17.328 72.229 39.096 ;
     RECT  72.229 16.896 72.608 39.096 ;
     RECT  71.561 40.128 72.608 41.16 ;
     RECT  72.608 2.148 72.712 45.372 ;
     RECT  72.712 2.418 72.904 45.102 ;
     RECT  72.904 16.896 73.469 39.096 ;
     RECT  73.469 17.136 74.617 39.096 ;
     RECT  74.617 17.04 74.797 39.096 ;
     RECT  72.904 40.128 74.797 41.4 ;
     RECT  74.797 17.04 75.805 41.4 ;
     RECT  75.805 17.04 76.021 42.024 ;
     RECT  76.021 16.608 76.133 42.024 ;
     RECT  76.133 16.608 76.205 41.304 ;
     RECT  76.129 14.832 76.241 14.856 ;
     RECT  76.205 16.608 76.349 39.048 ;
     RECT  76.205 40.128 76.493 41.304 ;
     RECT  76.349 16.608 77.033 38.904 ;
     RECT  77.033 17.088 78.008 38.904 ;
     RECT  76.493 40.128 78.008 40.44 ;
     RECT  78.008 2.148 78.112 45.372 ;
     RECT  78.112 2.418 78.304 45.102 ;
     RECT  78.304 17.088 78.401 24.216 ;
     RECT  78.304 25.728 78.401 38.472 ;
     RECT  78.401 17.088 78.473 20.904 ;
     RECT  78.401 25.728 78.581 35.496 ;
     RECT  78.401 36.576 78.617 38.472 ;
     RECT  78.304 40.128 78.617 41.448 ;
     RECT  78.473 19.2 78.659 20.904 ;
     RECT  78.659 20.544 78.689 20.904 ;
     RECT  78.689 20.544 78.7 20.712 ;
     RECT  78.581 25.728 78.725 26.808 ;
     RECT  78.617 40.368 78.725 41.448 ;
     RECT  78.581 27.888 78.761 35.496 ;
     RECT  78.725 40.944 78.797 41.448 ;
     RECT  78.7 20.688 78.833 20.712 ;
     RECT  78.725 25.776 78.977 26.808 ;
     RECT  78.401 22.32 79.049 24.216 ;
     RECT  78.473 17.088 79.085 18.168 ;
     RECT  78.761 27.888 79.085 35.448 ;
     RECT  79.085 17.088 79.301 17.928 ;
     RECT  79.301 17.088 79.409 17.832 ;
     RECT  78.797 41.184 79.733 41.448 ;
     RECT  78.977 25.776 79.801 26.76 ;
     RECT  79.409 17.088 79.805 17.112 ;
     RECT  78.659 19.2 80.053 19.224 ;
     RECT  79.657 21.408 80.053 21.528 ;
     RECT  79.049 23.232 80.053 24.216 ;
     RECT  79.801 25.584 80.053 26.76 ;
     RECT  80.053 23.232 80.089 26.76 ;
     RECT  79.085 28.176 80.125 35.448 ;
     RECT  78.617 36.672 80.125 38.472 ;
     RECT  80.053 18.96 80.341 19.224 ;
     RECT  80.125 28.176 80.341 38.472 ;
     RECT  80.089 23.232 80.377 27 ;
     RECT  80.341 28.176 80.377 38.76 ;
     RECT  80.053 21.216 80.413 21.528 ;
     RECT  80.377 23.232 80.413 38.76 ;
     RECT  80.341 18.96 80.629 19.944 ;
     RECT  80.413 21.216 80.629 21.672 ;
     RECT  79.733 41.424 80.633 41.448 ;
     RECT  80.629 21.216 80.665 21.768 ;
     RECT  80.413 23.136 80.665 38.76 ;
     RECT  80.665 21.216 80.881 38.76 ;
     RECT  80.629 18.576 80.989 19.944 ;
     RECT  80.989 18.144 81.133 19.944 ;
     RECT  81.133 18.144 81.277 19.992 ;
     RECT  81.277 17.904 81.349 19.992 ;
     RECT  81.349 17.856 81.457 19.992 ;
     RECT  80.881 20.976 81.457 38.76 ;
     RECT  81.457 17.856 81.529 38.76 ;
     RECT  81.529 17.856 82.181 39.288 ;
     RECT  81.529 40.848 82.433 40.872 ;
     RECT  83.221 16.896 83.408 16.92 ;
     RECT  82.181 18 83.408 39.288 ;
     RECT  82.501 40.608 83.408 40.632 ;
     RECT  83.269 42.288 83.408 42.312 ;
     RECT  83.269 43.632 83.408 43.656 ;
     RECT  83.408 2.148 83.512 45.372 ;
     RECT  83.512 2.418 83.704 45.102 ;
     RECT  83.704 20.4 83.873 38.472 ;
     RECT  83.873 20.4 84.841 37.128 ;
     RECT  83.704 16.56 84.877 18.888 ;
     RECT  84.841 20.304 84.913 37.128 ;
     RECT  83.873 38.16 84.913 38.472 ;
     RECT  84.877 16.368 85.381 18.984 ;
     RECT  84.913 20.304 85.381 38.472 ;
     RECT  85.381 16.368 86.209 38.472 ;
     RECT  83.704 39.504 86.209 42.408 ;
     RECT  86.209 16.368 86.245 42.408 ;
     RECT  86.245 16.368 86.316 16.392 ;
     RECT  86.245 16.392 86.357 16.464 ;
     RECT  86.245 16.464 86.316 16.488 ;
     RECT  86.245 16.488 86.357 16.56 ;
     RECT  86.245 16.56 86.316 16.584 ;
     RECT  86.245 16.584 86.357 16.656 ;
     RECT  86.245 16.656 86.316 16.68 ;
     RECT  86.245 16.68 86.357 16.752 ;
     RECT  86.245 16.752 86.316 16.776 ;
     RECT  86.245 16.776 86.357 16.848 ;
     RECT  86.245 16.848 86.316 16.872 ;
     RECT  86.245 16.872 86.357 16.944 ;
     RECT  86.245 16.944 86.316 16.968 ;
     RECT  86.245 16.968 86.357 17.04 ;
     RECT  86.245 17.04 86.316 17.064 ;
     RECT  86.245 17.064 86.357 17.136 ;
     RECT  86.245 17.136 86.316 17.16 ;
     RECT  86.245 17.16 86.357 17.232 ;
     RECT  86.245 17.232 86.316 17.256 ;
     RECT  86.245 17.256 86.357 17.328 ;
     RECT  86.245 17.328 86.316 17.352 ;
     RECT  86.245 17.352 86.357 17.424 ;
     RECT  86.245 17.424 86.316 17.448 ;
     RECT  86.245 17.448 86.357 17.52 ;
     RECT  86.245 17.52 86.316 17.544 ;
     RECT  86.245 17.544 86.357 17.616 ;
     RECT  86.245 17.616 86.316 17.64 ;
     RECT  86.245 17.64 86.357 17.712 ;
     RECT  86.245 17.712 86.316 17.736 ;
     RECT  86.245 17.736 86.357 17.808 ;
     RECT  86.245 17.808 86.316 17.832 ;
     RECT  86.245 17.832 86.357 17.904 ;
     RECT  86.245 17.904 86.316 17.928 ;
     RECT  86.245 17.928 86.357 18 ;
     RECT  86.245 18 86.316 18.024 ;
     RECT  86.245 18.024 86.357 18.096 ;
     RECT  86.245 18.096 86.316 18.12 ;
     RECT  86.245 18.12 86.357 18.192 ;
     RECT  86.245 18.192 86.316 18.216 ;
     RECT  86.245 18.216 86.357 18.288 ;
     RECT  86.245 18.288 86.316 18.312 ;
     RECT  86.245 18.312 86.357 18.384 ;
     RECT  86.245 18.384 86.316 18.408 ;
     RECT  86.245 18.408 86.357 18.48 ;
     RECT  86.245 18.48 86.316 18.504 ;
     RECT  86.245 18.504 86.357 18.576 ;
     RECT  86.245 18.576 86.316 18.6 ;
     RECT  86.245 18.6 86.357 18.672 ;
     RECT  86.245 18.672 86.316 18.696 ;
     RECT  86.245 18.696 86.357 18.768 ;
     RECT  86.245 18.768 86.316 18.792 ;
     RECT  86.245 18.792 86.357 18.864 ;
     RECT  86.245 18.864 86.316 18.888 ;
     RECT  86.245 18.888 86.357 18.96 ;
     RECT  86.245 18.96 86.316 18.984 ;
     RECT  86.245 18.984 86.357 19.056 ;
     RECT  86.245 19.056 86.316 19.08 ;
     RECT  86.245 19.08 86.357 19.152 ;
     RECT  86.245 19.152 86.316 19.176 ;
     RECT  86.245 19.176 86.357 19.248 ;
     RECT  86.245 19.248 86.316 19.272 ;
     RECT  86.245 19.272 86.357 19.344 ;
     RECT  86.245 19.344 86.316 19.368 ;
     RECT  86.245 19.368 86.357 20.208 ;
     RECT  86.245 20.208 86.316 20.232 ;
     RECT  86.245 20.232 86.357 20.304 ;
     RECT  86.245 20.304 86.316 20.328 ;
     RECT  86.245 20.328 86.357 20.4 ;
     RECT  86.245 20.4 86.316 20.424 ;
     RECT  86.245 20.424 86.357 20.496 ;
     RECT  86.245 20.496 86.316 20.52 ;
     RECT  86.245 20.52 86.357 20.592 ;
     RECT  86.245 20.592 86.316 20.616 ;
     RECT  86.245 20.616 86.357 20.688 ;
     RECT  86.245 20.688 86.316 20.712 ;
     RECT  86.245 20.712 86.357 20.784 ;
     RECT  86.245 20.784 86.316 20.808 ;
     RECT  86.245 20.808 86.357 20.88 ;
     RECT  86.245 20.88 86.316 20.904 ;
     RECT  86.245 20.904 86.357 20.976 ;
     RECT  86.245 20.976 86.316 21 ;
     RECT  86.245 21 86.357 21.072 ;
     RECT  86.245 21.072 86.316 21.096 ;
     RECT  86.245 21.096 86.357 21.168 ;
     RECT  86.245 21.168 86.316 21.192 ;
     RECT  86.245 21.192 86.357 21.264 ;
     RECT  86.245 21.264 86.316 21.288 ;
     RECT  86.245 21.288 86.357 21.36 ;
     RECT  86.245 21.36 86.316 21.384 ;
     RECT  86.245 21.384 86.357 21.456 ;
     RECT  86.245 21.456 86.316 21.48 ;
     RECT  86.245 21.48 86.357 21.552 ;
     RECT  86.245 21.552 86.316 21.576 ;
     RECT  86.245 21.576 86.357 21.648 ;
     RECT  86.245 21.648 86.316 21.672 ;
     RECT  86.245 21.672 86.357 21.744 ;
     RECT  86.245 21.744 86.316 21.768 ;
     RECT  86.245 21.768 86.357 21.84 ;
     RECT  86.245 21.84 86.316 21.864 ;
     RECT  86.245 21.864 86.357 21.936 ;
     RECT  86.245 21.936 86.316 21.96 ;
     RECT  86.245 21.96 86.357 22.032 ;
     RECT  86.245 22.032 86.316 22.056 ;
     RECT  86.245 22.056 86.357 22.128 ;
     RECT  86.245 22.128 86.316 22.152 ;
     RECT  86.245 22.152 86.357 22.224 ;
     RECT  86.245 22.224 86.316 22.248 ;
     RECT  86.245 22.248 86.357 22.32 ;
     RECT  86.245 22.32 86.316 22.344 ;
     RECT  86.245 22.344 86.357 22.416 ;
     RECT  86.245 22.416 86.316 22.44 ;
     RECT  86.245 22.44 86.357 22.512 ;
     RECT  86.245 22.512 86.316 22.536 ;
     RECT  86.245 22.536 86.357 22.608 ;
     RECT  86.245 22.608 86.316 22.632 ;
     RECT  86.245 22.632 86.357 22.704 ;
     RECT  86.245 22.704 86.316 22.728 ;
     RECT  86.245 22.728 86.357 22.8 ;
     RECT  86.245 22.8 86.316 22.824 ;
     RECT  86.245 22.824 86.357 22.896 ;
     RECT  86.245 22.896 86.316 22.92 ;
     RECT  86.245 22.92 86.357 22.992 ;
     RECT  86.245 22.992 86.316 23.016 ;
     RECT  86.245 23.016 86.357 23.088 ;
     RECT  86.245 23.088 86.316 23.112 ;
     RECT  86.245 23.112 86.357 23.184 ;
     RECT  86.245 23.184 86.316 23.208 ;
     RECT  86.245 23.208 86.357 23.28 ;
     RECT  86.245 23.28 86.316 23.304 ;
     RECT  86.245 23.304 86.357 23.376 ;
     RECT  86.245 23.376 86.316 23.4 ;
     RECT  86.245 23.4 86.357 23.472 ;
     RECT  86.245 23.472 86.316 23.496 ;
     RECT  86.245 23.496 86.357 23.568 ;
     RECT  86.245 23.568 86.316 23.592 ;
     RECT  86.245 23.592 86.357 23.664 ;
     RECT  86.245 23.664 86.316 23.688 ;
     RECT  86.245 23.688 86.357 23.76 ;
     RECT  86.245 23.76 86.316 23.784 ;
     RECT  86.245 23.784 86.357 23.856 ;
     RECT  86.245 23.856 86.316 23.88 ;
     RECT  86.245 23.88 86.357 23.952 ;
     RECT  86.245 23.952 86.316 23.976 ;
     RECT  86.245 23.976 86.357 24.048 ;
     RECT  86.245 24.048 86.316 24.072 ;
     RECT  86.245 24.072 86.357 24.144 ;
     RECT  86.245 24.144 86.316 24.168 ;
     RECT  86.245 24.168 86.357 24.24 ;
     RECT  86.245 24.24 86.316 24.264 ;
     RECT  86.245 24.264 86.357 24.336 ;
     RECT  86.245 24.336 86.316 24.36 ;
     RECT  86.245 24.36 86.357 24.432 ;
     RECT  86.245 24.432 86.316 24.456 ;
     RECT  86.245 24.456 86.357 24.528 ;
     RECT  86.245 24.528 86.316 24.552 ;
     RECT  86.245 24.552 86.357 24.624 ;
     RECT  86.245 24.624 86.316 24.648 ;
     RECT  86.245 24.648 86.357 24.72 ;
     RECT  86.245 24.72 86.316 24.744 ;
     RECT  86.245 24.744 86.357 24.816 ;
     RECT  86.245 24.816 86.316 24.84 ;
     RECT  86.245 24.84 86.357 24.912 ;
     RECT  86.245 24.912 86.316 24.936 ;
     RECT  86.245 24.936 86.357 25.008 ;
     RECT  86.245 25.008 86.316 25.032 ;
     RECT  86.245 25.032 86.357 25.104 ;
     RECT  86.245 25.104 86.316 25.128 ;
     RECT  86.245 25.128 86.357 25.2 ;
     RECT  86.245 25.2 86.316 25.224 ;
     RECT  86.245 25.224 86.357 25.296 ;
     RECT  86.245 25.296 86.316 25.32 ;
     RECT  86.245 25.32 86.357 25.392 ;
     RECT  86.245 25.392 86.316 25.416 ;
     RECT  86.245 25.416 86.357 25.488 ;
     RECT  86.245 25.488 86.316 25.512 ;
     RECT  86.245 25.512 86.357 25.584 ;
     RECT  86.245 25.584 86.316 25.608 ;
     RECT  86.245 25.608 86.357 25.68 ;
     RECT  86.245 25.68 86.316 25.704 ;
     RECT  86.245 25.704 86.357 25.776 ;
     RECT  86.245 25.776 86.316 25.8 ;
     RECT  86.245 25.8 86.357 25.872 ;
     RECT  86.245 25.872 86.316 25.896 ;
     RECT  86.245 25.896 86.357 25.968 ;
     RECT  86.245 25.968 86.316 25.992 ;
     RECT  86.245 25.992 86.357 26.064 ;
     RECT  86.245 26.064 86.316 26.088 ;
     RECT  86.245 26.088 86.357 26.16 ;
     RECT  86.245 26.16 86.316 26.184 ;
     RECT  86.245 26.184 86.357 26.256 ;
     RECT  86.245 26.256 86.316 26.28 ;
     RECT  86.245 26.28 86.357 26.352 ;
     RECT  86.245 26.352 86.316 26.376 ;
     RECT  86.245 26.376 86.357 26.448 ;
     RECT  86.245 26.448 86.316 26.472 ;
     RECT  86.245 26.472 86.357 26.544 ;
     RECT  86.245 26.544 86.316 26.568 ;
     RECT  86.245 26.568 86.357 26.64 ;
     RECT  86.245 26.64 86.316 26.664 ;
     RECT  86.245 26.664 86.357 26.736 ;
     RECT  86.245 26.736 86.316 26.76 ;
     RECT  86.245 26.76 86.357 26.832 ;
     RECT  86.245 26.832 86.316 26.856 ;
     RECT  86.245 26.856 86.357 26.928 ;
     RECT  86.245 26.928 86.316 26.952 ;
     RECT  86.245 26.952 86.357 27.024 ;
     RECT  86.245 27.024 86.316 27.048 ;
     RECT  86.245 27.048 86.357 27.12 ;
     RECT  86.245 27.12 86.316 27.144 ;
     RECT  86.245 27.144 86.357 27.216 ;
     RECT  86.245 27.216 86.316 27.24 ;
     RECT  86.245 27.24 86.357 27.312 ;
     RECT  86.245 27.312 86.316 27.336 ;
     RECT  86.245 27.336 86.357 27.408 ;
     RECT  86.245 27.408 86.316 27.432 ;
     RECT  86.245 27.432 86.357 27.504 ;
     RECT  86.245 27.504 86.316 27.528 ;
     RECT  86.245 27.528 86.357 27.6 ;
     RECT  86.245 27.6 86.316 27.624 ;
     RECT  86.245 27.624 86.357 27.696 ;
     RECT  86.245 27.696 86.316 27.72 ;
     RECT  86.245 27.72 86.357 27.792 ;
     RECT  86.245 27.792 86.316 27.816 ;
     RECT  86.245 27.816 86.357 27.888 ;
     RECT  86.245 27.888 86.316 27.912 ;
     RECT  86.245 27.912 86.357 27.984 ;
     RECT  86.245 27.984 86.316 28.008 ;
     RECT  86.245 28.008 86.357 28.08 ;
     RECT  86.245 28.08 86.316 28.104 ;
     RECT  86.245 28.104 86.357 28.176 ;
     RECT  86.245 28.176 86.316 28.2 ;
     RECT  86.245 28.2 86.357 28.272 ;
     RECT  86.245 28.272 86.316 28.296 ;
     RECT  86.245 28.296 86.357 28.368 ;
     RECT  86.245 28.368 86.316 28.392 ;
     RECT  86.245 28.392 86.357 28.464 ;
     RECT  86.245 28.464 86.316 28.488 ;
     RECT  86.245 28.488 86.357 28.56 ;
     RECT  86.245 28.56 86.316 28.584 ;
     RECT  86.245 28.584 86.357 28.656 ;
     RECT  86.245 28.656 86.316 28.68 ;
     RECT  86.245 28.68 86.357 28.752 ;
     RECT  86.245 28.752 86.316 28.776 ;
     RECT  86.245 28.776 86.357 28.848 ;
     RECT  86.245 28.848 86.316 28.872 ;
     RECT  86.245 28.872 86.357 28.944 ;
     RECT  86.245 28.944 86.316 28.968 ;
     RECT  86.245 28.968 86.357 29.04 ;
     RECT  86.245 29.04 86.316 29.064 ;
     RECT  86.245 29.064 86.357 29.136 ;
     RECT  86.245 29.136 86.316 29.16 ;
     RECT  86.245 29.16 86.357 29.232 ;
     RECT  86.245 29.232 86.316 29.256 ;
     RECT  86.245 29.256 86.357 29.328 ;
     RECT  86.245 29.328 86.316 29.352 ;
     RECT  86.245 29.352 86.357 29.424 ;
     RECT  86.245 29.424 86.316 29.448 ;
     RECT  86.245 29.448 86.357 29.52 ;
     RECT  86.245 29.52 86.316 29.544 ;
     RECT  86.245 29.544 86.357 29.616 ;
     RECT  86.245 29.616 86.316 29.64 ;
     RECT  86.245 29.64 86.357 29.712 ;
     RECT  86.245 29.712 86.316 29.736 ;
     RECT  86.245 29.736 86.357 29.808 ;
     RECT  86.245 29.808 86.316 29.832 ;
     RECT  86.245 29.832 86.357 29.904 ;
     RECT  86.245 29.904 86.316 29.928 ;
     RECT  86.245 29.928 86.357 30 ;
     RECT  86.245 30 86.316 30.024 ;
     RECT  86.245 30.024 86.357 30.096 ;
     RECT  86.245 30.096 86.316 30.12 ;
     RECT  86.245 30.12 86.357 30.192 ;
     RECT  86.245 30.192 86.316 30.216 ;
     RECT  86.245 30.216 86.357 30.288 ;
     RECT  86.245 30.288 86.316 30.312 ;
     RECT  86.245 30.312 86.357 30.384 ;
     RECT  86.245 30.384 86.316 30.408 ;
     RECT  86.245 30.408 86.357 30.48 ;
     RECT  86.245 30.48 86.316 30.504 ;
     RECT  86.245 30.504 86.357 30.576 ;
     RECT  86.245 30.576 86.316 30.6 ;
     RECT  86.245 30.6 86.357 30.672 ;
     RECT  86.245 30.672 86.316 30.696 ;
     RECT  86.245 30.696 86.357 30.768 ;
     RECT  86.245 30.768 86.316 30.792 ;
     RECT  86.245 30.792 86.357 30.864 ;
     RECT  86.245 30.864 86.316 30.888 ;
     RECT  86.245 30.888 86.357 30.96 ;
     RECT  86.245 30.96 86.316 30.984 ;
     RECT  86.245 30.984 86.357 31.056 ;
     RECT  86.245 31.056 86.316 31.08 ;
     RECT  86.245 31.08 86.357 31.152 ;
     RECT  86.245 31.152 86.316 31.176 ;
     RECT  86.245 31.176 86.357 31.248 ;
     RECT  86.245 31.248 86.316 31.272 ;
     RECT  86.245 31.272 86.357 31.344 ;
     RECT  86.245 31.344 86.316 31.368 ;
     RECT  86.245 31.368 86.357 31.44 ;
     RECT  86.245 31.44 86.316 31.464 ;
     RECT  86.245 31.464 86.357 31.536 ;
     RECT  86.245 31.536 86.316 31.56 ;
     RECT  86.245 31.56 86.357 31.632 ;
     RECT  86.245 31.632 86.316 31.656 ;
     RECT  86.245 31.656 86.357 31.728 ;
     RECT  86.245 31.728 86.316 31.752 ;
     RECT  86.245 31.752 86.357 31.824 ;
     RECT  86.245 31.824 86.316 31.848 ;
     RECT  86.245 31.848 86.357 31.92 ;
     RECT  86.245 31.92 86.316 31.944 ;
     RECT  86.245 31.944 86.357 32.016 ;
     RECT  86.245 32.016 86.316 32.04 ;
     RECT  86.245 32.04 86.357 32.112 ;
     RECT  86.245 32.112 86.316 32.136 ;
     RECT  86.245 32.136 86.357 32.208 ;
     RECT  86.245 32.208 86.316 32.232 ;
     RECT  86.245 32.232 86.357 32.304 ;
     RECT  86.245 32.304 86.316 32.328 ;
     RECT  86.245 32.328 86.357 32.4 ;
     RECT  86.245 32.4 86.316 32.424 ;
     RECT  86.245 32.424 86.357 32.496 ;
     RECT  86.245 32.496 86.316 32.52 ;
     RECT  86.245 32.52 86.357 32.592 ;
     RECT  86.245 32.592 86.316 32.616 ;
     RECT  86.245 32.616 86.357 32.688 ;
     RECT  86.245 32.688 86.316 32.712 ;
     RECT  86.245 32.712 86.357 32.784 ;
     RECT  86.245 32.784 86.316 32.808 ;
     RECT  86.245 32.808 86.357 32.88 ;
     RECT  86.245 32.88 86.316 32.904 ;
     RECT  86.245 32.904 86.357 32.976 ;
     RECT  86.245 32.976 86.316 33 ;
     RECT  86.245 33 86.357 33.072 ;
     RECT  86.245 33.072 86.316 33.096 ;
     RECT  86.245 33.096 86.357 33.168 ;
     RECT  86.245 33.168 86.316 33.192 ;
     RECT  86.245 33.192 86.357 33.264 ;
     RECT  86.245 33.264 86.316 33.288 ;
     RECT  86.245 33.288 86.357 33.36 ;
     RECT  86.245 33.36 86.316 33.384 ;
     RECT  86.245 33.384 86.357 33.456 ;
     RECT  86.245 33.456 86.316 33.48 ;
     RECT  86.245 33.48 86.357 33.552 ;
     RECT  86.245 33.552 86.316 33.576 ;
     RECT  86.245 33.576 86.357 33.648 ;
     RECT  86.245 33.648 86.316 33.672 ;
     RECT  86.245 33.672 86.357 33.744 ;
     RECT  86.245 33.744 86.316 33.768 ;
     RECT  86.245 33.768 86.357 33.84 ;
     RECT  86.245 33.84 86.316 33.864 ;
     RECT  86.245 33.864 86.357 33.936 ;
     RECT  86.245 33.936 86.316 33.96 ;
     RECT  86.245 33.96 86.357 34.032 ;
     RECT  86.245 34.032 86.316 34.056 ;
     RECT  86.245 34.056 86.357 34.128 ;
     RECT  86.245 34.128 86.316 34.152 ;
     RECT  86.245 34.152 86.357 34.224 ;
     RECT  86.245 34.224 86.316 34.248 ;
     RECT  86.245 34.248 86.357 34.32 ;
     RECT  86.245 34.32 86.316 34.344 ;
     RECT  86.245 34.344 86.357 34.416 ;
     RECT  86.245 34.416 86.316 34.44 ;
     RECT  86.245 34.44 86.357 34.512 ;
     RECT  86.245 34.512 86.316 34.536 ;
     RECT  86.245 34.536 86.357 34.608 ;
     RECT  86.245 34.608 86.316 34.632 ;
     RECT  86.245 34.632 86.357 34.704 ;
     RECT  86.245 34.704 86.316 34.728 ;
     RECT  86.245 34.728 86.357 34.8 ;
     RECT  86.245 34.8 86.316 34.824 ;
     RECT  86.245 34.824 86.357 34.896 ;
     RECT  86.245 34.896 86.316 34.92 ;
     RECT  86.245 34.92 86.357 34.992 ;
     RECT  86.245 34.992 86.316 35.016 ;
     RECT  86.245 35.016 86.357 35.088 ;
     RECT  86.245 35.088 86.316 35.112 ;
     RECT  86.245 35.112 86.357 35.184 ;
     RECT  86.245 35.184 86.316 35.208 ;
     RECT  86.245 35.208 86.357 35.28 ;
     RECT  86.245 35.28 86.316 35.304 ;
     RECT  86.245 35.304 86.357 35.376 ;
     RECT  86.245 35.376 86.316 35.4 ;
     RECT  86.245 35.4 86.357 35.472 ;
     RECT  86.245 35.472 86.316 35.496 ;
     RECT  86.245 35.496 86.357 35.568 ;
     RECT  86.245 35.568 86.316 35.592 ;
     RECT  86.245 35.592 86.357 35.664 ;
     RECT  86.245 35.664 86.316 35.688 ;
     RECT  86.245 35.688 86.357 35.76 ;
     RECT  86.245 35.76 86.316 35.784 ;
     RECT  86.245 35.784 86.357 35.856 ;
     RECT  86.245 35.856 86.316 35.88 ;
     RECT  86.245 35.88 86.357 35.952 ;
     RECT  86.245 35.952 86.316 35.976 ;
     RECT  86.245 35.976 86.357 36.048 ;
     RECT  86.245 36.048 86.316 36.072 ;
     RECT  86.245 36.072 86.357 36.144 ;
     RECT  86.245 36.144 86.316 36.168 ;
     RECT  86.245 36.168 86.357 36.24 ;
     RECT  86.245 36.24 86.316 36.264 ;
     RECT  86.245 36.264 86.357 36.336 ;
     RECT  86.245 36.336 86.316 36.36 ;
     RECT  86.245 36.36 86.357 36.432 ;
     RECT  86.245 36.432 86.316 36.456 ;
     RECT  86.245 36.456 86.357 36.528 ;
     RECT  86.245 36.528 86.316 36.552 ;
     RECT  86.245 36.552 86.357 36.624 ;
     RECT  86.245 36.624 86.316 36.648 ;
     RECT  86.245 36.648 86.357 36.72 ;
     RECT  86.245 36.72 86.316 36.744 ;
     RECT  86.245 36.744 86.357 36.816 ;
     RECT  86.245 36.816 86.316 36.84 ;
     RECT  86.245 36.84 86.357 36.912 ;
     RECT  86.245 36.912 86.316 36.936 ;
     RECT  86.245 36.936 86.357 37.008 ;
     RECT  86.245 37.008 86.316 37.032 ;
     RECT  86.245 37.032 86.357 37.104 ;
     RECT  86.245 37.104 86.316 37.128 ;
     RECT  86.245 37.128 86.357 37.2 ;
     RECT  86.245 37.2 86.316 37.224 ;
     RECT  86.245 37.224 86.357 37.296 ;
     RECT  86.245 37.296 86.316 37.32 ;
     RECT  86.245 37.32 86.357 37.392 ;
     RECT  86.245 37.392 86.316 37.416 ;
     RECT  86.245 37.416 86.357 37.488 ;
     RECT  86.245 37.488 86.316 37.512 ;
     RECT  86.245 37.512 86.357 37.584 ;
     RECT  86.245 37.584 86.316 37.608 ;
     RECT  86.245 37.608 86.357 37.68 ;
     RECT  86.245 37.68 86.316 37.704 ;
     RECT  86.245 37.704 86.357 37.776 ;
     RECT  86.245 37.776 86.316 37.8 ;
     RECT  86.245 37.8 86.357 37.872 ;
     RECT  86.245 37.872 86.316 37.896 ;
     RECT  86.245 37.896 86.357 37.968 ;
     RECT  86.245 37.968 86.316 37.992 ;
     RECT  86.245 37.992 86.357 38.064 ;
     RECT  86.245 38.064 86.316 38.088 ;
     RECT  86.245 38.088 86.357 38.16 ;
     RECT  86.245 38.16 86.316 38.184 ;
     RECT  86.245 38.184 86.357 38.256 ;
     RECT  86.245 38.256 86.316 38.28 ;
     RECT  86.245 38.28 86.357 38.352 ;
     RECT  86.245 38.352 86.316 38.376 ;
     RECT  86.245 38.376 86.357 38.448 ;
     RECT  86.245 38.448 86.316 38.472 ;
     RECT  86.245 38.472 86.357 38.544 ;
     RECT  86.245 38.544 86.316 38.568 ;
     RECT  86.245 38.568 86.357 39.408 ;
     RECT  86.245 39.408 86.316 39.432 ;
     RECT  86.245 39.432 86.357 39.504 ;
     RECT  86.245 39.504 86.316 39.528 ;
     RECT  86.245 39.528 86.357 39.6 ;
     RECT  86.245 39.6 86.316 39.624 ;
     RECT  86.245 39.624 86.357 39.696 ;
     RECT  86.245 39.696 86.316 39.72 ;
     RECT  86.245 39.72 86.357 39.792 ;
     RECT  86.245 39.792 86.316 39.816 ;
     RECT  86.245 39.816 86.357 39.888 ;
     RECT  86.245 39.888 86.316 39.912 ;
     RECT  86.245 39.912 86.357 39.984 ;
     RECT  86.245 39.984 86.316 40.008 ;
     RECT  86.245 40.008 86.357 40.08 ;
     RECT  86.245 40.08 86.316 40.104 ;
     RECT  86.245 40.104 86.357 40.176 ;
     RECT  86.245 40.176 86.316 40.2 ;
     RECT  86.245 40.2 86.357 40.272 ;
     RECT  86.245 40.272 86.316 40.296 ;
     RECT  86.245 40.296 86.357 40.368 ;
     RECT  86.245 40.368 86.316 40.392 ;
     RECT  86.245 40.392 86.357 40.464 ;
     RECT  86.245 40.464 86.316 40.488 ;
     RECT  86.245 40.488 86.357 40.56 ;
     RECT  86.245 40.56 86.316 40.584 ;
     RECT  86.245 40.584 86.357 40.656 ;
     RECT  86.245 40.656 86.316 40.68 ;
     RECT  86.245 40.68 86.357 40.752 ;
     RECT  86.245 40.752 86.316 40.776 ;
     RECT  86.245 40.776 86.357 40.848 ;
     RECT  86.245 40.848 86.316 40.872 ;
     RECT  86.245 40.872 86.357 40.944 ;
     RECT  86.245 40.944 86.316 40.968 ;
     RECT  86.245 40.968 86.357 41.04 ;
     RECT  86.245 41.04 86.316 41.064 ;
     RECT  86.245 41.064 86.357 41.136 ;
     RECT  86.245 41.136 86.316 41.16 ;
     RECT  86.245 41.16 86.357 41.232 ;
     RECT  86.245 41.232 86.316 41.256 ;
     RECT  86.245 41.256 86.357 41.328 ;
     RECT  86.245 41.328 86.316 41.352 ;
     RECT  86.245 41.352 86.357 41.424 ;
     RECT  86.245 41.424 86.316 41.448 ;
     RECT  86.245 41.448 86.357 41.52 ;
     RECT  86.245 41.52 86.316 41.544 ;
     RECT  86.245 41.544 86.357 41.616 ;
     RECT  86.245 41.616 86.316 41.64 ;
     RECT  86.245 41.64 86.357 41.712 ;
     RECT  86.245 41.712 86.316 41.736 ;
     RECT  86.245 41.736 86.357 41.808 ;
     RECT  86.245 41.808 86.316 41.832 ;
     RECT  86.245 41.832 86.357 41.904 ;
     RECT  86.245 41.904 86.316 41.928 ;
     RECT  86.245 41.928 86.357 42 ;
     RECT  86.245 42 86.316 42.024 ;
     RECT  86.245 42.024 86.357 42.096 ;
     RECT  86.245 42.096 86.316 42.12 ;
     RECT  86.245 42.12 86.357 42.192 ;
     RECT  86.245 42.192 86.316 42.216 ;
     RECT  86.245 42.216 86.357 42.288 ;
     RECT  86.245 42.288 86.316 42.312 ;
     RECT  86.245 42.312 86.357 42.384 ;
     RECT  86.245 42.384 86.316 42.408 ;
     RECT  86.245 42.408 86.357 42.552 ;
     RECT  86.357 16.392 86.364 16.464 ;
     RECT  86.357 16.488 86.364 16.56 ;
     RECT  86.357 16.584 86.364 16.656 ;
     RECT  86.357 16.68 86.364 16.752 ;
     RECT  86.357 16.776 86.364 16.848 ;
     RECT  86.357 16.872 86.364 16.944 ;
     RECT  86.357 16.968 86.364 17.04 ;
     RECT  86.357 17.064 86.364 17.136 ;
     RECT  86.357 17.16 86.364 17.232 ;
     RECT  86.357 17.256 86.364 17.328 ;
     RECT  86.357 17.352 86.364 17.424 ;
     RECT  86.357 17.448 86.364 17.52 ;
     RECT  86.357 17.544 86.364 17.616 ;
     RECT  86.357 17.64 86.364 17.712 ;
     RECT  86.357 17.736 86.364 17.808 ;
     RECT  86.357 17.832 86.364 17.904 ;
     RECT  86.357 17.928 86.364 18 ;
     RECT  86.357 18.024 86.364 18.096 ;
     RECT  86.357 18.12 86.364 18.192 ;
     RECT  86.357 18.216 86.364 18.288 ;
     RECT  86.357 18.312 86.364 18.384 ;
     RECT  86.357 18.408 86.364 18.48 ;
     RECT  86.357 18.504 86.364 18.576 ;
     RECT  86.357 18.6 86.364 18.672 ;
     RECT  86.357 18.696 86.364 18.768 ;
     RECT  86.357 18.792 86.364 18.864 ;
     RECT  86.357 18.888 86.364 18.96 ;
     RECT  86.357 18.984 86.364 19.056 ;
     RECT  86.357 19.08 86.364 19.152 ;
     RECT  86.357 19.176 86.364 19.248 ;
     RECT  86.357 19.272 86.364 19.344 ;
     RECT  86.357 19.368 86.364 20.208 ;
     RECT  86.357 20.232 86.364 20.304 ;
     RECT  86.357 20.328 86.364 20.4 ;
     RECT  86.357 20.424 86.364 20.496 ;
     RECT  86.357 20.52 86.364 20.592 ;
     RECT  86.357 20.616 86.364 20.688 ;
     RECT  86.357 20.712 86.364 20.784 ;
     RECT  86.357 20.808 86.364 20.88 ;
     RECT  86.357 20.904 86.364 20.976 ;
     RECT  86.357 21 86.364 21.072 ;
     RECT  86.357 21.096 86.364 21.168 ;
     RECT  86.357 21.192 86.364 21.264 ;
     RECT  86.357 21.288 86.364 21.36 ;
     RECT  86.357 21.384 86.364 21.456 ;
     RECT  86.357 21.48 86.364 21.552 ;
     RECT  86.357 21.576 86.364 21.648 ;
     RECT  86.357 21.672 86.364 21.744 ;
     RECT  86.357 21.768 86.364 21.84 ;
     RECT  86.357 21.864 86.364 21.936 ;
     RECT  86.357 21.96 86.364 22.032 ;
     RECT  86.357 22.056 86.364 22.128 ;
     RECT  86.357 22.152 86.364 22.224 ;
     RECT  86.357 22.248 86.364 22.32 ;
     RECT  86.357 22.344 86.364 22.416 ;
     RECT  86.357 22.44 86.364 22.512 ;
     RECT  86.357 22.536 86.364 22.608 ;
     RECT  86.357 22.632 86.364 22.704 ;
     RECT  86.357 22.728 86.364 22.8 ;
     RECT  86.357 22.824 86.364 22.896 ;
     RECT  86.357 22.92 86.364 22.992 ;
     RECT  86.357 23.016 86.364 23.088 ;
     RECT  86.357 23.112 86.364 23.184 ;
     RECT  86.357 23.208 86.364 23.28 ;
     RECT  86.357 23.304 86.364 23.376 ;
     RECT  86.357 23.4 86.364 23.472 ;
     RECT  86.357 23.496 86.364 23.568 ;
     RECT  86.357 23.592 86.364 23.664 ;
     RECT  86.357 23.688 86.364 23.76 ;
     RECT  86.357 23.784 86.364 23.856 ;
     RECT  86.357 23.88 86.364 23.952 ;
     RECT  86.357 23.976 86.364 24.048 ;
     RECT  86.357 24.072 86.364 24.144 ;
     RECT  86.357 24.168 86.364 24.24 ;
     RECT  86.357 24.264 86.364 24.336 ;
     RECT  86.357 24.36 86.364 24.432 ;
     RECT  86.357 24.456 86.364 24.528 ;
     RECT  86.357 24.552 86.364 24.624 ;
     RECT  86.357 24.648 86.364 24.72 ;
     RECT  86.357 24.744 86.364 24.816 ;
     RECT  86.357 24.84 86.364 24.912 ;
     RECT  86.357 24.936 86.364 25.008 ;
     RECT  86.357 25.032 86.364 25.104 ;
     RECT  86.357 25.128 86.364 25.2 ;
     RECT  86.357 25.224 86.364 25.296 ;
     RECT  86.357 25.32 86.364 25.392 ;
     RECT  86.357 25.416 86.364 25.488 ;
     RECT  86.357 25.512 86.364 25.584 ;
     RECT  86.357 25.608 86.364 25.68 ;
     RECT  86.357 25.704 86.364 25.776 ;
     RECT  86.357 25.8 86.364 25.872 ;
     RECT  86.357 25.896 86.364 25.968 ;
     RECT  86.357 25.992 86.364 26.064 ;
     RECT  86.357 26.088 86.364 26.16 ;
     RECT  86.357 26.184 86.364 26.256 ;
     RECT  86.357 26.28 86.364 26.352 ;
     RECT  86.357 26.376 86.364 26.448 ;
     RECT  86.357 26.472 86.364 26.544 ;
     RECT  86.357 26.568 86.364 26.64 ;
     RECT  86.357 26.664 86.364 26.736 ;
     RECT  86.357 26.76 86.364 26.832 ;
     RECT  86.357 26.856 86.364 26.928 ;
     RECT  86.357 26.952 86.364 27.024 ;
     RECT  86.357 27.048 86.364 27.12 ;
     RECT  86.357 27.144 86.364 27.216 ;
     RECT  86.357 27.24 86.364 27.312 ;
     RECT  86.357 27.336 86.364 27.408 ;
     RECT  86.357 27.432 86.364 27.504 ;
     RECT  86.357 27.528 86.364 27.6 ;
     RECT  86.357 27.624 86.364 27.696 ;
     RECT  86.357 27.72 86.364 27.792 ;
     RECT  86.357 27.816 86.364 27.888 ;
     RECT  86.357 27.912 86.364 27.984 ;
     RECT  86.357 28.008 86.364 28.08 ;
     RECT  86.357 28.104 86.364 28.176 ;
     RECT  86.357 28.2 86.364 28.272 ;
     RECT  86.357 28.296 86.364 28.368 ;
     RECT  86.357 28.392 86.364 28.464 ;
     RECT  86.357 28.488 86.364 28.56 ;
     RECT  86.357 28.584 86.364 28.656 ;
     RECT  86.357 28.68 86.364 28.752 ;
     RECT  86.357 28.776 86.364 28.848 ;
     RECT  86.357 28.872 86.364 28.944 ;
     RECT  86.357 28.968 86.364 29.04 ;
     RECT  86.357 29.064 86.364 29.136 ;
     RECT  86.357 29.16 86.364 29.232 ;
     RECT  86.357 29.256 86.364 29.328 ;
     RECT  86.357 29.352 86.364 29.424 ;
     RECT  86.357 29.448 86.364 29.52 ;
     RECT  86.357 29.544 86.364 29.616 ;
     RECT  86.357 29.64 86.364 29.712 ;
     RECT  86.357 29.736 86.364 29.808 ;
     RECT  86.357 29.832 86.364 29.904 ;
     RECT  86.357 29.928 86.364 30 ;
     RECT  86.357 30.024 86.364 30.096 ;
     RECT  86.357 30.12 86.364 30.192 ;
     RECT  86.357 30.216 86.364 30.288 ;
     RECT  86.357 30.312 86.364 30.384 ;
     RECT  86.357 30.408 86.364 30.48 ;
     RECT  86.357 30.504 86.364 30.576 ;
     RECT  86.357 30.6 86.364 30.672 ;
     RECT  86.357 30.696 86.364 30.768 ;
     RECT  86.357 30.792 86.364 30.864 ;
     RECT  86.357 30.888 86.364 30.96 ;
     RECT  86.357 30.984 86.364 31.056 ;
     RECT  86.357 31.08 86.364 31.152 ;
     RECT  86.357 31.176 86.364 31.248 ;
     RECT  86.357 31.272 86.364 31.344 ;
     RECT  86.357 31.368 86.364 31.44 ;
     RECT  86.357 31.464 86.364 31.536 ;
     RECT  86.357 31.56 86.364 31.632 ;
     RECT  86.357 31.656 86.364 31.728 ;
     RECT  86.357 31.752 86.364 31.824 ;
     RECT  86.357 31.848 86.364 31.92 ;
     RECT  86.357 31.944 86.364 32.016 ;
     RECT  86.357 32.04 86.364 32.112 ;
     RECT  86.357 32.136 86.364 32.208 ;
     RECT  86.357 32.232 86.364 32.304 ;
     RECT  86.357 32.328 86.364 32.4 ;
     RECT  86.357 32.424 86.364 32.496 ;
     RECT  86.357 32.52 86.364 32.592 ;
     RECT  86.357 32.616 86.364 32.688 ;
     RECT  86.357 32.712 86.364 32.784 ;
     RECT  86.357 32.808 86.364 32.88 ;
     RECT  86.357 32.904 86.364 32.976 ;
     RECT  86.357 33 86.364 33.072 ;
     RECT  86.357 33.096 86.364 33.168 ;
     RECT  86.357 33.192 86.364 33.264 ;
     RECT  86.357 33.288 86.364 33.36 ;
     RECT  86.357 33.384 86.364 33.456 ;
     RECT  86.357 33.48 86.364 33.552 ;
     RECT  86.357 33.576 86.364 33.648 ;
     RECT  86.357 33.672 86.364 33.744 ;
     RECT  86.357 33.768 86.364 33.84 ;
     RECT  86.357 33.864 86.364 33.936 ;
     RECT  86.357 33.96 86.364 34.032 ;
     RECT  86.357 34.056 86.364 34.128 ;
     RECT  86.357 34.152 86.364 34.224 ;
     RECT  86.357 34.248 86.364 34.32 ;
     RECT  86.357 34.344 86.364 34.416 ;
     RECT  86.357 34.44 86.364 34.512 ;
     RECT  86.357 34.536 86.364 34.608 ;
     RECT  86.357 34.632 86.364 34.704 ;
     RECT  86.357 34.728 86.364 34.8 ;
     RECT  86.357 34.824 86.364 34.896 ;
     RECT  86.357 34.92 86.364 34.992 ;
     RECT  86.357 35.016 86.364 35.088 ;
     RECT  86.357 35.112 86.364 35.184 ;
     RECT  86.357 35.208 86.364 35.28 ;
     RECT  86.357 35.304 86.364 35.376 ;
     RECT  86.357 35.4 86.364 35.472 ;
     RECT  86.357 35.496 86.364 35.568 ;
     RECT  86.357 35.592 86.364 35.664 ;
     RECT  86.357 35.688 86.364 35.76 ;
     RECT  86.357 35.784 86.364 35.856 ;
     RECT  86.357 35.88 86.364 35.952 ;
     RECT  86.357 35.976 86.364 36.048 ;
     RECT  86.357 36.072 86.364 36.144 ;
     RECT  86.357 36.168 86.364 36.24 ;
     RECT  86.357 36.264 86.364 36.336 ;
     RECT  86.357 36.36 86.364 36.432 ;
     RECT  86.357 36.456 86.364 36.528 ;
     RECT  86.357 36.552 86.364 36.624 ;
     RECT  86.357 36.648 86.364 36.72 ;
     RECT  86.357 36.744 86.364 36.816 ;
     RECT  86.357 36.84 86.364 36.912 ;
     RECT  86.357 36.936 86.364 37.008 ;
     RECT  86.357 37.032 86.364 37.104 ;
     RECT  86.357 37.128 86.364 37.2 ;
     RECT  86.357 37.224 86.364 37.296 ;
     RECT  86.357 37.32 86.364 37.392 ;
     RECT  86.357 37.416 86.364 37.488 ;
     RECT  86.357 37.512 86.364 37.584 ;
     RECT  86.357 37.608 86.364 37.68 ;
     RECT  86.357 37.704 86.364 37.776 ;
     RECT  86.357 37.8 86.364 37.872 ;
     RECT  86.357 37.896 86.364 37.968 ;
     RECT  86.357 37.992 86.364 38.064 ;
     RECT  86.357 38.088 86.364 38.16 ;
     RECT  86.357 38.184 86.364 38.256 ;
     RECT  86.357 38.28 86.364 38.352 ;
     RECT  86.357 38.376 86.364 38.448 ;
     RECT  86.357 38.472 86.364 38.544 ;
     RECT  86.357 38.568 86.364 39.408 ;
     RECT  86.357 39.432 86.364 39.504 ;
     RECT  86.357 39.528 86.364 39.6 ;
     RECT  86.357 39.624 86.364 39.696 ;
     RECT  86.357 39.72 86.364 39.792 ;
     RECT  86.357 39.816 86.364 39.888 ;
     RECT  86.357 39.912 86.364 39.984 ;
     RECT  86.357 40.008 86.364 40.08 ;
     RECT  86.357 40.104 86.364 40.176 ;
     RECT  86.357 40.2 86.364 40.272 ;
     RECT  86.357 40.296 86.364 40.368 ;
     RECT  86.357 40.392 86.364 40.464 ;
     RECT  86.357 40.488 86.364 40.56 ;
     RECT  86.357 40.584 86.364 40.656 ;
     RECT  86.357 40.68 86.364 40.752 ;
     RECT  86.357 40.776 86.364 40.848 ;
     RECT  86.357 40.872 86.364 40.944 ;
     RECT  86.357 40.968 86.364 41.04 ;
     RECT  86.357 41.064 86.364 41.136 ;
     RECT  86.357 41.16 86.364 41.232 ;
     RECT  86.357 41.256 86.364 41.328 ;
     RECT  86.357 41.352 86.364 41.424 ;
     RECT  86.357 41.448 86.364 41.52 ;
     RECT  86.357 41.544 86.364 41.616 ;
     RECT  86.357 41.64 86.364 41.712 ;
     RECT  86.357 41.736 86.364 41.808 ;
     RECT  86.357 41.832 86.364 41.904 ;
     RECT  86.357 41.928 86.364 42 ;
     RECT  86.357 42.024 86.364 42.096 ;
     RECT  86.357 42.12 86.364 42.192 ;
     RECT  86.357 42.216 86.364 42.288 ;
     RECT  86.357 42.312 86.364 42.384 ;
    LAYER M5 ;
     RECT  6.12 0.016 6.192 0.084 ;
     RECT  6.216 0.016 6.288 0.084 ;
     RECT  6.312 0.016 6.384 0.084 ;
     RECT  6.408 0.016 6.48 0.084 ;
     RECT  6.504 0.016 6.576 0.084 ;
     RECT  6.6 0.016 6.672 0.084 ;
     RECT  6.696 0.016 6.768 0.084 ;
     RECT  6.792 0.016 6.864 0.084 ;
     RECT  6.888 0.016 6.96 0.084 ;
     RECT  6.984 0.016 7.056 0.084 ;
     RECT  7.08 0.016 7.152 0.084 ;
     RECT  7.176 0.016 7.248 0.084 ;
     RECT  7.272 0.016 7.344 0.084 ;
     RECT  7.368 0.016 7.44 0.084 ;
     RECT  7.464 0.016 7.536 0.084 ;
     RECT  7.56 0.016 7.632 0.084 ;
     RECT  7.656 0.016 7.728 0.084 ;
     RECT  7.752 0.016 7.824 0.084 ;
     RECT  7.848 0.016 7.92 0.084 ;
     RECT  6.096 0.084 7.944 0.227 ;
     RECT  6.096 0.227 7.848 0.275 ;
     RECT  6.096 0.275 7.704 0.611 ;
     RECT  17.64 0.016 17.712 0.084 ;
     RECT  17.736 0.016 17.808 0.084 ;
     RECT  17.832 0.016 17.904 0.084 ;
     RECT  17.928 0.016 18 0.084 ;
     RECT  18.024 0.016 18.096 0.084 ;
     RECT  18.12 0.016 18.192 0.084 ;
     RECT  18.216 0.016 18.288 0.084 ;
     RECT  18.312 0.016 18.384 0.084 ;
     RECT  18.408 0.016 18.48 0.084 ;
     RECT  18.504 0.016 18.576 0.084 ;
     RECT  18.6 0.016 18.672 0.084 ;
     RECT  18.696 0.016 18.768 0.084 ;
     RECT  18.792 0.016 18.864 0.084 ;
     RECT  18.888 0.016 18.96 0.084 ;
     RECT  18.984 0.016 19.056 0.084 ;
     RECT  19.08 0.016 19.152 0.084 ;
     RECT  19.176 0.016 19.248 0.084 ;
     RECT  19.272 0.016 19.344 0.084 ;
     RECT  19.368 0.016 19.44 0.084 ;
     RECT  19.464 0.016 19.536 0.084 ;
     RECT  19.56 0.016 19.632 0.084 ;
     RECT  19.656 0.016 19.728 0.084 ;
     RECT  19.752 0.016 19.824 0.084 ;
     RECT  19.848 0.016 19.92 0.084 ;
     RECT  19.944 0.016 20.016 0.084 ;
     RECT  20.04 0.016 20.112 0.084 ;
     RECT  20.136 0.016 20.208 0.084 ;
     RECT  20.232 0.016 20.304 0.084 ;
     RECT  20.328 0.016 20.4 0.084 ;
     RECT  20.424 0.016 20.496 0.084 ;
     RECT  20.52 0.016 20.592 0.084 ;
     RECT  20.616 0.016 20.688 0.084 ;
     RECT  20.712 0.016 20.784 0.084 ;
     RECT  20.808 0.016 20.88 0.084 ;
     RECT  20.904 0.016 20.976 0.084 ;
     RECT  21 0.016 21.072 0.084 ;
     RECT  21.096 0.016 21.168 0.084 ;
     RECT  21.192 0.016 21.264 0.084 ;
     RECT  21.288 0.016 21.36 0.084 ;
     RECT  21.384 0.016 21.456 0.084 ;
     RECT  21.48 0.016 21.552 0.084 ;
     RECT  21.576 0.016 21.648 0.084 ;
     RECT  21.672 0.016 21.744 0.084 ;
     RECT  21.768 0.016 21.84 0.084 ;
     RECT  21.864 0.016 21.936 0.084 ;
     RECT  21.96 0.016 22.032 0.084 ;
     RECT  22.056 0.016 22.128 0.084 ;
     RECT  22.152 0.016 22.224 0.084 ;
     RECT  22.248 0.016 22.32 0.084 ;
     RECT  22.344 0.016 22.416 0.084 ;
     RECT  22.44 0.016 22.512 0.084 ;
     RECT  22.536 0.016 22.608 0.084 ;
     RECT  22.632 0.016 22.704 0.084 ;
     RECT  22.728 0.016 22.8 0.084 ;
     RECT  22.824 0.016 22.896 0.084 ;
     RECT  22.92 0.016 22.992 0.084 ;
     RECT  23.016 0.016 23.088 0.084 ;
     RECT  23.112 0.016 23.184 0.084 ;
     RECT  23.208 0.016 23.28 0.084 ;
     RECT  23.304 0.016 23.376 0.084 ;
     RECT  23.4 0.016 23.472 0.084 ;
     RECT  23.496 0.016 23.568 0.084 ;
     RECT  23.592 0.016 23.664 0.084 ;
     RECT  17.616 0.084 23.688 0.611 ;
     RECT  43.464 0.016 43.536 0.084 ;
     RECT  43.56 0.016 43.632 0.084 ;
     RECT  43.656 0.016 43.728 0.084 ;
     RECT  43.752 0.016 43.824 0.084 ;
     RECT  43.848 0.016 43.92 0.084 ;
     RECT  43.944 0.016 44.016 0.084 ;
     RECT  44.04 0.016 44.112 0.084 ;
     RECT  44.136 0.016 44.208 0.084 ;
     RECT  44.232 0.016 44.304 0.084 ;
     RECT  44.328 0.016 44.4 0.084 ;
     RECT  44.424 0.016 44.496 0.084 ;
     RECT  44.52 0.016 44.592 0.084 ;
     RECT  44.616 0.016 44.688 0.084 ;
     RECT  44.712 0.016 44.784 0.084 ;
     RECT  44.808 0.016 44.88 0.084 ;
     RECT  44.904 0.016 44.976 0.084 ;
     RECT  45 0.016 45.072 0.084 ;
     RECT  45.096 0.016 45.168 0.084 ;
     RECT  45.192 0.016 45.264 0.084 ;
     RECT  45.288 0.016 45.36 0.084 ;
     RECT  45.384 0.016 45.456 0.084 ;
     RECT  45.48 0.016 45.552 0.084 ;
     RECT  45.576 0.016 45.648 0.084 ;
     RECT  45.672 0.016 45.744 0.084 ;
     RECT  45.768 0.016 45.84 0.084 ;
     RECT  45.864 0.016 45.936 0.084 ;
     RECT  45.96 0.016 46.032 0.084 ;
     RECT  46.056 0.016 46.128 0.084 ;
     RECT  46.152 0.016 46.224 0.084 ;
     RECT  46.248 0.016 46.32 0.084 ;
     RECT  46.344 0.016 46.416 0.084 ;
     RECT  46.44 0.016 47.28 0.084 ;
     RECT  47.304 0.016 47.376 0.084 ;
     RECT  47.4 0.016 47.472 0.084 ;
     RECT  47.496 0.016 47.568 0.084 ;
     RECT  47.592 0.016 47.664 0.084 ;
     RECT  47.688 0.016 47.76 0.084 ;
     RECT  47.784 0.016 47.856 0.084 ;
     RECT  47.88 0.016 47.952 0.084 ;
     RECT  47.976 0.016 48.048 0.084 ;
     RECT  48.072 0.016 48.144 0.084 ;
     RECT  48.168 0.016 48.24 0.084 ;
     RECT  48.264 0.016 48.336 0.084 ;
     RECT  48.36 0.016 48.432 0.084 ;
     RECT  48.456 0.016 48.528 0.084 ;
     RECT  48.552 0.016 48.624 0.084 ;
     RECT  48.648 0.016 48.72 0.084 ;
     RECT  48.744 0.016 48.816 0.084 ;
     RECT  48.84 0.016 48.912 0.084 ;
     RECT  48.936 0.016 49.008 0.084 ;
     RECT  49.032 0.016 49.104 0.084 ;
     RECT  49.128 0.016 49.2 0.084 ;
     RECT  49.224 0.016 49.296 0.084 ;
     RECT  49.32 0.016 49.392 0.084 ;
     RECT  49.416 0.016 49.488 0.084 ;
     RECT  49.512 0.016 49.584 0.084 ;
     RECT  49.608 0.016 49.68 0.084 ;
     RECT  49.704 0.016 49.776 0.084 ;
     RECT  49.8 0.016 49.872 0.084 ;
     RECT  49.896 0.016 49.968 0.084 ;
     RECT  49.992 0.016 50.064 0.084 ;
     RECT  50.088 0.016 50.16 0.084 ;
     RECT  50.184 0.016 50.256 0.084 ;
     RECT  50.28 0.016 50.352 0.084 ;
     RECT  50.376 0.016 50.448 0.084 ;
     RECT  50.472 0.016 50.544 0.084 ;
     RECT  50.568 0.016 50.64 0.084 ;
     RECT  50.664 0.016 50.736 0.084 ;
     RECT  50.76 0.016 50.832 0.084 ;
     RECT  50.856 0.016 50.928 0.084 ;
     RECT  50.952 0.016 51.024 0.084 ;
     RECT  51.048 0.016 51.12 0.084 ;
     RECT  51.144 0.016 51.216 0.084 ;
     RECT  51.24 0.016 51.312 0.084 ;
     RECT  51.336 0.016 51.408 0.084 ;
     RECT  51.432 0.016 51.504 0.084 ;
     RECT  51.528 0.016 51.6 0.084 ;
     RECT  51.624 0.016 51.696 0.084 ;
     RECT  51.72 0.016 51.792 0.084 ;
     RECT  51.816 0.016 51.888 0.084 ;
     RECT  51.912 0.016 51.984 0.084 ;
     RECT  52.008 0.016 52.08 0.084 ;
     RECT  52.104 0.016 52.176 0.084 ;
     RECT  52.2 0.016 52.272 0.084 ;
     RECT  52.296 0.016 52.368 0.084 ;
     RECT  52.392 0.016 52.464 0.084 ;
     RECT  52.488 0.016 52.56 0.084 ;
     RECT  52.584 0.016 52.656 0.084 ;
     RECT  52.68 0.016 52.752 0.084 ;
     RECT  52.776 0.016 52.848 0.084 ;
     RECT  52.872 0.016 52.944 0.084 ;
     RECT  52.968 0.016 53.04 0.084 ;
     RECT  53.064 0.016 53.136 0.084 ;
     RECT  53.16 0.016 53.232 0.084 ;
     RECT  53.256 0.016 53.328 0.084 ;
     RECT  53.352 0.016 53.424 0.084 ;
     RECT  53.448 0.016 53.52 0.084 ;
     RECT  53.544 0.016 53.616 0.084 ;
     RECT  53.64 0.016 53.712 0.084 ;
     RECT  53.736 0.016 53.808 0.084 ;
     RECT  53.832 0.016 53.904 0.084 ;
     RECT  53.928 0.016 54 0.084 ;
     RECT  54.024 0.016 54.096 0.084 ;
     RECT  54.12 0.016 54.192 0.084 ;
     RECT  54.216 0.016 54.288 0.084 ;
     RECT  54.312 0.016 54.384 0.084 ;
     RECT  54.408 0.016 54.48 0.084 ;
     RECT  54.504 0.016 54.576 0.084 ;
     RECT  54.6 0.016 54.672 0.084 ;
     RECT  54.696 0.016 54.768 0.084 ;
     RECT  54.792 0.016 54.864 0.084 ;
     RECT  54.888 0.016 54.96 0.084 ;
     RECT  54.984 0.016 55.056 0.084 ;
     RECT  55.08 0.016 55.152 0.084 ;
     RECT  55.176 0.016 55.248 0.084 ;
     RECT  55.272 0.016 55.344 0.084 ;
     RECT  55.368 0.016 55.44 0.084 ;
     RECT  55.464 0.016 55.536 0.084 ;
     RECT  55.56 0.016 55.632 0.084 ;
     RECT  55.656 0.016 55.728 0.084 ;
     RECT  55.752 0.016 55.824 0.084 ;
     RECT  55.848 0.016 55.92 0.084 ;
     RECT  55.944 0.016 56.016 0.084 ;
     RECT  56.04 0.016 56.112 0.084 ;
     RECT  56.136 0.016 56.208 0.084 ;
     RECT  56.232 0.016 56.304 0.084 ;
     RECT  56.328 0.016 56.4 0.084 ;
     RECT  56.424 0.016 56.496 0.084 ;
     RECT  56.52 0.016 56.592 0.084 ;
     RECT  56.616 0.016 56.688 0.084 ;
     RECT  56.712 0.016 56.784 0.084 ;
     RECT  56.808 0.016 56.88 0.084 ;
     RECT  56.904 0.016 56.976 0.084 ;
     RECT  57 0.016 57.072 0.084 ;
     RECT  57.096 0.016 57.168 0.084 ;
     RECT  57.192 0.016 57.264 0.084 ;
     RECT  57.288 0.016 57.36 0.084 ;
     RECT  57.384 0.016 57.456 0.084 ;
     RECT  57.48 0.016 57.552 0.084 ;
     RECT  57.576 0.016 57.648 0.084 ;
     RECT  57.672 0.016 57.744 0.084 ;
     RECT  57.768 0.016 57.84 0.084 ;
     RECT  57.864 0.016 57.936 0.084 ;
     RECT  57.96 0.016 58.032 0.084 ;
     RECT  58.056 0.016 58.128 0.084 ;
     RECT  58.152 0.016 58.224 0.084 ;
     RECT  58.248 0.016 58.32 0.084 ;
     RECT  58.344 0.016 58.416 0.084 ;
     RECT  58.44 0.016 58.512 0.084 ;
     RECT  58.536 0.016 58.608 0.084 ;
     RECT  58.632 0.016 58.704 0.084 ;
     RECT  58.728 0.016 58.8 0.084 ;
     RECT  58.824 0.016 58.896 0.084 ;
     RECT  58.92 0.016 58.992 0.084 ;
     RECT  59.016 0.016 59.088 0.084 ;
     RECT  59.112 0.016 59.184 0.084 ;
     RECT  59.208 0.016 59.28 0.084 ;
     RECT  59.304 0.016 59.376 0.084 ;
     RECT  59.4 0.016 59.472 0.084 ;
     RECT  59.496 0.016 59.568 0.084 ;
     RECT  59.592 0.016 59.664 0.084 ;
     RECT  59.688 0.016 59.76 0.084 ;
     RECT  59.784 0.016 59.856 0.084 ;
     RECT  59.88 0.016 59.952 0.084 ;
     RECT  59.976 0.016 60.048 0.084 ;
     RECT  60.072 0.016 60.144 0.084 ;
     RECT  60.168 0.016 60.24 0.084 ;
     RECT  60.264 0.016 60.336 0.084 ;
     RECT  60.36 0.016 60.432 0.084 ;
     RECT  60.456 0.016 60.528 0.084 ;
     RECT  60.552 0.016 60.624 0.084 ;
     RECT  60.648 0.016 60.72 0.084 ;
     RECT  60.744 0.016 60.816 0.084 ;
     RECT  60.84 0.016 60.912 0.084 ;
     RECT  60.936 0.016 61.008 0.084 ;
     RECT  61.032 0.016 61.104 0.084 ;
     RECT  61.128 0.016 61.2 0.084 ;
     RECT  61.224 0.016 61.296 0.084 ;
     RECT  61.32 0.016 61.392 0.084 ;
     RECT  61.416 0.016 61.488 0.084 ;
     RECT  61.512 0.016 61.584 0.084 ;
     RECT  61.608 0.016 61.68 0.084 ;
     RECT  61.704 0.016 61.776 0.084 ;
     RECT  61.8 0.016 61.872 0.084 ;
     RECT  61.896 0.016 61.968 0.084 ;
     RECT  61.992 0.016 62.064 0.084 ;
     RECT  62.088 0.016 62.16 0.084 ;
     RECT  62.184 0.016 62.256 0.084 ;
     RECT  62.28 0.016 62.352 0.084 ;
     RECT  62.376 0.016 62.448 0.084 ;
     RECT  62.472 0.016 62.544 0.084 ;
     RECT  62.568 0.016 62.64 0.084 ;
     RECT  62.664 0.016 62.736 0.084 ;
     RECT  62.76 0.016 62.832 0.084 ;
     RECT  62.856 0.016 62.928 0.084 ;
     RECT  62.952 0.016 63.024 0.084 ;
     RECT  63.048 0.016 63.12 0.084 ;
     RECT  63.144 0.016 63.216 0.084 ;
     RECT  63.24 0.016 63.312 0.084 ;
     RECT  63.336 0.016 63.408 0.084 ;
     RECT  63.432 0.016 63.504 0.084 ;
     RECT  63.528 0.016 63.6 0.084 ;
     RECT  63.624 0.016 63.696 0.084 ;
     RECT  63.72 0.016 63.792 0.084 ;
     RECT  63.816 0.016 63.888 0.084 ;
     RECT  63.912 0.016 63.984 0.084 ;
     RECT  64.008 0.016 64.08 0.084 ;
     RECT  64.104 0.016 64.176 0.084 ;
     RECT  64.2 0.016 64.272 0.084 ;
     RECT  64.296 0.016 64.368 0.084 ;
     RECT  64.392 0.016 64.464 0.084 ;
     RECT  64.488 0.016 64.56 0.084 ;
     RECT  64.584 0.016 64.656 0.084 ;
     RECT  64.68 0.016 64.752 0.084 ;
     RECT  64.776 0.016 64.848 0.084 ;
     RECT  64.872 0.016 64.944 0.084 ;
     RECT  64.968 0.016 65.04 0.084 ;
     RECT  65.064 0.016 65.136 0.084 ;
     RECT  65.16 0.016 65.232 0.084 ;
     RECT  65.256 0.016 65.328 0.084 ;
     RECT  65.352 0.016 65.424 0.084 ;
     RECT  65.448 0.016 65.52 0.084 ;
     RECT  65.544 0.016 65.616 0.084 ;
     RECT  65.64 0.016 66.48 0.084 ;
     RECT  66.504 0.016 66.576 0.084 ;
     RECT  66.6 0.016 66.672 0.084 ;
     RECT  66.696 0.016 66.768 0.084 ;
     RECT  66.792 0.016 66.864 0.084 ;
     RECT  66.888 0.016 66.96 0.084 ;
     RECT  66.984 0.016 67.056 0.084 ;
     RECT  67.08 0.016 67.152 0.084 ;
     RECT  67.176 0.016 67.248 0.084 ;
     RECT  67.272 0.016 67.344 0.084 ;
     RECT  67.368 0.016 67.44 0.084 ;
     RECT  67.464 0.016 67.536 0.084 ;
     RECT  67.56 0.016 67.632 0.084 ;
     RECT  67.656 0.016 67.728 0.084 ;
     RECT  67.752 0.016 67.824 0.084 ;
     RECT  67.848 0.016 67.92 0.084 ;
     RECT  67.944 0.016 68.016 0.084 ;
     RECT  68.04 0.016 68.112 0.084 ;
     RECT  68.136 0.016 68.208 0.084 ;
     RECT  68.232 0.016 68.304 0.084 ;
     RECT  68.328 0.016 68.4 0.084 ;
     RECT  68.424 0.016 68.496 0.084 ;
     RECT  68.52 0.016 68.592 0.084 ;
     RECT  68.616 0.016 68.688 0.084 ;
     RECT  68.712 0.016 68.784 0.084 ;
     RECT  68.808 0.016 68.88 0.084 ;
     RECT  68.904 0.016 68.976 0.084 ;
     RECT  69 0.016 69.072 0.084 ;
     RECT  69.096 0.016 69.168 0.084 ;
     RECT  69.192 0.016 69.264 0.084 ;
     RECT  69.288 0.016 69.36 0.084 ;
     RECT  69.384 0.016 69.456 0.084 ;
     RECT  43.44 0.084 69.48 0.611 ;
     RECT  1.896 0.016 1.968 0.084 ;
     RECT  1.992 0.016 2.064 0.084 ;
     RECT  2.088 0.016 2.16 0.084 ;
     RECT  1.872 0.084 2.184 1.763 ;
     RECT  6.192 0.611 7.704 1.763 ;
     RECT  9.192 0.016 9.264 0.084 ;
     RECT  9.288 0.016 9.36 0.084 ;
     RECT  9.384 0.016 9.456 0.084 ;
     RECT  9.48 0.016 9.552 0.084 ;
     RECT  9.576 0.016 9.648 0.084 ;
     RECT  9.672 0.016 9.744 0.084 ;
     RECT  9.768 0.016 9.84 0.084 ;
     RECT  9.864 0.016 9.936 0.084 ;
     RECT  9.96 0.016 10.032 0.084 ;
     RECT  10.056 0.016 10.128 0.084 ;
     RECT  10.152 0.016 10.224 0.084 ;
     RECT  10.248 0.016 10.32 0.084 ;
     RECT  10.344 0.016 10.416 0.084 ;
     RECT  10.44 0.016 10.512 0.084 ;
     RECT  10.536 0.016 10.608 0.084 ;
     RECT  10.632 0.016 10.704 0.084 ;
     RECT  10.728 0.016 10.8 0.084 ;
     RECT  10.824 0.016 10.896 0.084 ;
     RECT  10.92 0.016 10.992 0.084 ;
     RECT  11.016 0.016 11.088 0.084 ;
     RECT  11.112 0.016 11.184 0.084 ;
     RECT  11.208 0.016 11.28 0.084 ;
     RECT  11.304 0.016 11.376 0.084 ;
     RECT  11.4 0.016 11.472 0.084 ;
     RECT  11.496 0.016 11.568 0.084 ;
     RECT  11.592 0.016 11.664 0.084 ;
     RECT  11.688 0.016 11.76 0.084 ;
     RECT  11.784 0.016 11.856 0.084 ;
     RECT  11.88 0.016 11.952 0.084 ;
     RECT  11.976 0.016 12.048 0.084 ;
     RECT  12.072 0.016 12.144 0.084 ;
     RECT  9.168 0.084 12.168 1.763 ;
     RECT  17.808 0.611 23.688 1.763 ;
     RECT  43.536 0.611 69.48 1.763 ;
     RECT  1.968 1.763 2.184 1.811 ;
     RECT  17.904 1.763 23.688 1.811 ;
     RECT  43.632 1.763 46.44 1.811 ;
     RECT  66.576 1.763 69.48 1.811 ;
     RECT  43.824 1.811 46.344 1.859 ;
     RECT  9.456 1.763 12.168 1.955 ;
     RECT  6.864 1.763 7.704 2.137 ;
     RECT  18.096 1.811 23.688 2.137 ;
     RECT  2.4 2.137 2.52 2.151 ;
     RECT  6.864 2.137 7.92 2.151 ;
     RECT  13.2 2.137 13.32 2.151 ;
     RECT  18.096 2.137 24.12 2.151 ;
     RECT  29.4 2.137 29.52 2.151 ;
     RECT  34.8 2.137 34.92 2.151 ;
     RECT  40.2 2.137 40.32 2.151 ;
     RECT  72.6 2.137 72.72 2.151 ;
     RECT  78 2.137 78.12 2.151 ;
     RECT  83.4 2.137 83.52 2.151 ;
     RECT  6.864 2.151 8.112 2.291 ;
     RECT  18.096 2.151 24.312 2.291 ;
     RECT  66.96 1.811 69.48 2.291 ;
     RECT  7.056 2.291 8.112 2.339 ;
     RECT  47.472 1.763 65.544 2.339 ;
     RECT  9.456 1.955 11.976 2.435 ;
     RECT  9.456 2.435 11.88 2.627 ;
     RECT  3.984 2.341 4.008 2.915 ;
     RECT  18.096 2.291 22.728 2.915 ;
     RECT  43.824 1.859 46.152 2.915 ;
     RECT  48.048 2.339 65.544 2.915 ;
     RECT  66.96 2.291 68.904 2.915 ;
     RECT  18.288 2.915 22.728 2.963 ;
     RECT  43.92 2.915 46.152 2.963 ;
     RECT  66.96 2.915 68.808 3.059 ;
     RECT  18.288 2.963 22.632 3.347 ;
     RECT  18.336 3.347 22.632 3.443 ;
     RECT  48.048 2.915 48.072 3.443 ;
     RECT  67.2 3.059 68.808 3.443 ;
     RECT  22.608 3.443 22.632 3.491 ;
     RECT  49.488 2.915 65.448 3.539 ;
     RECT  18.336 3.443 21.48 3.635 ;
     RECT  9.456 2.627 10.92 4.019 ;
     RECT  18.6 3.635 21.48 4.019 ;
     RECT  44.592 2.963 46.152 4.019 ;
     RECT  49.488 3.539 57.384 4.019 ;
     RECT  58.464 3.539 65.448 4.019 ;
     RECT  19.92 4.019 20.616 4.163 ;
     RECT  61.68 4.019 65.064 4.163 ;
     RECT  49.68 4.019 57.384 4.259 ;
     RECT  5.136 2.869 5.16 4.451 ;
     RECT  9.936 4.019 10.92 4.595 ;
     RECT  20.016 4.163 20.616 4.595 ;
     RECT  58.896 4.019 60.408 4.643 ;
     RECT  45.36 4.019 46.152 4.691 ;
     RECT  25.344 3.733 25.368 4.931 ;
     RECT  45.456 4.691 46.152 4.981 ;
     RECT  61.68 4.163 63.816 5.171 ;
     RECT  65.04 4.163 65.064 5.173 ;
     RECT  63.168 5.171 63.816 5.221 ;
     RECT  64.992 5.173 65.064 5.221 ;
     RECT  63.168 5.221 65.064 5.269 ;
     RECT  50.4 4.259 57.384 5.555 ;
     RECT  61.68 5.171 62.112 5.557 ;
     RECT  50.832 5.555 57.384 5.603 ;
     RECT  45.456 4.981 46.92 5.747 ;
     RECT  20.496 4.595 20.52 5.795 ;
     RECT  58.896 4.643 59.016 5.795 ;
     RECT  60.192 4.643 60.408 5.843 ;
     RECT  48.672 5.173 48.696 5.989 ;
     RECT  9.936 4.595 9.96 6.085 ;
     RECT  7.344 2.339 8.112 6.131 ;
     RECT  48.672 5.989 49.08 6.131 ;
     RECT  46.896 5.747 46.92 6.275 ;
     RECT  45.456 5.747 45.912 6.323 ;
     RECT  63.168 5.269 65.208 6.323 ;
     RECT  63.168 6.323 63.816 6.563 ;
     RECT  65.184 6.323 65.208 6.565 ;
     RECT  58.992 5.795 59.016 6.661 ;
     RECT  48.672 6.131 48.696 6.757 ;
     RECT  22.32 4.645 22.344 6.803 ;
     RECT  65.184 6.565 65.544 6.805 ;
     RECT  47.712 6.757 48.696 6.899 ;
     RECT  51 5.603 57.384 6.899 ;
     RECT  52.56 6.899 57.384 6.947 ;
     RECT  52.896 6.947 57.384 7.333 ;
     RECT  58.992 6.661 59.832 7.333 ;
     RECT  52.896 7.333 59.832 7.381 ;
     RECT  9.552 6.085 9.96 7.475 ;
     RECT  52.896 7.381 59.976 7.523 ;
     RECT  65.184 6.805 65.64 7.619 ;
     RECT  55.584 7.523 59.976 7.909 ;
     RECT  61.536 5.557 62.112 7.909 ;
     RECT  55.584 7.909 62.112 7.957 ;
     RECT  67.2 3.443 67.512 8.005 ;
     RECT  52.896 7.523 54.312 8.051 ;
     RECT  53.328 8.051 54.312 8.195 ;
     RECT  7.8 6.131 8.112 8.293 ;
     RECT  63.792 6.563 63.816 8.435 ;
     RECT  55.584 7.957 62.664 8.485 ;
     RECT  67.056 8.005 67.512 9.493 ;
     RECT  7.68 8.293 8.112 15.493 ;
     RECT  72.6 2.151 72.912 16.885 ;
     RECT  67.056 9.493 68.328 16.981 ;
     RECT  78 2.151 78.312 17.077 ;
     RECT  77.04 17.077 78.312 17.125 ;
     RECT  13.2 2.151 13.512 17.317 ;
     RECT  65.184 7.619 65.544 17.461 ;
     RECT  72.24 16.885 72.912 17.461 ;
     RECT  67.056 16.981 68.952 17.509 ;
     RECT  6.864 15.493 8.112 17.557 ;
     RECT  6.864 17.557 8.28 18.083 ;
     RECT  64.704 17.461 65.544 18.181 ;
     RECT  12.816 17.317 13.512 18.277 ;
     RECT  71.376 17.461 72.912 18.565 ;
     RECT  64.704 18.181 65.88 18.709 ;
     RECT  63.888 18.709 65.88 18.757 ;
     RECT  71.232 18.565 72.912 18.757 ;
     RECT  76.464 17.125 78.312 18.949 ;
     RECT  6.864 18.083 8.112 19.235 ;
     RECT  71.184 18.757 72.912 19.285 ;
     RECT  18.6 4.019 18.912 19.333 ;
     RECT  19.92 6.085 19.944 19.333 ;
     RECT  12.72 18.277 13.512 19.379 ;
     RECT  67.056 17.509 69 19.573 ;
     RECT  71.04 19.285 72.912 19.621 ;
     RECT  67.056 19.573 69.288 19.813 ;
     RECT  0.144 19.573 0.168 19.859 ;
     RECT  55.392 8.485 62.664 19.861 ;
     RECT  63.888 18.757 65.976 19.861 ;
     RECT  76.416 18.949 78.312 19.861 ;
     RECT  76.128 19.861 78.312 19.909 ;
     RECT  76.128 19.909 78.648 20.053 ;
     RECT  70.848 19.621 72.912 20.101 ;
     RECT  55.392 19.861 65.976 20.149 ;
     RECT  67.056 19.813 69.528 20.149 ;
     RECT  9.936 7.475 9.96 20.341 ;
     RECT  76.08 20.053 78.648 20.485 ;
     RECT  75.888 20.485 78.648 20.579 ;
     RECT  17.424 19.621 17.448 20.723 ;
     RECT  9.552 20.341 9.96 20.819 ;
     RECT  9.552 20.819 9.624 20.965 ;
     RECT  0.144 20.869 0.168 21.059 ;
     RECT  9.168 20.965 9.624 21.251 ;
     RECT  70.848 20.101 73.848 21.253 ;
     RECT  75.888 20.579 78.312 21.395 ;
     RECT  75.888 21.395 77.016 21.397 ;
     RECT  70.704 21.253 73.848 21.491 ;
     RECT  7.8 19.235 8.112 21.541 ;
     RECT  75.792 21.397 77.016 21.781 ;
     RECT  16.368 20.965 16.392 21.971 ;
     RECT  5.088 17.509 5.112 22.019 ;
     RECT  12 21.685 12.024 22.021 ;
     RECT  13.2 19.379 13.512 22.021 ;
     RECT  12 22.021 13.512 22.067 ;
     RECT  9.408 21.251 9.624 22.357 ;
     RECT  10.704 22.165 10.728 22.357 ;
     RECT  18.6 19.333 19.944 22.451 ;
     RECT  24 2.291 24.312 22.645 ;
     RECT  6.528 22.069 6.552 22.741 ;
     RECT  9.408 22.357 10.728 22.789 ;
     RECT  7.632 21.541 8.112 22.835 ;
     RECT  9.408 22.789 10.776 22.979 ;
     RECT  12.336 22.067 13.512 22.979 ;
     RECT  75.024 21.781 77.016 23.125 ;
     RECT  23.904 22.645 24.312 23.171 ;
     RECT  10.704 22.979 10.776 23.173 ;
     RECT  6 22.741 6.552 23.315 ;
     RECT  2.4 2.151 2.712 23.317 ;
     RECT  74.16 23.125 77.016 23.363 ;
     RECT  55.392 20.149 69.528 23.413 ;
     RECT  0.144 23.029 0.168 23.603 ;
     RECT  55.392 23.413 69.624 23.749 ;
     RECT  70.704 21.491 72.912 23.749 ;
     RECT  74.16 23.363 76.92 23.939 ;
     RECT  15.024 23.317 15.048 23.987 ;
     RECT  6 23.315 6.024 24.083 ;
     RECT  2.4 23.317 3 24.085 ;
     RECT  13.2 22.979 13.512 24.373 ;
     RECT  7.8 22.835 8.112 24.469 ;
     RECT  74.16 23.939 76.488 24.515 ;
     RECT  2.4 24.085 3.336 24.563 ;
     RECT  55.392 23.749 72.912 24.707 ;
     RECT  9.408 22.979 9.576 24.757 ;
     RECT  26.16 23.941 26.184 24.899 ;
     RECT  9.36 24.757 9.576 24.901 ;
     RECT  7.68 24.469 8.112 24.949 ;
     RECT  9.12 24.901 9.576 24.949 ;
     RECT  10.704 23.173 11.064 24.949 ;
     RECT  86.208 24.277 86.232 25.043 ;
     RECT  55.392 24.707 69.384 25.283 ;
     RECT  7.68 24.949 9.576 25.285 ;
     RECT  76.464 24.515 76.488 25.285 ;
     RECT  10.704 24.949 11.304 25.333 ;
     RECT  18.6 22.451 19.08 25.429 ;
     RECT  7.68 25.285 9.624 25.619 ;
     RECT  74.16 24.515 75.192 25.715 ;
     RECT  12.912 24.373 13.512 25.765 ;
     RECT  18.6 25.429 19.608 25.861 ;
     RECT  12.576 25.765 13.512 25.907 ;
     RECT  74.688 25.715 75.192 25.955 ;
     RECT  70.704 24.707 72.912 26.005 ;
     RECT  10.704 25.333 11.4 26.051 ;
     RECT  7.68 25.619 8.112 26.149 ;
     RECT  9.408 25.619 9.624 26.197 ;
     RECT  10.704 26.051 11.304 26.197 ;
     RECT  76.464 25.285 76.776 26.197 ;
     RECT  70.704 26.005 73.032 26.243 ;
     RECT  76.464 26.197 76.92 26.243 ;
     RECT  55.392 25.283 69.048 26.293 ;
     RECT  9.408 26.197 11.304 26.339 ;
     RECT  55.392 26.293 69.192 26.533 ;
     RECT  12.912 25.907 13.512 26.725 ;
     RECT  18.6 25.861 19.704 26.725 ;
     RECT  18.384 26.725 19.704 26.819 ;
     RECT  26.736 26.005 26.76 26.819 ;
     RECT  32.496 25.285 32.52 26.915 ;
     RECT  76.752 26.243 76.92 26.965 ;
     RECT  12.912 26.725 13.608 27.061 ;
     RECT  12.384 27.061 13.608 27.107 ;
     RECT  75.168 25.955 75.192 27.157 ;
     RECT  74.688 27.157 75.192 27.203 ;
     RECT  74.688 27.203 74.712 27.301 ;
     RECT  6.96 26.149 8.112 27.347 ;
     RECT  70.704 26.243 72.912 27.395 ;
     RECT  18.384 26.819 19.176 27.443 ;
     RECT  27.36 27.301 27.768 27.683 ;
     RECT  76.752 26.965 76.968 27.733 ;
     RECT  9.408 26.339 11.064 27.877 ;
     RECT  12.384 27.107 13.512 27.877 ;
     RECT  29.4 2.151 29.712 27.877 ;
     RECT  27.36 27.683 27.384 27.923 ;
     RECT  74.064 27.301 74.712 28.019 ;
     RECT  76.656 27.733 76.968 28.019 ;
     RECT  29.4 27.877 29.832 28.211 ;
     RECT  36.96 27.877 36.984 28.211 ;
     RECT  51 6.899 51.432 28.501 ;
     RECT  70.752 27.395 72.912 28.547 ;
     RECT  70.944 28.547 72.912 28.787 ;
     RECT  50.88 28.501 51.432 28.933 ;
     RECT  86.208 28.165 86.232 28.979 ;
     RECT  76.752 28.019 76.824 29.029 ;
     RECT  50.784 28.933 51.432 29.077 ;
     RECT  9.408 27.877 13.512 29.123 ;
     RECT  50.784 29.077 51.528 29.219 ;
     RECT  18.6 27.443 19.176 29.317 ;
     RECT  50.88 29.219 51.528 29.365 ;
     RECT  2.4 24.563 2.712 29.461 ;
     RECT  53.328 8.195 53.736 29.557 ;
     RECT  2.4 29.461 2.808 29.603 ;
     RECT  7.008 27.347 8.112 29.699 ;
     RECT  9.408 29.123 11.064 29.699 ;
     RECT  71.04 28.787 72.912 29.699 ;
     RECT  71.28 29.699 72.912 29.747 ;
     RECT  76.656 29.029 76.824 29.795 ;
     RECT  76.752 29.795 76.824 29.891 ;
     RECT  53.28 29.557 53.736 29.989 ;
     RECT  50.88 29.365 51.576 30.037 ;
     RECT  0.144 29.797 0.168 30.083 ;
     RECT  18.6 29.317 19.416 30.227 ;
     RECT  48.672 6.899 48.696 30.229 ;
     RECT  50.88 30.037 51.816 30.419 ;
     RECT  83.4 2.151 83.712 30.613 ;
     RECT  72.24 29.747 72.912 30.707 ;
     RECT  5.664 30.181 5.688 30.755 ;
     RECT  12.384 29.123 13.512 30.805 ;
     RECT  3.936 26.917 3.96 30.851 ;
     RECT  48.672 30.229 49.08 30.947 ;
     RECT  45.6 6.323 45.912 30.949 ;
     RECT  47.088 29.605 47.112 30.949 ;
     RECT  82.608 30.613 83.712 30.949 ;
     RECT  76.752 29.891 76.776 30.995 ;
     RECT  82.416 30.949 83.712 31.091 ;
     RECT  55.392 26.533 69.336 31.187 ;
     RECT  12.384 30.805 13.704 31.237 ;
     RECT  53.28 29.989 53.832 31.333 ;
     RECT  53.088 31.333 53.832 31.477 ;
     RECT  12.384 31.237 14.232 31.525 ;
     RECT  10.704 29.699 11.064 31.573 ;
     RECT  12.24 31.525 14.232 31.573 ;
     RECT  70.848 31.237 70.872 31.669 ;
     RECT  45.6 30.949 47.112 31.955 ;
     RECT  10.704 31.573 14.232 32.003 ;
     RECT  47.088 31.955 47.112 32.147 ;
     RECT  55.392 31.187 57.192 32.293 ;
     RECT  58.176 31.187 69.336 32.293 ;
     RECT  86.208 32.197 86.232 32.387 ;
     RECT  51 30.419 51.816 32.437 ;
     RECT  48.672 30.947 48.696 32.581 ;
     RECT  55.392 32.293 69.336 32.629 ;
     RECT  70.656 31.669 70.872 32.629 ;
     RECT  55.392 32.629 70.872 32.915 ;
     RECT  52.896 31.477 53.832 32.963 ;
     RECT  48.672 32.581 49.176 33.059 ;
     RECT  10.704 32.003 13.512 33.107 ;
     RECT  70.656 32.915 70.872 33.107 ;
     RECT  52.944 32.963 53.832 33.347 ;
     RECT  55.392 32.915 69.336 33.349 ;
     RECT  55.296 33.349 69.336 33.541 ;
     RECT  48.672 33.059 49.032 33.683 ;
     RECT  70.656 33.107 70.728 33.925 ;
     RECT  55.2 33.541 69.336 33.973 ;
     RECT  70.368 33.925 70.728 33.973 ;
     RECT  55.2 33.973 70.728 34.165 ;
     RECT  55.008 34.165 70.776 34.403 ;
     RECT  55.008 34.403 62.232 34.739 ;
     RECT  50.208 32.437 51.816 34.835 ;
     RECT  74.448 30.997 74.472 35.029 ;
     RECT  74.448 35.029 75.24 35.219 ;
     RECT  48.672 33.683 48.696 35.363 ;
     RECT  63.504 34.403 70.776 35.555 ;
     RECT  83.4 31.091 83.712 35.605 ;
     RECT  49.008 35.605 49.032 35.747 ;
     RECT  55.008 34.739 55.416 35.749 ;
     RECT  56.4 34.739 62.232 35.749 ;
     RECT  83.28 35.605 83.712 35.795 ;
     RECT  54.816 35.749 62.232 35.891 ;
     RECT  54.816 35.891 55.32 35.939 ;
     RECT  63.504 35.555 70.536 35.987 ;
     RECT  50.208 34.835 51.432 36.037 ;
     RECT  86.16 35.893 86.184 36.083 ;
     RECT  58.416 35.891 62.232 36.179 ;
     RECT  50.208 36.037 51.48 36.275 ;
     RECT  58.416 36.179 59.112 36.275 ;
     RECT  72.6 30.707 72.912 36.325 ;
     RECT  53.328 33.347 53.832 36.421 ;
     RECT  54.816 35.939 55.032 36.421 ;
     RECT  53.328 36.421 55.032 36.515 ;
     RECT  63.504 35.987 70.056 36.515 ;
     RECT  18.6 30.227 18.912 36.949 ;
     RECT  18.6 36.949 19.128 36.997 ;
     RECT  74.448 35.219 74.472 36.997 ;
     RECT  53.328 36.515 54.84 37.091 ;
     RECT  74.448 36.997 75.48 37.093 ;
     RECT  83.4 35.795 83.712 37.093 ;
     RECT  51 36.275 51.48 37.139 ;
     RECT  74.112 37.093 75.48 37.139 ;
     RECT  56.4 35.891 57.384 37.235 ;
     RECT  83.28 37.093 83.712 37.283 ;
     RECT  53.808 37.091 54.84 37.427 ;
     RECT  72.048 36.325 72.912 37.475 ;
     RECT  60.48 36.179 62.232 37.477 ;
     RECT  63.504 36.515 69.336 37.571 ;
     RECT  13.2 33.107 13.512 37.573 ;
     RECT  17.808 36.997 19.128 37.573 ;
     RECT  20.496 36.997 20.52 37.573 ;
     RECT  60.48 37.477 62.28 37.573 ;
     RECT  74.112 37.139 74.136 37.619 ;
     RECT  56.4 37.235 56.712 37.621 ;
     RECT  67.2 37.571 69.336 37.621 ;
     RECT  7.8 29.699 8.112 37.861 ;
     RECT  9.408 29.699 9.624 37.861 ;
     RECT  10.704 33.107 12.024 37.861 ;
     RECT  13.2 37.573 14.184 37.861 ;
     RECT  10.704 37.861 14.184 37.907 ;
     RECT  55.632 37.621 56.712 37.907 ;
     RECT  16.944 37.573 20.664 38.005 ;
     RECT  45.6 31.955 45.912 38.101 ;
     RECT  51 37.139 51.312 38.101 ;
     RECT  16.08 38.005 20.664 38.149 ;
     RECT  63.504 37.571 66.12 38.339 ;
     RECT  15.6 38.149 20.664 38.581 ;
     RECT  21.744 38.437 21.768 38.581 ;
     RECT  72.6 37.475 72.912 38.677 ;
     RECT  78 21.395 78.312 38.677 ;
     RECT  49.44 37.093 49.464 38.723 ;
     RECT  45.072 38.101 45.912 38.771 ;
     RECT  42.96 28.453 42.984 38.819 ;
     RECT  63.504 38.339 64.584 38.819 ;
     RECT  75.456 37.139 75.48 38.819 ;
     RECT  67.2 37.621 69.672 38.869 ;
     RECT  77.472 38.677 78.312 38.915 ;
     RECT  50.496 38.101 51.312 38.963 ;
     RECT  65.664 38.339 66.12 38.963 ;
     RECT  56.304 37.907 56.712 39.013 ;
     RECT  12.528 37.907 14.184 39.251 ;
     RECT  56.304 39.013 56.808 39.539 ;
     RECT  67.2 38.869 70.2 39.589 ;
     RECT  15.6 38.581 21.768 39.637 ;
     RECT  65.664 38.963 65.976 39.731 ;
     RECT  67.2 39.589 70.68 39.731 ;
     RECT  7.8 37.861 9.624 39.923 ;
     RECT  63.504 38.819 64.2 40.021 ;
     RECT  72.48 38.677 72.912 40.211 ;
     RECT  59.088 36.275 59.112 40.259 ;
     RECT  53.808 37.427 53.832 40.355 ;
     RECT  45.6 38.771 45.912 40.453 ;
     RECT  60.48 37.573 62.328 40.499 ;
     RECT  75.408 39.109 75.432 40.499 ;
     RECT  15.408 39.637 21.912 40.981 ;
     RECT  61.248 40.499 62.328 40.981 ;
     RECT  63.504 40.021 64.68 40.981 ;
     RECT  65.904 39.731 65.976 40.981 ;
     RECT  13.2 39.251 14.184 41.029 ;
     RECT  67.2 39.731 70.104 41.171 ;
     RECT  48.192 38.917 48.216 41.365 ;
     RECT  58.896 40.309 58.92 41.411 ;
     RECT  61.248 40.981 65.976 41.413 ;
     RECT  67.2 41.171 69.432 41.413 ;
     RECT  7.8 39.923 9.432 41.651 ;
     RECT  10.704 37.907 11.064 41.651 ;
     RECT  45.6 40.453 46.296 41.651 ;
     RECT  47.472 41.365 48.216 41.651 ;
     RECT  55.296 40.405 55.32 41.651 ;
     RECT  61.248 41.413 69.432 41.651 ;
     RECT  2.4 29.603 2.712 41.701 ;
     RECT  56.4 39.539 56.808 41.795 ;
     RECT  61.248 41.651 65.928 41.987 ;
     RECT  7.8 41.651 8.808 42.227 ;
     RECT  48.192 41.651 48.216 42.227 ;
     RECT  64.656 41.987 65.928 42.227 ;
     RECT  64.8 42.227 65.928 42.275 ;
     RECT  83.4 37.283 83.712 42.277 ;
     RECT  56.4 41.795 56.712 42.469 ;
     RECT  52.416 41.749 52.44 42.709 ;
     RECT  61.248 41.987 63.24 42.709 ;
     RECT  66.912 41.651 69.432 42.709 ;
     RECT  11.76 42.181 11.784 42.757 ;
     RECT  15.408 40.981 22.44 42.803 ;
     RECT  2.4 41.701 2.904 42.805 ;
     RECT  11.28 42.757 11.784 43.093 ;
     RECT  12.864 41.029 14.184 43.093 ;
     RECT  56.304 42.469 56.712 43.093 ;
     RECT  10.992 43.093 11.784 43.141 ;
     RECT  12.816 43.093 14.184 43.141 ;
     RECT  52.32 42.709 52.44 43.141 ;
     RECT  56.016 43.093 56.712 43.141 ;
     RECT  45.6 41.651 45.912 43.285 ;
     RECT  49.968 43.141 49.992 43.285 ;
     RECT  51 38.963 51.312 43.285 ;
     RECT  52.32 43.141 53.4 43.285 ;
     RECT  56.016 43.141 56.856 43.285 ;
     RECT  61.104 42.709 63.24 43.285 ;
     RECT  49.968 43.285 53.496 43.573 ;
     RECT  55.824 43.285 57.864 43.573 ;
     RECT  59.808 43.285 59.832 43.573 ;
     RECT  60.864 43.285 63.24 43.573 ;
     RECT  83.28 42.277 83.712 43.667 ;
     RECT  45.6 43.285 46.008 43.669 ;
     RECT  49.968 43.573 57.864 43.669 ;
     RECT  10.992 43.141 14.184 43.717 ;
     RECT  44.928 43.669 46.152 43.765 ;
     RECT  59.808 43.573 63.816 43.813 ;
     RECT  44.736 43.765 46.152 43.861 ;
     RECT  49.44 43.669 57.864 43.861 ;
     RECT  59.664 43.813 63.816 43.861 ;
     RECT  64.8 42.275 65.64 43.861 ;
     RECT  59.568 43.861 65.64 44.101 ;
     RECT  44.688 43.861 46.152 44.197 ;
     RECT  49.248 43.861 57.864 44.197 ;
     RECT  58.992 44.101 65.64 44.197 ;
     RECT  66.912 42.709 69.528 44.197 ;
     RECT  49.2 44.197 57.864 44.389 ;
     RECT  58.992 44.197 69.528 44.389 ;
     RECT  2.4 42.805 3.432 44.437 ;
     RECT  10.32 43.717 14.184 44.437 ;
     RECT  2.256 44.437 3.432 44.483 ;
     RECT  15.408 42.803 22.152 44.483 ;
     RECT  49.2 44.389 69.528 44.483 ;
     RECT  7.8 42.227 8.112 44.965 ;
     RECT  9.264 44.437 14.184 44.965 ;
     RECT  2.256 44.483 2.712 45.013 ;
     RECT  44.4 44.197 46.152 45.013 ;
     RECT  49.2 44.483 69.48 45.013 ;
     RECT  7.8 44.965 14.184 45.059 ;
     RECT  15.408 44.483 22.056 45.059 ;
     RECT  43.632 45.013 46.248 45.061 ;
     RECT  43.632 45.061 46.344 45.109 ;
     RECT  15.408 45.059 21.288 45.301 ;
     RECT  43.632 45.109 46.44 45.301 ;
     RECT  47.568 45.013 69.48 45.301 ;
     RECT  2.16 45.013 2.712 45.369 ;
     RECT  7.8 45.059 13.992 45.369 ;
     RECT  24 23.171 24.312 45.369 ;
     RECT  29.4 28.211 29.712 45.369 ;
     RECT  34.8 2.151 35.112 45.369 ;
     RECT  40.2 2.151 40.512 45.369 ;
     RECT  72.6 40.211 72.912 45.369 ;
     RECT  78 38.915 78.312 45.369 ;
     RECT  83.4 43.667 83.712 45.369 ;
     RECT  2.16 45.369 2.52 45.383 ;
     RECT  7.8 45.369 7.92 45.383 ;
     RECT  24 45.369 24.12 45.383 ;
     RECT  29.4 45.369 29.52 45.383 ;
     RECT  34.8 45.369 34.92 45.383 ;
     RECT  40.2 45.369 40.32 45.383 ;
     RECT  72.6 45.369 72.72 45.383 ;
     RECT  78 45.369 78.12 45.383 ;
     RECT  83.4 45.369 83.52 45.383 ;
     RECT  43.632 45.301 69.48 46.741 ;
     RECT  2.16 45.383 2.472 47.436 ;
     RECT  2.184 47.436 2.256 47.504 ;
     RECT  2.28 47.436 2.352 47.504 ;
     RECT  2.376 47.436 2.448 47.504 ;
     RECT  9.072 45.369 13.992 47.436 ;
     RECT  9.096 47.436 9.168 47.504 ;
     RECT  9.192 47.436 9.264 47.504 ;
     RECT  9.288 47.436 9.36 47.504 ;
     RECT  9.384 47.436 9.456 47.504 ;
     RECT  9.48 47.436 9.552 47.504 ;
     RECT  9.576 47.436 9.648 47.504 ;
     RECT  9.672 47.436 9.744 47.504 ;
     RECT  9.768 47.436 9.84 47.504 ;
     RECT  9.864 47.436 9.936 47.504 ;
     RECT  9.96 47.436 10.032 47.504 ;
     RECT  10.056 47.436 10.128 47.504 ;
     RECT  10.152 47.436 10.224 47.504 ;
     RECT  10.248 47.436 10.32 47.504 ;
     RECT  10.344 47.436 10.416 47.504 ;
     RECT  10.44 47.436 10.512 47.504 ;
     RECT  10.536 47.436 10.608 47.504 ;
     RECT  10.632 47.436 10.704 47.504 ;
     RECT  10.728 47.436 10.8 47.504 ;
     RECT  10.824 47.436 10.896 47.504 ;
     RECT  10.92 47.436 10.992 47.504 ;
     RECT  11.016 47.436 11.088 47.504 ;
     RECT  11.112 47.436 11.184 47.504 ;
     RECT  11.208 47.436 11.28 47.504 ;
     RECT  11.304 47.436 11.376 47.504 ;
     RECT  11.4 47.436 11.472 47.504 ;
     RECT  11.496 47.436 11.568 47.504 ;
     RECT  11.592 47.436 11.664 47.504 ;
     RECT  11.688 47.436 11.76 47.504 ;
     RECT  11.784 47.436 11.856 47.504 ;
     RECT  11.88 47.436 11.952 47.504 ;
     RECT  11.976 47.436 12.048 47.504 ;
     RECT  12.072 47.436 12.144 47.504 ;
     RECT  12.168 47.436 12.24 47.504 ;
     RECT  12.264 47.436 12.336 47.504 ;
     RECT  12.36 47.436 12.432 47.504 ;
     RECT  12.456 47.436 12.528 47.504 ;
     RECT  12.552 47.436 12.624 47.504 ;
     RECT  12.648 47.436 12.72 47.504 ;
     RECT  12.744 47.436 12.816 47.504 ;
     RECT  12.84 47.436 12.912 47.504 ;
     RECT  12.936 47.436 13.008 47.504 ;
     RECT  13.032 47.436 13.104 47.504 ;
     RECT  13.128 47.436 13.2 47.504 ;
     RECT  13.224 47.436 13.296 47.504 ;
     RECT  13.32 47.436 13.392 47.504 ;
     RECT  13.416 47.436 13.488 47.504 ;
     RECT  13.512 47.436 13.584 47.504 ;
     RECT  13.608 47.436 13.68 47.504 ;
     RECT  13.704 47.436 13.776 47.504 ;
     RECT  13.8 47.436 13.872 47.504 ;
     RECT  13.896 47.436 13.968 47.504 ;
     RECT  15.216 45.301 21.288 47.436 ;
     RECT  15.24 47.436 15.312 47.504 ;
     RECT  15.336 47.436 15.408 47.504 ;
     RECT  15.432 47.436 15.504 47.504 ;
     RECT  15.528 47.436 15.6 47.504 ;
     RECT  15.624 47.436 15.696 47.504 ;
     RECT  15.72 47.436 15.792 47.504 ;
     RECT  15.816 47.436 15.888 47.504 ;
     RECT  15.912 47.436 15.984 47.504 ;
     RECT  16.008 47.436 16.08 47.504 ;
     RECT  16.104 47.436 16.176 47.504 ;
     RECT  16.2 47.436 16.272 47.504 ;
     RECT  16.296 47.436 16.368 47.504 ;
     RECT  16.392 47.436 16.464 47.504 ;
     RECT  16.488 47.436 16.56 47.504 ;
     RECT  16.584 47.436 16.656 47.504 ;
     RECT  16.68 47.436 16.752 47.504 ;
     RECT  16.776 47.436 16.848 47.504 ;
     RECT  16.872 47.436 16.944 47.504 ;
     RECT  16.968 47.436 17.04 47.504 ;
     RECT  17.064 47.436 17.136 47.504 ;
     RECT  17.16 47.436 17.232 47.504 ;
     RECT  17.256 47.436 17.328 47.504 ;
     RECT  17.352 47.436 17.424 47.504 ;
     RECT  17.448 47.436 17.52 47.504 ;
     RECT  17.544 47.436 17.616 47.504 ;
     RECT  17.64 47.436 17.712 47.504 ;
     RECT  17.736 47.436 17.808 47.504 ;
     RECT  17.832 47.436 17.904 47.504 ;
     RECT  17.928 47.436 18 47.504 ;
     RECT  18.024 47.436 18.096 47.504 ;
     RECT  18.12 47.436 18.192 47.504 ;
     RECT  18.216 47.436 18.288 47.504 ;
     RECT  18.312 47.436 18.384 47.504 ;
     RECT  18.408 47.436 18.48 47.504 ;
     RECT  18.504 47.436 18.576 47.504 ;
     RECT  18.6 47.436 18.672 47.504 ;
     RECT  18.696 47.436 18.768 47.504 ;
     RECT  18.792 47.436 18.864 47.504 ;
     RECT  18.888 47.436 18.96 47.504 ;
     RECT  18.984 47.436 19.056 47.504 ;
     RECT  19.08 47.436 19.152 47.504 ;
     RECT  19.176 47.436 19.248 47.504 ;
     RECT  19.272 47.436 19.344 47.504 ;
     RECT  19.368 47.436 19.44 47.504 ;
     RECT  19.464 47.436 19.536 47.504 ;
     RECT  19.56 47.436 19.632 47.504 ;
     RECT  19.656 47.436 19.728 47.504 ;
     RECT  19.752 47.436 19.824 47.504 ;
     RECT  19.848 47.436 19.92 47.504 ;
     RECT  19.944 47.436 20.016 47.504 ;
     RECT  20.04 47.436 20.112 47.504 ;
     RECT  20.136 47.436 20.208 47.504 ;
     RECT  20.232 47.436 20.304 47.504 ;
     RECT  20.328 47.436 20.4 47.504 ;
     RECT  20.424 47.436 20.496 47.504 ;
     RECT  20.52 47.436 20.592 47.504 ;
     RECT  20.616 47.436 20.688 47.504 ;
     RECT  20.712 47.436 20.784 47.504 ;
     RECT  20.808 47.436 20.88 47.504 ;
     RECT  20.904 47.436 20.976 47.504 ;
     RECT  21 47.436 21.072 47.504 ;
     RECT  21.096 47.436 21.168 47.504 ;
     RECT  21.192 47.436 21.264 47.504 ;
     RECT  43.44 46.741 69.48 47.436 ;
     RECT  43.464 47.436 43.536 47.504 ;
     RECT  43.56 47.436 43.632 47.504 ;
     RECT  43.656 47.436 43.728 47.504 ;
     RECT  43.752 47.436 43.824 47.504 ;
     RECT  43.848 47.436 43.92 47.504 ;
     RECT  43.944 47.436 44.016 47.504 ;
     RECT  44.04 47.436 44.112 47.504 ;
     RECT  44.136 47.436 44.208 47.504 ;
     RECT  44.232 47.436 44.304 47.504 ;
     RECT  44.328 47.436 44.4 47.504 ;
     RECT  44.424 47.436 44.496 47.504 ;
     RECT  44.52 47.436 44.592 47.504 ;
     RECT  44.616 47.436 44.688 47.504 ;
     RECT  44.712 47.436 44.784 47.504 ;
     RECT  44.808 47.436 44.88 47.504 ;
     RECT  44.904 47.436 44.976 47.504 ;
     RECT  45 47.436 45.072 47.504 ;
     RECT  45.096 47.436 45.168 47.504 ;
     RECT  45.192 47.436 45.264 47.504 ;
     RECT  45.288 47.436 45.36 47.504 ;
     RECT  45.384 47.436 45.456 47.504 ;
     RECT  45.48 47.436 45.552 47.504 ;
     RECT  45.576 47.436 45.648 47.504 ;
     RECT  45.672 47.436 45.744 47.504 ;
     RECT  45.768 47.436 45.84 47.504 ;
     RECT  45.864 47.436 45.936 47.504 ;
     RECT  45.96 47.436 46.032 47.504 ;
     RECT  46.056 47.436 46.128 47.504 ;
     RECT  46.152 47.436 46.224 47.504 ;
     RECT  46.248 47.436 46.32 47.504 ;
     RECT  46.344 47.436 46.416 47.504 ;
     RECT  46.44 47.436 47.28 47.504 ;
     RECT  47.304 47.436 47.376 47.504 ;
     RECT  47.4 47.436 47.472 47.504 ;
     RECT  47.496 47.436 47.568 47.504 ;
     RECT  47.592 47.436 47.664 47.504 ;
     RECT  47.688 47.436 47.76 47.504 ;
     RECT  47.784 47.436 47.856 47.504 ;
     RECT  47.88 47.436 47.952 47.504 ;
     RECT  47.976 47.436 48.048 47.504 ;
     RECT  48.072 47.436 48.144 47.504 ;
     RECT  48.168 47.436 48.24 47.504 ;
     RECT  48.264 47.436 48.336 47.504 ;
     RECT  48.36 47.436 48.432 47.504 ;
     RECT  48.456 47.436 48.528 47.504 ;
     RECT  48.552 47.436 48.624 47.504 ;
     RECT  48.648 47.436 48.72 47.504 ;
     RECT  48.744 47.436 48.816 47.504 ;
     RECT  48.84 47.436 48.912 47.504 ;
     RECT  48.936 47.436 49.008 47.504 ;
     RECT  49.032 47.436 49.104 47.504 ;
     RECT  49.128 47.436 49.2 47.504 ;
     RECT  49.224 47.436 49.296 47.504 ;
     RECT  49.32 47.436 49.392 47.504 ;
     RECT  49.416 47.436 49.488 47.504 ;
     RECT  49.512 47.436 49.584 47.504 ;
     RECT  49.608 47.436 49.68 47.504 ;
     RECT  49.704 47.436 49.776 47.504 ;
     RECT  49.8 47.436 49.872 47.504 ;
     RECT  49.896 47.436 49.968 47.504 ;
     RECT  49.992 47.436 50.064 47.504 ;
     RECT  50.088 47.436 50.16 47.504 ;
     RECT  50.184 47.436 50.256 47.504 ;
     RECT  50.28 47.436 50.352 47.504 ;
     RECT  50.376 47.436 50.448 47.504 ;
     RECT  50.472 47.436 50.544 47.504 ;
     RECT  50.568 47.436 50.64 47.504 ;
     RECT  50.664 47.436 50.736 47.504 ;
     RECT  50.76 47.436 50.832 47.504 ;
     RECT  50.856 47.436 50.928 47.504 ;
     RECT  50.952 47.436 51.024 47.504 ;
     RECT  51.048 47.436 51.12 47.504 ;
     RECT  51.144 47.436 51.216 47.504 ;
     RECT  51.24 47.436 51.312 47.504 ;
     RECT  51.336 47.436 51.408 47.504 ;
     RECT  51.432 47.436 51.504 47.504 ;
     RECT  51.528 47.436 51.6 47.504 ;
     RECT  51.624 47.436 51.696 47.504 ;
     RECT  51.72 47.436 51.792 47.504 ;
     RECT  51.816 47.436 51.888 47.504 ;
     RECT  51.912 47.436 51.984 47.504 ;
     RECT  52.008 47.436 52.08 47.504 ;
     RECT  52.104 47.436 52.176 47.504 ;
     RECT  52.2 47.436 52.272 47.504 ;
     RECT  52.296 47.436 52.368 47.504 ;
     RECT  52.392 47.436 52.464 47.504 ;
     RECT  52.488 47.436 52.56 47.504 ;
     RECT  52.584 47.436 52.656 47.504 ;
     RECT  52.68 47.436 52.752 47.504 ;
     RECT  52.776 47.436 52.848 47.504 ;
     RECT  52.872 47.436 52.944 47.504 ;
     RECT  52.968 47.436 53.04 47.504 ;
     RECT  53.064 47.436 53.136 47.504 ;
     RECT  53.16 47.436 53.232 47.504 ;
     RECT  53.256 47.436 53.328 47.504 ;
     RECT  53.352 47.436 53.424 47.504 ;
     RECT  53.448 47.436 53.52 47.504 ;
     RECT  53.544 47.436 53.616 47.504 ;
     RECT  53.64 47.436 53.712 47.504 ;
     RECT  53.736 47.436 53.808 47.504 ;
     RECT  53.832 47.436 53.904 47.504 ;
     RECT  53.928 47.436 54 47.504 ;
     RECT  54.024 47.436 54.096 47.504 ;
     RECT  54.12 47.436 54.192 47.504 ;
     RECT  54.216 47.436 54.288 47.504 ;
     RECT  54.312 47.436 54.384 47.504 ;
     RECT  54.408 47.436 54.48 47.504 ;
     RECT  54.504 47.436 54.576 47.504 ;
     RECT  54.6 47.436 54.672 47.504 ;
     RECT  54.696 47.436 54.768 47.504 ;
     RECT  54.792 47.436 54.864 47.504 ;
     RECT  54.888 47.436 54.96 47.504 ;
     RECT  54.984 47.436 55.056 47.504 ;
     RECT  55.08 47.436 55.152 47.504 ;
     RECT  55.176 47.436 55.248 47.504 ;
     RECT  55.272 47.436 55.344 47.504 ;
     RECT  55.368 47.436 55.44 47.504 ;
     RECT  55.464 47.436 55.536 47.504 ;
     RECT  55.56 47.436 55.632 47.504 ;
     RECT  55.656 47.436 55.728 47.504 ;
     RECT  55.752 47.436 55.824 47.504 ;
     RECT  55.848 47.436 55.92 47.504 ;
     RECT  55.944 47.436 56.016 47.504 ;
     RECT  56.04 47.436 56.112 47.504 ;
     RECT  56.136 47.436 56.208 47.504 ;
     RECT  56.232 47.436 56.304 47.504 ;
     RECT  56.328 47.436 56.4 47.504 ;
     RECT  56.424 47.436 56.496 47.504 ;
     RECT  56.52 47.436 56.592 47.504 ;
     RECT  56.616 47.436 56.688 47.504 ;
     RECT  56.712 47.436 56.784 47.504 ;
     RECT  56.808 47.436 56.88 47.504 ;
     RECT  56.904 47.436 56.976 47.504 ;
     RECT  57 47.436 57.072 47.504 ;
     RECT  57.096 47.436 57.168 47.504 ;
     RECT  57.192 47.436 57.264 47.504 ;
     RECT  57.288 47.436 57.36 47.504 ;
     RECT  57.384 47.436 57.456 47.504 ;
     RECT  57.48 47.436 57.552 47.504 ;
     RECT  57.576 47.436 57.648 47.504 ;
     RECT  57.672 47.436 57.744 47.504 ;
     RECT  57.768 47.436 57.84 47.504 ;
     RECT  57.864 47.436 57.936 47.504 ;
     RECT  57.96 47.436 58.032 47.504 ;
     RECT  58.056 47.436 58.128 47.504 ;
     RECT  58.152 47.436 58.224 47.504 ;
     RECT  58.248 47.436 58.32 47.504 ;
     RECT  58.344 47.436 58.416 47.504 ;
     RECT  58.44 47.436 58.512 47.504 ;
     RECT  58.536 47.436 58.608 47.504 ;
     RECT  58.632 47.436 58.704 47.504 ;
     RECT  58.728 47.436 58.8 47.504 ;
     RECT  58.824 47.436 58.896 47.504 ;
     RECT  58.92 47.436 58.992 47.504 ;
     RECT  59.016 47.436 59.088 47.504 ;
     RECT  59.112 47.436 59.184 47.504 ;
     RECT  59.208 47.436 59.28 47.504 ;
     RECT  59.304 47.436 59.376 47.504 ;
     RECT  59.4 47.436 59.472 47.504 ;
     RECT  59.496 47.436 59.568 47.504 ;
     RECT  59.592 47.436 59.664 47.504 ;
     RECT  59.688 47.436 59.76 47.504 ;
     RECT  59.784 47.436 59.856 47.504 ;
     RECT  59.88 47.436 59.952 47.504 ;
     RECT  59.976 47.436 60.048 47.504 ;
     RECT  60.072 47.436 60.144 47.504 ;
     RECT  60.168 47.436 60.24 47.504 ;
     RECT  60.264 47.436 60.336 47.504 ;
     RECT  60.36 47.436 60.432 47.504 ;
     RECT  60.456 47.436 60.528 47.504 ;
     RECT  60.552 47.436 60.624 47.504 ;
     RECT  60.648 47.436 60.72 47.504 ;
     RECT  60.744 47.436 60.816 47.504 ;
     RECT  60.84 47.436 60.912 47.504 ;
     RECT  60.936 47.436 61.008 47.504 ;
     RECT  61.032 47.436 61.104 47.504 ;
     RECT  61.128 47.436 61.2 47.504 ;
     RECT  61.224 47.436 61.296 47.504 ;
     RECT  61.32 47.436 61.392 47.504 ;
     RECT  61.416 47.436 61.488 47.504 ;
     RECT  61.512 47.436 61.584 47.504 ;
     RECT  61.608 47.436 61.68 47.504 ;
     RECT  61.704 47.436 61.776 47.504 ;
     RECT  61.8 47.436 61.872 47.504 ;
     RECT  61.896 47.436 61.968 47.504 ;
     RECT  61.992 47.436 62.064 47.504 ;
     RECT  62.088 47.436 62.16 47.504 ;
     RECT  62.184 47.436 62.256 47.504 ;
     RECT  62.28 47.436 62.352 47.504 ;
     RECT  62.376 47.436 62.448 47.504 ;
     RECT  62.472 47.436 62.544 47.504 ;
     RECT  62.568 47.436 62.64 47.504 ;
     RECT  62.664 47.436 62.736 47.504 ;
     RECT  62.76 47.436 62.832 47.504 ;
     RECT  62.856 47.436 62.928 47.504 ;
     RECT  62.952 47.436 63.024 47.504 ;
     RECT  63.048 47.436 63.12 47.504 ;
     RECT  63.144 47.436 63.216 47.504 ;
     RECT  63.24 47.436 63.312 47.504 ;
     RECT  63.336 47.436 63.408 47.504 ;
     RECT  63.432 47.436 63.504 47.504 ;
     RECT  63.528 47.436 63.6 47.504 ;
     RECT  63.624 47.436 63.696 47.504 ;
     RECT  63.72 47.436 63.792 47.504 ;
     RECT  63.816 47.436 63.888 47.504 ;
     RECT  63.912 47.436 63.984 47.504 ;
     RECT  64.008 47.436 64.08 47.504 ;
     RECT  64.104 47.436 64.176 47.504 ;
     RECT  64.2 47.436 64.272 47.504 ;
     RECT  64.296 47.436 64.368 47.504 ;
     RECT  64.392 47.436 64.464 47.504 ;
     RECT  64.488 47.436 64.56 47.504 ;
     RECT  64.584 47.436 64.656 47.504 ;
     RECT  64.68 47.436 64.752 47.504 ;
     RECT  64.776 47.436 64.848 47.504 ;
     RECT  64.872 47.436 64.944 47.504 ;
     RECT  64.968 47.436 65.04 47.504 ;
     RECT  65.064 47.436 65.136 47.504 ;
     RECT  65.16 47.436 65.232 47.504 ;
     RECT  65.256 47.436 65.328 47.504 ;
     RECT  65.352 47.436 65.424 47.504 ;
     RECT  65.448 47.436 65.52 47.504 ;
     RECT  65.544 47.436 65.616 47.504 ;
     RECT  65.64 47.436 66.48 47.504 ;
     RECT  66.504 47.436 66.576 47.504 ;
     RECT  66.6 47.436 66.672 47.504 ;
     RECT  66.696 47.436 66.768 47.504 ;
     RECT  66.792 47.436 66.864 47.504 ;
     RECT  66.888 47.436 66.96 47.504 ;
     RECT  66.984 47.436 67.056 47.504 ;
     RECT  67.08 47.436 67.152 47.504 ;
     RECT  67.176 47.436 67.248 47.504 ;
     RECT  67.272 47.436 67.344 47.504 ;
     RECT  67.368 47.436 67.44 47.504 ;
     RECT  67.464 47.436 67.536 47.504 ;
     RECT  67.56 47.436 67.632 47.504 ;
     RECT  67.656 47.436 67.728 47.504 ;
     RECT  67.752 47.436 67.824 47.504 ;
     RECT  67.848 47.436 67.92 47.504 ;
     RECT  67.944 47.436 68.016 47.504 ;
     RECT  68.04 47.436 68.112 47.504 ;
     RECT  68.136 47.436 68.208 47.504 ;
     RECT  68.232 47.436 68.304 47.504 ;
     RECT  68.328 47.436 68.4 47.504 ;
     RECT  68.424 47.436 68.496 47.504 ;
     RECT  68.52 47.436 68.592 47.504 ;
     RECT  68.616 47.436 68.688 47.504 ;
     RECT  68.712 47.436 68.784 47.504 ;
     RECT  68.808 47.436 68.88 47.504 ;
     RECT  68.904 47.436 68.976 47.504 ;
     RECT  69 47.436 69.072 47.504 ;
     RECT  69.096 47.436 69.168 47.504 ;
     RECT  69.192 47.436 69.264 47.504 ;
     RECT  69.288 47.436 69.36 47.504 ;
     RECT  69.384 47.436 69.456 47.504 ;
     RECT  7.992 0.016 9.12 0.132 ;
     RECT  7.944 0.132 9.168 0.227 ;
     RECT  7.848 0.227 9.168 0.275 ;
     RECT  7.704 0.275 9.168 1.763 ;
     RECT  7.704 1.763 9.456 2.137 ;
     RECT  46.44 1.763 47.472 1.811 ;
     RECT  65.544 1.763 66.576 1.811 ;
     RECT  46.344 1.811 47.472 1.859 ;
     RECT  65.544 1.811 66.96 2.915 ;
     RECT  46.152 1.859 47.472 2.339 ;
     RECT  11.976 1.955 12.168 2.137 ;
     RECT  7.92 2.137 9.456 2.151 ;
     RECT  11.976 2.137 13.2 2.435 ;
     RECT  8.112 2.151 9.456 4.019 ;
     RECT  22.728 2.291 24 2.963 ;
     RECT  2.712 2.341 3.984 2.915 ;
     RECT  11.88 2.435 13.2 2.627 ;
     RECT  4.008 2.869 5.136 2.915 ;
     RECT  48.072 2.915 49.488 3.443 ;
     RECT  65.448 2.915 66.96 3.059 ;
     RECT  22.632 2.963 24 3.491 ;
     RECT  21.48 3.443 22.608 3.491 ;
     RECT  21.48 3.491 22.344 4.019 ;
     RECT  57.384 3.539 58.464 4.019 ;
     RECT  24.312 3.733 25.344 4.931 ;
     RECT  18.912 4.019 19.92 4.163 ;
     RECT  22.32 4.019 22.344 4.645 ;
     RECT  57.384 4.019 58.896 5.795 ;
     RECT  60.408 4.019 61.68 5.557 ;
     RECT  65.064 4.019 65.208 5.269 ;
     RECT  18.912 4.163 20.016 4.595 ;
     RECT  63.816 4.163 65.04 5.173 ;
     RECT  18.912 4.595 20.496 5.795 ;
     RECT  59.016 4.643 60.192 5.843 ;
     RECT  62.112 5.171 63.168 6.563 ;
     RECT  63.816 5.173 64.992 5.221 ;
     RECT  60.408 5.557 61.536 5.843 ;
     RECT  45.912 5.747 46.896 6.275 ;
     RECT  18.912 5.795 19.944 6.085 ;
     RECT  59.016 5.843 59.832 6.661 ;
     RECT  8.112 6.085 9.552 7.475 ;
     RECT  18.912 6.085 19.92 19.333 ;
     RECT  63.816 6.323 65.184 8.435 ;
     RECT  62.112 6.563 63.792 7.957 ;
     RECT  51.432 6.899 52.56 6.947 ;
     RECT  51.432 6.947 52.896 8.051 ;
     RECT  54.312 7.523 55.584 8.195 ;
     RECT  65.544 7.619 65.64 8.005 ;
     RECT  62.664 7.957 63.792 8.435 ;
     RECT  65.544 8.005 67.056 18.181 ;
     RECT  55.392 8.195 55.584 8.485 ;
     RECT  65.88 18.181 67.056 18.757 ;
     RECT  62.664 18.709 63.888 19.861 ;
     RECT  65.976 18.757 67.056 20.149 ;
     RECT  17.448 19.621 18.6 20.723 ;
     RECT  69.528 19.813 70.848 21.253 ;
     RECT  0.144 19.859 0.168 20.869 ;
     RECT  8.112 20.341 9.552 20.965 ;
     RECT  9.624 20.819 9.96 22.165 ;
     RECT  8.112 20.965 9.168 21.251 ;
     RECT  8.112 21.251 9.408 24.757 ;
     RECT  69.528 21.253 70.704 23.413 ;
     RECT  77.016 21.395 78 23.363 ;
     RECT  12.024 21.685 13.2 22.021 ;
     RECT  6.552 22.069 7.632 22.835 ;
     RECT  9.624 22.165 10.704 22.357 ;
     RECT  6.552 22.835 7.8 23.315 ;
     RECT  9.576 22.979 10.704 25.285 ;
     RECT  12.912 22.979 13.2 24.373 ;
     RECT  72.912 23.125 74.16 25.715 ;
     RECT  7.68 23.315 7.8 24.469 ;
     RECT  13.512 23.317 15.024 23.987 ;
     RECT  76.92 23.363 78 23.939 ;
     RECT  69.624 23.413 70.704 23.749 ;
     RECT  76.488 23.939 78 25.285 ;
     RECT  75.192 24.515 76.464 26.243 ;
     RECT  69.384 24.707 70.704 25.283 ;
     RECT  8.112 24.757 9.36 24.901 ;
     RECT  8.112 24.901 9.12 24.949 ;
     RECT  69.048 25.283 70.704 26.293 ;
     RECT  9.624 25.285 10.704 26.197 ;
     RECT  76.776 25.285 78 26.197 ;
     RECT  11.4 25.333 12.912 25.765 ;
     RECT  8.112 25.619 9.408 37.861 ;
     RECT  72.912 25.715 73.032 26.005 ;
     RECT  11.4 25.765 12.576 25.907 ;
     RECT  11.4 25.907 12.912 26.051 ;
     RECT  74.688 25.955 75.168 27.157 ;
     RECT  11.304 26.051 12.912 26.339 ;
     RECT  76.92 26.197 78 26.965 ;
     RECT  72.912 26.243 73.032 27.301 ;
     RECT  75.192 26.243 76.752 27.203 ;
     RECT  69.192 26.293 70.704 26.533 ;
     RECT  11.064 26.339 12.912 27.061 ;
     RECT  69.336 26.533 70.704 27.395 ;
     RECT  2.712 26.917 3.936 29.461 ;
     RECT  76.968 26.965 78 28.019 ;
     RECT  11.064 27.061 12.384 27.877 ;
     RECT  76.656 27.203 76.752 27.733 ;
     RECT  72.912 27.301 74.064 28.019 ;
     RECT  69.336 27.395 70.752 28.547 ;
     RECT  76.656 28.019 76.752 29.029 ;
     RECT  76.824 28.019 78 29.891 ;
     RECT  11.064 29.123 12.384 31.525 ;
     RECT  2.808 29.461 3.936 29.603 ;
     RECT  2.712 29.603 3.936 30.851 ;
     RECT  45.912 29.605 47.088 30.949 ;
     RECT  9.624 29.699 10.704 39.923 ;
     RECT  76.776 29.891 78 30.995 ;
     RECT  51.816 30.037 53.28 31.333 ;
     RECT  48.696 30.947 49.08 32.437 ;
     RECT  57.192 31.187 58.176 32.293 ;
     RECT  69.336 31.237 70.848 31.669 ;
     RECT  51.816 31.333 53.088 31.477 ;
     RECT  51.816 31.477 52.896 32.963 ;
     RECT  11.064 31.525 12.24 31.573 ;
     RECT  69.336 31.669 70.656 32.629 ;
     RECT  45.912 31.955 47.088 32.147 ;
     RECT  48.696 32.437 50.208 32.581 ;
     RECT  49.176 32.581 50.208 33.059 ;
     RECT  69.336 32.915 70.656 33.925 ;
     RECT  51.816 32.963 52.944 33.347 ;
     RECT  49.032 33.059 50.208 33.683 ;
     RECT  12.024 33.107 13.2 37.861 ;
     RECT  70.728 33.107 70.776 34.165 ;
     RECT  51.816 33.347 53.328 34.835 ;
     RECT  53.832 33.349 55.296 33.541 ;
     RECT  53.832 33.541 55.2 34.165 ;
     RECT  48.696 33.683 50.208 35.363 ;
     RECT  69.336 33.925 70.368 33.973 ;
     RECT  53.832 34.165 55.008 35.749 ;
     RECT  62.232 34.403 63.504 37.477 ;
     RECT  55.416 34.739 56.4 35.749 ;
     RECT  51.432 34.835 51.48 36.037 ;
     RECT  49.008 35.363 50.208 35.605 ;
     RECT  49.032 35.605 50.208 35.747 ;
     RECT  49.44 35.747 50.208 36.275 ;
     RECT  53.832 35.749 54.816 36.421 ;
     RECT  83.28 35.795 83.4 37.093 ;
     RECT  55.32 35.891 56.4 35.939 ;
     RECT  57.384 35.891 58.416 36.275 ;
     RECT  55.032 35.939 56.4 36.515 ;
     RECT  59.112 36.179 60.48 40.259 ;
     RECT  49.44 36.275 49.464 37.093 ;
     RECT  54.84 36.515 56.4 37.427 ;
     RECT  69.336 36.515 69.672 37.621 ;
     RECT  19.128 36.997 20.496 37.573 ;
     RECT  72.912 37.093 74.112 37.619 ;
     RECT  74.136 37.139 75.456 37.619 ;
     RECT  55.632 37.427 56.4 37.621 ;
     RECT  72.48 37.475 72.6 38.677 ;
     RECT  62.28 37.477 63.504 37.573 ;
     RECT  66.12 37.571 67.2 38.963 ;
     RECT  62.328 37.573 63.504 40.981 ;
     RECT  75.408 37.619 75.456 38.819 ;
     RECT  11.064 37.907 12.528 39.251 ;
     RECT  49.464 38.101 50.496 38.723 ;
     RECT  14.184 38.149 15.6 39.637 ;
     RECT  64.584 38.339 65.664 38.819 ;
     RECT  20.664 38.437 21.744 38.581 ;
     RECT  64.2 38.819 65.664 39.731 ;
     RECT  75.408 38.819 75.432 39.109 ;
     RECT  65.976 38.963 67.2 41.413 ;
     RECT  56.304 39.539 56.4 40.405 ;
     RECT  14.184 39.637 15.408 45.059 ;
     RECT  64.2 39.731 65.904 40.021 ;
     RECT  9.432 39.923 10.704 41.651 ;
     RECT  64.68 40.021 65.904 40.981 ;
     RECT  55.32 40.405 56.4 41.651 ;
     RECT  46.296 41.365 47.472 41.651 ;
     RECT  10.992 41.651 11.064 42.181 ;
     RECT  56.016 41.651 56.4 42.469 ;
     RECT  65.928 41.651 66.912 42.275 ;
     RECT  51.312 41.749 52.416 42.709 ;
     RECT  56.712 41.795 56.808 43.141 ;
     RECT  63.24 41.987 64.656 42.227 ;
     RECT  10.992 42.181 11.76 42.757 ;
     RECT  11.784 42.181 12.864 43.093 ;
     RECT  63.24 42.227 64.8 43.573 ;
     RECT  65.64 42.275 66.912 44.197 ;
     RECT  56.016 42.469 56.304 43.093 ;
     RECT  51.312 42.709 52.32 43.285 ;
     RECT  10.992 42.757 11.28 43.093 ;
     RECT  11.784 43.093 12.816 43.141 ;
     RECT  49.992 43.141 51 43.285 ;
     RECT  59.832 43.285 60.864 43.573 ;
     RECT  63.816 43.573 64.8 43.861 ;
     RECT  57.864 44.101 58.992 44.389 ;
     RECT  8.112 44.437 9.264 44.965 ;
     RECT  46.248 45.013 47.568 45.061 ;
     RECT  13.992 45.059 15.408 45.301 ;
     RECT  46.344 45.061 47.568 45.109 ;
     RECT  46.44 45.109 47.568 45.301 ;
     RECT  13.992 45.301 15.216 47.388 ;
     RECT  7.92 45.369 9.072 45.383 ;
     RECT  14.04 47.388 15.168 47.504 ;
  END
END qkd_astk_er_tap_st
END LIBRARY
